VERSION 5.8 ;
BUSBITCHARS "[]" ;
DIVIDERCHAR "/" ;
UNITS
    DATABASE MICRONS 1000 ;
END UNITS

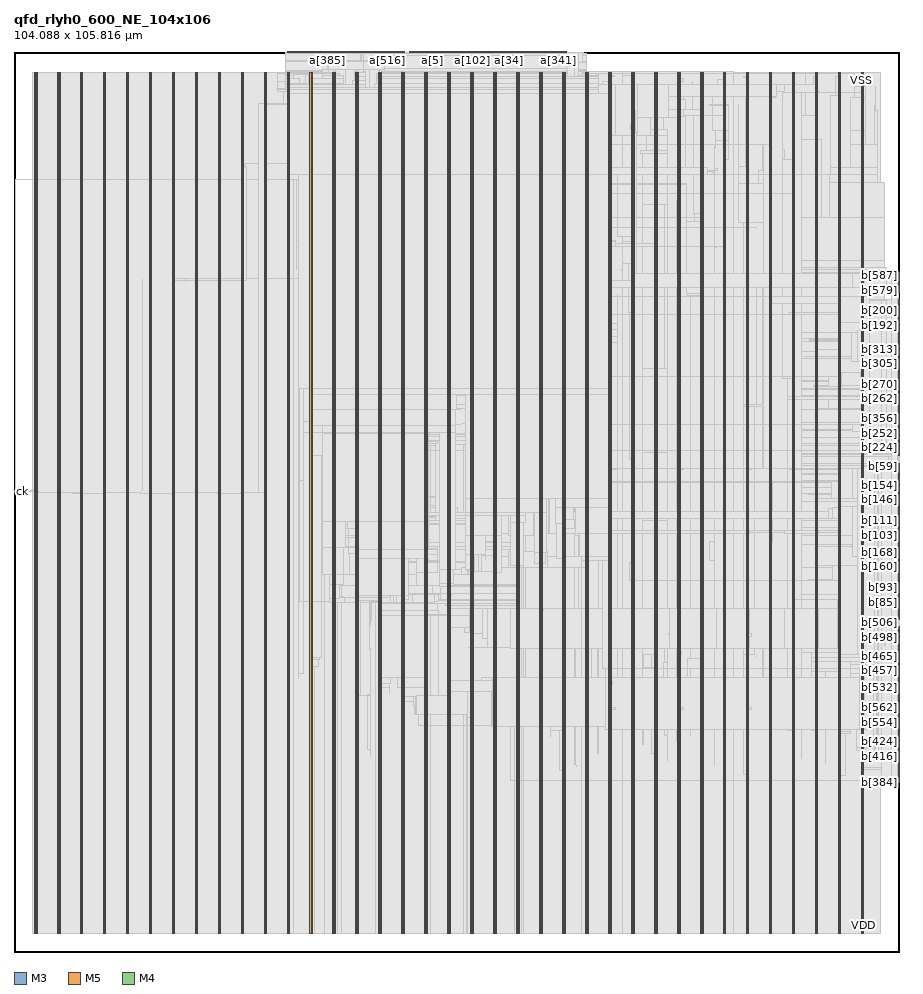
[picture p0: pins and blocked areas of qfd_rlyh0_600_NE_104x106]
MACRO qfd_rlyh0_600_NE_104x106
  FOREIGN qfd_rlyh0_600_NE_104x106 0 0 ;
  CLASS BLOCK ;
  SIZE 104.088 BY 105.816 ;
  PIN a[0]
    DIRECTION INPUT ;
    USE SIGNAL ;
    PORT
      LAYER M3 ;
        RECT  48.852 105.779 48.87 105.816 ;
    END
  END a[0]
  PIN a[100]
    DIRECTION INPUT ;
    USE SIGNAL ;
    PORT
      LAYER M3 ;
        RECT  53.748 105.779 53.766 105.816 ;
    END
  END a[100]
  PIN a[101]
    DIRECTION INPUT ;
    USE SIGNAL ;
    PORT
      LAYER M3 ;
        RECT  53.82 105.779 53.838 105.816 ;
    END
  END a[101]
  PIN a[102]
    DIRECTION INPUT ;
    USE SIGNAL ;
    PORT
      LAYER M3 ;
        RECT  53.892 105.779 53.91 105.816 ;
    END
  END a[102]
  PIN a[103]
    DIRECTION INPUT ;
    USE SIGNAL ;
    PORT
      LAYER M3 ;
        RECT  53.964 105.779 53.982 105.816 ;
    END
  END a[103]
  PIN a[104]
    DIRECTION INPUT ;
    USE SIGNAL ;
    PORT
      LAYER M3 ;
        RECT  54.036 105.779 54.054 105.816 ;
    END
  END a[104]
  PIN a[105]
    DIRECTION INPUT ;
    USE SIGNAL ;
    PORT
      LAYER M3 ;
        RECT  54.108 105.779 54.126 105.816 ;
    END
  END a[105]
  PIN a[106]
    DIRECTION INPUT ;
    USE SIGNAL ;
    PORT
      LAYER M3 ;
        RECT  54.18 105.779 54.198 105.816 ;
    END
  END a[106]
  PIN a[107]
    DIRECTION INPUT ;
    USE SIGNAL ;
    PORT
      LAYER M3 ;
        RECT  54.252 105.779 54.27 105.816 ;
    END
  END a[107]
  PIN a[108]
    DIRECTION INPUT ;
    USE SIGNAL ;
    PORT
      LAYER M3 ;
        RECT  54.324 105.779 54.342 105.816 ;
    END
  END a[108]
  PIN a[109]
    DIRECTION INPUT ;
    USE SIGNAL ;
    PORT
      LAYER M3 ;
        RECT  54.396 105.779 54.414 105.816 ;
    END
  END a[109]
  PIN a[10]
    DIRECTION INPUT ;
    USE SIGNAL ;
    PORT
      LAYER M3 ;
        RECT  49.572 105.779 49.59 105.816 ;
    END
  END a[10]
  PIN a[110]
    DIRECTION INPUT ;
    USE SIGNAL ;
    PORT
      LAYER M3 ;
        RECT  54.468 105.779 54.486 105.816 ;
    END
  END a[110]
  PIN a[111]
    DIRECTION INPUT ;
    USE SIGNAL ;
    PORT
      LAYER M3 ;
        RECT  54.54 105.779 54.558 105.816 ;
    END
  END a[111]
  PIN a[112]
    DIRECTION INPUT ;
    USE SIGNAL ;
    PORT
      LAYER M3 ;
        RECT  54.612 105.779 54.63 105.816 ;
    END
  END a[112]
  PIN a[113]
    DIRECTION INPUT ;
    USE SIGNAL ;
    PORT
      LAYER M3 ;
        RECT  54.684 105.779 54.702 105.816 ;
    END
  END a[113]
  PIN a[114]
    DIRECTION INPUT ;
    USE SIGNAL ;
    PORT
      LAYER M3 ;
        RECT  54.756 105.779 54.774 105.816 ;
    END
  END a[114]
  PIN a[115]
    DIRECTION INPUT ;
    USE SIGNAL ;
    PORT
      LAYER M3 ;
        RECT  54.828 105.779 54.846 105.816 ;
    END
  END a[115]
  PIN a[116]
    DIRECTION INPUT ;
    USE SIGNAL ;
    PORT
      LAYER M3 ;
        RECT  54.9 105.779 54.918 105.816 ;
    END
  END a[116]
  PIN a[117]
    DIRECTION INPUT ;
    USE SIGNAL ;
    PORT
      LAYER M3 ;
        RECT  54.972 105.779 54.99 105.816 ;
    END
  END a[117]
  PIN a[118]
    DIRECTION INPUT ;
    USE SIGNAL ;
    PORT
      LAYER M3 ;
        RECT  55.044 105.779 55.062 105.816 ;
    END
  END a[118]
  PIN a[119]
    DIRECTION INPUT ;
    USE SIGNAL ;
    PORT
      LAYER M3 ;
        RECT  55.116 105.779 55.134 105.816 ;
    END
  END a[119]
  PIN a[11]
    DIRECTION INPUT ;
    USE SIGNAL ;
    PORT
      LAYER M3 ;
        RECT  49.644 105.779 49.662 105.816 ;
    END
  END a[11]
  PIN a[120]
    DIRECTION INPUT ;
    USE SIGNAL ;
    PORT
      LAYER M3 ;
        RECT  55.188 105.779 55.206 105.816 ;
    END
  END a[120]
  PIN a[121]
    DIRECTION INPUT ;
    USE SIGNAL ;
    PORT
      LAYER M3 ;
        RECT  55.26 105.779 55.278 105.816 ;
    END
  END a[121]
  PIN a[122]
    DIRECTION INPUT ;
    USE SIGNAL ;
    PORT
      LAYER M3 ;
        RECT  55.332 105.779 55.35 105.816 ;
    END
  END a[122]
  PIN a[123]
    DIRECTION INPUT ;
    USE SIGNAL ;
    PORT
      LAYER M3 ;
        RECT  55.404 105.779 55.422 105.816 ;
    END
  END a[123]
  PIN a[124]
    DIRECTION INPUT ;
    USE SIGNAL ;
    PORT
      LAYER M3 ;
        RECT  55.476 105.779 55.494 105.816 ;
    END
  END a[124]
  PIN a[125]
    DIRECTION INPUT ;
    USE SIGNAL ;
    PORT
      LAYER M3 ;
        RECT  55.548 105.779 55.566 105.816 ;
    END
  END a[125]
  PIN a[126]
    DIRECTION INPUT ;
    USE SIGNAL ;
    PORT
      LAYER M3 ;
        RECT  55.62 105.779 55.638 105.816 ;
    END
  END a[126]
  PIN a[127]
    DIRECTION INPUT ;
    USE SIGNAL ;
    PORT
      LAYER M3 ;
        RECT  55.692 105.779 55.71 105.816 ;
    END
  END a[127]
  PIN a[128]
    DIRECTION INPUT ;
    USE SIGNAL ;
    PORT
      LAYER M3 ;
        RECT  55.764 105.779 55.782 105.816 ;
    END
  END a[128]
  PIN a[129]
    DIRECTION INPUT ;
    USE SIGNAL ;
    PORT
      LAYER M3 ;
        RECT  55.836 105.779 55.854 105.816 ;
    END
  END a[129]
  PIN a[12]
    DIRECTION INPUT ;
    USE SIGNAL ;
    PORT
      LAYER M3 ;
        RECT  49.716 105.779 49.734 105.816 ;
    END
  END a[12]
  PIN a[130]
    DIRECTION INPUT ;
    USE SIGNAL ;
    PORT
      LAYER M3 ;
        RECT  55.908 105.779 55.926 105.816 ;
    END
  END a[130]
  PIN a[131]
    DIRECTION INPUT ;
    USE SIGNAL ;
    PORT
      LAYER M3 ;
        RECT  55.98 105.779 55.998 105.816 ;
    END
  END a[131]
  PIN a[132]
    DIRECTION INPUT ;
    USE SIGNAL ;
    PORT
      LAYER M3 ;
        RECT  56.052 105.779 56.07 105.816 ;
    END
  END a[132]
  PIN a[133]
    DIRECTION INPUT ;
    USE SIGNAL ;
    PORT
      LAYER M3 ;
        RECT  56.124 105.779 56.142 105.816 ;
    END
  END a[133]
  PIN a[134]
    DIRECTION INPUT ;
    USE SIGNAL ;
    PORT
      LAYER M3 ;
        RECT  56.196 105.779 56.214 105.816 ;
    END
  END a[134]
  PIN a[135]
    DIRECTION INPUT ;
    USE SIGNAL ;
    PORT
      LAYER M3 ;
        RECT  56.268 105.779 56.286 105.816 ;
    END
  END a[135]
  PIN a[136]
    DIRECTION INPUT ;
    USE SIGNAL ;
    PORT
      LAYER M3 ;
        RECT  56.34 105.779 56.358 105.816 ;
    END
  END a[136]
  PIN a[137]
    DIRECTION INPUT ;
    USE SIGNAL ;
    PORT
      LAYER M3 ;
        RECT  56.412 105.779 56.43 105.816 ;
    END
  END a[137]
  PIN a[138]
    DIRECTION INPUT ;
    USE SIGNAL ;
    PORT
      LAYER M3 ;
        RECT  56.484 105.779 56.502 105.816 ;
    END
  END a[138]
  PIN a[139]
    DIRECTION INPUT ;
    USE SIGNAL ;
    PORT
      LAYER M3 ;
        RECT  56.556 105.779 56.574 105.816 ;
    END
  END a[139]
  PIN a[13]
    DIRECTION INPUT ;
    USE SIGNAL ;
    PORT
      LAYER M3 ;
        RECT  49.788 105.779 49.806 105.816 ;
    END
  END a[13]
  PIN a[140]
    DIRECTION INPUT ;
    USE SIGNAL ;
    PORT
      LAYER M3 ;
        RECT  56.628 105.779 56.646 105.816 ;
    END
  END a[140]
  PIN a[141]
    DIRECTION INPUT ;
    USE SIGNAL ;
    PORT
      LAYER M3 ;
        RECT  56.7 105.779 56.718 105.816 ;
    END
  END a[141]
  PIN a[142]
    DIRECTION INPUT ;
    USE SIGNAL ;
    PORT
      LAYER M3 ;
        RECT  56.772 105.779 56.79 105.816 ;
    END
  END a[142]
  PIN a[143]
    DIRECTION INPUT ;
    USE SIGNAL ;
    PORT
      LAYER M3 ;
        RECT  56.844 105.779 56.862 105.816 ;
    END
  END a[143]
  PIN a[144]
    DIRECTION INPUT ;
    USE SIGNAL ;
    PORT
      LAYER M3 ;
        RECT  56.916 105.779 56.934 105.816 ;
    END
  END a[144]
  PIN a[145]
    DIRECTION INPUT ;
    USE SIGNAL ;
    PORT
      LAYER M3 ;
        RECT  56.988 105.779 57.006 105.816 ;
    END
  END a[145]
  PIN a[146]
    DIRECTION INPUT ;
    USE SIGNAL ;
    PORT
      LAYER M3 ;
        RECT  57.06 105.779 57.078 105.816 ;
    END
  END a[146]
  PIN a[147]
    DIRECTION INPUT ;
    USE SIGNAL ;
    PORT
      LAYER M3 ;
        RECT  57.132 105.779 57.15 105.816 ;
    END
  END a[147]
  PIN a[148]
    DIRECTION INPUT ;
    USE SIGNAL ;
    PORT
      LAYER M3 ;
        RECT  57.204 105.779 57.222 105.816 ;
    END
  END a[148]
  PIN a[149]
    DIRECTION INPUT ;
    USE SIGNAL ;
    PORT
      LAYER M3 ;
        RECT  57.276 105.779 57.294 105.816 ;
    END
  END a[149]
  PIN a[14]
    DIRECTION INPUT ;
    USE SIGNAL ;
    PORT
      LAYER M3 ;
        RECT  49.86 105.779 49.878 105.816 ;
    END
  END a[14]
  PIN a[150]
    DIRECTION INPUT ;
    USE SIGNAL ;
    PORT
      LAYER M3 ;
        RECT  57.348 105.779 57.366 105.816 ;
    END
  END a[150]
  PIN a[151]
    DIRECTION INPUT ;
    USE SIGNAL ;
    PORT
      LAYER M3 ;
        RECT  57.42 105.779 57.438 105.816 ;
    END
  END a[151]
  PIN a[152]
    DIRECTION INPUT ;
    USE SIGNAL ;
    PORT
      LAYER M3 ;
        RECT  57.492 105.779 57.51 105.816 ;
    END
  END a[152]
  PIN a[153]
    DIRECTION INPUT ;
    USE SIGNAL ;
    PORT
      LAYER M3 ;
        RECT  57.564 105.779 57.582 105.816 ;
    END
  END a[153]
  PIN a[154]
    DIRECTION INPUT ;
    USE SIGNAL ;
    PORT
      LAYER M3 ;
        RECT  57.636 105.779 57.654 105.816 ;
    END
  END a[154]
  PIN a[155]
    DIRECTION INPUT ;
    USE SIGNAL ;
    PORT
      LAYER M3 ;
        RECT  57.708 105.779 57.726 105.816 ;
    END
  END a[155]
  PIN a[156]
    DIRECTION INPUT ;
    USE SIGNAL ;
    PORT
      LAYER M3 ;
        RECT  57.78 105.779 57.798 105.816 ;
    END
  END a[156]
  PIN a[157]
    DIRECTION INPUT ;
    USE SIGNAL ;
    PORT
      LAYER M3 ;
        RECT  57.852 105.779 57.87 105.816 ;
    END
  END a[157]
  PIN a[158]
    DIRECTION INPUT ;
    USE SIGNAL ;
    PORT
      LAYER M3 ;
        RECT  57.924 105.779 57.942 105.816 ;
    END
  END a[158]
  PIN a[159]
    DIRECTION INPUT ;
    USE SIGNAL ;
    PORT
      LAYER M3 ;
        RECT  57.996 105.779 58.014 105.816 ;
    END
  END a[159]
  PIN a[15]
    DIRECTION INPUT ;
    USE SIGNAL ;
    PORT
      LAYER M3 ;
        RECT  49.932 105.779 49.95 105.816 ;
    END
  END a[15]
  PIN a[160]
    DIRECTION INPUT ;
    USE SIGNAL ;
    PORT
      LAYER M3 ;
        RECT  51.156 105.779 51.174 105.816 ;
    END
  END a[160]
  PIN a[161]
    DIRECTION INPUT ;
    USE SIGNAL ;
    PORT
      LAYER M3 ;
        RECT  51.228 105.779 51.246 105.816 ;
    END
  END a[161]
  PIN a[162]
    DIRECTION INPUT ;
    USE SIGNAL ;
    PORT
      LAYER M3 ;
        RECT  51.3 105.779 51.318 105.816 ;
    END
  END a[162]
  PIN a[163]
    DIRECTION INPUT ;
    USE SIGNAL ;
    PORT
      LAYER M3 ;
        RECT  51.372 105.779 51.39 105.816 ;
    END
  END a[163]
  PIN a[164]
    DIRECTION INPUT ;
    USE SIGNAL ;
    PORT
      LAYER M3 ;
        RECT  51.444 105.779 51.462 105.816 ;
    END
  END a[164]
  PIN a[165]
    DIRECTION INPUT ;
    USE SIGNAL ;
    PORT
      LAYER M3 ;
        RECT  51.516 105.779 51.534 105.816 ;
    END
  END a[165]
  PIN a[166]
    DIRECTION INPUT ;
    USE SIGNAL ;
    PORT
      LAYER M3 ;
        RECT  51.588 105.779 51.606 105.816 ;
    END
  END a[166]
  PIN a[167]
    DIRECTION INPUT ;
    USE SIGNAL ;
    PORT
      LAYER M3 ;
        RECT  51.66 105.779 51.678 105.816 ;
    END
  END a[167]
  PIN a[168]
    DIRECTION INPUT ;
    USE SIGNAL ;
    PORT
      LAYER M3 ;
        RECT  51.732 105.779 51.75 105.816 ;
    END
  END a[168]
  PIN a[169]
    DIRECTION INPUT ;
    USE SIGNAL ;
    PORT
      LAYER M3 ;
        RECT  51.804 105.779 51.822 105.816 ;
    END
  END a[169]
  PIN a[16]
    DIRECTION INPUT ;
    USE SIGNAL ;
    PORT
      LAYER M3 ;
        RECT  50.004 105.779 50.022 105.816 ;
    END
  END a[16]
  PIN a[170]
    DIRECTION INPUT ;
    USE SIGNAL ;
    PORT
      LAYER M3 ;
        RECT  51.876 105.779 51.894 105.816 ;
    END
  END a[170]
  PIN a[171]
    DIRECTION INPUT ;
    USE SIGNAL ;
    PORT
      LAYER M3 ;
        RECT  51.948 105.779 51.966 105.816 ;
    END
  END a[171]
  PIN a[172]
    DIRECTION INPUT ;
    USE SIGNAL ;
    PORT
      LAYER M3 ;
        RECT  52.02 105.779 52.038 105.816 ;
    END
  END a[172]
  PIN a[173]
    DIRECTION INPUT ;
    USE SIGNAL ;
    PORT
      LAYER M3 ;
        RECT  52.092 105.779 52.11 105.816 ;
    END
  END a[173]
  PIN a[174]
    DIRECTION INPUT ;
    USE SIGNAL ;
    PORT
      LAYER M3 ;
        RECT  52.164 105.779 52.182 105.816 ;
    END
  END a[174]
  PIN a[175]
    DIRECTION INPUT ;
    USE SIGNAL ;
    PORT
      LAYER M3 ;
        RECT  52.236 105.779 52.254 105.816 ;
    END
  END a[175]
  PIN a[176]
    DIRECTION INPUT ;
    USE SIGNAL ;
    PORT
      LAYER M3 ;
        RECT  52.308 105.779 52.326 105.816 ;
    END
  END a[176]
  PIN a[177]
    DIRECTION INPUT ;
    USE SIGNAL ;
    PORT
      LAYER M3 ;
        RECT  52.38 105.779 52.398 105.816 ;
    END
  END a[177]
  PIN a[178]
    DIRECTION INPUT ;
    USE SIGNAL ;
    PORT
      LAYER M3 ;
        RECT  52.452 105.779 52.47 105.816 ;
    END
  END a[178]
  PIN a[179]
    DIRECTION INPUT ;
    USE SIGNAL ;
    PORT
      LAYER M3 ;
        RECT  52.524 105.779 52.542 105.816 ;
    END
  END a[179]
  PIN a[17]
    DIRECTION INPUT ;
    USE SIGNAL ;
    PORT
      LAYER M3 ;
        RECT  50.076 105.779 50.094 105.816 ;
    END
  END a[17]
  PIN a[180]
    DIRECTION INPUT ;
    USE SIGNAL ;
    PORT
      LAYER M3 ;
        RECT  52.596 105.779 52.614 105.816 ;
    END
  END a[180]
  PIN a[181]
    DIRECTION INPUT ;
    USE SIGNAL ;
    PORT
      LAYER M3 ;
        RECT  52.668 105.779 52.686 105.816 ;
    END
  END a[181]
  PIN a[182]
    DIRECTION INPUT ;
    USE SIGNAL ;
    PORT
      LAYER M3 ;
        RECT  52.74 105.779 52.758 105.816 ;
    END
  END a[182]
  PIN a[183]
    DIRECTION INPUT ;
    USE SIGNAL ;
    PORT
      LAYER M3 ;
        RECT  52.812 105.779 52.83 105.816 ;
    END
  END a[183]
  PIN a[184]
    DIRECTION INPUT ;
    USE SIGNAL ;
    PORT
      LAYER M3 ;
        RECT  52.884 105.779 52.902 105.816 ;
    END
  END a[184]
  PIN a[185]
    DIRECTION INPUT ;
    USE SIGNAL ;
    PORT
      LAYER M3 ;
        RECT  52.956 105.779 52.974 105.816 ;
    END
  END a[185]
  PIN a[186]
    DIRECTION INPUT ;
    USE SIGNAL ;
    PORT
      LAYER M3 ;
        RECT  53.028 105.779 53.046 105.816 ;
    END
  END a[186]
  PIN a[187]
    DIRECTION INPUT ;
    USE SIGNAL ;
    PORT
      LAYER M3 ;
        RECT  53.1 105.779 53.118 105.816 ;
    END
  END a[187]
  PIN a[188]
    DIRECTION INPUT ;
    USE SIGNAL ;
    PORT
      LAYER M3 ;
        RECT  53.172 105.779 53.19 105.816 ;
    END
  END a[188]
  PIN a[189]
    DIRECTION INPUT ;
    USE SIGNAL ;
    PORT
      LAYER M3 ;
        RECT  53.244 105.779 53.262 105.816 ;
    END
  END a[189]
  PIN a[18]
    DIRECTION INPUT ;
    USE SIGNAL ;
    PORT
      LAYER M3 ;
        RECT  50.148 105.779 50.166 105.816 ;
    END
  END a[18]
  PIN a[190]
    DIRECTION INPUT ;
    USE SIGNAL ;
    PORT
      LAYER M3 ;
        RECT  53.316 105.779 53.334 105.816 ;
    END
  END a[190]
  PIN a[191]
    DIRECTION INPUT ;
    USE SIGNAL ;
    PORT
      LAYER M3 ;
        RECT  53.388 105.779 53.406 105.816 ;
    END
  END a[191]
  PIN a[192]
    DIRECTION INPUT ;
    USE SIGNAL ;
    PORT
      LAYER M5 ;
        RECT  52.752 105.732 52.776 105.816 ;
    END
  END a[192]
  PIN a[193]
    DIRECTION INPUT ;
    USE SIGNAL ;
    PORT
      LAYER M5 ;
        RECT  52.848 105.732 52.872 105.816 ;
    END
  END a[193]
  PIN a[194]
    DIRECTION INPUT ;
    USE SIGNAL ;
    PORT
      LAYER M5 ;
        RECT  52.944 105.732 52.968 105.816 ;
    END
  END a[194]
  PIN a[195]
    DIRECTION INPUT ;
    USE SIGNAL ;
    PORT
      LAYER M5 ;
        RECT  53.04 105.732 53.064 105.816 ;
    END
  END a[195]
  PIN a[196]
    DIRECTION INPUT ;
    USE SIGNAL ;
    PORT
      LAYER M5 ;
        RECT  53.136 105.732 53.16 105.816 ;
    END
  END a[196]
  PIN a[197]
    DIRECTION INPUT ;
    USE SIGNAL ;
    PORT
      LAYER M5 ;
        RECT  53.232 105.732 53.256 105.816 ;
    END
  END a[197]
  PIN a[198]
    DIRECTION INPUT ;
    USE SIGNAL ;
    PORT
      LAYER M5 ;
        RECT  53.328 105.732 53.352 105.816 ;
    END
  END a[198]
  PIN a[199]
    DIRECTION INPUT ;
    USE SIGNAL ;
    PORT
      LAYER M5 ;
        RECT  53.424 105.732 53.448 105.816 ;
    END
  END a[199]
  PIN a[19]
    DIRECTION INPUT ;
    USE SIGNAL ;
    PORT
      LAYER M3 ;
        RECT  50.22 105.779 50.238 105.816 ;
    END
  END a[19]
  PIN a[1]
    DIRECTION INPUT ;
    USE SIGNAL ;
    PORT
      LAYER M3 ;
        RECT  48.924 105.779 48.942 105.816 ;
    END
  END a[1]
  PIN a[200]
    DIRECTION INPUT ;
    USE SIGNAL ;
    PORT
      LAYER M5 ;
        RECT  53.52 105.732 53.544 105.816 ;
    END
  END a[200]
  PIN a[201]
    DIRECTION INPUT ;
    USE SIGNAL ;
    PORT
      LAYER M5 ;
        RECT  53.616 105.732 53.64 105.816 ;
    END
  END a[201]
  PIN a[202]
    DIRECTION INPUT ;
    USE SIGNAL ;
    PORT
      LAYER M5 ;
        RECT  53.712 105.732 53.736 105.816 ;
    END
  END a[202]
  PIN a[203]
    DIRECTION INPUT ;
    USE SIGNAL ;
    PORT
      LAYER M5 ;
        RECT  53.808 105.732 53.832 105.816 ;
    END
  END a[203]
  PIN a[204]
    DIRECTION INPUT ;
    USE SIGNAL ;
    PORT
      LAYER M5 ;
        RECT  53.904 105.732 53.928 105.816 ;
    END
  END a[204]
  PIN a[205]
    DIRECTION INPUT ;
    USE SIGNAL ;
    PORT
      LAYER M5 ;
        RECT  54 105.732 54.024 105.816 ;
    END
  END a[205]
  PIN a[206]
    DIRECTION INPUT ;
    USE SIGNAL ;
    PORT
      LAYER M5 ;
        RECT  54.096 105.732 54.12 105.816 ;
    END
  END a[206]
  PIN a[207]
    DIRECTION INPUT ;
    USE SIGNAL ;
    PORT
      LAYER M5 ;
        RECT  54.192 105.732 54.216 105.816 ;
    END
  END a[207]
  PIN a[208]
    DIRECTION INPUT ;
    USE SIGNAL ;
    PORT
      LAYER M5 ;
        RECT  54.288 105.732 54.312 105.816 ;
    END
  END a[208]
  PIN a[209]
    DIRECTION INPUT ;
    USE SIGNAL ;
    PORT
      LAYER M5 ;
        RECT  54.384 105.732 54.408 105.816 ;
    END
  END a[209]
  PIN a[20]
    DIRECTION INPUT ;
    USE SIGNAL ;
    PORT
      LAYER M3 ;
        RECT  50.292 105.779 50.31 105.816 ;
    END
  END a[20]
  PIN a[210]
    DIRECTION INPUT ;
    USE SIGNAL ;
    PORT
      LAYER M5 ;
        RECT  54.48 105.732 54.504 105.816 ;
    END
  END a[210]
  PIN a[211]
    DIRECTION INPUT ;
    USE SIGNAL ;
    PORT
      LAYER M5 ;
        RECT  54.576 105.732 54.6 105.816 ;
    END
  END a[211]
  PIN a[212]
    DIRECTION INPUT ;
    USE SIGNAL ;
    PORT
      LAYER M5 ;
        RECT  54.672 105.732 54.696 105.816 ;
    END
  END a[212]
  PIN a[213]
    DIRECTION INPUT ;
    USE SIGNAL ;
    PORT
      LAYER M5 ;
        RECT  54.768 105.732 54.792 105.816 ;
    END
  END a[213]
  PIN a[214]
    DIRECTION INPUT ;
    USE SIGNAL ;
    PORT
      LAYER M5 ;
        RECT  54.864 105.732 54.888 105.816 ;
    END
  END a[214]
  PIN a[215]
    DIRECTION INPUT ;
    USE SIGNAL ;
    PORT
      LAYER M5 ;
        RECT  54.96 105.732 54.984 105.816 ;
    END
  END a[215]
  PIN a[216]
    DIRECTION INPUT ;
    USE SIGNAL ;
    PORT
      LAYER M5 ;
        RECT  55.056 105.732 55.08 105.816 ;
    END
  END a[216]
  PIN a[217]
    DIRECTION INPUT ;
    USE SIGNAL ;
    PORT
      LAYER M5 ;
        RECT  55.152 105.732 55.176 105.816 ;
    END
  END a[217]
  PIN a[218]
    DIRECTION INPUT ;
    USE SIGNAL ;
    PORT
      LAYER M5 ;
        RECT  55.248 105.732 55.272 105.816 ;
    END
  END a[218]
  PIN a[219]
    DIRECTION INPUT ;
    USE SIGNAL ;
    PORT
      LAYER M5 ;
        RECT  55.344 105.732 55.368 105.816 ;
    END
  END a[219]
  PIN a[21]
    DIRECTION INPUT ;
    USE SIGNAL ;
    PORT
      LAYER M3 ;
        RECT  50.364 105.779 50.382 105.816 ;
    END
  END a[21]
  PIN a[220]
    DIRECTION INPUT ;
    USE SIGNAL ;
    PORT
      LAYER M5 ;
        RECT  55.44 105.732 55.464 105.816 ;
    END
  END a[220]
  PIN a[221]
    DIRECTION INPUT ;
    USE SIGNAL ;
    PORT
      LAYER M5 ;
        RECT  55.536 105.732 55.56 105.816 ;
    END
  END a[221]
  PIN a[222]
    DIRECTION INPUT ;
    USE SIGNAL ;
    PORT
      LAYER M5 ;
        RECT  55.632 105.732 55.656 105.816 ;
    END
  END a[222]
  PIN a[223]
    DIRECTION INPUT ;
    USE SIGNAL ;
    PORT
      LAYER M5 ;
        RECT  55.728 105.732 55.752 105.816 ;
    END
  END a[223]
  PIN a[224]
    DIRECTION INPUT ;
    USE SIGNAL ;
    PORT
      LAYER M5 ;
        RECT  46.608 105.732 46.632 105.816 ;
    END
  END a[224]
  PIN a[225]
    DIRECTION INPUT ;
    USE SIGNAL ;
    PORT
      LAYER M5 ;
        RECT  46.704 105.732 46.728 105.816 ;
    END
  END a[225]
  PIN a[226]
    DIRECTION INPUT ;
    USE SIGNAL ;
    PORT
      LAYER M5 ;
        RECT  46.8 105.732 46.824 105.816 ;
    END
  END a[226]
  PIN a[227]
    DIRECTION INPUT ;
    USE SIGNAL ;
    PORT
      LAYER M5 ;
        RECT  46.896 105.732 46.92 105.816 ;
    END
  END a[227]
  PIN a[228]
    DIRECTION INPUT ;
    USE SIGNAL ;
    PORT
      LAYER M5 ;
        RECT  46.992 105.732 47.016 105.816 ;
    END
  END a[228]
  PIN a[229]
    DIRECTION INPUT ;
    USE SIGNAL ;
    PORT
      LAYER M5 ;
        RECT  47.088 105.732 47.112 105.816 ;
    END
  END a[229]
  PIN a[22]
    DIRECTION INPUT ;
    USE SIGNAL ;
    PORT
      LAYER M3 ;
        RECT  50.436 105.779 50.454 105.816 ;
    END
  END a[22]
  PIN a[230]
    DIRECTION INPUT ;
    USE SIGNAL ;
    PORT
      LAYER M5 ;
        RECT  47.184 105.732 47.208 105.816 ;
    END
  END a[230]
  PIN a[231]
    DIRECTION INPUT ;
    USE SIGNAL ;
    PORT
      LAYER M5 ;
        RECT  47.28 105.732 47.304 105.816 ;
    END
  END a[231]
  PIN a[232]
    DIRECTION INPUT ;
    USE SIGNAL ;
    PORT
      LAYER M5 ;
        RECT  47.376 105.732 47.4 105.816 ;
    END
  END a[232]
  PIN a[233]
    DIRECTION INPUT ;
    USE SIGNAL ;
    PORT
      LAYER M5 ;
        RECT  47.472 105.732 47.496 105.816 ;
    END
  END a[233]
  PIN a[234]
    DIRECTION INPUT ;
    USE SIGNAL ;
    PORT
      LAYER M5 ;
        RECT  47.568 105.732 47.592 105.816 ;
    END
  END a[234]
  PIN a[235]
    DIRECTION INPUT ;
    USE SIGNAL ;
    PORT
      LAYER M5 ;
        RECT  47.664 105.732 47.688 105.816 ;
    END
  END a[235]
  PIN a[236]
    DIRECTION INPUT ;
    USE SIGNAL ;
    PORT
      LAYER M5 ;
        RECT  47.76 105.732 47.784 105.816 ;
    END
  END a[236]
  PIN a[237]
    DIRECTION INPUT ;
    USE SIGNAL ;
    PORT
      LAYER M5 ;
        RECT  47.856 105.732 47.88 105.816 ;
    END
  END a[237]
  PIN a[238]
    DIRECTION INPUT ;
    USE SIGNAL ;
    PORT
      LAYER M5 ;
        RECT  47.952 105.732 47.976 105.816 ;
    END
  END a[238]
  PIN a[239]
    DIRECTION INPUT ;
    USE SIGNAL ;
    PORT
      LAYER M5 ;
        RECT  48.048 105.732 48.072 105.816 ;
    END
  END a[239]
  PIN a[23]
    DIRECTION INPUT ;
    USE SIGNAL ;
    PORT
      LAYER M3 ;
        RECT  50.508 105.779 50.526 105.816 ;
    END
  END a[23]
  PIN a[240]
    DIRECTION INPUT ;
    USE SIGNAL ;
    PORT
      LAYER M5 ;
        RECT  48.144 105.732 48.168 105.816 ;
    END
  END a[240]
  PIN a[241]
    DIRECTION INPUT ;
    USE SIGNAL ;
    PORT
      LAYER M5 ;
        RECT  48.24 105.732 48.264 105.816 ;
    END
  END a[241]
  PIN a[242]
    DIRECTION INPUT ;
    USE SIGNAL ;
    PORT
      LAYER M5 ;
        RECT  48.336 105.732 48.36 105.816 ;
    END
  END a[242]
  PIN a[243]
    DIRECTION INPUT ;
    USE SIGNAL ;
    PORT
      LAYER M5 ;
        RECT  48.432 105.732 48.456 105.816 ;
    END
  END a[243]
  PIN a[244]
    DIRECTION INPUT ;
    USE SIGNAL ;
    PORT
      LAYER M5 ;
        RECT  48.528 105.732 48.552 105.816 ;
    END
  END a[244]
  PIN a[245]
    DIRECTION INPUT ;
    USE SIGNAL ;
    PORT
      LAYER M5 ;
        RECT  48.624 105.732 48.648 105.816 ;
    END
  END a[245]
  PIN a[246]
    DIRECTION INPUT ;
    USE SIGNAL ;
    PORT
      LAYER M5 ;
        RECT  48.72 105.732 48.744 105.816 ;
    END
  END a[246]
  PIN a[247]
    DIRECTION INPUT ;
    USE SIGNAL ;
    PORT
      LAYER M5 ;
        RECT  48.816 105.732 48.84 105.816 ;
    END
  END a[247]
  PIN a[248]
    DIRECTION INPUT ;
    USE SIGNAL ;
    PORT
      LAYER M5 ;
        RECT  48.912 105.732 48.936 105.816 ;
    END
  END a[248]
  PIN a[249]
    DIRECTION INPUT ;
    USE SIGNAL ;
    PORT
      LAYER M5 ;
        RECT  49.008 105.732 49.032 105.816 ;
    END
  END a[249]
  PIN a[24]
    DIRECTION INPUT ;
    USE SIGNAL ;
    PORT
      LAYER M3 ;
        RECT  50.58 105.779 50.598 105.816 ;
    END
  END a[24]
  PIN a[250]
    DIRECTION INPUT ;
    USE SIGNAL ;
    PORT
      LAYER M5 ;
        RECT  49.104 105.732 49.128 105.816 ;
    END
  END a[250]
  PIN a[251]
    DIRECTION INPUT ;
    USE SIGNAL ;
    PORT
      LAYER M5 ;
        RECT  49.2 105.732 49.224 105.816 ;
    END
  END a[251]
  PIN a[252]
    DIRECTION INPUT ;
    USE SIGNAL ;
    PORT
      LAYER M5 ;
        RECT  49.296 105.732 49.32 105.816 ;
    END
  END a[252]
  PIN a[253]
    DIRECTION INPUT ;
    USE SIGNAL ;
    PORT
      LAYER M5 ;
        RECT  49.392 105.732 49.416 105.816 ;
    END
  END a[253]
  PIN a[254]
    DIRECTION INPUT ;
    USE SIGNAL ;
    PORT
      LAYER M5 ;
        RECT  49.488 105.732 49.512 105.816 ;
    END
  END a[254]
  PIN a[255]
    DIRECTION INPUT ;
    USE SIGNAL ;
    PORT
      LAYER M5 ;
        RECT  49.584 105.732 49.608 105.816 ;
    END
  END a[255]
  PIN a[256]
    DIRECTION INPUT ;
    USE SIGNAL ;
    PORT
      LAYER M5 ;
        RECT  58.896 105.732 58.92 105.816 ;
    END
  END a[256]
  PIN a[257]
    DIRECTION INPUT ;
    USE SIGNAL ;
    PORT
      LAYER M5 ;
        RECT  58.992 105.732 59.016 105.816 ;
    END
  END a[257]
  PIN a[258]
    DIRECTION INPUT ;
    USE SIGNAL ;
    PORT
      LAYER M5 ;
        RECT  59.088 105.732 59.112 105.816 ;
    END
  END a[258]
  PIN a[259]
    DIRECTION INPUT ;
    USE SIGNAL ;
    PORT
      LAYER M5 ;
        RECT  59.184 105.732 59.208 105.816 ;
    END
  END a[259]
  PIN a[25]
    DIRECTION INPUT ;
    USE SIGNAL ;
    PORT
      LAYER M3 ;
        RECT  50.652 105.779 50.67 105.816 ;
    END
  END a[25]
  PIN a[260]
    DIRECTION INPUT ;
    USE SIGNAL ;
    PORT
      LAYER M5 ;
        RECT  59.28 105.732 59.304 105.816 ;
    END
  END a[260]
  PIN a[261]
    DIRECTION INPUT ;
    USE SIGNAL ;
    PORT
      LAYER M5 ;
        RECT  59.376 105.732 59.4 105.816 ;
    END
  END a[261]
  PIN a[262]
    DIRECTION INPUT ;
    USE SIGNAL ;
    PORT
      LAYER M5 ;
        RECT  59.472 105.732 59.496 105.816 ;
    END
  END a[262]
  PIN a[263]
    DIRECTION INPUT ;
    USE SIGNAL ;
    PORT
      LAYER M5 ;
        RECT  59.568 105.732 59.592 105.816 ;
    END
  END a[263]
  PIN a[264]
    DIRECTION INPUT ;
    USE SIGNAL ;
    PORT
      LAYER M5 ;
        RECT  59.664 105.732 59.688 105.816 ;
    END
  END a[264]
  PIN a[265]
    DIRECTION INPUT ;
    USE SIGNAL ;
    PORT
      LAYER M5 ;
        RECT  59.76 105.732 59.784 105.816 ;
    END
  END a[265]
  PIN a[266]
    DIRECTION INPUT ;
    USE SIGNAL ;
    PORT
      LAYER M5 ;
        RECT  59.856 105.732 59.88 105.816 ;
    END
  END a[266]
  PIN a[267]
    DIRECTION INPUT ;
    USE SIGNAL ;
    PORT
      LAYER M5 ;
        RECT  59.952 105.732 59.976 105.816 ;
    END
  END a[267]
  PIN a[268]
    DIRECTION INPUT ;
    USE SIGNAL ;
    PORT
      LAYER M5 ;
        RECT  60.048 105.732 60.072 105.816 ;
    END
  END a[268]
  PIN a[269]
    DIRECTION INPUT ;
    USE SIGNAL ;
    PORT
      LAYER M5 ;
        RECT  60.144 105.732 60.168 105.816 ;
    END
  END a[269]
  PIN a[26]
    DIRECTION INPUT ;
    USE SIGNAL ;
    PORT
      LAYER M3 ;
        RECT  50.724 105.779 50.742 105.816 ;
    END
  END a[26]
  PIN a[270]
    DIRECTION INPUT ;
    USE SIGNAL ;
    PORT
      LAYER M5 ;
        RECT  60.24 105.732 60.264 105.816 ;
    END
  END a[270]
  PIN a[271]
    DIRECTION INPUT ;
    USE SIGNAL ;
    PORT
      LAYER M5 ;
        RECT  60.336 105.732 60.36 105.816 ;
    END
  END a[271]
  PIN a[272]
    DIRECTION INPUT ;
    USE SIGNAL ;
    PORT
      LAYER M5 ;
        RECT  60.432 105.732 60.456 105.816 ;
    END
  END a[272]
  PIN a[273]
    DIRECTION INPUT ;
    USE SIGNAL ;
    PORT
      LAYER M5 ;
        RECT  60.528 105.732 60.552 105.816 ;
    END
  END a[273]
  PIN a[274]
    DIRECTION INPUT ;
    USE SIGNAL ;
    PORT
      LAYER M5 ;
        RECT  60.624 105.732 60.648 105.816 ;
    END
  END a[274]
  PIN a[275]
    DIRECTION INPUT ;
    USE SIGNAL ;
    PORT
      LAYER M5 ;
        RECT  60.72 105.732 60.744 105.816 ;
    END
  END a[275]
  PIN a[276]
    DIRECTION INPUT ;
    USE SIGNAL ;
    PORT
      LAYER M5 ;
        RECT  60.816 105.732 60.84 105.816 ;
    END
  END a[276]
  PIN a[277]
    DIRECTION INPUT ;
    USE SIGNAL ;
    PORT
      LAYER M5 ;
        RECT  60.912 105.732 60.936 105.816 ;
    END
  END a[277]
  PIN a[278]
    DIRECTION INPUT ;
    USE SIGNAL ;
    PORT
      LAYER M5 ;
        RECT  61.008 105.732 61.032 105.816 ;
    END
  END a[278]
  PIN a[279]
    DIRECTION INPUT ;
    USE SIGNAL ;
    PORT
      LAYER M5 ;
        RECT  61.104 105.732 61.128 105.816 ;
    END
  END a[279]
  PIN a[27]
    DIRECTION INPUT ;
    USE SIGNAL ;
    PORT
      LAYER M3 ;
        RECT  50.796 105.779 50.814 105.816 ;
    END
  END a[27]
  PIN a[280]
    DIRECTION INPUT ;
    USE SIGNAL ;
    PORT
      LAYER M5 ;
        RECT  61.2 105.732 61.224 105.816 ;
    END
  END a[280]
  PIN a[281]
    DIRECTION INPUT ;
    USE SIGNAL ;
    PORT
      LAYER M5 ;
        RECT  61.296 105.732 61.32 105.816 ;
    END
  END a[281]
  PIN a[282]
    DIRECTION INPUT ;
    USE SIGNAL ;
    PORT
      LAYER M5 ;
        RECT  61.392 105.732 61.416 105.816 ;
    END
  END a[282]
  PIN a[283]
    DIRECTION INPUT ;
    USE SIGNAL ;
    PORT
      LAYER M5 ;
        RECT  61.488 105.732 61.512 105.816 ;
    END
  END a[283]
  PIN a[284]
    DIRECTION INPUT ;
    USE SIGNAL ;
    PORT
      LAYER M5 ;
        RECT  61.584 105.732 61.608 105.816 ;
    END
  END a[284]
  PIN a[285]
    DIRECTION INPUT ;
    USE SIGNAL ;
    PORT
      LAYER M5 ;
        RECT  61.68 105.732 61.704 105.816 ;
    END
  END a[285]
  PIN a[286]
    DIRECTION INPUT ;
    USE SIGNAL ;
    PORT
      LAYER M5 ;
        RECT  61.776 105.732 61.8 105.816 ;
    END
  END a[286]
  PIN a[287]
    DIRECTION INPUT ;
    USE SIGNAL ;
    PORT
      LAYER M5 ;
        RECT  61.872 105.732 61.896 105.816 ;
    END
  END a[287]
  PIN a[288]
    DIRECTION INPUT ;
    USE SIGNAL ;
    PORT
      LAYER M5 ;
        RECT  55.824 105.732 55.848 105.816 ;
    END
  END a[288]
  PIN a[289]
    DIRECTION INPUT ;
    USE SIGNAL ;
    PORT
      LAYER M5 ;
        RECT  55.92 105.732 55.944 105.816 ;
    END
  END a[289]
  PIN a[28]
    DIRECTION INPUT ;
    USE SIGNAL ;
    PORT
      LAYER M3 ;
        RECT  50.868 105.779 50.886 105.816 ;
    END
  END a[28]
  PIN a[290]
    DIRECTION INPUT ;
    USE SIGNAL ;
    PORT
      LAYER M5 ;
        RECT  56.016 105.732 56.04 105.816 ;
    END
  END a[290]
  PIN a[291]
    DIRECTION INPUT ;
    USE SIGNAL ;
    PORT
      LAYER M5 ;
        RECT  56.112 105.732 56.136 105.816 ;
    END
  END a[291]
  PIN a[292]
    DIRECTION INPUT ;
    USE SIGNAL ;
    PORT
      LAYER M5 ;
        RECT  56.208 105.732 56.232 105.816 ;
    END
  END a[292]
  PIN a[293]
    DIRECTION INPUT ;
    USE SIGNAL ;
    PORT
      LAYER M5 ;
        RECT  56.304 105.732 56.328 105.816 ;
    END
  END a[293]
  PIN a[294]
    DIRECTION INPUT ;
    USE SIGNAL ;
    PORT
      LAYER M5 ;
        RECT  56.4 105.732 56.424 105.816 ;
    END
  END a[294]
  PIN a[295]
    DIRECTION INPUT ;
    USE SIGNAL ;
    PORT
      LAYER M5 ;
        RECT  56.496 105.732 56.52 105.816 ;
    END
  END a[295]
  PIN a[296]
    DIRECTION INPUT ;
    USE SIGNAL ;
    PORT
      LAYER M5 ;
        RECT  56.592 105.732 56.616 105.816 ;
    END
  END a[296]
  PIN a[297]
    DIRECTION INPUT ;
    USE SIGNAL ;
    PORT
      LAYER M5 ;
        RECT  56.688 105.732 56.712 105.816 ;
    END
  END a[297]
  PIN a[298]
    DIRECTION INPUT ;
    USE SIGNAL ;
    PORT
      LAYER M5 ;
        RECT  56.784 105.732 56.808 105.816 ;
    END
  END a[298]
  PIN a[299]
    DIRECTION INPUT ;
    USE SIGNAL ;
    PORT
      LAYER M5 ;
        RECT  56.88 105.732 56.904 105.816 ;
    END
  END a[299]
  PIN a[29]
    DIRECTION INPUT ;
    USE SIGNAL ;
    PORT
      LAYER M3 ;
        RECT  50.94 105.779 50.958 105.816 ;
    END
  END a[29]
  PIN a[2]
    DIRECTION INPUT ;
    USE SIGNAL ;
    PORT
      LAYER M3 ;
        RECT  48.996 105.779 49.014 105.816 ;
    END
  END a[2]
  PIN a[300]
    DIRECTION INPUT ;
    USE SIGNAL ;
    PORT
      LAYER M5 ;
        RECT  56.976 105.732 57 105.816 ;
    END
  END a[300]
  PIN a[301]
    DIRECTION INPUT ;
    USE SIGNAL ;
    PORT
      LAYER M5 ;
        RECT  57.072 105.732 57.096 105.816 ;
    END
  END a[301]
  PIN a[302]
    DIRECTION INPUT ;
    USE SIGNAL ;
    PORT
      LAYER M5 ;
        RECT  57.168 105.732 57.192 105.816 ;
    END
  END a[302]
  PIN a[303]
    DIRECTION INPUT ;
    USE SIGNAL ;
    PORT
      LAYER M5 ;
        RECT  57.264 105.732 57.288 105.816 ;
    END
  END a[303]
  PIN a[304]
    DIRECTION INPUT ;
    USE SIGNAL ;
    PORT
      LAYER M5 ;
        RECT  57.36 105.732 57.384 105.816 ;
    END
  END a[304]
  PIN a[305]
    DIRECTION INPUT ;
    USE SIGNAL ;
    PORT
      LAYER M5 ;
        RECT  57.456 105.732 57.48 105.816 ;
    END
  END a[305]
  PIN a[306]
    DIRECTION INPUT ;
    USE SIGNAL ;
    PORT
      LAYER M5 ;
        RECT  57.552 105.732 57.576 105.816 ;
    END
  END a[306]
  PIN a[307]
    DIRECTION INPUT ;
    USE SIGNAL ;
    PORT
      LAYER M5 ;
        RECT  57.648 105.732 57.672 105.816 ;
    END
  END a[307]
  PIN a[308]
    DIRECTION INPUT ;
    USE SIGNAL ;
    PORT
      LAYER M5 ;
        RECT  57.744 105.732 57.768 105.816 ;
    END
  END a[308]
  PIN a[309]
    DIRECTION INPUT ;
    USE SIGNAL ;
    PORT
      LAYER M5 ;
        RECT  57.84 105.732 57.864 105.816 ;
    END
  END a[309]
  PIN a[30]
    DIRECTION INPUT ;
    USE SIGNAL ;
    PORT
      LAYER M3 ;
        RECT  51.012 105.779 51.03 105.816 ;
    END
  END a[30]
  PIN a[310]
    DIRECTION INPUT ;
    USE SIGNAL ;
    PORT
      LAYER M5 ;
        RECT  57.936 105.732 57.96 105.816 ;
    END
  END a[310]
  PIN a[311]
    DIRECTION INPUT ;
    USE SIGNAL ;
    PORT
      LAYER M5 ;
        RECT  58.032 105.732 58.056 105.816 ;
    END
  END a[311]
  PIN a[312]
    DIRECTION INPUT ;
    USE SIGNAL ;
    PORT
      LAYER M5 ;
        RECT  58.128 105.732 58.152 105.816 ;
    END
  END a[312]
  PIN a[313]
    DIRECTION INPUT ;
    USE SIGNAL ;
    PORT
      LAYER M5 ;
        RECT  58.224 105.732 58.248 105.816 ;
    END
  END a[313]
  PIN a[314]
    DIRECTION INPUT ;
    USE SIGNAL ;
    PORT
      LAYER M5 ;
        RECT  58.32 105.732 58.344 105.816 ;
    END
  END a[314]
  PIN a[315]
    DIRECTION INPUT ;
    USE SIGNAL ;
    PORT
      LAYER M5 ;
        RECT  58.416 105.732 58.44 105.816 ;
    END
  END a[315]
  PIN a[316]
    DIRECTION INPUT ;
    USE SIGNAL ;
    PORT
      LAYER M5 ;
        RECT  58.512 105.732 58.536 105.816 ;
    END
  END a[316]
  PIN a[317]
    DIRECTION INPUT ;
    USE SIGNAL ;
    PORT
      LAYER M5 ;
        RECT  58.608 105.732 58.632 105.816 ;
    END
  END a[317]
  PIN a[318]
    DIRECTION INPUT ;
    USE SIGNAL ;
    PORT
      LAYER M5 ;
        RECT  58.704 105.732 58.728 105.816 ;
    END
  END a[318]
  PIN a[319]
    DIRECTION INPUT ;
    USE SIGNAL ;
    PORT
      LAYER M5 ;
        RECT  58.8 105.732 58.824 105.816 ;
    END
  END a[319]
  PIN a[31]
    DIRECTION INPUT ;
    USE SIGNAL ;
    PORT
      LAYER M3 ;
        RECT  51.084 105.779 51.102 105.816 ;
    END
  END a[31]
  PIN a[320]
    DIRECTION INPUT ;
    USE SIGNAL ;
    PORT
      LAYER M5 ;
        RECT  61.968 105.732 61.992 105.816 ;
    END
  END a[320]
  PIN a[321]
    DIRECTION INPUT ;
    USE SIGNAL ;
    PORT
      LAYER M5 ;
        RECT  62.064 105.732 62.088 105.816 ;
    END
  END a[321]
  PIN a[322]
    DIRECTION INPUT ;
    USE SIGNAL ;
    PORT
      LAYER M5 ;
        RECT  62.16 105.732 62.184 105.816 ;
    END
  END a[322]
  PIN a[323]
    DIRECTION INPUT ;
    USE SIGNAL ;
    PORT
      LAYER M5 ;
        RECT  62.256 105.732 62.28 105.816 ;
    END
  END a[323]
  PIN a[324]
    DIRECTION INPUT ;
    USE SIGNAL ;
    PORT
      LAYER M5 ;
        RECT  62.352 105.732 62.376 105.816 ;
    END
  END a[324]
  PIN a[325]
    DIRECTION INPUT ;
    USE SIGNAL ;
    PORT
      LAYER M5 ;
        RECT  62.448 105.732 62.472 105.816 ;
    END
  END a[325]
  PIN a[326]
    DIRECTION INPUT ;
    USE SIGNAL ;
    PORT
      LAYER M5 ;
        RECT  62.544 105.732 62.568 105.816 ;
    END
  END a[326]
  PIN a[327]
    DIRECTION INPUT ;
    USE SIGNAL ;
    PORT
      LAYER M5 ;
        RECT  62.64 105.732 62.664 105.816 ;
    END
  END a[327]
  PIN a[328]
    DIRECTION INPUT ;
    USE SIGNAL ;
    PORT
      LAYER M5 ;
        RECT  62.736 105.732 62.76 105.816 ;
    END
  END a[328]
  PIN a[329]
    DIRECTION INPUT ;
    USE SIGNAL ;
    PORT
      LAYER M5 ;
        RECT  62.832 105.732 62.856 105.816 ;
    END
  END a[329]
  PIN a[32]
    DIRECTION INPUT ;
    USE SIGNAL ;
    PORT
      LAYER M3 ;
        RECT  58.068 105.779 58.086 105.816 ;
    END
  END a[32]
  PIN a[330]
    DIRECTION INPUT ;
    USE SIGNAL ;
    PORT
      LAYER M5 ;
        RECT  62.928 105.732 62.952 105.816 ;
    END
  END a[330]
  PIN a[331]
    DIRECTION INPUT ;
    USE SIGNAL ;
    PORT
      LAYER M5 ;
        RECT  63.024 105.732 63.048 105.816 ;
    END
  END a[331]
  PIN a[332]
    DIRECTION INPUT ;
    USE SIGNAL ;
    PORT
      LAYER M5 ;
        RECT  63.12 105.732 63.144 105.816 ;
    END
  END a[332]
  PIN a[333]
    DIRECTION INPUT ;
    USE SIGNAL ;
    PORT
      LAYER M5 ;
        RECT  63.216 105.732 63.24 105.816 ;
    END
  END a[333]
  PIN a[334]
    DIRECTION INPUT ;
    USE SIGNAL ;
    PORT
      LAYER M5 ;
        RECT  63.312 105.732 63.336 105.816 ;
    END
  END a[334]
  PIN a[335]
    DIRECTION INPUT ;
    USE SIGNAL ;
    PORT
      LAYER M5 ;
        RECT  63.408 105.732 63.432 105.816 ;
    END
  END a[335]
  PIN a[336]
    DIRECTION INPUT ;
    USE SIGNAL ;
    PORT
      LAYER M5 ;
        RECT  63.504 105.732 63.528 105.816 ;
    END
  END a[336]
  PIN a[337]
    DIRECTION INPUT ;
    USE SIGNAL ;
    PORT
      LAYER M5 ;
        RECT  63.6 105.732 63.624 105.816 ;
    END
  END a[337]
  PIN a[338]
    DIRECTION INPUT ;
    USE SIGNAL ;
    PORT
      LAYER M5 ;
        RECT  63.696 105.732 63.72 105.816 ;
    END
  END a[338]
  PIN a[339]
    DIRECTION INPUT ;
    USE SIGNAL ;
    PORT
      LAYER M5 ;
        RECT  63.792 105.732 63.816 105.816 ;
    END
  END a[339]
  PIN a[33]
    DIRECTION INPUT ;
    USE SIGNAL ;
    PORT
      LAYER M3 ;
        RECT  58.14 105.779 58.158 105.816 ;
    END
  END a[33]
  PIN a[340]
    DIRECTION INPUT ;
    USE SIGNAL ;
    PORT
      LAYER M5 ;
        RECT  63.888 105.732 63.912 105.816 ;
    END
  END a[340]
  PIN a[341]
    DIRECTION INPUT ;
    USE SIGNAL ;
    PORT
      LAYER M5 ;
        RECT  63.984 105.732 64.008 105.816 ;
    END
  END a[341]
  PIN a[342]
    DIRECTION INPUT ;
    USE SIGNAL ;
    PORT
      LAYER M5 ;
        RECT  64.08 105.732 64.104 105.816 ;
    END
  END a[342]
  PIN a[343]
    DIRECTION INPUT ;
    USE SIGNAL ;
    PORT
      LAYER M5 ;
        RECT  64.176 105.732 64.2 105.816 ;
    END
  END a[343]
  PIN a[344]
    DIRECTION INPUT ;
    USE SIGNAL ;
    PORT
      LAYER M5 ;
        RECT  64.272 105.732 64.296 105.816 ;
    END
  END a[344]
  PIN a[345]
    DIRECTION INPUT ;
    USE SIGNAL ;
    PORT
      LAYER M5 ;
        RECT  64.368 105.732 64.392 105.816 ;
    END
  END a[345]
  PIN a[346]
    DIRECTION INPUT ;
    USE SIGNAL ;
    PORT
      LAYER M5 ;
        RECT  64.464 105.732 64.488 105.816 ;
    END
  END a[346]
  PIN a[347]
    DIRECTION INPUT ;
    USE SIGNAL ;
    PORT
      LAYER M5 ;
        RECT  64.56 105.732 64.584 105.816 ;
    END
  END a[347]
  PIN a[348]
    DIRECTION INPUT ;
    USE SIGNAL ;
    PORT
      LAYER M5 ;
        RECT  64.656 105.732 64.68 105.816 ;
    END
  END a[348]
  PIN a[349]
    DIRECTION INPUT ;
    USE SIGNAL ;
    PORT
      LAYER M5 ;
        RECT  64.752 105.732 64.776 105.816 ;
    END
  END a[349]
  PIN a[34]
    DIRECTION INPUT ;
    USE SIGNAL ;
    PORT
      LAYER M3 ;
        RECT  58.212 105.779 58.23 105.816 ;
    END
  END a[34]
  PIN a[350]
    DIRECTION INPUT ;
    USE SIGNAL ;
    PORT
      LAYER M5 ;
        RECT  64.848 105.732 64.872 105.816 ;
    END
  END a[350]
  PIN a[351]
    DIRECTION INPUT ;
    USE SIGNAL ;
    PORT
      LAYER M5 ;
        RECT  64.944 105.732 64.968 105.816 ;
    END
  END a[351]
  PIN a[352]
    DIRECTION INPUT ;
    USE SIGNAL ;
    PORT
      LAYER M5 ;
        RECT  49.68 105.732 49.704 105.816 ;
    END
  END a[352]
  PIN a[353]
    DIRECTION INPUT ;
    USE SIGNAL ;
    PORT
      LAYER M5 ;
        RECT  49.776 105.732 49.8 105.816 ;
    END
  END a[353]
  PIN a[354]
    DIRECTION INPUT ;
    USE SIGNAL ;
    PORT
      LAYER M5 ;
        RECT  49.872 105.732 49.896 105.816 ;
    END
  END a[354]
  PIN a[355]
    DIRECTION INPUT ;
    USE SIGNAL ;
    PORT
      LAYER M5 ;
        RECT  49.968 105.732 49.992 105.816 ;
    END
  END a[355]
  PIN a[356]
    DIRECTION INPUT ;
    USE SIGNAL ;
    PORT
      LAYER M5 ;
        RECT  50.064 105.732 50.088 105.816 ;
    END
  END a[356]
  PIN a[357]
    DIRECTION INPUT ;
    USE SIGNAL ;
    PORT
      LAYER M5 ;
        RECT  50.16 105.732 50.184 105.816 ;
    END
  END a[357]
  PIN a[358]
    DIRECTION INPUT ;
    USE SIGNAL ;
    PORT
      LAYER M5 ;
        RECT  50.256 105.732 50.28 105.816 ;
    END
  END a[358]
  PIN a[359]
    DIRECTION INPUT ;
    USE SIGNAL ;
    PORT
      LAYER M5 ;
        RECT  50.352 105.732 50.376 105.816 ;
    END
  END a[359]
  PIN a[35]
    DIRECTION INPUT ;
    USE SIGNAL ;
    PORT
      LAYER M3 ;
        RECT  58.284 105.779 58.302 105.816 ;
    END
  END a[35]
  PIN a[360]
    DIRECTION INPUT ;
    USE SIGNAL ;
    PORT
      LAYER M5 ;
        RECT  50.448 105.732 50.472 105.816 ;
    END
  END a[360]
  PIN a[361]
    DIRECTION INPUT ;
    USE SIGNAL ;
    PORT
      LAYER M5 ;
        RECT  50.544 105.732 50.568 105.816 ;
    END
  END a[361]
  PIN a[362]
    DIRECTION INPUT ;
    USE SIGNAL ;
    PORT
      LAYER M5 ;
        RECT  50.64 105.732 50.664 105.816 ;
    END
  END a[362]
  PIN a[363]
    DIRECTION INPUT ;
    USE SIGNAL ;
    PORT
      LAYER M5 ;
        RECT  50.736 105.732 50.76 105.816 ;
    END
  END a[363]
  PIN a[364]
    DIRECTION INPUT ;
    USE SIGNAL ;
    PORT
      LAYER M5 ;
        RECT  50.832 105.732 50.856 105.816 ;
    END
  END a[364]
  PIN a[365]
    DIRECTION INPUT ;
    USE SIGNAL ;
    PORT
      LAYER M5 ;
        RECT  50.928 105.732 50.952 105.816 ;
    END
  END a[365]
  PIN a[366]
    DIRECTION INPUT ;
    USE SIGNAL ;
    PORT
      LAYER M5 ;
        RECT  51.024 105.732 51.048 105.816 ;
    END
  END a[366]
  PIN a[367]
    DIRECTION INPUT ;
    USE SIGNAL ;
    PORT
      LAYER M5 ;
        RECT  51.12 105.732 51.144 105.816 ;
    END
  END a[367]
  PIN a[368]
    DIRECTION INPUT ;
    USE SIGNAL ;
    PORT
      LAYER M5 ;
        RECT  51.216 105.732 51.24 105.816 ;
    END
  END a[368]
  PIN a[369]
    DIRECTION INPUT ;
    USE SIGNAL ;
    PORT
      LAYER M5 ;
        RECT  51.312 105.732 51.336 105.816 ;
    END
  END a[369]
  PIN a[36]
    DIRECTION INPUT ;
    USE SIGNAL ;
    PORT
      LAYER M3 ;
        RECT  58.356 105.779 58.374 105.816 ;
    END
  END a[36]
  PIN a[370]
    DIRECTION INPUT ;
    USE SIGNAL ;
    PORT
      LAYER M5 ;
        RECT  51.408 105.732 51.432 105.816 ;
    END
  END a[370]
  PIN a[371]
    DIRECTION INPUT ;
    USE SIGNAL ;
    PORT
      LAYER M5 ;
        RECT  51.504 105.732 51.528 105.816 ;
    END
  END a[371]
  PIN a[372]
    DIRECTION INPUT ;
    USE SIGNAL ;
    PORT
      LAYER M5 ;
        RECT  51.6 105.732 51.624 105.816 ;
    END
  END a[372]
  PIN a[373]
    DIRECTION INPUT ;
    USE SIGNAL ;
    PORT
      LAYER M5 ;
        RECT  51.696 105.732 51.72 105.816 ;
    END
  END a[373]
  PIN a[374]
    DIRECTION INPUT ;
    USE SIGNAL ;
    PORT
      LAYER M5 ;
        RECT  51.792 105.732 51.816 105.816 ;
    END
  END a[374]
  PIN a[375]
    DIRECTION INPUT ;
    USE SIGNAL ;
    PORT
      LAYER M5 ;
        RECT  51.888 105.732 51.912 105.816 ;
    END
  END a[375]
  PIN a[376]
    DIRECTION INPUT ;
    USE SIGNAL ;
    PORT
      LAYER M5 ;
        RECT  51.984 105.732 52.008 105.816 ;
    END
  END a[376]
  PIN a[377]
    DIRECTION INPUT ;
    USE SIGNAL ;
    PORT
      LAYER M5 ;
        RECT  52.08 105.732 52.104 105.816 ;
    END
  END a[377]
  PIN a[378]
    DIRECTION INPUT ;
    USE SIGNAL ;
    PORT
      LAYER M5 ;
        RECT  52.176 105.732 52.2 105.816 ;
    END
  END a[378]
  PIN a[379]
    DIRECTION INPUT ;
    USE SIGNAL ;
    PORT
      LAYER M5 ;
        RECT  52.272 105.732 52.296 105.816 ;
    END
  END a[379]
  PIN a[37]
    DIRECTION INPUT ;
    USE SIGNAL ;
    PORT
      LAYER M3 ;
        RECT  58.428 105.779 58.446 105.816 ;
    END
  END a[37]
  PIN a[380]
    DIRECTION INPUT ;
    USE SIGNAL ;
    PORT
      LAYER M5 ;
        RECT  52.368 105.732 52.392 105.816 ;
    END
  END a[380]
  PIN a[381]
    DIRECTION INPUT ;
    USE SIGNAL ;
    PORT
      LAYER M5 ;
        RECT  52.464 105.732 52.488 105.816 ;
    END
  END a[381]
  PIN a[382]
    DIRECTION INPUT ;
    USE SIGNAL ;
    PORT
      LAYER M5 ;
        RECT  52.56 105.732 52.584 105.816 ;
    END
  END a[382]
  PIN a[383]
    DIRECTION INPUT ;
    USE SIGNAL ;
    PORT
      LAYER M5 ;
        RECT  52.656 105.732 52.68 105.816 ;
    END
  END a[383]
  PIN a[384]
    DIRECTION INPUT ;
    USE SIGNAL ;
    PORT
      LAYER M3 ;
        RECT  36.756 105.779 36.774 105.816 ;
    END
  END a[384]
  PIN a[385]
    DIRECTION INPUT ;
    USE SIGNAL ;
    PORT
      LAYER M3 ;
        RECT  36.828 105.779 36.846 105.816 ;
    END
  END a[385]
  PIN a[386]
    DIRECTION INPUT ;
    USE SIGNAL ;
    PORT
      LAYER M3 ;
        RECT  36.9 105.779 36.918 105.816 ;
    END
  END a[386]
  PIN a[387]
    DIRECTION INPUT ;
    USE SIGNAL ;
    PORT
      LAYER M3 ;
        RECT  36.972 105.779 36.99 105.816 ;
    END
  END a[387]
  PIN a[388]
    DIRECTION INPUT ;
    USE SIGNAL ;
    PORT
      LAYER M3 ;
        RECT  37.044 105.779 37.062 105.816 ;
    END
  END a[388]
  PIN a[389]
    DIRECTION INPUT ;
    USE SIGNAL ;
    PORT
      LAYER M3 ;
        RECT  37.116 105.779 37.134 105.816 ;
    END
  END a[389]
  PIN a[38]
    DIRECTION INPUT ;
    USE SIGNAL ;
    PORT
      LAYER M3 ;
        RECT  58.5 105.779 58.518 105.816 ;
    END
  END a[38]
  PIN a[390]
    DIRECTION INPUT ;
    USE SIGNAL ;
    PORT
      LAYER M3 ;
        RECT  37.188 105.779 37.206 105.816 ;
    END
  END a[390]
  PIN a[391]
    DIRECTION INPUT ;
    USE SIGNAL ;
    PORT
      LAYER M3 ;
        RECT  37.26 105.779 37.278 105.816 ;
    END
  END a[391]
  PIN a[392]
    DIRECTION INPUT ;
    USE SIGNAL ;
    PORT
      LAYER M3 ;
        RECT  37.332 105.779 37.35 105.816 ;
    END
  END a[392]
  PIN a[393]
    DIRECTION INPUT ;
    USE SIGNAL ;
    PORT
      LAYER M3 ;
        RECT  37.404 105.779 37.422 105.816 ;
    END
  END a[393]
  PIN a[394]
    DIRECTION INPUT ;
    USE SIGNAL ;
    PORT
      LAYER M3 ;
        RECT  37.476 105.779 37.494 105.816 ;
    END
  END a[394]
  PIN a[395]
    DIRECTION INPUT ;
    USE SIGNAL ;
    PORT
      LAYER M3 ;
        RECT  37.548 105.779 37.566 105.816 ;
    END
  END a[395]
  PIN a[396]
    DIRECTION INPUT ;
    USE SIGNAL ;
    PORT
      LAYER M3 ;
        RECT  37.62 105.779 37.638 105.816 ;
    END
  END a[396]
  PIN a[397]
    DIRECTION INPUT ;
    USE SIGNAL ;
    PORT
      LAYER M3 ;
        RECT  37.692 105.779 37.71 105.816 ;
    END
  END a[397]
  PIN a[398]
    DIRECTION INPUT ;
    USE SIGNAL ;
    PORT
      LAYER M3 ;
        RECT  37.764 105.779 37.782 105.816 ;
    END
  END a[398]
  PIN a[399]
    DIRECTION INPUT ;
    USE SIGNAL ;
    PORT
      LAYER M3 ;
        RECT  37.836 105.779 37.854 105.816 ;
    END
  END a[399]
  PIN a[39]
    DIRECTION INPUT ;
    USE SIGNAL ;
    PORT
      LAYER M3 ;
        RECT  58.572 105.779 58.59 105.816 ;
    END
  END a[39]
  PIN a[3]
    DIRECTION INPUT ;
    USE SIGNAL ;
    PORT
      LAYER M3 ;
        RECT  49.068 105.779 49.086 105.816 ;
    END
  END a[3]
  PIN a[400]
    DIRECTION INPUT ;
    USE SIGNAL ;
    PORT
      LAYER M3 ;
        RECT  37.908 105.779 37.926 105.816 ;
    END
  END a[400]
  PIN a[401]
    DIRECTION INPUT ;
    USE SIGNAL ;
    PORT
      LAYER M3 ;
        RECT  37.98 105.779 37.998 105.816 ;
    END
  END a[401]
  PIN a[402]
    DIRECTION INPUT ;
    USE SIGNAL ;
    PORT
      LAYER M3 ;
        RECT  38.052 105.779 38.07 105.816 ;
    END
  END a[402]
  PIN a[403]
    DIRECTION INPUT ;
    USE SIGNAL ;
    PORT
      LAYER M3 ;
        RECT  38.124 105.779 38.142 105.816 ;
    END
  END a[403]
  PIN a[404]
    DIRECTION INPUT ;
    USE SIGNAL ;
    PORT
      LAYER M3 ;
        RECT  38.196 105.779 38.214 105.816 ;
    END
  END a[404]
  PIN a[405]
    DIRECTION INPUT ;
    USE SIGNAL ;
    PORT
      LAYER M3 ;
        RECT  38.268 105.779 38.286 105.816 ;
    END
  END a[405]
  PIN a[406]
    DIRECTION INPUT ;
    USE SIGNAL ;
    PORT
      LAYER M3 ;
        RECT  38.34 105.779 38.358 105.816 ;
    END
  END a[406]
  PIN a[407]
    DIRECTION INPUT ;
    USE SIGNAL ;
    PORT
      LAYER M3 ;
        RECT  38.412 105.779 38.43 105.816 ;
    END
  END a[407]
  PIN a[408]
    DIRECTION INPUT ;
    USE SIGNAL ;
    PORT
      LAYER M3 ;
        RECT  38.484 105.779 38.502 105.816 ;
    END
  END a[408]
  PIN a[409]
    DIRECTION INPUT ;
    USE SIGNAL ;
    PORT
      LAYER M3 ;
        RECT  38.556 105.779 38.574 105.816 ;
    END
  END a[409]
  PIN a[40]
    DIRECTION INPUT ;
    USE SIGNAL ;
    PORT
      LAYER M3 ;
        RECT  58.644 105.779 58.662 105.816 ;
    END
  END a[40]
  PIN a[410]
    DIRECTION INPUT ;
    USE SIGNAL ;
    PORT
      LAYER M3 ;
        RECT  38.628 105.779 38.646 105.816 ;
    END
  END a[410]
  PIN a[411]
    DIRECTION INPUT ;
    USE SIGNAL ;
    PORT
      LAYER M3 ;
        RECT  38.7 105.779 38.718 105.816 ;
    END
  END a[411]
  PIN a[412]
    DIRECTION INPUT ;
    USE SIGNAL ;
    PORT
      LAYER M3 ;
        RECT  38.772 105.779 38.79 105.816 ;
    END
  END a[412]
  PIN a[413]
    DIRECTION INPUT ;
    USE SIGNAL ;
    PORT
      LAYER M3 ;
        RECT  38.844 105.779 38.862 105.816 ;
    END
  END a[413]
  PIN a[414]
    DIRECTION INPUT ;
    USE SIGNAL ;
    PORT
      LAYER M3 ;
        RECT  38.916 105.779 38.934 105.816 ;
    END
  END a[414]
  PIN a[415]
    DIRECTION INPUT ;
    USE SIGNAL ;
    PORT
      LAYER M3 ;
        RECT  38.988 105.779 39.006 105.816 ;
    END
  END a[415]
  PIN a[416]
    DIRECTION INPUT ;
    USE SIGNAL ;
    PORT
      LAYER M3 ;
        RECT  34.452 105.779 34.47 105.816 ;
    END
  END a[416]
  PIN a[417]
    DIRECTION INPUT ;
    USE SIGNAL ;
    PORT
      LAYER M3 ;
        RECT  34.524 105.779 34.542 105.816 ;
    END
  END a[417]
  PIN a[418]
    DIRECTION INPUT ;
    USE SIGNAL ;
    PORT
      LAYER M3 ;
        RECT  34.596 105.779 34.614 105.816 ;
    END
  END a[418]
  PIN a[419]
    DIRECTION INPUT ;
    USE SIGNAL ;
    PORT
      LAYER M3 ;
        RECT  34.668 105.779 34.686 105.816 ;
    END
  END a[419]
  PIN a[41]
    DIRECTION INPUT ;
    USE SIGNAL ;
    PORT
      LAYER M3 ;
        RECT  58.716 105.779 58.734 105.816 ;
    END
  END a[41]
  PIN a[420]
    DIRECTION INPUT ;
    USE SIGNAL ;
    PORT
      LAYER M3 ;
        RECT  34.74 105.779 34.758 105.816 ;
    END
  END a[420]
  PIN a[421]
    DIRECTION INPUT ;
    USE SIGNAL ;
    PORT
      LAYER M3 ;
        RECT  34.812 105.779 34.83 105.816 ;
    END
  END a[421]
  PIN a[422]
    DIRECTION INPUT ;
    USE SIGNAL ;
    PORT
      LAYER M3 ;
        RECT  34.884 105.779 34.902 105.816 ;
    END
  END a[422]
  PIN a[423]
    DIRECTION INPUT ;
    USE SIGNAL ;
    PORT
      LAYER M3 ;
        RECT  34.956 105.779 34.974 105.816 ;
    END
  END a[423]
  PIN a[424]
    DIRECTION INPUT ;
    USE SIGNAL ;
    PORT
      LAYER M3 ;
        RECT  35.028 105.779 35.046 105.816 ;
    END
  END a[424]
  PIN a[425]
    DIRECTION INPUT ;
    USE SIGNAL ;
    PORT
      LAYER M3 ;
        RECT  35.1 105.779 35.118 105.816 ;
    END
  END a[425]
  PIN a[426]
    DIRECTION INPUT ;
    USE SIGNAL ;
    PORT
      LAYER M3 ;
        RECT  35.172 105.779 35.19 105.816 ;
    END
  END a[426]
  PIN a[427]
    DIRECTION INPUT ;
    USE SIGNAL ;
    PORT
      LAYER M3 ;
        RECT  35.244 105.779 35.262 105.816 ;
    END
  END a[427]
  PIN a[428]
    DIRECTION INPUT ;
    USE SIGNAL ;
    PORT
      LAYER M3 ;
        RECT  35.316 105.779 35.334 105.816 ;
    END
  END a[428]
  PIN a[429]
    DIRECTION INPUT ;
    USE SIGNAL ;
    PORT
      LAYER M3 ;
        RECT  35.388 105.779 35.406 105.816 ;
    END
  END a[429]
  PIN a[42]
    DIRECTION INPUT ;
    USE SIGNAL ;
    PORT
      LAYER M3 ;
        RECT  58.788 105.779 58.806 105.816 ;
    END
  END a[42]
  PIN a[430]
    DIRECTION INPUT ;
    USE SIGNAL ;
    PORT
      LAYER M3 ;
        RECT  35.46 105.779 35.478 105.816 ;
    END
  END a[430]
  PIN a[431]
    DIRECTION INPUT ;
    USE SIGNAL ;
    PORT
      LAYER M3 ;
        RECT  35.532 105.779 35.55 105.816 ;
    END
  END a[431]
  PIN a[432]
    DIRECTION INPUT ;
    USE SIGNAL ;
    PORT
      LAYER M3 ;
        RECT  35.604 105.779 35.622 105.816 ;
    END
  END a[432]
  PIN a[433]
    DIRECTION INPUT ;
    USE SIGNAL ;
    PORT
      LAYER M3 ;
        RECT  35.676 105.779 35.694 105.816 ;
    END
  END a[433]
  PIN a[434]
    DIRECTION INPUT ;
    USE SIGNAL ;
    PORT
      LAYER M3 ;
        RECT  35.748 105.779 35.766 105.816 ;
    END
  END a[434]
  PIN a[435]
    DIRECTION INPUT ;
    USE SIGNAL ;
    PORT
      LAYER M3 ;
        RECT  35.82 105.779 35.838 105.816 ;
    END
  END a[435]
  PIN a[436]
    DIRECTION INPUT ;
    USE SIGNAL ;
    PORT
      LAYER M3 ;
        RECT  35.892 105.779 35.91 105.816 ;
    END
  END a[436]
  PIN a[437]
    DIRECTION INPUT ;
    USE SIGNAL ;
    PORT
      LAYER M3 ;
        RECT  35.964 105.779 35.982 105.816 ;
    END
  END a[437]
  PIN a[438]
    DIRECTION INPUT ;
    USE SIGNAL ;
    PORT
      LAYER M3 ;
        RECT  36.036 105.779 36.054 105.816 ;
    END
  END a[438]
  PIN a[439]
    DIRECTION INPUT ;
    USE SIGNAL ;
    PORT
      LAYER M3 ;
        RECT  36.108 105.779 36.126 105.816 ;
    END
  END a[439]
  PIN a[43]
    DIRECTION INPUT ;
    USE SIGNAL ;
    PORT
      LAYER M3 ;
        RECT  58.86 105.779 58.878 105.816 ;
    END
  END a[43]
  PIN a[440]
    DIRECTION INPUT ;
    USE SIGNAL ;
    PORT
      LAYER M3 ;
        RECT  36.18 105.779 36.198 105.816 ;
    END
  END a[440]
  PIN a[441]
    DIRECTION INPUT ;
    USE SIGNAL ;
    PORT
      LAYER M3 ;
        RECT  36.252 105.779 36.27 105.816 ;
    END
  END a[441]
  PIN a[442]
    DIRECTION INPUT ;
    USE SIGNAL ;
    PORT
      LAYER M3 ;
        RECT  36.324 105.779 36.342 105.816 ;
    END
  END a[442]
  PIN a[443]
    DIRECTION INPUT ;
    USE SIGNAL ;
    PORT
      LAYER M3 ;
        RECT  36.396 105.779 36.414 105.816 ;
    END
  END a[443]
  PIN a[444]
    DIRECTION INPUT ;
    USE SIGNAL ;
    PORT
      LAYER M3 ;
        RECT  36.468 105.779 36.486 105.816 ;
    END
  END a[444]
  PIN a[445]
    DIRECTION INPUT ;
    USE SIGNAL ;
    PORT
      LAYER M3 ;
        RECT  36.54 105.779 36.558 105.816 ;
    END
  END a[445]
  PIN a[446]
    DIRECTION INPUT ;
    USE SIGNAL ;
    PORT
      LAYER M3 ;
        RECT  36.612 105.779 36.63 105.816 ;
    END
  END a[446]
  PIN a[447]
    DIRECTION INPUT ;
    USE SIGNAL ;
    PORT
      LAYER M3 ;
        RECT  36.684 105.779 36.702 105.816 ;
    END
  END a[447]
  PIN a[448]
    DIRECTION INPUT ;
    USE SIGNAL ;
    PORT
      LAYER M3 ;
        RECT  32.148 105.779 32.166 105.816 ;
    END
  END a[448]
  PIN a[449]
    DIRECTION INPUT ;
    USE SIGNAL ;
    PORT
      LAYER M3 ;
        RECT  32.22 105.779 32.238 105.816 ;
    END
  END a[449]
  PIN a[44]
    DIRECTION INPUT ;
    USE SIGNAL ;
    PORT
      LAYER M3 ;
        RECT  58.932 105.779 58.95 105.816 ;
    END
  END a[44]
  PIN a[450]
    DIRECTION INPUT ;
    USE SIGNAL ;
    PORT
      LAYER M3 ;
        RECT  32.292 105.779 32.31 105.816 ;
    END
  END a[450]
  PIN a[451]
    DIRECTION INPUT ;
    USE SIGNAL ;
    PORT
      LAYER M3 ;
        RECT  32.364 105.779 32.382 105.816 ;
    END
  END a[451]
  PIN a[452]
    DIRECTION INPUT ;
    USE SIGNAL ;
    PORT
      LAYER M3 ;
        RECT  32.436 105.779 32.454 105.816 ;
    END
  END a[452]
  PIN a[453]
    DIRECTION INPUT ;
    USE SIGNAL ;
    PORT
      LAYER M3 ;
        RECT  32.508 105.779 32.526 105.816 ;
    END
  END a[453]
  PIN a[454]
    DIRECTION INPUT ;
    USE SIGNAL ;
    PORT
      LAYER M3 ;
        RECT  32.58 105.779 32.598 105.816 ;
    END
  END a[454]
  PIN a[455]
    DIRECTION INPUT ;
    USE SIGNAL ;
    PORT
      LAYER M3 ;
        RECT  32.652 105.779 32.67 105.816 ;
    END
  END a[455]
  PIN a[456]
    DIRECTION INPUT ;
    USE SIGNAL ;
    PORT
      LAYER M3 ;
        RECT  32.724 105.779 32.742 105.816 ;
    END
  END a[456]
  PIN a[457]
    DIRECTION INPUT ;
    USE SIGNAL ;
    PORT
      LAYER M3 ;
        RECT  32.796 105.779 32.814 105.816 ;
    END
  END a[457]
  PIN a[458]
    DIRECTION INPUT ;
    USE SIGNAL ;
    PORT
      LAYER M3 ;
        RECT  32.868 105.779 32.886 105.816 ;
    END
  END a[458]
  PIN a[459]
    DIRECTION INPUT ;
    USE SIGNAL ;
    PORT
      LAYER M3 ;
        RECT  32.94 105.779 32.958 105.816 ;
    END
  END a[459]
  PIN a[45]
    DIRECTION INPUT ;
    USE SIGNAL ;
    PORT
      LAYER M3 ;
        RECT  59.004 105.779 59.022 105.816 ;
    END
  END a[45]
  PIN a[460]
    DIRECTION INPUT ;
    USE SIGNAL ;
    PORT
      LAYER M3 ;
        RECT  33.012 105.779 33.03 105.816 ;
    END
  END a[460]
  PIN a[461]
    DIRECTION INPUT ;
    USE SIGNAL ;
    PORT
      LAYER M3 ;
        RECT  33.084 105.779 33.102 105.816 ;
    END
  END a[461]
  PIN a[462]
    DIRECTION INPUT ;
    USE SIGNAL ;
    PORT
      LAYER M3 ;
        RECT  33.156 105.779 33.174 105.816 ;
    END
  END a[462]
  PIN a[463]
    DIRECTION INPUT ;
    USE SIGNAL ;
    PORT
      LAYER M3 ;
        RECT  33.228 105.779 33.246 105.816 ;
    END
  END a[463]
  PIN a[464]
    DIRECTION INPUT ;
    USE SIGNAL ;
    PORT
      LAYER M3 ;
        RECT  33.3 105.779 33.318 105.816 ;
    END
  END a[464]
  PIN a[465]
    DIRECTION INPUT ;
    USE SIGNAL ;
    PORT
      LAYER M3 ;
        RECT  33.372 105.779 33.39 105.816 ;
    END
  END a[465]
  PIN a[466]
    DIRECTION INPUT ;
    USE SIGNAL ;
    PORT
      LAYER M3 ;
        RECT  33.444 105.779 33.462 105.816 ;
    END
  END a[466]
  PIN a[467]
    DIRECTION INPUT ;
    USE SIGNAL ;
    PORT
      LAYER M3 ;
        RECT  33.516 105.779 33.534 105.816 ;
    END
  END a[467]
  PIN a[468]
    DIRECTION INPUT ;
    USE SIGNAL ;
    PORT
      LAYER M3 ;
        RECT  33.588 105.779 33.606 105.816 ;
    END
  END a[468]
  PIN a[469]
    DIRECTION INPUT ;
    USE SIGNAL ;
    PORT
      LAYER M3 ;
        RECT  33.66 105.779 33.678 105.816 ;
    END
  END a[469]
  PIN a[46]
    DIRECTION INPUT ;
    USE SIGNAL ;
    PORT
      LAYER M3 ;
        RECT  59.076 105.779 59.094 105.816 ;
    END
  END a[46]
  PIN a[470]
    DIRECTION INPUT ;
    USE SIGNAL ;
    PORT
      LAYER M3 ;
        RECT  33.732 105.779 33.75 105.816 ;
    END
  END a[470]
  PIN a[471]
    DIRECTION INPUT ;
    USE SIGNAL ;
    PORT
      LAYER M3 ;
        RECT  33.804 105.779 33.822 105.816 ;
    END
  END a[471]
  PIN a[472]
    DIRECTION INPUT ;
    USE SIGNAL ;
    PORT
      LAYER M3 ;
        RECT  33.876 105.779 33.894 105.816 ;
    END
  END a[472]
  PIN a[473]
    DIRECTION INPUT ;
    USE SIGNAL ;
    PORT
      LAYER M3 ;
        RECT  33.948 105.779 33.966 105.816 ;
    END
  END a[473]
  PIN a[474]
    DIRECTION INPUT ;
    USE SIGNAL ;
    PORT
      LAYER M3 ;
        RECT  34.02 105.779 34.038 105.816 ;
    END
  END a[474]
  PIN a[475]
    DIRECTION INPUT ;
    USE SIGNAL ;
    PORT
      LAYER M3 ;
        RECT  34.092 105.779 34.11 105.816 ;
    END
  END a[475]
  PIN a[476]
    DIRECTION INPUT ;
    USE SIGNAL ;
    PORT
      LAYER M3 ;
        RECT  34.164 105.779 34.182 105.816 ;
    END
  END a[476]
  PIN a[477]
    DIRECTION INPUT ;
    USE SIGNAL ;
    PORT
      LAYER M3 ;
        RECT  34.236 105.779 34.254 105.816 ;
    END
  END a[477]
  PIN a[478]
    DIRECTION INPUT ;
    USE SIGNAL ;
    PORT
      LAYER M3 ;
        RECT  34.308 105.779 34.326 105.816 ;
    END
  END a[478]
  PIN a[479]
    DIRECTION INPUT ;
    USE SIGNAL ;
    PORT
      LAYER M3 ;
        RECT  34.38 105.779 34.398 105.816 ;
    END
  END a[479]
  PIN a[47]
    DIRECTION INPUT ;
    USE SIGNAL ;
    PORT
      LAYER M3 ;
        RECT  59.148 105.779 59.166 105.816 ;
    END
  END a[47]
  PIN a[480]
    DIRECTION INPUT ;
    USE SIGNAL ;
    PORT
      LAYER M3 ;
        RECT  39.06 105.779 39.078 105.816 ;
    END
  END a[480]
  PIN a[481]
    DIRECTION INPUT ;
    USE SIGNAL ;
    PORT
      LAYER M3 ;
        RECT  39.132 105.779 39.15 105.816 ;
    END
  END a[481]
  PIN a[482]
    DIRECTION INPUT ;
    USE SIGNAL ;
    PORT
      LAYER M3 ;
        RECT  39.204 105.779 39.222 105.816 ;
    END
  END a[482]
  PIN a[483]
    DIRECTION INPUT ;
    USE SIGNAL ;
    PORT
      LAYER M3 ;
        RECT  39.276 105.779 39.294 105.816 ;
    END
  END a[483]
  PIN a[484]
    DIRECTION INPUT ;
    USE SIGNAL ;
    PORT
      LAYER M3 ;
        RECT  39.348 105.779 39.366 105.816 ;
    END
  END a[484]
  PIN a[485]
    DIRECTION INPUT ;
    USE SIGNAL ;
    PORT
      LAYER M3 ;
        RECT  39.42 105.779 39.438 105.816 ;
    END
  END a[485]
  PIN a[486]
    DIRECTION INPUT ;
    USE SIGNAL ;
    PORT
      LAYER M3 ;
        RECT  39.492 105.779 39.51 105.816 ;
    END
  END a[486]
  PIN a[487]
    DIRECTION INPUT ;
    USE SIGNAL ;
    PORT
      LAYER M3 ;
        RECT  39.564 105.779 39.582 105.816 ;
    END
  END a[487]
  PIN a[488]
    DIRECTION INPUT ;
    USE SIGNAL ;
    PORT
      LAYER M3 ;
        RECT  39.636 105.779 39.654 105.816 ;
    END
  END a[488]
  PIN a[489]
    DIRECTION INPUT ;
    USE SIGNAL ;
    PORT
      LAYER M3 ;
        RECT  39.708 105.779 39.726 105.816 ;
    END
  END a[489]
  PIN a[48]
    DIRECTION INPUT ;
    USE SIGNAL ;
    PORT
      LAYER M3 ;
        RECT  59.22 105.779 59.238 105.816 ;
    END
  END a[48]
  PIN a[490]
    DIRECTION INPUT ;
    USE SIGNAL ;
    PORT
      LAYER M3 ;
        RECT  39.78 105.779 39.798 105.816 ;
    END
  END a[490]
  PIN a[491]
    DIRECTION INPUT ;
    USE SIGNAL ;
    PORT
      LAYER M3 ;
        RECT  39.852 105.779 39.87 105.816 ;
    END
  END a[491]
  PIN a[492]
    DIRECTION INPUT ;
    USE SIGNAL ;
    PORT
      LAYER M3 ;
        RECT  39.924 105.779 39.942 105.816 ;
    END
  END a[492]
  PIN a[493]
    DIRECTION INPUT ;
    USE SIGNAL ;
    PORT
      LAYER M3 ;
        RECT  39.996 105.779 40.014 105.816 ;
    END
  END a[493]
  PIN a[494]
    DIRECTION INPUT ;
    USE SIGNAL ;
    PORT
      LAYER M3 ;
        RECT  40.068 105.779 40.086 105.816 ;
    END
  END a[494]
  PIN a[495]
    DIRECTION INPUT ;
    USE SIGNAL ;
    PORT
      LAYER M3 ;
        RECT  40.14 105.779 40.158 105.816 ;
    END
  END a[495]
  PIN a[496]
    DIRECTION INPUT ;
    USE SIGNAL ;
    PORT
      LAYER M3 ;
        RECT  40.212 105.779 40.23 105.816 ;
    END
  END a[496]
  PIN a[497]
    DIRECTION INPUT ;
    USE SIGNAL ;
    PORT
      LAYER M3 ;
        RECT  40.284 105.779 40.302 105.816 ;
    END
  END a[497]
  PIN a[498]
    DIRECTION INPUT ;
    USE SIGNAL ;
    PORT
      LAYER M3 ;
        RECT  40.356 105.779 40.374 105.816 ;
    END
  END a[498]
  PIN a[499]
    DIRECTION INPUT ;
    USE SIGNAL ;
    PORT
      LAYER M3 ;
        RECT  40.428 105.779 40.446 105.816 ;
    END
  END a[499]
  PIN a[49]
    DIRECTION INPUT ;
    USE SIGNAL ;
    PORT
      LAYER M3 ;
        RECT  59.292 105.779 59.31 105.816 ;
    END
  END a[49]
  PIN a[4]
    DIRECTION INPUT ;
    USE SIGNAL ;
    PORT
      LAYER M3 ;
        RECT  49.14 105.779 49.158 105.816 ;
    END
  END a[4]
  PIN a[500]
    DIRECTION INPUT ;
    USE SIGNAL ;
    PORT
      LAYER M3 ;
        RECT  40.5 105.779 40.518 105.816 ;
    END
  END a[500]
  PIN a[501]
    DIRECTION INPUT ;
    USE SIGNAL ;
    PORT
      LAYER M3 ;
        RECT  40.572 105.779 40.59 105.816 ;
    END
  END a[501]
  PIN a[502]
    DIRECTION INPUT ;
    USE SIGNAL ;
    PORT
      LAYER M3 ;
        RECT  40.644 105.779 40.662 105.816 ;
    END
  END a[502]
  PIN a[503]
    DIRECTION INPUT ;
    USE SIGNAL ;
    PORT
      LAYER M3 ;
        RECT  40.716 105.779 40.734 105.816 ;
    END
  END a[503]
  PIN a[504]
    DIRECTION INPUT ;
    USE SIGNAL ;
    PORT
      LAYER M3 ;
        RECT  40.788 105.779 40.806 105.816 ;
    END
  END a[504]
  PIN a[505]
    DIRECTION INPUT ;
    USE SIGNAL ;
    PORT
      LAYER M3 ;
        RECT  40.86 105.779 40.878 105.816 ;
    END
  END a[505]
  PIN a[506]
    DIRECTION INPUT ;
    USE SIGNAL ;
    PORT
      LAYER M3 ;
        RECT  40.932 105.779 40.95 105.816 ;
    END
  END a[506]
  PIN a[507]
    DIRECTION INPUT ;
    USE SIGNAL ;
    PORT
      LAYER M3 ;
        RECT  41.004 105.779 41.022 105.816 ;
    END
  END a[507]
  PIN a[508]
    DIRECTION INPUT ;
    USE SIGNAL ;
    PORT
      LAYER M3 ;
        RECT  41.076 105.779 41.094 105.816 ;
    END
  END a[508]
  PIN a[509]
    DIRECTION INPUT ;
    USE SIGNAL ;
    PORT
      LAYER M3 ;
        RECT  41.148 105.779 41.166 105.816 ;
    END
  END a[509]
  PIN a[50]
    DIRECTION INPUT ;
    USE SIGNAL ;
    PORT
      LAYER M3 ;
        RECT  59.364 105.779 59.382 105.816 ;
    END
  END a[50]
  PIN a[510]
    DIRECTION INPUT ;
    USE SIGNAL ;
    PORT
      LAYER M3 ;
        RECT  41.22 105.779 41.238 105.816 ;
    END
  END a[510]
  PIN a[511]
    DIRECTION INPUT ;
    USE SIGNAL ;
    PORT
      LAYER M3 ;
        RECT  41.292 105.779 41.31 105.816 ;
    END
  END a[511]
  PIN a[512]
    DIRECTION INPUT ;
    USE SIGNAL ;
    PORT
      LAYER M3 ;
        RECT  43.668 105.779 43.686 105.816 ;
    END
  END a[512]
  PIN a[513]
    DIRECTION INPUT ;
    USE SIGNAL ;
    PORT
      LAYER M3 ;
        RECT  43.74 105.779 43.758 105.816 ;
    END
  END a[513]
  PIN a[514]
    DIRECTION INPUT ;
    USE SIGNAL ;
    PORT
      LAYER M3 ;
        RECT  43.812 105.779 43.83 105.816 ;
    END
  END a[514]
  PIN a[515]
    DIRECTION INPUT ;
    USE SIGNAL ;
    PORT
      LAYER M3 ;
        RECT  43.884 105.779 43.902 105.816 ;
    END
  END a[515]
  PIN a[516]
    DIRECTION INPUT ;
    USE SIGNAL ;
    PORT
      LAYER M3 ;
        RECT  43.956 105.779 43.974 105.816 ;
    END
  END a[516]
  PIN a[517]
    DIRECTION INPUT ;
    USE SIGNAL ;
    PORT
      LAYER M3 ;
        RECT  44.028 105.779 44.046 105.816 ;
    END
  END a[517]
  PIN a[518]
    DIRECTION INPUT ;
    USE SIGNAL ;
    PORT
      LAYER M3 ;
        RECT  44.1 105.779 44.118 105.816 ;
    END
  END a[518]
  PIN a[519]
    DIRECTION INPUT ;
    USE SIGNAL ;
    PORT
      LAYER M3 ;
        RECT  44.172 105.779 44.19 105.816 ;
    END
  END a[519]
  PIN a[51]
    DIRECTION INPUT ;
    USE SIGNAL ;
    PORT
      LAYER M3 ;
        RECT  59.436 105.779 59.454 105.816 ;
    END
  END a[51]
  PIN a[520]
    DIRECTION INPUT ;
    USE SIGNAL ;
    PORT
      LAYER M3 ;
        RECT  44.244 105.779 44.262 105.816 ;
    END
  END a[520]
  PIN a[521]
    DIRECTION INPUT ;
    USE SIGNAL ;
    PORT
      LAYER M3 ;
        RECT  44.316 105.779 44.334 105.816 ;
    END
  END a[521]
  PIN a[522]
    DIRECTION INPUT ;
    USE SIGNAL ;
    PORT
      LAYER M3 ;
        RECT  44.388 105.779 44.406 105.816 ;
    END
  END a[522]
  PIN a[523]
    DIRECTION INPUT ;
    USE SIGNAL ;
    PORT
      LAYER M3 ;
        RECT  44.46 105.779 44.478 105.816 ;
    END
  END a[523]
  PIN a[524]
    DIRECTION INPUT ;
    USE SIGNAL ;
    PORT
      LAYER M3 ;
        RECT  44.532 105.779 44.55 105.816 ;
    END
  END a[524]
  PIN a[525]
    DIRECTION INPUT ;
    USE SIGNAL ;
    PORT
      LAYER M3 ;
        RECT  44.604 105.779 44.622 105.816 ;
    END
  END a[525]
  PIN a[526]
    DIRECTION INPUT ;
    USE SIGNAL ;
    PORT
      LAYER M3 ;
        RECT  44.676 105.779 44.694 105.816 ;
    END
  END a[526]
  PIN a[527]
    DIRECTION INPUT ;
    USE SIGNAL ;
    PORT
      LAYER M3 ;
        RECT  44.748 105.779 44.766 105.816 ;
    END
  END a[527]
  PIN a[528]
    DIRECTION INPUT ;
    USE SIGNAL ;
    PORT
      LAYER M3 ;
        RECT  44.82 105.779 44.838 105.816 ;
    END
  END a[528]
  PIN a[529]
    DIRECTION INPUT ;
    USE SIGNAL ;
    PORT
      LAYER M3 ;
        RECT  44.892 105.779 44.91 105.816 ;
    END
  END a[529]
  PIN a[52]
    DIRECTION INPUT ;
    USE SIGNAL ;
    PORT
      LAYER M3 ;
        RECT  59.508 105.779 59.526 105.816 ;
    END
  END a[52]
  PIN a[530]
    DIRECTION INPUT ;
    USE SIGNAL ;
    PORT
      LAYER M3 ;
        RECT  44.964 105.779 44.982 105.816 ;
    END
  END a[530]
  PIN a[531]
    DIRECTION INPUT ;
    USE SIGNAL ;
    PORT
      LAYER M3 ;
        RECT  45.036 105.779 45.054 105.816 ;
    END
  END a[531]
  PIN a[532]
    DIRECTION INPUT ;
    USE SIGNAL ;
    PORT
      LAYER M3 ;
        RECT  45.108 105.779 45.126 105.816 ;
    END
  END a[532]
  PIN a[533]
    DIRECTION INPUT ;
    USE SIGNAL ;
    PORT
      LAYER M3 ;
        RECT  45.18 105.779 45.198 105.816 ;
    END
  END a[533]
  PIN a[534]
    DIRECTION INPUT ;
    USE SIGNAL ;
    PORT
      LAYER M3 ;
        RECT  45.252 105.779 45.27 105.816 ;
    END
  END a[534]
  PIN a[535]
    DIRECTION INPUT ;
    USE SIGNAL ;
    PORT
      LAYER M3 ;
        RECT  45.324 105.779 45.342 105.816 ;
    END
  END a[535]
  PIN a[536]
    DIRECTION INPUT ;
    USE SIGNAL ;
    PORT
      LAYER M3 ;
        RECT  45.396 105.779 45.414 105.816 ;
    END
  END a[536]
  PIN a[537]
    DIRECTION INPUT ;
    USE SIGNAL ;
    PORT
      LAYER M3 ;
        RECT  45.468 105.779 45.486 105.816 ;
    END
  END a[537]
  PIN a[538]
    DIRECTION INPUT ;
    USE SIGNAL ;
    PORT
      LAYER M3 ;
        RECT  45.54 105.779 45.558 105.816 ;
    END
  END a[538]
  PIN a[539]
    DIRECTION INPUT ;
    USE SIGNAL ;
    PORT
      LAYER M3 ;
        RECT  45.612 105.779 45.63 105.816 ;
    END
  END a[539]
  PIN a[53]
    DIRECTION INPUT ;
    USE SIGNAL ;
    PORT
      LAYER M3 ;
        RECT  59.58 105.779 59.598 105.816 ;
    END
  END a[53]
  PIN a[540]
    DIRECTION INPUT ;
    USE SIGNAL ;
    PORT
      LAYER M3 ;
        RECT  45.684 105.779 45.702 105.816 ;
    END
  END a[540]
  PIN a[541]
    DIRECTION INPUT ;
    USE SIGNAL ;
    PORT
      LAYER M3 ;
        RECT  45.756 105.779 45.774 105.816 ;
    END
  END a[541]
  PIN a[542]
    DIRECTION INPUT ;
    USE SIGNAL ;
    PORT
      LAYER M3 ;
        RECT  45.828 105.779 45.846 105.816 ;
    END
  END a[542]
  PIN a[543]
    DIRECTION INPUT ;
    USE SIGNAL ;
    PORT
      LAYER M3 ;
        RECT  45.9 105.779 45.918 105.816 ;
    END
  END a[543]
  PIN a[544]
    DIRECTION INPUT ;
    USE SIGNAL ;
    PORT
      LAYER M3 ;
        RECT  41.364 105.779 41.382 105.816 ;
    END
  END a[544]
  PIN a[545]
    DIRECTION INPUT ;
    USE SIGNAL ;
    PORT
      LAYER M3 ;
        RECT  41.436 105.779 41.454 105.816 ;
    END
  END a[545]
  PIN a[546]
    DIRECTION INPUT ;
    USE SIGNAL ;
    PORT
      LAYER M3 ;
        RECT  41.508 105.779 41.526 105.816 ;
    END
  END a[546]
  PIN a[547]
    DIRECTION INPUT ;
    USE SIGNAL ;
    PORT
      LAYER M3 ;
        RECT  41.58 105.779 41.598 105.816 ;
    END
  END a[547]
  PIN a[548]
    DIRECTION INPUT ;
    USE SIGNAL ;
    PORT
      LAYER M3 ;
        RECT  41.652 105.779 41.67 105.816 ;
    END
  END a[548]
  PIN a[549]
    DIRECTION INPUT ;
    USE SIGNAL ;
    PORT
      LAYER M3 ;
        RECT  41.724 105.779 41.742 105.816 ;
    END
  END a[549]
  PIN a[54]
    DIRECTION INPUT ;
    USE SIGNAL ;
    PORT
      LAYER M3 ;
        RECT  59.652 105.779 59.67 105.816 ;
    END
  END a[54]
  PIN a[550]
    DIRECTION INPUT ;
    USE SIGNAL ;
    PORT
      LAYER M3 ;
        RECT  41.796 105.779 41.814 105.816 ;
    END
  END a[550]
  PIN a[551]
    DIRECTION INPUT ;
    USE SIGNAL ;
    PORT
      LAYER M3 ;
        RECT  41.868 105.779 41.886 105.816 ;
    END
  END a[551]
  PIN a[552]
    DIRECTION INPUT ;
    USE SIGNAL ;
    PORT
      LAYER M3 ;
        RECT  41.94 105.779 41.958 105.816 ;
    END
  END a[552]
  PIN a[553]
    DIRECTION INPUT ;
    USE SIGNAL ;
    PORT
      LAYER M3 ;
        RECT  42.012 105.779 42.03 105.816 ;
    END
  END a[553]
  PIN a[554]
    DIRECTION INPUT ;
    USE SIGNAL ;
    PORT
      LAYER M3 ;
        RECT  42.084 105.779 42.102 105.816 ;
    END
  END a[554]
  PIN a[555]
    DIRECTION INPUT ;
    USE SIGNAL ;
    PORT
      LAYER M3 ;
        RECT  42.156 105.779 42.174 105.816 ;
    END
  END a[555]
  PIN a[556]
    DIRECTION INPUT ;
    USE SIGNAL ;
    PORT
      LAYER M3 ;
        RECT  42.228 105.779 42.246 105.816 ;
    END
  END a[556]
  PIN a[557]
    DIRECTION INPUT ;
    USE SIGNAL ;
    PORT
      LAYER M3 ;
        RECT  42.3 105.779 42.318 105.816 ;
    END
  END a[557]
  PIN a[558]
    DIRECTION INPUT ;
    USE SIGNAL ;
    PORT
      LAYER M3 ;
        RECT  42.372 105.779 42.39 105.816 ;
    END
  END a[558]
  PIN a[559]
    DIRECTION INPUT ;
    USE SIGNAL ;
    PORT
      LAYER M3 ;
        RECT  42.444 105.779 42.462 105.816 ;
    END
  END a[559]
  PIN a[55]
    DIRECTION INPUT ;
    USE SIGNAL ;
    PORT
      LAYER M3 ;
        RECT  59.724 105.779 59.742 105.816 ;
    END
  END a[55]
  PIN a[560]
    DIRECTION INPUT ;
    USE SIGNAL ;
    PORT
      LAYER M3 ;
        RECT  42.516 105.779 42.534 105.816 ;
    END
  END a[560]
  PIN a[561]
    DIRECTION INPUT ;
    USE SIGNAL ;
    PORT
      LAYER M3 ;
        RECT  42.588 105.779 42.606 105.816 ;
    END
  END a[561]
  PIN a[562]
    DIRECTION INPUT ;
    USE SIGNAL ;
    PORT
      LAYER M3 ;
        RECT  42.66 105.779 42.678 105.816 ;
    END
  END a[562]
  PIN a[563]
    DIRECTION INPUT ;
    USE SIGNAL ;
    PORT
      LAYER M3 ;
        RECT  42.732 105.779 42.75 105.816 ;
    END
  END a[563]
  PIN a[564]
    DIRECTION INPUT ;
    USE SIGNAL ;
    PORT
      LAYER M3 ;
        RECT  42.804 105.779 42.822 105.816 ;
    END
  END a[564]
  PIN a[565]
    DIRECTION INPUT ;
    USE SIGNAL ;
    PORT
      LAYER M3 ;
        RECT  42.876 105.779 42.894 105.816 ;
    END
  END a[565]
  PIN a[566]
    DIRECTION INPUT ;
    USE SIGNAL ;
    PORT
      LAYER M3 ;
        RECT  42.948 105.779 42.966 105.816 ;
    END
  END a[566]
  PIN a[567]
    DIRECTION INPUT ;
    USE SIGNAL ;
    PORT
      LAYER M3 ;
        RECT  43.02 105.779 43.038 105.816 ;
    END
  END a[567]
  PIN a[568]
    DIRECTION INPUT ;
    USE SIGNAL ;
    PORT
      LAYER M3 ;
        RECT  43.092 105.779 43.11 105.816 ;
    END
  END a[568]
  PIN a[569]
    DIRECTION INPUT ;
    USE SIGNAL ;
    PORT
      LAYER M3 ;
        RECT  43.164 105.779 43.182 105.816 ;
    END
  END a[569]
  PIN a[56]
    DIRECTION INPUT ;
    USE SIGNAL ;
    PORT
      LAYER M3 ;
        RECT  59.796 105.779 59.814 105.816 ;
    END
  END a[56]
  PIN a[570]
    DIRECTION INPUT ;
    USE SIGNAL ;
    PORT
      LAYER M3 ;
        RECT  43.236 105.779 43.254 105.816 ;
    END
  END a[570]
  PIN a[571]
    DIRECTION INPUT ;
    USE SIGNAL ;
    PORT
      LAYER M3 ;
        RECT  43.308 105.779 43.326 105.816 ;
    END
  END a[571]
  PIN a[572]
    DIRECTION INPUT ;
    USE SIGNAL ;
    PORT
      LAYER M3 ;
        RECT  43.38 105.779 43.398 105.816 ;
    END
  END a[572]
  PIN a[573]
    DIRECTION INPUT ;
    USE SIGNAL ;
    PORT
      LAYER M3 ;
        RECT  43.452 105.779 43.47 105.816 ;
    END
  END a[573]
  PIN a[574]
    DIRECTION INPUT ;
    USE SIGNAL ;
    PORT
      LAYER M3 ;
        RECT  43.524 105.779 43.542 105.816 ;
    END
  END a[574]
  PIN a[575]
    DIRECTION INPUT ;
    USE SIGNAL ;
    PORT
      LAYER M3 ;
        RECT  43.596 105.779 43.614 105.816 ;
    END
  END a[575]
  PIN a[576]
    DIRECTION INPUT ;
    USE SIGNAL ;
    PORT
      LAYER M5 ;
        RECT  43.536 105.732 43.56 105.816 ;
    END
  END a[576]
  PIN a[577]
    DIRECTION INPUT ;
    USE SIGNAL ;
    PORT
      LAYER M5 ;
        RECT  43.632 105.732 43.656 105.816 ;
    END
  END a[577]
  PIN a[578]
    DIRECTION INPUT ;
    USE SIGNAL ;
    PORT
      LAYER M5 ;
        RECT  43.728 105.732 43.752 105.816 ;
    END
  END a[578]
  PIN a[579]
    DIRECTION INPUT ;
    USE SIGNAL ;
    PORT
      LAYER M5 ;
        RECT  43.824 105.732 43.848 105.816 ;
    END
  END a[579]
  PIN a[57]
    DIRECTION INPUT ;
    USE SIGNAL ;
    PORT
      LAYER M3 ;
        RECT  59.868 105.779 59.886 105.816 ;
    END
  END a[57]
  PIN a[580]
    DIRECTION INPUT ;
    USE SIGNAL ;
    PORT
      LAYER M5 ;
        RECT  43.92 105.732 43.944 105.816 ;
    END
  END a[580]
  PIN a[581]
    DIRECTION INPUT ;
    USE SIGNAL ;
    PORT
      LAYER M5 ;
        RECT  44.016 105.732 44.04 105.816 ;
    END
  END a[581]
  PIN a[582]
    DIRECTION INPUT ;
    USE SIGNAL ;
    PORT
      LAYER M5 ;
        RECT  44.112 105.732 44.136 105.816 ;
    END
  END a[582]
  PIN a[583]
    DIRECTION INPUT ;
    USE SIGNAL ;
    PORT
      LAYER M5 ;
        RECT  44.208 105.732 44.232 105.816 ;
    END
  END a[583]
  PIN a[584]
    DIRECTION INPUT ;
    USE SIGNAL ;
    PORT
      LAYER M5 ;
        RECT  44.304 105.732 44.328 105.816 ;
    END
  END a[584]
  PIN a[585]
    DIRECTION INPUT ;
    USE SIGNAL ;
    PORT
      LAYER M5 ;
        RECT  44.4 105.732 44.424 105.816 ;
    END
  END a[585]
  PIN a[586]
    DIRECTION INPUT ;
    USE SIGNAL ;
    PORT
      LAYER M5 ;
        RECT  44.496 105.732 44.52 105.816 ;
    END
  END a[586]
  PIN a[587]
    DIRECTION INPUT ;
    USE SIGNAL ;
    PORT
      LAYER M5 ;
        RECT  44.592 105.732 44.616 105.816 ;
    END
  END a[587]
  PIN a[588]
    DIRECTION INPUT ;
    USE SIGNAL ;
    PORT
      LAYER M5 ;
        RECT  44.688 105.732 44.712 105.816 ;
    END
  END a[588]
  PIN a[589]
    DIRECTION INPUT ;
    USE SIGNAL ;
    PORT
      LAYER M5 ;
        RECT  44.784 105.732 44.808 105.816 ;
    END
  END a[589]
  PIN a[58]
    DIRECTION INPUT ;
    USE SIGNAL ;
    PORT
      LAYER M3 ;
        RECT  59.94 105.779 59.958 105.816 ;
    END
  END a[58]
  PIN a[590]
    DIRECTION INPUT ;
    USE SIGNAL ;
    PORT
      LAYER M5 ;
        RECT  44.88 105.732 44.904 105.816 ;
    END
  END a[590]
  PIN a[591]
    DIRECTION INPUT ;
    USE SIGNAL ;
    PORT
      LAYER M5 ;
        RECT  44.976 105.732 45 105.816 ;
    END
  END a[591]
  PIN a[592]
    DIRECTION INPUT ;
    USE SIGNAL ;
    PORT
      LAYER M5 ;
        RECT  45.072 105.732 45.096 105.816 ;
    END
  END a[592]
  PIN a[593]
    DIRECTION INPUT ;
    USE SIGNAL ;
    PORT
      LAYER M5 ;
        RECT  45.168 105.732 45.192 105.816 ;
    END
  END a[593]
  PIN a[594]
    DIRECTION INPUT ;
    USE SIGNAL ;
    PORT
      LAYER M5 ;
        RECT  45.264 105.732 45.288 105.816 ;
    END
  END a[594]
  PIN a[595]
    DIRECTION INPUT ;
    USE SIGNAL ;
    PORT
      LAYER M5 ;
        RECT  45.36 105.732 45.384 105.816 ;
    END
  END a[595]
  PIN a[596]
    DIRECTION INPUT ;
    USE SIGNAL ;
    PORT
      LAYER M5 ;
        RECT  45.456 105.732 45.48 105.816 ;
    END
  END a[596]
  PIN a[597]
    DIRECTION INPUT ;
    USE SIGNAL ;
    PORT
      LAYER M5 ;
        RECT  45.552 105.732 45.576 105.816 ;
    END
  END a[597]
  PIN a[598]
    DIRECTION INPUT ;
    USE SIGNAL ;
    PORT
      LAYER M5 ;
        RECT  45.648 105.732 45.672 105.816 ;
    END
  END a[598]
  PIN a[599]
    DIRECTION INPUT ;
    USE SIGNAL ;
    PORT
      LAYER M5 ;
        RECT  45.744 105.732 45.768 105.816 ;
    END
  END a[599]
  PIN a[59]
    DIRECTION INPUT ;
    USE SIGNAL ;
    PORT
      LAYER M3 ;
        RECT  60.012 105.779 60.03 105.816 ;
    END
  END a[59]
  PIN a[5]
    DIRECTION INPUT ;
    USE SIGNAL ;
    PORT
      LAYER M3 ;
        RECT  49.212 105.779 49.23 105.816 ;
    END
  END a[5]
  PIN a[60]
    DIRECTION INPUT ;
    USE SIGNAL ;
    PORT
      LAYER M3 ;
        RECT  60.084 105.779 60.102 105.816 ;
    END
  END a[60]
  PIN a[61]
    DIRECTION INPUT ;
    USE SIGNAL ;
    PORT
      LAYER M3 ;
        RECT  60.156 105.779 60.174 105.816 ;
    END
  END a[61]
  PIN a[62]
    DIRECTION INPUT ;
    USE SIGNAL ;
    PORT
      LAYER M3 ;
        RECT  60.228 105.779 60.246 105.816 ;
    END
  END a[62]
  PIN a[63]
    DIRECTION INPUT ;
    USE SIGNAL ;
    PORT
      LAYER M3 ;
        RECT  60.3 105.779 60.318 105.816 ;
    END
  END a[63]
  PIN a[64]
    DIRECTION INPUT ;
    USE SIGNAL ;
    PORT
      LAYER M3 ;
        RECT  46.548 105.779 46.566 105.816 ;
    END
  END a[64]
  PIN a[65]
    DIRECTION INPUT ;
    USE SIGNAL ;
    PORT
      LAYER M3 ;
        RECT  46.62 105.779 46.638 105.816 ;
    END
  END a[65]
  PIN a[66]
    DIRECTION INPUT ;
    USE SIGNAL ;
    PORT
      LAYER M3 ;
        RECT  46.692 105.779 46.71 105.816 ;
    END
  END a[66]
  PIN a[67]
    DIRECTION INPUT ;
    USE SIGNAL ;
    PORT
      LAYER M3 ;
        RECT  46.764 105.779 46.782 105.816 ;
    END
  END a[67]
  PIN a[68]
    DIRECTION INPUT ;
    USE SIGNAL ;
    PORT
      LAYER M3 ;
        RECT  46.836 105.779 46.854 105.816 ;
    END
  END a[68]
  PIN a[69]
    DIRECTION INPUT ;
    USE SIGNAL ;
    PORT
      LAYER M3 ;
        RECT  46.908 105.779 46.926 105.816 ;
    END
  END a[69]
  PIN a[6]
    DIRECTION INPUT ;
    USE SIGNAL ;
    PORT
      LAYER M3 ;
        RECT  49.284 105.779 49.302 105.816 ;
    END
  END a[6]
  PIN a[70]
    DIRECTION INPUT ;
    USE SIGNAL ;
    PORT
      LAYER M3 ;
        RECT  46.98 105.779 46.998 105.816 ;
    END
  END a[70]
  PIN a[71]
    DIRECTION INPUT ;
    USE SIGNAL ;
    PORT
      LAYER M3 ;
        RECT  47.052 105.779 47.07 105.816 ;
    END
  END a[71]
  PIN a[72]
    DIRECTION INPUT ;
    USE SIGNAL ;
    PORT
      LAYER M3 ;
        RECT  47.124 105.779 47.142 105.816 ;
    END
  END a[72]
  PIN a[73]
    DIRECTION INPUT ;
    USE SIGNAL ;
    PORT
      LAYER M3 ;
        RECT  47.196 105.779 47.214 105.816 ;
    END
  END a[73]
  PIN a[74]
    DIRECTION INPUT ;
    USE SIGNAL ;
    PORT
      LAYER M3 ;
        RECT  47.268 105.779 47.286 105.816 ;
    END
  END a[74]
  PIN a[75]
    DIRECTION INPUT ;
    USE SIGNAL ;
    PORT
      LAYER M3 ;
        RECT  47.34 105.779 47.358 105.816 ;
    END
  END a[75]
  PIN a[76]
    DIRECTION INPUT ;
    USE SIGNAL ;
    PORT
      LAYER M3 ;
        RECT  47.412 105.779 47.43 105.816 ;
    END
  END a[76]
  PIN a[77]
    DIRECTION INPUT ;
    USE SIGNAL ;
    PORT
      LAYER M3 ;
        RECT  47.484 105.779 47.502 105.816 ;
    END
  END a[77]
  PIN a[78]
    DIRECTION INPUT ;
    USE SIGNAL ;
    PORT
      LAYER M3 ;
        RECT  47.556 105.779 47.574 105.816 ;
    END
  END a[78]
  PIN a[79]
    DIRECTION INPUT ;
    USE SIGNAL ;
    PORT
      LAYER M3 ;
        RECT  47.628 105.779 47.646 105.816 ;
    END
  END a[79]
  PIN a[7]
    DIRECTION INPUT ;
    USE SIGNAL ;
    PORT
      LAYER M3 ;
        RECT  49.356 105.779 49.374 105.816 ;
    END
  END a[7]
  PIN a[80]
    DIRECTION INPUT ;
    USE SIGNAL ;
    PORT
      LAYER M3 ;
        RECT  47.7 105.779 47.718 105.816 ;
    END
  END a[80]
  PIN a[81]
    DIRECTION INPUT ;
    USE SIGNAL ;
    PORT
      LAYER M3 ;
        RECT  47.772 105.779 47.79 105.816 ;
    END
  END a[81]
  PIN a[82]
    DIRECTION INPUT ;
    USE SIGNAL ;
    PORT
      LAYER M3 ;
        RECT  47.844 105.779 47.862 105.816 ;
    END
  END a[82]
  PIN a[83]
    DIRECTION INPUT ;
    USE SIGNAL ;
    PORT
      LAYER M3 ;
        RECT  47.916 105.779 47.934 105.816 ;
    END
  END a[83]
  PIN a[84]
    DIRECTION INPUT ;
    USE SIGNAL ;
    PORT
      LAYER M3 ;
        RECT  47.988 105.779 48.006 105.816 ;
    END
  END a[84]
  PIN a[85]
    DIRECTION INPUT ;
    USE SIGNAL ;
    PORT
      LAYER M3 ;
        RECT  48.06 105.779 48.078 105.816 ;
    END
  END a[85]
  PIN a[86]
    DIRECTION INPUT ;
    USE SIGNAL ;
    PORT
      LAYER M3 ;
        RECT  48.132 105.779 48.15 105.816 ;
    END
  END a[86]
  PIN a[87]
    DIRECTION INPUT ;
    USE SIGNAL ;
    PORT
      LAYER M3 ;
        RECT  48.204 105.779 48.222 105.816 ;
    END
  END a[87]
  PIN a[88]
    DIRECTION INPUT ;
    USE SIGNAL ;
    PORT
      LAYER M3 ;
        RECT  48.276 105.779 48.294 105.816 ;
    END
  END a[88]
  PIN a[89]
    DIRECTION INPUT ;
    USE SIGNAL ;
    PORT
      LAYER M3 ;
        RECT  48.348 105.779 48.366 105.816 ;
    END
  END a[89]
  PIN a[8]
    DIRECTION INPUT ;
    USE SIGNAL ;
    PORT
      LAYER M3 ;
        RECT  49.428 105.779 49.446 105.816 ;
    END
  END a[8]
  PIN a[90]
    DIRECTION INPUT ;
    USE SIGNAL ;
    PORT
      LAYER M3 ;
        RECT  48.42 105.779 48.438 105.816 ;
    END
  END a[90]
  PIN a[91]
    DIRECTION INPUT ;
    USE SIGNAL ;
    PORT
      LAYER M3 ;
        RECT  48.492 105.779 48.51 105.816 ;
    END
  END a[91]
  PIN a[92]
    DIRECTION INPUT ;
    USE SIGNAL ;
    PORT
      LAYER M3 ;
        RECT  48.564 105.779 48.582 105.816 ;
    END
  END a[92]
  PIN a[93]
    DIRECTION INPUT ;
    USE SIGNAL ;
    PORT
      LAYER M3 ;
        RECT  48.636 105.779 48.654 105.816 ;
    END
  END a[93]
  PIN a[94]
    DIRECTION INPUT ;
    USE SIGNAL ;
    PORT
      LAYER M3 ;
        RECT  48.708 105.779 48.726 105.816 ;
    END
  END a[94]
  PIN a[95]
    DIRECTION INPUT ;
    USE SIGNAL ;
    PORT
      LAYER M3 ;
        RECT  48.78 105.779 48.798 105.816 ;
    END
  END a[95]
  PIN a[96]
    DIRECTION INPUT ;
    USE SIGNAL ;
    PORT
      LAYER M3 ;
        RECT  53.46 105.779 53.478 105.816 ;
    END
  END a[96]
  PIN a[97]
    DIRECTION INPUT ;
    USE SIGNAL ;
    PORT
      LAYER M3 ;
        RECT  53.532 105.779 53.55 105.816 ;
    END
  END a[97]
  PIN a[98]
    DIRECTION INPUT ;
    USE SIGNAL ;
    PORT
      LAYER M3 ;
        RECT  53.604 105.779 53.622 105.816 ;
    END
  END a[98]
  PIN a[99]
    DIRECTION INPUT ;
    USE SIGNAL ;
    PORT
      LAYER M3 ;
        RECT  53.676 105.779 53.694 105.816 ;
    END
  END a[99]
  PIN a[9]
    DIRECTION INPUT ;
    USE SIGNAL ;
    PORT
      LAYER M3 ;
        RECT  49.5 105.779 49.518 105.816 ;
    END
  END a[9]
  PIN b[0]
    DIRECTION OUTPUT ;
    USE SIGNAL ;
    PORT
      LAYER M4 ;
        RECT  104.004 42.192 104.088 42.216 ;
    END
  END b[0]
  PIN b[100]
    DIRECTION OUTPUT ;
    USE SIGNAL ;
    PORT
      LAYER M4 ;
        RECT  104.004 48.72 104.088 48.744 ;
    END
  END b[100]
  PIN b[101]
    DIRECTION OUTPUT ;
    USE SIGNAL ;
    PORT
      LAYER M4 ;
        RECT  104.004 48.816 104.088 48.84 ;
    END
  END b[101]
  PIN b[102]
    DIRECTION OUTPUT ;
    USE SIGNAL ;
    PORT
      LAYER M4 ;
        RECT  104.004 48.912 104.088 48.936 ;
    END
  END b[102]
  PIN b[103]
    DIRECTION OUTPUT ;
    USE SIGNAL ;
    PORT
      LAYER M4 ;
        RECT  104.004 49.008 104.088 49.032 ;
    END
  END b[103]
  PIN b[104]
    DIRECTION OUTPUT ;
    USE SIGNAL ;
    PORT
      LAYER M4 ;
        RECT  104.004 49.104 104.088 49.128 ;
    END
  END b[104]
  PIN b[105]
    DIRECTION OUTPUT ;
    USE SIGNAL ;
    PORT
      LAYER M4 ;
        RECT  104.004 49.2 104.088 49.224 ;
    END
  END b[105]
  PIN b[106]
    DIRECTION OUTPUT ;
    USE SIGNAL ;
    PORT
      LAYER M4 ;
        RECT  104.004 49.296 104.088 49.32 ;
    END
  END b[106]
  PIN b[107]
    DIRECTION OUTPUT ;
    USE SIGNAL ;
    PORT
      LAYER M4 ;
        RECT  104.004 49.392 104.088 49.416 ;
    END
  END b[107]
  PIN b[108]
    DIRECTION OUTPUT ;
    USE SIGNAL ;
    PORT
      LAYER M4 ;
        RECT  104.004 49.488 104.088 49.512 ;
    END
  END b[108]
  PIN b[109]
    DIRECTION OUTPUT ;
    USE SIGNAL ;
    PORT
      LAYER M4 ;
        RECT  104.004 49.584 104.088 49.608 ;
    END
  END b[109]
  PIN b[10]
    DIRECTION OUTPUT ;
    USE SIGNAL ;
    PORT
      LAYER M4 ;
        RECT  104.004 43.152 104.088 43.176 ;
    END
  END b[10]
  PIN b[110]
    DIRECTION OUTPUT ;
    USE SIGNAL ;
    PORT
      LAYER M4 ;
        RECT  104.004 49.68 104.088 49.704 ;
    END
  END b[110]
  PIN b[111]
    DIRECTION OUTPUT ;
    USE SIGNAL ;
    PORT
      LAYER M4 ;
        RECT  104.004 49.776 104.088 49.8 ;
    END
  END b[111]
  PIN b[112]
    DIRECTION OUTPUT ;
    USE SIGNAL ;
    PORT
      LAYER M4 ;
        RECT  104.004 49.872 104.088 49.896 ;
    END
  END b[112]
  PIN b[113]
    DIRECTION OUTPUT ;
    USE SIGNAL ;
    PORT
      LAYER M4 ;
        RECT  104.004 49.968 104.088 49.992 ;
    END
  END b[113]
  PIN b[114]
    DIRECTION OUTPUT ;
    USE SIGNAL ;
    PORT
      LAYER M4 ;
        RECT  104.004 50.064 104.088 50.088 ;
    END
  END b[114]
  PIN b[115]
    DIRECTION OUTPUT ;
    USE SIGNAL ;
    PORT
      LAYER M4 ;
        RECT  104.004 50.16 104.088 50.184 ;
    END
  END b[115]
  PIN b[116]
    DIRECTION OUTPUT ;
    USE SIGNAL ;
    PORT
      LAYER M4 ;
        RECT  104.004 50.256 104.088 50.28 ;
    END
  END b[116]
  PIN b[117]
    DIRECTION OUTPUT ;
    USE SIGNAL ;
    PORT
      LAYER M4 ;
        RECT  104.004 50.352 104.088 50.376 ;
    END
  END b[117]
  PIN b[118]
    DIRECTION OUTPUT ;
    USE SIGNAL ;
    PORT
      LAYER M4 ;
        RECT  104.004 50.448 104.088 50.472 ;
    END
  END b[118]
  PIN b[119]
    DIRECTION OUTPUT ;
    USE SIGNAL ;
    PORT
      LAYER M4 ;
        RECT  104.004 50.544 104.088 50.568 ;
    END
  END b[119]
  PIN b[11]
    DIRECTION OUTPUT ;
    USE SIGNAL ;
    PORT
      LAYER M4 ;
        RECT  104.004 43.248 104.088 43.272 ;
    END
  END b[11]
  PIN b[120]
    DIRECTION OUTPUT ;
    USE SIGNAL ;
    PORT
      LAYER M4 ;
        RECT  104.004 50.64 104.088 50.664 ;
    END
  END b[120]
  PIN b[121]
    DIRECTION OUTPUT ;
    USE SIGNAL ;
    PORT
      LAYER M4 ;
        RECT  104.004 50.736 104.088 50.76 ;
    END
  END b[121]
  PIN b[122]
    DIRECTION OUTPUT ;
    USE SIGNAL ;
    PORT
      LAYER M4 ;
        RECT  104.004 50.832 104.088 50.856 ;
    END
  END b[122]
  PIN b[123]
    DIRECTION OUTPUT ;
    USE SIGNAL ;
    PORT
      LAYER M4 ;
        RECT  104.004 50.928 104.088 50.952 ;
    END
  END b[123]
  PIN b[124]
    DIRECTION OUTPUT ;
    USE SIGNAL ;
    PORT
      LAYER M4 ;
        RECT  104.004 51.024 104.088 51.048 ;
    END
  END b[124]
  PIN b[125]
    DIRECTION OUTPUT ;
    USE SIGNAL ;
    PORT
      LAYER M4 ;
        RECT  104.004 51.12 104.088 51.144 ;
    END
  END b[125]
  PIN b[126]
    DIRECTION OUTPUT ;
    USE SIGNAL ;
    PORT
      LAYER M4 ;
        RECT  104.004 51.216 104.088 51.24 ;
    END
  END b[126]
  PIN b[127]
    DIRECTION OUTPUT ;
    USE SIGNAL ;
    PORT
      LAYER M4 ;
        RECT  104.004 51.312 104.088 51.336 ;
    END
  END b[127]
  PIN b[128]
    DIRECTION OUTPUT ;
    USE SIGNAL ;
    PORT
      LAYER M4 ;
        RECT  104.004 51.408 104.088 51.432 ;
    END
  END b[128]
  PIN b[129]
    DIRECTION OUTPUT ;
    USE SIGNAL ;
    PORT
      LAYER M4 ;
        RECT  104.004 51.504 104.088 51.528 ;
    END
  END b[129]
  PIN b[12]
    DIRECTION OUTPUT ;
    USE SIGNAL ;
    PORT
      LAYER M4 ;
        RECT  104.004 43.344 104.088 43.368 ;
    END
  END b[12]
  PIN b[130]
    DIRECTION OUTPUT ;
    USE SIGNAL ;
    PORT
      LAYER M4 ;
        RECT  104.004 51.6 104.088 51.624 ;
    END
  END b[130]
  PIN b[131]
    DIRECTION OUTPUT ;
    USE SIGNAL ;
    PORT
      LAYER M4 ;
        RECT  104.004 51.696 104.088 51.72 ;
    END
  END b[131]
  PIN b[132]
    DIRECTION OUTPUT ;
    USE SIGNAL ;
    PORT
      LAYER M4 ;
        RECT  104.004 51.792 104.088 51.816 ;
    END
  END b[132]
  PIN b[133]
    DIRECTION OUTPUT ;
    USE SIGNAL ;
    PORT
      LAYER M4 ;
        RECT  104.004 51.888 104.088 51.912 ;
    END
  END b[133]
  PIN b[134]
    DIRECTION OUTPUT ;
    USE SIGNAL ;
    PORT
      LAYER M4 ;
        RECT  104.004 51.984 104.088 52.008 ;
    END
  END b[134]
  PIN b[135]
    DIRECTION OUTPUT ;
    USE SIGNAL ;
    PORT
      LAYER M4 ;
        RECT  104.004 52.08 104.088 52.104 ;
    END
  END b[135]
  PIN b[136]
    DIRECTION OUTPUT ;
    USE SIGNAL ;
    PORT
      LAYER M4 ;
        RECT  104.004 52.176 104.088 52.2 ;
    END
  END b[136]
  PIN b[137]
    DIRECTION OUTPUT ;
    USE SIGNAL ;
    PORT
      LAYER M4 ;
        RECT  104.004 52.272 104.088 52.296 ;
    END
  END b[137]
  PIN b[138]
    DIRECTION OUTPUT ;
    USE SIGNAL ;
    PORT
      LAYER M4 ;
        RECT  104.004 52.368 104.088 52.392 ;
    END
  END b[138]
  PIN b[139]
    DIRECTION OUTPUT ;
    USE SIGNAL ;
    PORT
      LAYER M4 ;
        RECT  104.004 52.464 104.088 52.488 ;
    END
  END b[139]
  PIN b[13]
    DIRECTION OUTPUT ;
    USE SIGNAL ;
    PORT
      LAYER M4 ;
        RECT  104.004 43.44 104.088 43.464 ;
    END
  END b[13]
  PIN b[140]
    DIRECTION OUTPUT ;
    USE SIGNAL ;
    PORT
      LAYER M4 ;
        RECT  104.004 52.56 104.088 52.584 ;
    END
  END b[140]
  PIN b[141]
    DIRECTION OUTPUT ;
    USE SIGNAL ;
    PORT
      LAYER M4 ;
        RECT  104.004 52.656 104.088 52.68 ;
    END
  END b[141]
  PIN b[142]
    DIRECTION OUTPUT ;
    USE SIGNAL ;
    PORT
      LAYER M4 ;
        RECT  104.004 52.752 104.088 52.776 ;
    END
  END b[142]
  PIN b[143]
    DIRECTION OUTPUT ;
    USE SIGNAL ;
    PORT
      LAYER M4 ;
        RECT  104.004 52.848 104.088 52.872 ;
    END
  END b[143]
  PIN b[144]
    DIRECTION OUTPUT ;
    USE SIGNAL ;
    PORT
      LAYER M4 ;
        RECT  104.004 52.944 104.088 52.968 ;
    END
  END b[144]
  PIN b[145]
    DIRECTION OUTPUT ;
    USE SIGNAL ;
    PORT
      LAYER M4 ;
        RECT  104.004 53.04 104.088 53.064 ;
    END
  END b[145]
  PIN b[146]
    DIRECTION OUTPUT ;
    USE SIGNAL ;
    PORT
      LAYER M4 ;
        RECT  104.004 53.136 104.088 53.16 ;
    END
  END b[146]
  PIN b[147]
    DIRECTION OUTPUT ;
    USE SIGNAL ;
    PORT
      LAYER M4 ;
        RECT  104.004 53.232 104.088 53.256 ;
    END
  END b[147]
  PIN b[148]
    DIRECTION OUTPUT ;
    USE SIGNAL ;
    PORT
      LAYER M4 ;
        RECT  104.004 53.328 104.088 53.352 ;
    END
  END b[148]
  PIN b[149]
    DIRECTION OUTPUT ;
    USE SIGNAL ;
    PORT
      LAYER M4 ;
        RECT  104.004 53.424 104.088 53.448 ;
    END
  END b[149]
  PIN b[14]
    DIRECTION OUTPUT ;
    USE SIGNAL ;
    PORT
      LAYER M4 ;
        RECT  104.004 43.536 104.088 43.56 ;
    END
  END b[14]
  PIN b[150]
    DIRECTION OUTPUT ;
    USE SIGNAL ;
    PORT
      LAYER M4 ;
        RECT  104.004 53.52 104.088 53.544 ;
    END
  END b[150]
  PIN b[151]
    DIRECTION OUTPUT ;
    USE SIGNAL ;
    PORT
      LAYER M4 ;
        RECT  104.004 53.616 104.088 53.64 ;
    END
  END b[151]
  PIN b[152]
    DIRECTION OUTPUT ;
    USE SIGNAL ;
    PORT
      LAYER M4 ;
        RECT  104.004 53.712 104.088 53.736 ;
    END
  END b[152]
  PIN b[153]
    DIRECTION OUTPUT ;
    USE SIGNAL ;
    PORT
      LAYER M4 ;
        RECT  104.004 53.808 104.088 53.832 ;
    END
  END b[153]
  PIN b[154]
    DIRECTION OUTPUT ;
    USE SIGNAL ;
    PORT
      LAYER M4 ;
        RECT  104.004 53.904 104.088 53.928 ;
    END
  END b[154]
  PIN b[155]
    DIRECTION OUTPUT ;
    USE SIGNAL ;
    PORT
      LAYER M4 ;
        RECT  104.004 54 104.088 54.024 ;
    END
  END b[155]
  PIN b[156]
    DIRECTION OUTPUT ;
    USE SIGNAL ;
    PORT
      LAYER M4 ;
        RECT  104.004 54.096 104.088 54.12 ;
    END
  END b[156]
  PIN b[157]
    DIRECTION OUTPUT ;
    USE SIGNAL ;
    PORT
      LAYER M4 ;
        RECT  104.004 54.192 104.088 54.216 ;
    END
  END b[157]
  PIN b[158]
    DIRECTION OUTPUT ;
    USE SIGNAL ;
    PORT
      LAYER M4 ;
        RECT  104.004 54.288 104.088 54.312 ;
    END
  END b[158]
  PIN b[159]
    DIRECTION OUTPUT ;
    USE SIGNAL ;
    PORT
      LAYER M4 ;
        RECT  104.004 54.384 104.088 54.408 ;
    END
  END b[159]
  PIN b[15]
    DIRECTION OUTPUT ;
    USE SIGNAL ;
    PORT
      LAYER M4 ;
        RECT  104.004 43.632 104.088 43.656 ;
    END
  END b[15]
  PIN b[160]
    DIRECTION OUTPUT ;
    USE SIGNAL ;
    PORT
      LAYER M4 ;
        RECT  104.004 45.264 104.088 45.288 ;
    END
  END b[160]
  PIN b[161]
    DIRECTION OUTPUT ;
    USE SIGNAL ;
    PORT
      LAYER M4 ;
        RECT  104.004 45.36 104.088 45.384 ;
    END
  END b[161]
  PIN b[162]
    DIRECTION OUTPUT ;
    USE SIGNAL ;
    PORT
      LAYER M4 ;
        RECT  104.004 45.456 104.088 45.48 ;
    END
  END b[162]
  PIN b[163]
    DIRECTION OUTPUT ;
    USE SIGNAL ;
    PORT
      LAYER M4 ;
        RECT  104.004 45.552 104.088 45.576 ;
    END
  END b[163]
  PIN b[164]
    DIRECTION OUTPUT ;
    USE SIGNAL ;
    PORT
      LAYER M4 ;
        RECT  104.004 45.648 104.088 45.672 ;
    END
  END b[164]
  PIN b[165]
    DIRECTION OUTPUT ;
    USE SIGNAL ;
    PORT
      LAYER M4 ;
        RECT  104.004 45.744 104.088 45.768 ;
    END
  END b[165]
  PIN b[166]
    DIRECTION OUTPUT ;
    USE SIGNAL ;
    PORT
      LAYER M4 ;
        RECT  104.004 45.84 104.088 45.864 ;
    END
  END b[166]
  PIN b[167]
    DIRECTION OUTPUT ;
    USE SIGNAL ;
    PORT
      LAYER M4 ;
        RECT  104.004 45.936 104.088 45.96 ;
    END
  END b[167]
  PIN b[168]
    DIRECTION OUTPUT ;
    USE SIGNAL ;
    PORT
      LAYER M4 ;
        RECT  104.004 46.032 104.088 46.056 ;
    END
  END b[168]
  PIN b[169]
    DIRECTION OUTPUT ;
    USE SIGNAL ;
    PORT
      LAYER M4 ;
        RECT  104.004 46.128 104.088 46.152 ;
    END
  END b[169]
  PIN b[16]
    DIRECTION OUTPUT ;
    USE SIGNAL ;
    PORT
      LAYER M4 ;
        RECT  104.004 43.728 104.088 43.752 ;
    END
  END b[16]
  PIN b[170]
    DIRECTION OUTPUT ;
    USE SIGNAL ;
    PORT
      LAYER M4 ;
        RECT  104.004 46.224 104.088 46.248 ;
    END
  END b[170]
  PIN b[171]
    DIRECTION OUTPUT ;
    USE SIGNAL ;
    PORT
      LAYER M4 ;
        RECT  104.004 46.32 104.088 46.344 ;
    END
  END b[171]
  PIN b[172]
    DIRECTION OUTPUT ;
    USE SIGNAL ;
    PORT
      LAYER M4 ;
        RECT  104.004 46.416 104.088 46.44 ;
    END
  END b[172]
  PIN b[173]
    DIRECTION OUTPUT ;
    USE SIGNAL ;
    PORT
      LAYER M4 ;
        RECT  104.004 46.512 104.088 46.536 ;
    END
  END b[173]
  PIN b[174]
    DIRECTION OUTPUT ;
    USE SIGNAL ;
    PORT
      LAYER M4 ;
        RECT  104.004 46.608 104.088 46.632 ;
    END
  END b[174]
  PIN b[175]
    DIRECTION OUTPUT ;
    USE SIGNAL ;
    PORT
      LAYER M4 ;
        RECT  104.004 46.704 104.088 46.728 ;
    END
  END b[175]
  PIN b[176]
    DIRECTION OUTPUT ;
    USE SIGNAL ;
    PORT
      LAYER M4 ;
        RECT  104.004 46.8 104.088 46.824 ;
    END
  END b[176]
  PIN b[177]
    DIRECTION OUTPUT ;
    USE SIGNAL ;
    PORT
      LAYER M4 ;
        RECT  104.004 46.896 104.088 46.92 ;
    END
  END b[177]
  PIN b[178]
    DIRECTION OUTPUT ;
    USE SIGNAL ;
    PORT
      LAYER M4 ;
        RECT  104.004 46.992 104.088 47.016 ;
    END
  END b[178]
  PIN b[179]
    DIRECTION OUTPUT ;
    USE SIGNAL ;
    PORT
      LAYER M4 ;
        RECT  104.004 47.088 104.088 47.112 ;
    END
  END b[179]
  PIN b[17]
    DIRECTION OUTPUT ;
    USE SIGNAL ;
    PORT
      LAYER M4 ;
        RECT  104.004 43.824 104.088 43.848 ;
    END
  END b[17]
  PIN b[180]
    DIRECTION OUTPUT ;
    USE SIGNAL ;
    PORT
      LAYER M4 ;
        RECT  104.004 47.184 104.088 47.208 ;
    END
  END b[180]
  PIN b[181]
    DIRECTION OUTPUT ;
    USE SIGNAL ;
    PORT
      LAYER M4 ;
        RECT  104.004 47.28 104.088 47.304 ;
    END
  END b[181]
  PIN b[182]
    DIRECTION OUTPUT ;
    USE SIGNAL ;
    PORT
      LAYER M4 ;
        RECT  104.004 47.376 104.088 47.4 ;
    END
  END b[182]
  PIN b[183]
    DIRECTION OUTPUT ;
    USE SIGNAL ;
    PORT
      LAYER M4 ;
        RECT  104.004 47.472 104.088 47.496 ;
    END
  END b[183]
  PIN b[184]
    DIRECTION OUTPUT ;
    USE SIGNAL ;
    PORT
      LAYER M4 ;
        RECT  104.004 47.568 104.088 47.592 ;
    END
  END b[184]
  PIN b[185]
    DIRECTION OUTPUT ;
    USE SIGNAL ;
    PORT
      LAYER M4 ;
        RECT  104.004 47.664 104.088 47.688 ;
    END
  END b[185]
  PIN b[186]
    DIRECTION OUTPUT ;
    USE SIGNAL ;
    PORT
      LAYER M4 ;
        RECT  104.004 47.76 104.088 47.784 ;
    END
  END b[186]
  PIN b[187]
    DIRECTION OUTPUT ;
    USE SIGNAL ;
    PORT
      LAYER M4 ;
        RECT  104.004 47.856 104.088 47.88 ;
    END
  END b[187]
  PIN b[188]
    DIRECTION OUTPUT ;
    USE SIGNAL ;
    PORT
      LAYER M4 ;
        RECT  104.004 47.952 104.088 47.976 ;
    END
  END b[188]
  PIN b[189]
    DIRECTION OUTPUT ;
    USE SIGNAL ;
    PORT
      LAYER M4 ;
        RECT  104.004 48.048 104.088 48.072 ;
    END
  END b[189]
  PIN b[18]
    DIRECTION OUTPUT ;
    USE SIGNAL ;
    PORT
      LAYER M4 ;
        RECT  104.004 43.92 104.088 43.944 ;
    END
  END b[18]
  PIN b[190]
    DIRECTION OUTPUT ;
    USE SIGNAL ;
    PORT
      LAYER M4 ;
        RECT  104.004 48.144 104.088 48.168 ;
    END
  END b[190]
  PIN b[191]
    DIRECTION OUTPUT ;
    USE SIGNAL ;
    PORT
      LAYER M4 ;
        RECT  104.004 48.24 104.088 48.264 ;
    END
  END b[191]
  PIN b[192]
    DIRECTION OUTPUT ;
    USE SIGNAL ;
    PORT
      LAYER M4 ;
        RECT  104.004 73.68 104.088 73.704 ;
    END
  END b[192]
  PIN b[193]
    DIRECTION OUTPUT ;
    USE SIGNAL ;
    PORT
      LAYER M4 ;
        RECT  104.004 73.776 104.088 73.8 ;
    END
  END b[193]
  PIN b[194]
    DIRECTION OUTPUT ;
    USE SIGNAL ;
    PORT
      LAYER M4 ;
        RECT  104.004 73.872 104.088 73.896 ;
    END
  END b[194]
  PIN b[195]
    DIRECTION OUTPUT ;
    USE SIGNAL ;
    PORT
      LAYER M4 ;
        RECT  104.004 73.968 104.088 73.992 ;
    END
  END b[195]
  PIN b[196]
    DIRECTION OUTPUT ;
    USE SIGNAL ;
    PORT
      LAYER M4 ;
        RECT  104.004 74.064 104.088 74.088 ;
    END
  END b[196]
  PIN b[197]
    DIRECTION OUTPUT ;
    USE SIGNAL ;
    PORT
      LAYER M4 ;
        RECT  104.004 74.16 104.088 74.184 ;
    END
  END b[197]
  PIN b[198]
    DIRECTION OUTPUT ;
    USE SIGNAL ;
    PORT
      LAYER M4 ;
        RECT  104.004 74.256 104.088 74.28 ;
    END
  END b[198]
  PIN b[199]
    DIRECTION OUTPUT ;
    USE SIGNAL ;
    PORT
      LAYER M4 ;
        RECT  104.004 74.352 104.088 74.376 ;
    END
  END b[199]
  PIN b[19]
    DIRECTION OUTPUT ;
    USE SIGNAL ;
    PORT
      LAYER M4 ;
        RECT  104.004 44.016 104.088 44.04 ;
    END
  END b[19]
  PIN b[1]
    DIRECTION OUTPUT ;
    USE SIGNAL ;
    PORT
      LAYER M4 ;
        RECT  104.004 42.288 104.088 42.312 ;
    END
  END b[1]
  PIN b[200]
    DIRECTION OUTPUT ;
    USE SIGNAL ;
    PORT
      LAYER M4 ;
        RECT  104.004 74.448 104.088 74.472 ;
    END
  END b[200]
  PIN b[201]
    DIRECTION OUTPUT ;
    USE SIGNAL ;
    PORT
      LAYER M4 ;
        RECT  104.004 74.544 104.088 74.568 ;
    END
  END b[201]
  PIN b[202]
    DIRECTION OUTPUT ;
    USE SIGNAL ;
    PORT
      LAYER M4 ;
        RECT  104.004 74.64 104.088 74.664 ;
    END
  END b[202]
  PIN b[203]
    DIRECTION OUTPUT ;
    USE SIGNAL ;
    PORT
      LAYER M4 ;
        RECT  104.004 74.736 104.088 74.76 ;
    END
  END b[203]
  PIN b[204]
    DIRECTION OUTPUT ;
    USE SIGNAL ;
    PORT
      LAYER M4 ;
        RECT  104.004 74.832 104.088 74.856 ;
    END
  END b[204]
  PIN b[205]
    DIRECTION OUTPUT ;
    USE SIGNAL ;
    PORT
      LAYER M4 ;
        RECT  104.004 74.928 104.088 74.952 ;
    END
  END b[205]
  PIN b[206]
    DIRECTION OUTPUT ;
    USE SIGNAL ;
    PORT
      LAYER M4 ;
        RECT  104.004 75.024 104.088 75.048 ;
    END
  END b[206]
  PIN b[207]
    DIRECTION OUTPUT ;
    USE SIGNAL ;
    PORT
      LAYER M4 ;
        RECT  104.004 75.12 104.088 75.144 ;
    END
  END b[207]
  PIN b[208]
    DIRECTION OUTPUT ;
    USE SIGNAL ;
    PORT
      LAYER M4 ;
        RECT  104.004 75.216 104.088 75.24 ;
    END
  END b[208]
  PIN b[209]
    DIRECTION OUTPUT ;
    USE SIGNAL ;
    PORT
      LAYER M4 ;
        RECT  104.004 75.312 104.088 75.336 ;
    END
  END b[209]
  PIN b[20]
    DIRECTION OUTPUT ;
    USE SIGNAL ;
    PORT
      LAYER M4 ;
        RECT  104.004 44.112 104.088 44.136 ;
    END
  END b[20]
  PIN b[210]
    DIRECTION OUTPUT ;
    USE SIGNAL ;
    PORT
      LAYER M4 ;
        RECT  104.004 75.408 104.088 75.432 ;
    END
  END b[210]
  PIN b[211]
    DIRECTION OUTPUT ;
    USE SIGNAL ;
    PORT
      LAYER M4 ;
        RECT  104.004 75.504 104.088 75.528 ;
    END
  END b[211]
  PIN b[212]
    DIRECTION OUTPUT ;
    USE SIGNAL ;
    PORT
      LAYER M4 ;
        RECT  104.004 75.6 104.088 75.624 ;
    END
  END b[212]
  PIN b[213]
    DIRECTION OUTPUT ;
    USE SIGNAL ;
    PORT
      LAYER M4 ;
        RECT  104.004 75.696 104.088 75.72 ;
    END
  END b[213]
  PIN b[214]
    DIRECTION OUTPUT ;
    USE SIGNAL ;
    PORT
      LAYER M4 ;
        RECT  104.004 75.792 104.088 75.816 ;
    END
  END b[214]
  PIN b[215]
    DIRECTION OUTPUT ;
    USE SIGNAL ;
    PORT
      LAYER M4 ;
        RECT  104.004 75.888 104.088 75.912 ;
    END
  END b[215]
  PIN b[216]
    DIRECTION OUTPUT ;
    USE SIGNAL ;
    PORT
      LAYER M4 ;
        RECT  104.004 75.984 104.088 76.008 ;
    END
  END b[216]
  PIN b[217]
    DIRECTION OUTPUT ;
    USE SIGNAL ;
    PORT
      LAYER M4 ;
        RECT  104.004 76.08 104.088 76.104 ;
    END
  END b[217]
  PIN b[218]
    DIRECTION OUTPUT ;
    USE SIGNAL ;
    PORT
      LAYER M4 ;
        RECT  104.004 76.176 104.088 76.2 ;
    END
  END b[218]
  PIN b[219]
    DIRECTION OUTPUT ;
    USE SIGNAL ;
    PORT
      LAYER M4 ;
        RECT  104.004 76.272 104.088 76.296 ;
    END
  END b[219]
  PIN b[21]
    DIRECTION OUTPUT ;
    USE SIGNAL ;
    PORT
      LAYER M4 ;
        RECT  104.004 44.208 104.088 44.232 ;
    END
  END b[21]
  PIN b[220]
    DIRECTION OUTPUT ;
    USE SIGNAL ;
    PORT
      LAYER M4 ;
        RECT  104.004 76.368 104.088 76.392 ;
    END
  END b[220]
  PIN b[221]
    DIRECTION OUTPUT ;
    USE SIGNAL ;
    PORT
      LAYER M4 ;
        RECT  104.004 76.464 104.088 76.488 ;
    END
  END b[221]
  PIN b[222]
    DIRECTION OUTPUT ;
    USE SIGNAL ;
    PORT
      LAYER M4 ;
        RECT  104.004 76.56 104.088 76.584 ;
    END
  END b[222]
  PIN b[223]
    DIRECTION OUTPUT ;
    USE SIGNAL ;
    PORT
      LAYER M4 ;
        RECT  104.004 76.656 104.088 76.68 ;
    END
  END b[223]
  PIN b[224]
    DIRECTION OUTPUT ;
    USE SIGNAL ;
    PORT
      LAYER M4 ;
        RECT  104.004 58.32 104.088 58.344 ;
    END
  END b[224]
  PIN b[225]
    DIRECTION OUTPUT ;
    USE SIGNAL ;
    PORT
      LAYER M4 ;
        RECT  104.004 58.416 104.088 58.44 ;
    END
  END b[225]
  PIN b[226]
    DIRECTION OUTPUT ;
    USE SIGNAL ;
    PORT
      LAYER M4 ;
        RECT  104.004 58.512 104.088 58.536 ;
    END
  END b[226]
  PIN b[227]
    DIRECTION OUTPUT ;
    USE SIGNAL ;
    PORT
      LAYER M4 ;
        RECT  104.004 58.608 104.088 58.632 ;
    END
  END b[227]
  PIN b[228]
    DIRECTION OUTPUT ;
    USE SIGNAL ;
    PORT
      LAYER M4 ;
        RECT  104.004 58.704 104.088 58.728 ;
    END
  END b[228]
  PIN b[229]
    DIRECTION OUTPUT ;
    USE SIGNAL ;
    PORT
      LAYER M4 ;
        RECT  104.004 58.8 104.088 58.824 ;
    END
  END b[229]
  PIN b[22]
    DIRECTION OUTPUT ;
    USE SIGNAL ;
    PORT
      LAYER M4 ;
        RECT  104.004 44.304 104.088 44.328 ;
    END
  END b[22]
  PIN b[230]
    DIRECTION OUTPUT ;
    USE SIGNAL ;
    PORT
      LAYER M4 ;
        RECT  104.004 58.896 104.088 58.92 ;
    END
  END b[230]
  PIN b[231]
    DIRECTION OUTPUT ;
    USE SIGNAL ;
    PORT
      LAYER M4 ;
        RECT  104.004 58.992 104.088 59.016 ;
    END
  END b[231]
  PIN b[232]
    DIRECTION OUTPUT ;
    USE SIGNAL ;
    PORT
      LAYER M4 ;
        RECT  104.004 59.088 104.088 59.112 ;
    END
  END b[232]
  PIN b[233]
    DIRECTION OUTPUT ;
    USE SIGNAL ;
    PORT
      LAYER M4 ;
        RECT  104.004 59.184 104.088 59.208 ;
    END
  END b[233]
  PIN b[234]
    DIRECTION OUTPUT ;
    USE SIGNAL ;
    PORT
      LAYER M4 ;
        RECT  104.004 59.28 104.088 59.304 ;
    END
  END b[234]
  PIN b[235]
    DIRECTION OUTPUT ;
    USE SIGNAL ;
    PORT
      LAYER M4 ;
        RECT  104.004 59.376 104.088 59.4 ;
    END
  END b[235]
  PIN b[236]
    DIRECTION OUTPUT ;
    USE SIGNAL ;
    PORT
      LAYER M4 ;
        RECT  104.004 59.472 104.088 59.496 ;
    END
  END b[236]
  PIN b[237]
    DIRECTION OUTPUT ;
    USE SIGNAL ;
    PORT
      LAYER M4 ;
        RECT  104.004 59.568 104.088 59.592 ;
    END
  END b[237]
  PIN b[238]
    DIRECTION OUTPUT ;
    USE SIGNAL ;
    PORT
      LAYER M4 ;
        RECT  104.004 59.664 104.088 59.688 ;
    END
  END b[238]
  PIN b[239]
    DIRECTION OUTPUT ;
    USE SIGNAL ;
    PORT
      LAYER M4 ;
        RECT  104.004 59.76 104.088 59.784 ;
    END
  END b[239]
  PIN b[23]
    DIRECTION OUTPUT ;
    USE SIGNAL ;
    PORT
      LAYER M4 ;
        RECT  104.004 44.4 104.088 44.424 ;
    END
  END b[23]
  PIN b[240]
    DIRECTION OUTPUT ;
    USE SIGNAL ;
    PORT
      LAYER M4 ;
        RECT  104.004 59.856 104.088 59.88 ;
    END
  END b[240]
  PIN b[241]
    DIRECTION OUTPUT ;
    USE SIGNAL ;
    PORT
      LAYER M4 ;
        RECT  104.004 59.952 104.088 59.976 ;
    END
  END b[241]
  PIN b[242]
    DIRECTION OUTPUT ;
    USE SIGNAL ;
    PORT
      LAYER M4 ;
        RECT  104.004 60.048 104.088 60.072 ;
    END
  END b[242]
  PIN b[243]
    DIRECTION OUTPUT ;
    USE SIGNAL ;
    PORT
      LAYER M4 ;
        RECT  104.004 60.144 104.088 60.168 ;
    END
  END b[243]
  PIN b[244]
    DIRECTION OUTPUT ;
    USE SIGNAL ;
    PORT
      LAYER M4 ;
        RECT  104.004 60.24 104.088 60.264 ;
    END
  END b[244]
  PIN b[245]
    DIRECTION OUTPUT ;
    USE SIGNAL ;
    PORT
      LAYER M4 ;
        RECT  104.004 60.336 104.088 60.36 ;
    END
  END b[245]
  PIN b[246]
    DIRECTION OUTPUT ;
    USE SIGNAL ;
    PORT
      LAYER M4 ;
        RECT  104.004 60.432 104.088 60.456 ;
    END
  END b[246]
  PIN b[247]
    DIRECTION OUTPUT ;
    USE SIGNAL ;
    PORT
      LAYER M4 ;
        RECT  104.004 60.528 104.088 60.552 ;
    END
  END b[247]
  PIN b[248]
    DIRECTION OUTPUT ;
    USE SIGNAL ;
    PORT
      LAYER M4 ;
        RECT  104.004 60.624 104.088 60.648 ;
    END
  END b[248]
  PIN b[249]
    DIRECTION OUTPUT ;
    USE SIGNAL ;
    PORT
      LAYER M4 ;
        RECT  104.004 60.72 104.088 60.744 ;
    END
  END b[249]
  PIN b[24]
    DIRECTION OUTPUT ;
    USE SIGNAL ;
    PORT
      LAYER M4 ;
        RECT  104.004 44.496 104.088 44.52 ;
    END
  END b[24]
  PIN b[250]
    DIRECTION OUTPUT ;
    USE SIGNAL ;
    PORT
      LAYER M4 ;
        RECT  104.004 60.816 104.088 60.84 ;
    END
  END b[250]
  PIN b[251]
    DIRECTION OUTPUT ;
    USE SIGNAL ;
    PORT
      LAYER M4 ;
        RECT  104.004 60.912 104.088 60.936 ;
    END
  END b[251]
  PIN b[252]
    DIRECTION OUTPUT ;
    USE SIGNAL ;
    PORT
      LAYER M4 ;
        RECT  104.004 61.008 104.088 61.032 ;
    END
  END b[252]
  PIN b[253]
    DIRECTION OUTPUT ;
    USE SIGNAL ;
    PORT
      LAYER M4 ;
        RECT  104.004 61.104 104.088 61.128 ;
    END
  END b[253]
  PIN b[254]
    DIRECTION OUTPUT ;
    USE SIGNAL ;
    PORT
      LAYER M4 ;
        RECT  104.004 61.2 104.088 61.224 ;
    END
  END b[254]
  PIN b[255]
    DIRECTION OUTPUT ;
    USE SIGNAL ;
    PORT
      LAYER M4 ;
        RECT  104.004 61.296 104.088 61.32 ;
    END
  END b[255]
  PIN b[256]
    DIRECTION OUTPUT ;
    USE SIGNAL ;
    PORT
      LAYER M4 ;
        RECT  104.004 64.464 104.088 64.488 ;
    END
  END b[256]
  PIN b[257]
    DIRECTION OUTPUT ;
    USE SIGNAL ;
    PORT
      LAYER M4 ;
        RECT  104.004 64.56 104.088 64.584 ;
    END
  END b[257]
  PIN b[258]
    DIRECTION OUTPUT ;
    USE SIGNAL ;
    PORT
      LAYER M4 ;
        RECT  104.004 64.656 104.088 64.68 ;
    END
  END b[258]
  PIN b[259]
    DIRECTION OUTPUT ;
    USE SIGNAL ;
    PORT
      LAYER M4 ;
        RECT  104.004 64.752 104.088 64.776 ;
    END
  END b[259]
  PIN b[25]
    DIRECTION OUTPUT ;
    USE SIGNAL ;
    PORT
      LAYER M4 ;
        RECT  104.004 44.592 104.088 44.616 ;
    END
  END b[25]
  PIN b[260]
    DIRECTION OUTPUT ;
    USE SIGNAL ;
    PORT
      LAYER M4 ;
        RECT  104.004 64.848 104.088 64.872 ;
    END
  END b[260]
  PIN b[261]
    DIRECTION OUTPUT ;
    USE SIGNAL ;
    PORT
      LAYER M4 ;
        RECT  104.004 64.944 104.088 64.968 ;
    END
  END b[261]
  PIN b[262]
    DIRECTION OUTPUT ;
    USE SIGNAL ;
    PORT
      LAYER M4 ;
        RECT  104.004 65.04 104.088 65.064 ;
    END
  END b[262]
  PIN b[263]
    DIRECTION OUTPUT ;
    USE SIGNAL ;
    PORT
      LAYER M4 ;
        RECT  104.004 65.136 104.088 65.16 ;
    END
  END b[263]
  PIN b[264]
    DIRECTION OUTPUT ;
    USE SIGNAL ;
    PORT
      LAYER M4 ;
        RECT  104.004 65.232 104.088 65.256 ;
    END
  END b[264]
  PIN b[265]
    DIRECTION OUTPUT ;
    USE SIGNAL ;
    PORT
      LAYER M4 ;
        RECT  104.004 65.328 104.088 65.352 ;
    END
  END b[265]
  PIN b[266]
    DIRECTION OUTPUT ;
    USE SIGNAL ;
    PORT
      LAYER M4 ;
        RECT  104.004 65.424 104.088 65.448 ;
    END
  END b[266]
  PIN b[267]
    DIRECTION OUTPUT ;
    USE SIGNAL ;
    PORT
      LAYER M4 ;
        RECT  104.004 65.52 104.088 65.544 ;
    END
  END b[267]
  PIN b[268]
    DIRECTION OUTPUT ;
    USE SIGNAL ;
    PORT
      LAYER M4 ;
        RECT  104.004 65.616 104.088 65.64 ;
    END
  END b[268]
  PIN b[269]
    DIRECTION OUTPUT ;
    USE SIGNAL ;
    PORT
      LAYER M4 ;
        RECT  104.004 65.712 104.088 65.736 ;
    END
  END b[269]
  PIN b[26]
    DIRECTION OUTPUT ;
    USE SIGNAL ;
    PORT
      LAYER M4 ;
        RECT  104.004 44.688 104.088 44.712 ;
    END
  END b[26]
  PIN b[270]
    DIRECTION OUTPUT ;
    USE SIGNAL ;
    PORT
      LAYER M4 ;
        RECT  104.004 65.808 104.088 65.832 ;
    END
  END b[270]
  PIN b[271]
    DIRECTION OUTPUT ;
    USE SIGNAL ;
    PORT
      LAYER M4 ;
        RECT  104.004 65.904 104.088 65.928 ;
    END
  END b[271]
  PIN b[272]
    DIRECTION OUTPUT ;
    USE SIGNAL ;
    PORT
      LAYER M4 ;
        RECT  104.004 66 104.088 66.024 ;
    END
  END b[272]
  PIN b[273]
    DIRECTION OUTPUT ;
    USE SIGNAL ;
    PORT
      LAYER M4 ;
        RECT  104.004 66.096 104.088 66.12 ;
    END
  END b[273]
  PIN b[274]
    DIRECTION OUTPUT ;
    USE SIGNAL ;
    PORT
      LAYER M4 ;
        RECT  104.004 66.192 104.088 66.216 ;
    END
  END b[274]
  PIN b[275]
    DIRECTION OUTPUT ;
    USE SIGNAL ;
    PORT
      LAYER M4 ;
        RECT  104.004 66.288 104.088 66.312 ;
    END
  END b[275]
  PIN b[276]
    DIRECTION OUTPUT ;
    USE SIGNAL ;
    PORT
      LAYER M4 ;
        RECT  104.004 66.384 104.088 66.408 ;
    END
  END b[276]
  PIN b[277]
    DIRECTION OUTPUT ;
    USE SIGNAL ;
    PORT
      LAYER M4 ;
        RECT  104.004 66.48 104.088 66.504 ;
    END
  END b[277]
  PIN b[278]
    DIRECTION OUTPUT ;
    USE SIGNAL ;
    PORT
      LAYER M4 ;
        RECT  104.004 66.576 104.088 66.6 ;
    END
  END b[278]
  PIN b[279]
    DIRECTION OUTPUT ;
    USE SIGNAL ;
    PORT
      LAYER M4 ;
        RECT  104.004 66.672 104.088 66.696 ;
    END
  END b[279]
  PIN b[27]
    DIRECTION OUTPUT ;
    USE SIGNAL ;
    PORT
      LAYER M4 ;
        RECT  104.004 44.784 104.088 44.808 ;
    END
  END b[27]
  PIN b[280]
    DIRECTION OUTPUT ;
    USE SIGNAL ;
    PORT
      LAYER M4 ;
        RECT  104.004 66.768 104.088 66.792 ;
    END
  END b[280]
  PIN b[281]
    DIRECTION OUTPUT ;
    USE SIGNAL ;
    PORT
      LAYER M4 ;
        RECT  104.004 66.864 104.088 66.888 ;
    END
  END b[281]
  PIN b[282]
    DIRECTION OUTPUT ;
    USE SIGNAL ;
    PORT
      LAYER M4 ;
        RECT  104.004 66.96 104.088 66.984 ;
    END
  END b[282]
  PIN b[283]
    DIRECTION OUTPUT ;
    USE SIGNAL ;
    PORT
      LAYER M4 ;
        RECT  104.004 67.056 104.088 67.08 ;
    END
  END b[283]
  PIN b[284]
    DIRECTION OUTPUT ;
    USE SIGNAL ;
    PORT
      LAYER M4 ;
        RECT  104.004 67.152 104.088 67.176 ;
    END
  END b[284]
  PIN b[285]
    DIRECTION OUTPUT ;
    USE SIGNAL ;
    PORT
      LAYER M4 ;
        RECT  104.004 67.248 104.088 67.272 ;
    END
  END b[285]
  PIN b[286]
    DIRECTION OUTPUT ;
    USE SIGNAL ;
    PORT
      LAYER M4 ;
        RECT  104.004 67.344 104.088 67.368 ;
    END
  END b[286]
  PIN b[287]
    DIRECTION OUTPUT ;
    USE SIGNAL ;
    PORT
      LAYER M4 ;
        RECT  104.004 67.44 104.088 67.464 ;
    END
  END b[287]
  PIN b[288]
    DIRECTION OUTPUT ;
    USE SIGNAL ;
    PORT
      LAYER M4 ;
        RECT  104.004 67.536 104.088 67.56 ;
    END
  END b[288]
  PIN b[289]
    DIRECTION OUTPUT ;
    USE SIGNAL ;
    PORT
      LAYER M4 ;
        RECT  104.004 67.632 104.088 67.656 ;
    END
  END b[289]
  PIN b[28]
    DIRECTION OUTPUT ;
    USE SIGNAL ;
    PORT
      LAYER M4 ;
        RECT  104.004 44.88 104.088 44.904 ;
    END
  END b[28]
  PIN b[290]
    DIRECTION OUTPUT ;
    USE SIGNAL ;
    PORT
      LAYER M4 ;
        RECT  104.004 67.728 104.088 67.752 ;
    END
  END b[290]
  PIN b[291]
    DIRECTION OUTPUT ;
    USE SIGNAL ;
    PORT
      LAYER M4 ;
        RECT  104.004 67.824 104.088 67.848 ;
    END
  END b[291]
  PIN b[292]
    DIRECTION OUTPUT ;
    USE SIGNAL ;
    PORT
      LAYER M4 ;
        RECT  104.004 67.92 104.088 67.944 ;
    END
  END b[292]
  PIN b[293]
    DIRECTION OUTPUT ;
    USE SIGNAL ;
    PORT
      LAYER M4 ;
        RECT  104.004 68.016 104.088 68.04 ;
    END
  END b[293]
  PIN b[294]
    DIRECTION OUTPUT ;
    USE SIGNAL ;
    PORT
      LAYER M4 ;
        RECT  104.004 68.112 104.088 68.136 ;
    END
  END b[294]
  PIN b[295]
    DIRECTION OUTPUT ;
    USE SIGNAL ;
    PORT
      LAYER M4 ;
        RECT  104.004 68.208 104.088 68.232 ;
    END
  END b[295]
  PIN b[296]
    DIRECTION OUTPUT ;
    USE SIGNAL ;
    PORT
      LAYER M4 ;
        RECT  104.004 68.304 104.088 68.328 ;
    END
  END b[296]
  PIN b[297]
    DIRECTION OUTPUT ;
    USE SIGNAL ;
    PORT
      LAYER M4 ;
        RECT  104.004 68.4 104.088 68.424 ;
    END
  END b[297]
  PIN b[298]
    DIRECTION OUTPUT ;
    USE SIGNAL ;
    PORT
      LAYER M4 ;
        RECT  104.004 68.496 104.088 68.52 ;
    END
  END b[298]
  PIN b[299]
    DIRECTION OUTPUT ;
    USE SIGNAL ;
    PORT
      LAYER M4 ;
        RECT  104.004 68.592 104.088 68.616 ;
    END
  END b[299]
  PIN b[29]
    DIRECTION OUTPUT ;
    USE SIGNAL ;
    PORT
      LAYER M4 ;
        RECT  104.004 44.976 104.088 45 ;
    END
  END b[29]
  PIN b[2]
    DIRECTION OUTPUT ;
    USE SIGNAL ;
    PORT
      LAYER M4 ;
        RECT  104.004 42.384 104.088 42.408 ;
    END
  END b[2]
  PIN b[300]
    DIRECTION OUTPUT ;
    USE SIGNAL ;
    PORT
      LAYER M4 ;
        RECT  104.004 68.688 104.088 68.712 ;
    END
  END b[300]
  PIN b[301]
    DIRECTION OUTPUT ;
    USE SIGNAL ;
    PORT
      LAYER M4 ;
        RECT  104.004 68.784 104.088 68.808 ;
    END
  END b[301]
  PIN b[302]
    DIRECTION OUTPUT ;
    USE SIGNAL ;
    PORT
      LAYER M4 ;
        RECT  104.004 68.88 104.088 68.904 ;
    END
  END b[302]
  PIN b[303]
    DIRECTION OUTPUT ;
    USE SIGNAL ;
    PORT
      LAYER M4 ;
        RECT  104.004 68.976 104.088 69 ;
    END
  END b[303]
  PIN b[304]
    DIRECTION OUTPUT ;
    USE SIGNAL ;
    PORT
      LAYER M4 ;
        RECT  104.004 69.072 104.088 69.096 ;
    END
  END b[304]
  PIN b[305]
    DIRECTION OUTPUT ;
    USE SIGNAL ;
    PORT
      LAYER M4 ;
        RECT  104.004 69.168 104.088 69.192 ;
    END
  END b[305]
  PIN b[306]
    DIRECTION OUTPUT ;
    USE SIGNAL ;
    PORT
      LAYER M4 ;
        RECT  104.004 69.264 104.088 69.288 ;
    END
  END b[306]
  PIN b[307]
    DIRECTION OUTPUT ;
    USE SIGNAL ;
    PORT
      LAYER M4 ;
        RECT  104.004 69.36 104.088 69.384 ;
    END
  END b[307]
  PIN b[308]
    DIRECTION OUTPUT ;
    USE SIGNAL ;
    PORT
      LAYER M4 ;
        RECT  104.004 69.456 104.088 69.48 ;
    END
  END b[308]
  PIN b[309]
    DIRECTION OUTPUT ;
    USE SIGNAL ;
    PORT
      LAYER M4 ;
        RECT  104.004 69.552 104.088 69.576 ;
    END
  END b[309]
  PIN b[30]
    DIRECTION OUTPUT ;
    USE SIGNAL ;
    PORT
      LAYER M4 ;
        RECT  104.004 45.072 104.088 45.096 ;
    END
  END b[30]
  PIN b[310]
    DIRECTION OUTPUT ;
    USE SIGNAL ;
    PORT
      LAYER M4 ;
        RECT  104.004 69.648 104.088 69.672 ;
    END
  END b[310]
  PIN b[311]
    DIRECTION OUTPUT ;
    USE SIGNAL ;
    PORT
      LAYER M4 ;
        RECT  104.004 69.744 104.088 69.768 ;
    END
  END b[311]
  PIN b[312]
    DIRECTION OUTPUT ;
    USE SIGNAL ;
    PORT
      LAYER M4 ;
        RECT  104.004 69.84 104.088 69.864 ;
    END
  END b[312]
  PIN b[313]
    DIRECTION OUTPUT ;
    USE SIGNAL ;
    PORT
      LAYER M4 ;
        RECT  104.004 69.936 104.088 69.96 ;
    END
  END b[313]
  PIN b[314]
    DIRECTION OUTPUT ;
    USE SIGNAL ;
    PORT
      LAYER M4 ;
        RECT  104.004 70.032 104.088 70.056 ;
    END
  END b[314]
  PIN b[315]
    DIRECTION OUTPUT ;
    USE SIGNAL ;
    PORT
      LAYER M4 ;
        RECT  104.004 70.128 104.088 70.152 ;
    END
  END b[315]
  PIN b[316]
    DIRECTION OUTPUT ;
    USE SIGNAL ;
    PORT
      LAYER M4 ;
        RECT  104.004 70.224 104.088 70.248 ;
    END
  END b[316]
  PIN b[317]
    DIRECTION OUTPUT ;
    USE SIGNAL ;
    PORT
      LAYER M4 ;
        RECT  104.004 70.32 104.088 70.344 ;
    END
  END b[317]
  PIN b[318]
    DIRECTION OUTPUT ;
    USE SIGNAL ;
    PORT
      LAYER M4 ;
        RECT  104.004 70.416 104.088 70.44 ;
    END
  END b[318]
  PIN b[319]
    DIRECTION OUTPUT ;
    USE SIGNAL ;
    PORT
      LAYER M4 ;
        RECT  104.004 70.512 104.088 70.536 ;
    END
  END b[319]
  PIN b[31]
    DIRECTION OUTPUT ;
    USE SIGNAL ;
    PORT
      LAYER M4 ;
        RECT  104.004 45.168 104.088 45.192 ;
    END
  END b[31]
  PIN b[320]
    DIRECTION OUTPUT ;
    USE SIGNAL ;
    PORT
      LAYER M4 ;
        RECT  104.004 70.608 104.088 70.632 ;
    END
  END b[320]
  PIN b[321]
    DIRECTION OUTPUT ;
    USE SIGNAL ;
    PORT
      LAYER M4 ;
        RECT  104.004 70.704 104.088 70.728 ;
    END
  END b[321]
  PIN b[322]
    DIRECTION OUTPUT ;
    USE SIGNAL ;
    PORT
      LAYER M4 ;
        RECT  104.004 70.8 104.088 70.824 ;
    END
  END b[322]
  PIN b[323]
    DIRECTION OUTPUT ;
    USE SIGNAL ;
    PORT
      LAYER M4 ;
        RECT  104.004 70.896 104.088 70.92 ;
    END
  END b[323]
  PIN b[324]
    DIRECTION OUTPUT ;
    USE SIGNAL ;
    PORT
      LAYER M4 ;
        RECT  104.004 70.992 104.088 71.016 ;
    END
  END b[324]
  PIN b[325]
    DIRECTION OUTPUT ;
    USE SIGNAL ;
    PORT
      LAYER M4 ;
        RECT  104.004 71.088 104.088 71.112 ;
    END
  END b[325]
  PIN b[326]
    DIRECTION OUTPUT ;
    USE SIGNAL ;
    PORT
      LAYER M4 ;
        RECT  104.004 71.184 104.088 71.208 ;
    END
  END b[326]
  PIN b[327]
    DIRECTION OUTPUT ;
    USE SIGNAL ;
    PORT
      LAYER M4 ;
        RECT  104.004 71.28 104.088 71.304 ;
    END
  END b[327]
  PIN b[328]
    DIRECTION OUTPUT ;
    USE SIGNAL ;
    PORT
      LAYER M4 ;
        RECT  104.004 71.376 104.088 71.4 ;
    END
  END b[328]
  PIN b[329]
    DIRECTION OUTPUT ;
    USE SIGNAL ;
    PORT
      LAYER M4 ;
        RECT  104.004 71.472 104.088 71.496 ;
    END
  END b[329]
  PIN b[32]
    DIRECTION OUTPUT ;
    USE SIGNAL ;
    PORT
      LAYER M4 ;
        RECT  104.004 54.48 104.088 54.504 ;
    END
  END b[32]
  PIN b[330]
    DIRECTION OUTPUT ;
    USE SIGNAL ;
    PORT
      LAYER M4 ;
        RECT  104.004 71.568 104.088 71.592 ;
    END
  END b[330]
  PIN b[331]
    DIRECTION OUTPUT ;
    USE SIGNAL ;
    PORT
      LAYER M4 ;
        RECT  104.004 71.664 104.088 71.688 ;
    END
  END b[331]
  PIN b[332]
    DIRECTION OUTPUT ;
    USE SIGNAL ;
    PORT
      LAYER M4 ;
        RECT  104.004 71.76 104.088 71.784 ;
    END
  END b[332]
  PIN b[333]
    DIRECTION OUTPUT ;
    USE SIGNAL ;
    PORT
      LAYER M4 ;
        RECT  104.004 71.856 104.088 71.88 ;
    END
  END b[333]
  PIN b[334]
    DIRECTION OUTPUT ;
    USE SIGNAL ;
    PORT
      LAYER M4 ;
        RECT  104.004 71.952 104.088 71.976 ;
    END
  END b[334]
  PIN b[335]
    DIRECTION OUTPUT ;
    USE SIGNAL ;
    PORT
      LAYER M4 ;
        RECT  104.004 72.048 104.088 72.072 ;
    END
  END b[335]
  PIN b[336]
    DIRECTION OUTPUT ;
    USE SIGNAL ;
    PORT
      LAYER M4 ;
        RECT  104.004 72.144 104.088 72.168 ;
    END
  END b[336]
  PIN b[337]
    DIRECTION OUTPUT ;
    USE SIGNAL ;
    PORT
      LAYER M4 ;
        RECT  104.004 72.24 104.088 72.264 ;
    END
  END b[337]
  PIN b[338]
    DIRECTION OUTPUT ;
    USE SIGNAL ;
    PORT
      LAYER M4 ;
        RECT  104.004 72.336 104.088 72.36 ;
    END
  END b[338]
  PIN b[339]
    DIRECTION OUTPUT ;
    USE SIGNAL ;
    PORT
      LAYER M4 ;
        RECT  104.004 72.432 104.088 72.456 ;
    END
  END b[339]
  PIN b[33]
    DIRECTION OUTPUT ;
    USE SIGNAL ;
    PORT
      LAYER M4 ;
        RECT  104.004 54.576 104.088 54.6 ;
    END
  END b[33]
  PIN b[340]
    DIRECTION OUTPUT ;
    USE SIGNAL ;
    PORT
      LAYER M4 ;
        RECT  104.004 72.528 104.088 72.552 ;
    END
  END b[340]
  PIN b[341]
    DIRECTION OUTPUT ;
    USE SIGNAL ;
    PORT
      LAYER M4 ;
        RECT  104.004 72.624 104.088 72.648 ;
    END
  END b[341]
  PIN b[342]
    DIRECTION OUTPUT ;
    USE SIGNAL ;
    PORT
      LAYER M4 ;
        RECT  104.004 72.72 104.088 72.744 ;
    END
  END b[342]
  PIN b[343]
    DIRECTION OUTPUT ;
    USE SIGNAL ;
    PORT
      LAYER M4 ;
        RECT  104.004 72.816 104.088 72.84 ;
    END
  END b[343]
  PIN b[344]
    DIRECTION OUTPUT ;
    USE SIGNAL ;
    PORT
      LAYER M4 ;
        RECT  104.004 72.912 104.088 72.936 ;
    END
  END b[344]
  PIN b[345]
    DIRECTION OUTPUT ;
    USE SIGNAL ;
    PORT
      LAYER M4 ;
        RECT  104.004 73.008 104.088 73.032 ;
    END
  END b[345]
  PIN b[346]
    DIRECTION OUTPUT ;
    USE SIGNAL ;
    PORT
      LAYER M4 ;
        RECT  104.004 73.104 104.088 73.128 ;
    END
  END b[346]
  PIN b[347]
    DIRECTION OUTPUT ;
    USE SIGNAL ;
    PORT
      LAYER M4 ;
        RECT  104.004 73.2 104.088 73.224 ;
    END
  END b[347]
  PIN b[348]
    DIRECTION OUTPUT ;
    USE SIGNAL ;
    PORT
      LAYER M4 ;
        RECT  104.004 73.296 104.088 73.32 ;
    END
  END b[348]
  PIN b[349]
    DIRECTION OUTPUT ;
    USE SIGNAL ;
    PORT
      LAYER M4 ;
        RECT  104.004 73.392 104.088 73.416 ;
    END
  END b[349]
  PIN b[34]
    DIRECTION OUTPUT ;
    USE SIGNAL ;
    PORT
      LAYER M4 ;
        RECT  104.004 54.672 104.088 54.696 ;
    END
  END b[34]
  PIN b[350]
    DIRECTION OUTPUT ;
    USE SIGNAL ;
    PORT
      LAYER M4 ;
        RECT  104.004 73.488 104.088 73.512 ;
    END
  END b[350]
  PIN b[351]
    DIRECTION OUTPUT ;
    USE SIGNAL ;
    PORT
      LAYER M4 ;
        RECT  104.004 73.584 104.088 73.608 ;
    END
  END b[351]
  PIN b[352]
    DIRECTION OUTPUT ;
    USE SIGNAL ;
    PORT
      LAYER M4 ;
        RECT  104.004 61.392 104.088 61.416 ;
    END
  END b[352]
  PIN b[353]
    DIRECTION OUTPUT ;
    USE SIGNAL ;
    PORT
      LAYER M4 ;
        RECT  104.004 61.488 104.088 61.512 ;
    END
  END b[353]
  PIN b[354]
    DIRECTION OUTPUT ;
    USE SIGNAL ;
    PORT
      LAYER M4 ;
        RECT  104.004 61.584 104.088 61.608 ;
    END
  END b[354]
  PIN b[355]
    DIRECTION OUTPUT ;
    USE SIGNAL ;
    PORT
      LAYER M4 ;
        RECT  104.004 61.68 104.088 61.704 ;
    END
  END b[355]
  PIN b[356]
    DIRECTION OUTPUT ;
    USE SIGNAL ;
    PORT
      LAYER M4 ;
        RECT  104.004 61.776 104.088 61.8 ;
    END
  END b[356]
  PIN b[357]
    DIRECTION OUTPUT ;
    USE SIGNAL ;
    PORT
      LAYER M4 ;
        RECT  104.004 61.872 104.088 61.896 ;
    END
  END b[357]
  PIN b[358]
    DIRECTION OUTPUT ;
    USE SIGNAL ;
    PORT
      LAYER M4 ;
        RECT  104.004 61.968 104.088 61.992 ;
    END
  END b[358]
  PIN b[359]
    DIRECTION OUTPUT ;
    USE SIGNAL ;
    PORT
      LAYER M4 ;
        RECT  104.004 62.064 104.088 62.088 ;
    END
  END b[359]
  PIN b[35]
    DIRECTION OUTPUT ;
    USE SIGNAL ;
    PORT
      LAYER M4 ;
        RECT  104.004 54.768 104.088 54.792 ;
    END
  END b[35]
  PIN b[360]
    DIRECTION OUTPUT ;
    USE SIGNAL ;
    PORT
      LAYER M4 ;
        RECT  104.004 62.16 104.088 62.184 ;
    END
  END b[360]
  PIN b[361]
    DIRECTION OUTPUT ;
    USE SIGNAL ;
    PORT
      LAYER M4 ;
        RECT  104.004 62.256 104.088 62.28 ;
    END
  END b[361]
  PIN b[362]
    DIRECTION OUTPUT ;
    USE SIGNAL ;
    PORT
      LAYER M4 ;
        RECT  104.004 62.352 104.088 62.376 ;
    END
  END b[362]
  PIN b[363]
    DIRECTION OUTPUT ;
    USE SIGNAL ;
    PORT
      LAYER M4 ;
        RECT  104.004 62.448 104.088 62.472 ;
    END
  END b[363]
  PIN b[364]
    DIRECTION OUTPUT ;
    USE SIGNAL ;
    PORT
      LAYER M4 ;
        RECT  104.004 62.544 104.088 62.568 ;
    END
  END b[364]
  PIN b[365]
    DIRECTION OUTPUT ;
    USE SIGNAL ;
    PORT
      LAYER M4 ;
        RECT  104.004 62.64 104.088 62.664 ;
    END
  END b[365]
  PIN b[366]
    DIRECTION OUTPUT ;
    USE SIGNAL ;
    PORT
      LAYER M4 ;
        RECT  104.004 62.736 104.088 62.76 ;
    END
  END b[366]
  PIN b[367]
    DIRECTION OUTPUT ;
    USE SIGNAL ;
    PORT
      LAYER M4 ;
        RECT  104.004 62.832 104.088 62.856 ;
    END
  END b[367]
  PIN b[368]
    DIRECTION OUTPUT ;
    USE SIGNAL ;
    PORT
      LAYER M4 ;
        RECT  104.004 62.928 104.088 62.952 ;
    END
  END b[368]
  PIN b[369]
    DIRECTION OUTPUT ;
    USE SIGNAL ;
    PORT
      LAYER M4 ;
        RECT  104.004 63.024 104.088 63.048 ;
    END
  END b[369]
  PIN b[36]
    DIRECTION OUTPUT ;
    USE SIGNAL ;
    PORT
      LAYER M4 ;
        RECT  104.004 54.864 104.088 54.888 ;
    END
  END b[36]
  PIN b[370]
    DIRECTION OUTPUT ;
    USE SIGNAL ;
    PORT
      LAYER M4 ;
        RECT  104.004 63.12 104.088 63.144 ;
    END
  END b[370]
  PIN b[371]
    DIRECTION OUTPUT ;
    USE SIGNAL ;
    PORT
      LAYER M4 ;
        RECT  104.004 63.216 104.088 63.24 ;
    END
  END b[371]
  PIN b[372]
    DIRECTION OUTPUT ;
    USE SIGNAL ;
    PORT
      LAYER M4 ;
        RECT  104.004 63.312 104.088 63.336 ;
    END
  END b[372]
  PIN b[373]
    DIRECTION OUTPUT ;
    USE SIGNAL ;
    PORT
      LAYER M4 ;
        RECT  104.004 63.408 104.088 63.432 ;
    END
  END b[373]
  PIN b[374]
    DIRECTION OUTPUT ;
    USE SIGNAL ;
    PORT
      LAYER M4 ;
        RECT  104.004 63.504 104.088 63.528 ;
    END
  END b[374]
  PIN b[375]
    DIRECTION OUTPUT ;
    USE SIGNAL ;
    PORT
      LAYER M4 ;
        RECT  104.004 63.6 104.088 63.624 ;
    END
  END b[375]
  PIN b[376]
    DIRECTION OUTPUT ;
    USE SIGNAL ;
    PORT
      LAYER M4 ;
        RECT  104.004 63.696 104.088 63.72 ;
    END
  END b[376]
  PIN b[377]
    DIRECTION OUTPUT ;
    USE SIGNAL ;
    PORT
      LAYER M4 ;
        RECT  104.004 63.792 104.088 63.816 ;
    END
  END b[377]
  PIN b[378]
    DIRECTION OUTPUT ;
    USE SIGNAL ;
    PORT
      LAYER M4 ;
        RECT  104.004 63.888 104.088 63.912 ;
    END
  END b[378]
  PIN b[379]
    DIRECTION OUTPUT ;
    USE SIGNAL ;
    PORT
      LAYER M4 ;
        RECT  104.004 63.984 104.088 64.008 ;
    END
  END b[379]
  PIN b[37]
    DIRECTION OUTPUT ;
    USE SIGNAL ;
    PORT
      LAYER M4 ;
        RECT  104.004 54.96 104.088 54.984 ;
    END
  END b[37]
  PIN b[380]
    DIRECTION OUTPUT ;
    USE SIGNAL ;
    PORT
      LAYER M4 ;
        RECT  104.004 64.08 104.088 64.104 ;
    END
  END b[380]
  PIN b[381]
    DIRECTION OUTPUT ;
    USE SIGNAL ;
    PORT
      LAYER M4 ;
        RECT  104.004 64.176 104.088 64.2 ;
    END
  END b[381]
  PIN b[382]
    DIRECTION OUTPUT ;
    USE SIGNAL ;
    PORT
      LAYER M4 ;
        RECT  104.004 64.272 104.088 64.296 ;
    END
  END b[382]
  PIN b[383]
    DIRECTION OUTPUT ;
    USE SIGNAL ;
    PORT
      LAYER M4 ;
        RECT  104.004 64.368 104.088 64.392 ;
    END
  END b[383]
  PIN b[384]
    DIRECTION OUTPUT ;
    USE SIGNAL ;
    PORT
      LAYER M4 ;
        RECT  104.004 19.92 104.088 19.944 ;
    END
  END b[384]
  PIN b[385]
    DIRECTION OUTPUT ;
    USE SIGNAL ;
    PORT
      LAYER M4 ;
        RECT  104.004 20.016 104.088 20.04 ;
    END
  END b[385]
  PIN b[386]
    DIRECTION OUTPUT ;
    USE SIGNAL ;
    PORT
      LAYER M4 ;
        RECT  104.004 20.112 104.088 20.136 ;
    END
  END b[386]
  PIN b[387]
    DIRECTION OUTPUT ;
    USE SIGNAL ;
    PORT
      LAYER M4 ;
        RECT  104.004 20.208 104.088 20.232 ;
    END
  END b[387]
  PIN b[388]
    DIRECTION OUTPUT ;
    USE SIGNAL ;
    PORT
      LAYER M4 ;
        RECT  104.004 20.304 104.088 20.328 ;
    END
  END b[388]
  PIN b[389]
    DIRECTION OUTPUT ;
    USE SIGNAL ;
    PORT
      LAYER M4 ;
        RECT  104.004 20.4 104.088 20.424 ;
    END
  END b[389]
  PIN b[38]
    DIRECTION OUTPUT ;
    USE SIGNAL ;
    PORT
      LAYER M4 ;
        RECT  104.004 55.056 104.088 55.08 ;
    END
  END b[38]
  PIN b[390]
    DIRECTION OUTPUT ;
    USE SIGNAL ;
    PORT
      LAYER M4 ;
        RECT  104.004 20.496 104.088 20.52 ;
    END
  END b[390]
  PIN b[391]
    DIRECTION OUTPUT ;
    USE SIGNAL ;
    PORT
      LAYER M4 ;
        RECT  104.004 20.592 104.088 20.616 ;
    END
  END b[391]
  PIN b[392]
    DIRECTION OUTPUT ;
    USE SIGNAL ;
    PORT
      LAYER M4 ;
        RECT  104.004 20.688 104.088 20.712 ;
    END
  END b[392]
  PIN b[393]
    DIRECTION OUTPUT ;
    USE SIGNAL ;
    PORT
      LAYER M4 ;
        RECT  104.004 20.784 104.088 20.808 ;
    END
  END b[393]
  PIN b[394]
    DIRECTION OUTPUT ;
    USE SIGNAL ;
    PORT
      LAYER M4 ;
        RECT  104.004 20.88 104.088 20.904 ;
    END
  END b[394]
  PIN b[395]
    DIRECTION OUTPUT ;
    USE SIGNAL ;
    PORT
      LAYER M4 ;
        RECT  104.004 20.976 104.088 21 ;
    END
  END b[395]
  PIN b[396]
    DIRECTION OUTPUT ;
    USE SIGNAL ;
    PORT
      LAYER M4 ;
        RECT  104.004 21.072 104.088 21.096 ;
    END
  END b[396]
  PIN b[397]
    DIRECTION OUTPUT ;
    USE SIGNAL ;
    PORT
      LAYER M4 ;
        RECT  104.004 21.168 104.088 21.192 ;
    END
  END b[397]
  PIN b[398]
    DIRECTION OUTPUT ;
    USE SIGNAL ;
    PORT
      LAYER M4 ;
        RECT  104.004 21.264 104.088 21.288 ;
    END
  END b[398]
  PIN b[399]
    DIRECTION OUTPUT ;
    USE SIGNAL ;
    PORT
      LAYER M4 ;
        RECT  104.004 21.36 104.088 21.384 ;
    END
  END b[399]
  PIN b[39]
    DIRECTION OUTPUT ;
    USE SIGNAL ;
    PORT
      LAYER M4 ;
        RECT  104.004 55.152 104.088 55.176 ;
    END
  END b[39]
  PIN b[3]
    DIRECTION OUTPUT ;
    USE SIGNAL ;
    PORT
      LAYER M4 ;
        RECT  104.004 42.48 104.088 42.504 ;
    END
  END b[3]
  PIN b[400]
    DIRECTION OUTPUT ;
    USE SIGNAL ;
    PORT
      LAYER M4 ;
        RECT  104.004 21.456 104.088 21.48 ;
    END
  END b[400]
  PIN b[401]
    DIRECTION OUTPUT ;
    USE SIGNAL ;
    PORT
      LAYER M4 ;
        RECT  104.004 21.552 104.088 21.576 ;
    END
  END b[401]
  PIN b[402]
    DIRECTION OUTPUT ;
    USE SIGNAL ;
    PORT
      LAYER M4 ;
        RECT  104.004 21.648 104.088 21.672 ;
    END
  END b[402]
  PIN b[403]
    DIRECTION OUTPUT ;
    USE SIGNAL ;
    PORT
      LAYER M4 ;
        RECT  104.004 21.744 104.088 21.768 ;
    END
  END b[403]
  PIN b[404]
    DIRECTION OUTPUT ;
    USE SIGNAL ;
    PORT
      LAYER M4 ;
        RECT  104.004 21.84 104.088 21.864 ;
    END
  END b[404]
  PIN b[405]
    DIRECTION OUTPUT ;
    USE SIGNAL ;
    PORT
      LAYER M4 ;
        RECT  104.004 21.936 104.088 21.96 ;
    END
  END b[405]
  PIN b[406]
    DIRECTION OUTPUT ;
    USE SIGNAL ;
    PORT
      LAYER M4 ;
        RECT  104.004 22.032 104.088 22.056 ;
    END
  END b[406]
  PIN b[407]
    DIRECTION OUTPUT ;
    USE SIGNAL ;
    PORT
      LAYER M4 ;
        RECT  104.004 22.128 104.088 22.152 ;
    END
  END b[407]
  PIN b[408]
    DIRECTION OUTPUT ;
    USE SIGNAL ;
    PORT
      LAYER M4 ;
        RECT  104.004 22.224 104.088 22.248 ;
    END
  END b[408]
  PIN b[409]
    DIRECTION OUTPUT ;
    USE SIGNAL ;
    PORT
      LAYER M4 ;
        RECT  104.004 22.32 104.088 22.344 ;
    END
  END b[409]
  PIN b[40]
    DIRECTION OUTPUT ;
    USE SIGNAL ;
    PORT
      LAYER M4 ;
        RECT  104.004 55.248 104.088 55.272 ;
    END
  END b[40]
  PIN b[410]
    DIRECTION OUTPUT ;
    USE SIGNAL ;
    PORT
      LAYER M4 ;
        RECT  104.004 22.416 104.088 22.44 ;
    END
  END b[410]
  PIN b[411]
    DIRECTION OUTPUT ;
    USE SIGNAL ;
    PORT
      LAYER M4 ;
        RECT  104.004 22.512 104.088 22.536 ;
    END
  END b[411]
  PIN b[412]
    DIRECTION OUTPUT ;
    USE SIGNAL ;
    PORT
      LAYER M4 ;
        RECT  104.004 22.608 104.088 22.632 ;
    END
  END b[412]
  PIN b[413]
    DIRECTION OUTPUT ;
    USE SIGNAL ;
    PORT
      LAYER M4 ;
        RECT  104.004 22.704 104.088 22.728 ;
    END
  END b[413]
  PIN b[414]
    DIRECTION OUTPUT ;
    USE SIGNAL ;
    PORT
      LAYER M4 ;
        RECT  104.004 22.8 104.088 22.824 ;
    END
  END b[414]
  PIN b[415]
    DIRECTION OUTPUT ;
    USE SIGNAL ;
    PORT
      LAYER M4 ;
        RECT  104.004 22.896 104.088 22.92 ;
    END
  END b[415]
  PIN b[416]
    DIRECTION OUTPUT ;
    USE SIGNAL ;
    PORT
      LAYER M4 ;
        RECT  104.004 22.992 104.088 23.016 ;
    END
  END b[416]
  PIN b[417]
    DIRECTION OUTPUT ;
    USE SIGNAL ;
    PORT
      LAYER M4 ;
        RECT  104.004 23.088 104.088 23.112 ;
    END
  END b[417]
  PIN b[418]
    DIRECTION OUTPUT ;
    USE SIGNAL ;
    PORT
      LAYER M4 ;
        RECT  104.004 23.184 104.088 23.208 ;
    END
  END b[418]
  PIN b[419]
    DIRECTION OUTPUT ;
    USE SIGNAL ;
    PORT
      LAYER M4 ;
        RECT  104.004 23.28 104.088 23.304 ;
    END
  END b[419]
  PIN b[41]
    DIRECTION OUTPUT ;
    USE SIGNAL ;
    PORT
      LAYER M4 ;
        RECT  104.004 55.344 104.088 55.368 ;
    END
  END b[41]
  PIN b[420]
    DIRECTION OUTPUT ;
    USE SIGNAL ;
    PORT
      LAYER M4 ;
        RECT  104.004 23.376 104.088 23.4 ;
    END
  END b[420]
  PIN b[421]
    DIRECTION OUTPUT ;
    USE SIGNAL ;
    PORT
      LAYER M4 ;
        RECT  104.004 23.472 104.088 23.496 ;
    END
  END b[421]
  PIN b[422]
    DIRECTION OUTPUT ;
    USE SIGNAL ;
    PORT
      LAYER M4 ;
        RECT  104.004 23.568 104.088 23.592 ;
    END
  END b[422]
  PIN b[423]
    DIRECTION OUTPUT ;
    USE SIGNAL ;
    PORT
      LAYER M4 ;
        RECT  104.004 23.664 104.088 23.688 ;
    END
  END b[423]
  PIN b[424]
    DIRECTION OUTPUT ;
    USE SIGNAL ;
    PORT
      LAYER M4 ;
        RECT  104.004 23.76 104.088 23.784 ;
    END
  END b[424]
  PIN b[425]
    DIRECTION OUTPUT ;
    USE SIGNAL ;
    PORT
      LAYER M4 ;
        RECT  104.004 23.856 104.088 23.88 ;
    END
  END b[425]
  PIN b[426]
    DIRECTION OUTPUT ;
    USE SIGNAL ;
    PORT
      LAYER M4 ;
        RECT  104.004 23.952 104.088 23.976 ;
    END
  END b[426]
  PIN b[427]
    DIRECTION OUTPUT ;
    USE SIGNAL ;
    PORT
      LAYER M4 ;
        RECT  104.004 24.048 104.088 24.072 ;
    END
  END b[427]
  PIN b[428]
    DIRECTION OUTPUT ;
    USE SIGNAL ;
    PORT
      LAYER M4 ;
        RECT  104.004 24.144 104.088 24.168 ;
    END
  END b[428]
  PIN b[429]
    DIRECTION OUTPUT ;
    USE SIGNAL ;
    PORT
      LAYER M4 ;
        RECT  104.004 24.24 104.088 24.264 ;
    END
  END b[429]
  PIN b[42]
    DIRECTION OUTPUT ;
    USE SIGNAL ;
    PORT
      LAYER M4 ;
        RECT  104.004 55.44 104.088 55.464 ;
    END
  END b[42]
  PIN b[430]
    DIRECTION OUTPUT ;
    USE SIGNAL ;
    PORT
      LAYER M4 ;
        RECT  104.004 24.336 104.088 24.36 ;
    END
  END b[430]
  PIN b[431]
    DIRECTION OUTPUT ;
    USE SIGNAL ;
    PORT
      LAYER M4 ;
        RECT  104.004 24.432 104.088 24.456 ;
    END
  END b[431]
  PIN b[432]
    DIRECTION OUTPUT ;
    USE SIGNAL ;
    PORT
      LAYER M4 ;
        RECT  104.004 24.528 104.088 24.552 ;
    END
  END b[432]
  PIN b[433]
    DIRECTION OUTPUT ;
    USE SIGNAL ;
    PORT
      LAYER M4 ;
        RECT  104.004 24.624 104.088 24.648 ;
    END
  END b[433]
  PIN b[434]
    DIRECTION OUTPUT ;
    USE SIGNAL ;
    PORT
      LAYER M4 ;
        RECT  104.004 24.72 104.088 24.744 ;
    END
  END b[434]
  PIN b[435]
    DIRECTION OUTPUT ;
    USE SIGNAL ;
    PORT
      LAYER M4 ;
        RECT  104.004 24.816 104.088 24.84 ;
    END
  END b[435]
  PIN b[436]
    DIRECTION OUTPUT ;
    USE SIGNAL ;
    PORT
      LAYER M4 ;
        RECT  104.004 24.912 104.088 24.936 ;
    END
  END b[436]
  PIN b[437]
    DIRECTION OUTPUT ;
    USE SIGNAL ;
    PORT
      LAYER M4 ;
        RECT  104.004 25.008 104.088 25.032 ;
    END
  END b[437]
  PIN b[438]
    DIRECTION OUTPUT ;
    USE SIGNAL ;
    PORT
      LAYER M4 ;
        RECT  104.004 25.104 104.088 25.128 ;
    END
  END b[438]
  PIN b[439]
    DIRECTION OUTPUT ;
    USE SIGNAL ;
    PORT
      LAYER M4 ;
        RECT  104.004 25.2 104.088 25.224 ;
    END
  END b[439]
  PIN b[43]
    DIRECTION OUTPUT ;
    USE SIGNAL ;
    PORT
      LAYER M4 ;
        RECT  104.004 55.536 104.088 55.56 ;
    END
  END b[43]
  PIN b[440]
    DIRECTION OUTPUT ;
    USE SIGNAL ;
    PORT
      LAYER M4 ;
        RECT  104.004 25.296 104.088 25.32 ;
    END
  END b[440]
  PIN b[441]
    DIRECTION OUTPUT ;
    USE SIGNAL ;
    PORT
      LAYER M4 ;
        RECT  104.004 25.392 104.088 25.416 ;
    END
  END b[441]
  PIN b[442]
    DIRECTION OUTPUT ;
    USE SIGNAL ;
    PORT
      LAYER M4 ;
        RECT  104.004 25.488 104.088 25.512 ;
    END
  END b[442]
  PIN b[443]
    DIRECTION OUTPUT ;
    USE SIGNAL ;
    PORT
      LAYER M4 ;
        RECT  104.004 25.584 104.088 25.608 ;
    END
  END b[443]
  PIN b[444]
    DIRECTION OUTPUT ;
    USE SIGNAL ;
    PORT
      LAYER M4 ;
        RECT  104.004 25.68 104.088 25.704 ;
    END
  END b[444]
  PIN b[445]
    DIRECTION OUTPUT ;
    USE SIGNAL ;
    PORT
      LAYER M4 ;
        RECT  104.004 25.776 104.088 25.8 ;
    END
  END b[445]
  PIN b[446]
    DIRECTION OUTPUT ;
    USE SIGNAL ;
    PORT
      LAYER M4 ;
        RECT  104.004 25.872 104.088 25.896 ;
    END
  END b[446]
  PIN b[447]
    DIRECTION OUTPUT ;
    USE SIGNAL ;
    PORT
      LAYER M4 ;
        RECT  104.004 25.968 104.088 25.992 ;
    END
  END b[447]
  PIN b[448]
    DIRECTION OUTPUT ;
    USE SIGNAL ;
    PORT
      LAYER M4 ;
        RECT  104.004 32.208 104.088 32.232 ;
    END
  END b[448]
  PIN b[449]
    DIRECTION OUTPUT ;
    USE SIGNAL ;
    PORT
      LAYER M4 ;
        RECT  104.004 32.304 104.088 32.328 ;
    END
  END b[449]
  PIN b[44]
    DIRECTION OUTPUT ;
    USE SIGNAL ;
    PORT
      LAYER M4 ;
        RECT  104.004 55.632 104.088 55.656 ;
    END
  END b[44]
  PIN b[450]
    DIRECTION OUTPUT ;
    USE SIGNAL ;
    PORT
      LAYER M4 ;
        RECT  104.004 32.4 104.088 32.424 ;
    END
  END b[450]
  PIN b[451]
    DIRECTION OUTPUT ;
    USE SIGNAL ;
    PORT
      LAYER M4 ;
        RECT  104.004 32.496 104.088 32.52 ;
    END
  END b[451]
  PIN b[452]
    DIRECTION OUTPUT ;
    USE SIGNAL ;
    PORT
      LAYER M4 ;
        RECT  104.004 32.592 104.088 32.616 ;
    END
  END b[452]
  PIN b[453]
    DIRECTION OUTPUT ;
    USE SIGNAL ;
    PORT
      LAYER M4 ;
        RECT  104.004 32.688 104.088 32.712 ;
    END
  END b[453]
  PIN b[454]
    DIRECTION OUTPUT ;
    USE SIGNAL ;
    PORT
      LAYER M4 ;
        RECT  104.004 32.784 104.088 32.808 ;
    END
  END b[454]
  PIN b[455]
    DIRECTION OUTPUT ;
    USE SIGNAL ;
    PORT
      LAYER M4 ;
        RECT  104.004 32.88 104.088 32.904 ;
    END
  END b[455]
  PIN b[456]
    DIRECTION OUTPUT ;
    USE SIGNAL ;
    PORT
      LAYER M4 ;
        RECT  104.004 32.976 104.088 33 ;
    END
  END b[456]
  PIN b[457]
    DIRECTION OUTPUT ;
    USE SIGNAL ;
    PORT
      LAYER M4 ;
        RECT  104.004 33.072 104.088 33.096 ;
    END
  END b[457]
  PIN b[458]
    DIRECTION OUTPUT ;
    USE SIGNAL ;
    PORT
      LAYER M4 ;
        RECT  104.004 33.168 104.088 33.192 ;
    END
  END b[458]
  PIN b[459]
    DIRECTION OUTPUT ;
    USE SIGNAL ;
    PORT
      LAYER M4 ;
        RECT  104.004 33.264 104.088 33.288 ;
    END
  END b[459]
  PIN b[45]
    DIRECTION OUTPUT ;
    USE SIGNAL ;
    PORT
      LAYER M4 ;
        RECT  104.004 55.728 104.088 55.752 ;
    END
  END b[45]
  PIN b[460]
    DIRECTION OUTPUT ;
    USE SIGNAL ;
    PORT
      LAYER M4 ;
        RECT  104.004 33.36 104.088 33.384 ;
    END
  END b[460]
  PIN b[461]
    DIRECTION OUTPUT ;
    USE SIGNAL ;
    PORT
      LAYER M4 ;
        RECT  104.004 33.456 104.088 33.48 ;
    END
  END b[461]
  PIN b[462]
    DIRECTION OUTPUT ;
    USE SIGNAL ;
    PORT
      LAYER M4 ;
        RECT  104.004 33.552 104.088 33.576 ;
    END
  END b[462]
  PIN b[463]
    DIRECTION OUTPUT ;
    USE SIGNAL ;
    PORT
      LAYER M4 ;
        RECT  104.004 33.648 104.088 33.672 ;
    END
  END b[463]
  PIN b[464]
    DIRECTION OUTPUT ;
    USE SIGNAL ;
    PORT
      LAYER M4 ;
        RECT  104.004 33.744 104.088 33.768 ;
    END
  END b[464]
  PIN b[465]
    DIRECTION OUTPUT ;
    USE SIGNAL ;
    PORT
      LAYER M4 ;
        RECT  104.004 33.84 104.088 33.864 ;
    END
  END b[465]
  PIN b[466]
    DIRECTION OUTPUT ;
    USE SIGNAL ;
    PORT
      LAYER M4 ;
        RECT  104.004 33.936 104.088 33.96 ;
    END
  END b[466]
  PIN b[467]
    DIRECTION OUTPUT ;
    USE SIGNAL ;
    PORT
      LAYER M4 ;
        RECT  104.004 34.032 104.088 34.056 ;
    END
  END b[467]
  PIN b[468]
    DIRECTION OUTPUT ;
    USE SIGNAL ;
    PORT
      LAYER M4 ;
        RECT  104.004 34.128 104.088 34.152 ;
    END
  END b[468]
  PIN b[469]
    DIRECTION OUTPUT ;
    USE SIGNAL ;
    PORT
      LAYER M4 ;
        RECT  104.004 34.224 104.088 34.248 ;
    END
  END b[469]
  PIN b[46]
    DIRECTION OUTPUT ;
    USE SIGNAL ;
    PORT
      LAYER M4 ;
        RECT  104.004 55.824 104.088 55.848 ;
    END
  END b[46]
  PIN b[470]
    DIRECTION OUTPUT ;
    USE SIGNAL ;
    PORT
      LAYER M4 ;
        RECT  104.004 34.32 104.088 34.344 ;
    END
  END b[470]
  PIN b[471]
    DIRECTION OUTPUT ;
    USE SIGNAL ;
    PORT
      LAYER M4 ;
        RECT  104.004 34.416 104.088 34.44 ;
    END
  END b[471]
  PIN b[472]
    DIRECTION OUTPUT ;
    USE SIGNAL ;
    PORT
      LAYER M4 ;
        RECT  104.004 34.512 104.088 34.536 ;
    END
  END b[472]
  PIN b[473]
    DIRECTION OUTPUT ;
    USE SIGNAL ;
    PORT
      LAYER M4 ;
        RECT  104.004 34.608 104.088 34.632 ;
    END
  END b[473]
  PIN b[474]
    DIRECTION OUTPUT ;
    USE SIGNAL ;
    PORT
      LAYER M4 ;
        RECT  104.004 34.704 104.088 34.728 ;
    END
  END b[474]
  PIN b[475]
    DIRECTION OUTPUT ;
    USE SIGNAL ;
    PORT
      LAYER M4 ;
        RECT  104.004 34.8 104.088 34.824 ;
    END
  END b[475]
  PIN b[476]
    DIRECTION OUTPUT ;
    USE SIGNAL ;
    PORT
      LAYER M4 ;
        RECT  104.004 34.896 104.088 34.92 ;
    END
  END b[476]
  PIN b[477]
    DIRECTION OUTPUT ;
    USE SIGNAL ;
    PORT
      LAYER M4 ;
        RECT  104.004 34.992 104.088 35.016 ;
    END
  END b[477]
  PIN b[478]
    DIRECTION OUTPUT ;
    USE SIGNAL ;
    PORT
      LAYER M4 ;
        RECT  104.004 35.088 104.088 35.112 ;
    END
  END b[478]
  PIN b[479]
    DIRECTION OUTPUT ;
    USE SIGNAL ;
    PORT
      LAYER M4 ;
        RECT  104.004 35.184 104.088 35.208 ;
    END
  END b[479]
  PIN b[47]
    DIRECTION OUTPUT ;
    USE SIGNAL ;
    PORT
      LAYER M4 ;
        RECT  104.004 55.92 104.088 55.944 ;
    END
  END b[47]
  PIN b[480]
    DIRECTION OUTPUT ;
    USE SIGNAL ;
    PORT
      LAYER M4 ;
        RECT  104.004 35.28 104.088 35.304 ;
    END
  END b[480]
  PIN b[481]
    DIRECTION OUTPUT ;
    USE SIGNAL ;
    PORT
      LAYER M4 ;
        RECT  104.004 35.376 104.088 35.4 ;
    END
  END b[481]
  PIN b[482]
    DIRECTION OUTPUT ;
    USE SIGNAL ;
    PORT
      LAYER M4 ;
        RECT  104.004 35.472 104.088 35.496 ;
    END
  END b[482]
  PIN b[483]
    DIRECTION OUTPUT ;
    USE SIGNAL ;
    PORT
      LAYER M4 ;
        RECT  104.004 35.568 104.088 35.592 ;
    END
  END b[483]
  PIN b[484]
    DIRECTION OUTPUT ;
    USE SIGNAL ;
    PORT
      LAYER M4 ;
        RECT  104.004 35.664 104.088 35.688 ;
    END
  END b[484]
  PIN b[485]
    DIRECTION OUTPUT ;
    USE SIGNAL ;
    PORT
      LAYER M4 ;
        RECT  104.004 35.76 104.088 35.784 ;
    END
  END b[485]
  PIN b[486]
    DIRECTION OUTPUT ;
    USE SIGNAL ;
    PORT
      LAYER M4 ;
        RECT  104.004 35.856 104.088 35.88 ;
    END
  END b[486]
  PIN b[487]
    DIRECTION OUTPUT ;
    USE SIGNAL ;
    PORT
      LAYER M4 ;
        RECT  104.004 35.952 104.088 35.976 ;
    END
  END b[487]
  PIN b[488]
    DIRECTION OUTPUT ;
    USE SIGNAL ;
    PORT
      LAYER M4 ;
        RECT  104.004 36.048 104.088 36.072 ;
    END
  END b[488]
  PIN b[489]
    DIRECTION OUTPUT ;
    USE SIGNAL ;
    PORT
      LAYER M4 ;
        RECT  104.004 36.144 104.088 36.168 ;
    END
  END b[489]
  PIN b[48]
    DIRECTION OUTPUT ;
    USE SIGNAL ;
    PORT
      LAYER M4 ;
        RECT  104.004 56.016 104.088 56.04 ;
    END
  END b[48]
  PIN b[490]
    DIRECTION OUTPUT ;
    USE SIGNAL ;
    PORT
      LAYER M4 ;
        RECT  104.004 36.24 104.088 36.264 ;
    END
  END b[490]
  PIN b[491]
    DIRECTION OUTPUT ;
    USE SIGNAL ;
    PORT
      LAYER M4 ;
        RECT  104.004 36.336 104.088 36.36 ;
    END
  END b[491]
  PIN b[492]
    DIRECTION OUTPUT ;
    USE SIGNAL ;
    PORT
      LAYER M4 ;
        RECT  104.004 36.432 104.088 36.456 ;
    END
  END b[492]
  PIN b[493]
    DIRECTION OUTPUT ;
    USE SIGNAL ;
    PORT
      LAYER M4 ;
        RECT  104.004 36.528 104.088 36.552 ;
    END
  END b[493]
  PIN b[494]
    DIRECTION OUTPUT ;
    USE SIGNAL ;
    PORT
      LAYER M4 ;
        RECT  104.004 36.624 104.088 36.648 ;
    END
  END b[494]
  PIN b[495]
    DIRECTION OUTPUT ;
    USE SIGNAL ;
    PORT
      LAYER M4 ;
        RECT  104.004 36.72 104.088 36.744 ;
    END
  END b[495]
  PIN b[496]
    DIRECTION OUTPUT ;
    USE SIGNAL ;
    PORT
      LAYER M4 ;
        RECT  104.004 36.816 104.088 36.84 ;
    END
  END b[496]
  PIN b[497]
    DIRECTION OUTPUT ;
    USE SIGNAL ;
    PORT
      LAYER M4 ;
        RECT  104.004 36.912 104.088 36.936 ;
    END
  END b[497]
  PIN b[498]
    DIRECTION OUTPUT ;
    USE SIGNAL ;
    PORT
      LAYER M4 ;
        RECT  104.004 37.008 104.088 37.032 ;
    END
  END b[498]
  PIN b[499]
    DIRECTION OUTPUT ;
    USE SIGNAL ;
    PORT
      LAYER M4 ;
        RECT  104.004 37.104 104.088 37.128 ;
    END
  END b[499]
  PIN b[49]
    DIRECTION OUTPUT ;
    USE SIGNAL ;
    PORT
      LAYER M4 ;
        RECT  104.004 56.112 104.088 56.136 ;
    END
  END b[49]
  PIN b[4]
    DIRECTION OUTPUT ;
    USE SIGNAL ;
    PORT
      LAYER M4 ;
        RECT  104.004 42.576 104.088 42.6 ;
    END
  END b[4]
  PIN b[500]
    DIRECTION OUTPUT ;
    USE SIGNAL ;
    PORT
      LAYER M4 ;
        RECT  104.004 37.2 104.088 37.224 ;
    END
  END b[500]
  PIN b[501]
    DIRECTION OUTPUT ;
    USE SIGNAL ;
    PORT
      LAYER M4 ;
        RECT  104.004 37.296 104.088 37.32 ;
    END
  END b[501]
  PIN b[502]
    DIRECTION OUTPUT ;
    USE SIGNAL ;
    PORT
      LAYER M4 ;
        RECT  104.004 37.392 104.088 37.416 ;
    END
  END b[502]
  PIN b[503]
    DIRECTION OUTPUT ;
    USE SIGNAL ;
    PORT
      LAYER M4 ;
        RECT  104.004 37.488 104.088 37.512 ;
    END
  END b[503]
  PIN b[504]
    DIRECTION OUTPUT ;
    USE SIGNAL ;
    PORT
      LAYER M4 ;
        RECT  104.004 37.584 104.088 37.608 ;
    END
  END b[504]
  PIN b[505]
    DIRECTION OUTPUT ;
    USE SIGNAL ;
    PORT
      LAYER M4 ;
        RECT  104.004 37.68 104.088 37.704 ;
    END
  END b[505]
  PIN b[506]
    DIRECTION OUTPUT ;
    USE SIGNAL ;
    PORT
      LAYER M4 ;
        RECT  104.004 37.776 104.088 37.8 ;
    END
  END b[506]
  PIN b[507]
    DIRECTION OUTPUT ;
    USE SIGNAL ;
    PORT
      LAYER M4 ;
        RECT  104.004 37.872 104.088 37.896 ;
    END
  END b[507]
  PIN b[508]
    DIRECTION OUTPUT ;
    USE SIGNAL ;
    PORT
      LAYER M4 ;
        RECT  104.004 37.968 104.088 37.992 ;
    END
  END b[508]
  PIN b[509]
    DIRECTION OUTPUT ;
    USE SIGNAL ;
    PORT
      LAYER M4 ;
        RECT  104.004 38.064 104.088 38.088 ;
    END
  END b[509]
  PIN b[50]
    DIRECTION OUTPUT ;
    USE SIGNAL ;
    PORT
      LAYER M4 ;
        RECT  104.004 56.208 104.088 56.232 ;
    END
  END b[50]
  PIN b[510]
    DIRECTION OUTPUT ;
    USE SIGNAL ;
    PORT
      LAYER M4 ;
        RECT  104.004 38.16 104.088 38.184 ;
    END
  END b[510]
  PIN b[511]
    DIRECTION OUTPUT ;
    USE SIGNAL ;
    PORT
      LAYER M4 ;
        RECT  104.004 38.256 104.088 38.28 ;
    END
  END b[511]
  PIN b[512]
    DIRECTION OUTPUT ;
    USE SIGNAL ;
    PORT
      LAYER M4 ;
        RECT  104.004 29.136 104.088 29.16 ;
    END
  END b[512]
  PIN b[513]
    DIRECTION OUTPUT ;
    USE SIGNAL ;
    PORT
      LAYER M4 ;
        RECT  104.004 29.232 104.088 29.256 ;
    END
  END b[513]
  PIN b[514]
    DIRECTION OUTPUT ;
    USE SIGNAL ;
    PORT
      LAYER M4 ;
        RECT  104.004 29.328 104.088 29.352 ;
    END
  END b[514]
  PIN b[515]
    DIRECTION OUTPUT ;
    USE SIGNAL ;
    PORT
      LAYER M4 ;
        RECT  104.004 29.424 104.088 29.448 ;
    END
  END b[515]
  PIN b[516]
    DIRECTION OUTPUT ;
    USE SIGNAL ;
    PORT
      LAYER M4 ;
        RECT  104.004 29.52 104.088 29.544 ;
    END
  END b[516]
  PIN b[517]
    DIRECTION OUTPUT ;
    USE SIGNAL ;
    PORT
      LAYER M4 ;
        RECT  104.004 29.616 104.088 29.64 ;
    END
  END b[517]
  PIN b[518]
    DIRECTION OUTPUT ;
    USE SIGNAL ;
    PORT
      LAYER M4 ;
        RECT  104.004 29.712 104.088 29.736 ;
    END
  END b[518]
  PIN b[519]
    DIRECTION OUTPUT ;
    USE SIGNAL ;
    PORT
      LAYER M4 ;
        RECT  104.004 29.808 104.088 29.832 ;
    END
  END b[519]
  PIN b[51]
    DIRECTION OUTPUT ;
    USE SIGNAL ;
    PORT
      LAYER M4 ;
        RECT  104.004 56.304 104.088 56.328 ;
    END
  END b[51]
  PIN b[520]
    DIRECTION OUTPUT ;
    USE SIGNAL ;
    PORT
      LAYER M4 ;
        RECT  104.004 29.904 104.088 29.928 ;
    END
  END b[520]
  PIN b[521]
    DIRECTION OUTPUT ;
    USE SIGNAL ;
    PORT
      LAYER M4 ;
        RECT  104.004 30 104.088 30.024 ;
    END
  END b[521]
  PIN b[522]
    DIRECTION OUTPUT ;
    USE SIGNAL ;
    PORT
      LAYER M4 ;
        RECT  104.004 30.096 104.088 30.12 ;
    END
  END b[522]
  PIN b[523]
    DIRECTION OUTPUT ;
    USE SIGNAL ;
    PORT
      LAYER M4 ;
        RECT  104.004 30.192 104.088 30.216 ;
    END
  END b[523]
  PIN b[524]
    DIRECTION OUTPUT ;
    USE SIGNAL ;
    PORT
      LAYER M4 ;
        RECT  104.004 30.288 104.088 30.312 ;
    END
  END b[524]
  PIN b[525]
    DIRECTION OUTPUT ;
    USE SIGNAL ;
    PORT
      LAYER M4 ;
        RECT  104.004 30.384 104.088 30.408 ;
    END
  END b[525]
  PIN b[526]
    DIRECTION OUTPUT ;
    USE SIGNAL ;
    PORT
      LAYER M4 ;
        RECT  104.004 30.48 104.088 30.504 ;
    END
  END b[526]
  PIN b[527]
    DIRECTION OUTPUT ;
    USE SIGNAL ;
    PORT
      LAYER M4 ;
        RECT  104.004 30.576 104.088 30.6 ;
    END
  END b[527]
  PIN b[528]
    DIRECTION OUTPUT ;
    USE SIGNAL ;
    PORT
      LAYER M4 ;
        RECT  104.004 30.672 104.088 30.696 ;
    END
  END b[528]
  PIN b[529]
    DIRECTION OUTPUT ;
    USE SIGNAL ;
    PORT
      LAYER M4 ;
        RECT  104.004 30.768 104.088 30.792 ;
    END
  END b[529]
  PIN b[52]
    DIRECTION OUTPUT ;
    USE SIGNAL ;
    PORT
      LAYER M4 ;
        RECT  104.004 56.4 104.088 56.424 ;
    END
  END b[52]
  PIN b[530]
    DIRECTION OUTPUT ;
    USE SIGNAL ;
    PORT
      LAYER M4 ;
        RECT  104.004 30.864 104.088 30.888 ;
    END
  END b[530]
  PIN b[531]
    DIRECTION OUTPUT ;
    USE SIGNAL ;
    PORT
      LAYER M4 ;
        RECT  104.004 30.96 104.088 30.984 ;
    END
  END b[531]
  PIN b[532]
    DIRECTION OUTPUT ;
    USE SIGNAL ;
    PORT
      LAYER M4 ;
        RECT  104.004 31.056 104.088 31.08 ;
    END
  END b[532]
  PIN b[533]
    DIRECTION OUTPUT ;
    USE SIGNAL ;
    PORT
      LAYER M4 ;
        RECT  104.004 31.152 104.088 31.176 ;
    END
  END b[533]
  PIN b[534]
    DIRECTION OUTPUT ;
    USE SIGNAL ;
    PORT
      LAYER M4 ;
        RECT  104.004 31.248 104.088 31.272 ;
    END
  END b[534]
  PIN b[535]
    DIRECTION OUTPUT ;
    USE SIGNAL ;
    PORT
      LAYER M4 ;
        RECT  104.004 31.344 104.088 31.368 ;
    END
  END b[535]
  PIN b[536]
    DIRECTION OUTPUT ;
    USE SIGNAL ;
    PORT
      LAYER M4 ;
        RECT  104.004 31.44 104.088 31.464 ;
    END
  END b[536]
  PIN b[537]
    DIRECTION OUTPUT ;
    USE SIGNAL ;
    PORT
      LAYER M4 ;
        RECT  104.004 31.536 104.088 31.56 ;
    END
  END b[537]
  PIN b[538]
    DIRECTION OUTPUT ;
    USE SIGNAL ;
    PORT
      LAYER M4 ;
        RECT  104.004 31.632 104.088 31.656 ;
    END
  END b[538]
  PIN b[539]
    DIRECTION OUTPUT ;
    USE SIGNAL ;
    PORT
      LAYER M4 ;
        RECT  104.004 31.728 104.088 31.752 ;
    END
  END b[539]
  PIN b[53]
    DIRECTION OUTPUT ;
    USE SIGNAL ;
    PORT
      LAYER M4 ;
        RECT  104.004 56.496 104.088 56.52 ;
    END
  END b[53]
  PIN b[540]
    DIRECTION OUTPUT ;
    USE SIGNAL ;
    PORT
      LAYER M4 ;
        RECT  104.004 31.824 104.088 31.848 ;
    END
  END b[540]
  PIN b[541]
    DIRECTION OUTPUT ;
    USE SIGNAL ;
    PORT
      LAYER M4 ;
        RECT  104.004 31.92 104.088 31.944 ;
    END
  END b[541]
  PIN b[542]
    DIRECTION OUTPUT ;
    USE SIGNAL ;
    PORT
      LAYER M4 ;
        RECT  104.004 32.016 104.088 32.04 ;
    END
  END b[542]
  PIN b[543]
    DIRECTION OUTPUT ;
    USE SIGNAL ;
    PORT
      LAYER M4 ;
        RECT  104.004 32.112 104.088 32.136 ;
    END
  END b[543]
  PIN b[544]
    DIRECTION OUTPUT ;
    USE SIGNAL ;
    PORT
      LAYER M4 ;
        RECT  104.004 26.064 104.088 26.088 ;
    END
  END b[544]
  PIN b[545]
    DIRECTION OUTPUT ;
    USE SIGNAL ;
    PORT
      LAYER M4 ;
        RECT  104.004 26.16 104.088 26.184 ;
    END
  END b[545]
  PIN b[546]
    DIRECTION OUTPUT ;
    USE SIGNAL ;
    PORT
      LAYER M4 ;
        RECT  104.004 26.256 104.088 26.28 ;
    END
  END b[546]
  PIN b[547]
    DIRECTION OUTPUT ;
    USE SIGNAL ;
    PORT
      LAYER M4 ;
        RECT  104.004 26.352 104.088 26.376 ;
    END
  END b[547]
  PIN b[548]
    DIRECTION OUTPUT ;
    USE SIGNAL ;
    PORT
      LAYER M4 ;
        RECT  104.004 26.448 104.088 26.472 ;
    END
  END b[548]
  PIN b[549]
    DIRECTION OUTPUT ;
    USE SIGNAL ;
    PORT
      LAYER M4 ;
        RECT  104.004 26.544 104.088 26.568 ;
    END
  END b[549]
  PIN b[54]
    DIRECTION OUTPUT ;
    USE SIGNAL ;
    PORT
      LAYER M4 ;
        RECT  104.004 56.592 104.088 56.616 ;
    END
  END b[54]
  PIN b[550]
    DIRECTION OUTPUT ;
    USE SIGNAL ;
    PORT
      LAYER M4 ;
        RECT  104.004 26.64 104.088 26.664 ;
    END
  END b[550]
  PIN b[551]
    DIRECTION OUTPUT ;
    USE SIGNAL ;
    PORT
      LAYER M4 ;
        RECT  104.004 26.736 104.088 26.76 ;
    END
  END b[551]
  PIN b[552]
    DIRECTION OUTPUT ;
    USE SIGNAL ;
    PORT
      LAYER M4 ;
        RECT  104.004 26.832 104.088 26.856 ;
    END
  END b[552]
  PIN b[553]
    DIRECTION OUTPUT ;
    USE SIGNAL ;
    PORT
      LAYER M4 ;
        RECT  104.004 26.928 104.088 26.952 ;
    END
  END b[553]
  PIN b[554]
    DIRECTION OUTPUT ;
    USE SIGNAL ;
    PORT
      LAYER M4 ;
        RECT  104.004 27.024 104.088 27.048 ;
    END
  END b[554]
  PIN b[555]
    DIRECTION OUTPUT ;
    USE SIGNAL ;
    PORT
      LAYER M4 ;
        RECT  104.004 27.12 104.088 27.144 ;
    END
  END b[555]
  PIN b[556]
    DIRECTION OUTPUT ;
    USE SIGNAL ;
    PORT
      LAYER M4 ;
        RECT  104.004 27.216 104.088 27.24 ;
    END
  END b[556]
  PIN b[557]
    DIRECTION OUTPUT ;
    USE SIGNAL ;
    PORT
      LAYER M4 ;
        RECT  104.004 27.312 104.088 27.336 ;
    END
  END b[557]
  PIN b[558]
    DIRECTION OUTPUT ;
    USE SIGNAL ;
    PORT
      LAYER M4 ;
        RECT  104.004 27.408 104.088 27.432 ;
    END
  END b[558]
  PIN b[559]
    DIRECTION OUTPUT ;
    USE SIGNAL ;
    PORT
      LAYER M4 ;
        RECT  104.004 27.504 104.088 27.528 ;
    END
  END b[559]
  PIN b[55]
    DIRECTION OUTPUT ;
    USE SIGNAL ;
    PORT
      LAYER M4 ;
        RECT  104.004 56.688 104.088 56.712 ;
    END
  END b[55]
  PIN b[560]
    DIRECTION OUTPUT ;
    USE SIGNAL ;
    PORT
      LAYER M4 ;
        RECT  104.004 27.6 104.088 27.624 ;
    END
  END b[560]
  PIN b[561]
    DIRECTION OUTPUT ;
    USE SIGNAL ;
    PORT
      LAYER M4 ;
        RECT  104.004 27.696 104.088 27.72 ;
    END
  END b[561]
  PIN b[562]
    DIRECTION OUTPUT ;
    USE SIGNAL ;
    PORT
      LAYER M4 ;
        RECT  104.004 27.792 104.088 27.816 ;
    END
  END b[562]
  PIN b[563]
    DIRECTION OUTPUT ;
    USE SIGNAL ;
    PORT
      LAYER M4 ;
        RECT  104.004 27.888 104.088 27.912 ;
    END
  END b[563]
  PIN b[564]
    DIRECTION OUTPUT ;
    USE SIGNAL ;
    PORT
      LAYER M4 ;
        RECT  104.004 27.984 104.088 28.008 ;
    END
  END b[564]
  PIN b[565]
    DIRECTION OUTPUT ;
    USE SIGNAL ;
    PORT
      LAYER M4 ;
        RECT  104.004 28.08 104.088 28.104 ;
    END
  END b[565]
  PIN b[566]
    DIRECTION OUTPUT ;
    USE SIGNAL ;
    PORT
      LAYER M4 ;
        RECT  104.004 28.176 104.088 28.2 ;
    END
  END b[566]
  PIN b[567]
    DIRECTION OUTPUT ;
    USE SIGNAL ;
    PORT
      LAYER M4 ;
        RECT  104.004 28.272 104.088 28.296 ;
    END
  END b[567]
  PIN b[568]
    DIRECTION OUTPUT ;
    USE SIGNAL ;
    PORT
      LAYER M4 ;
        RECT  104.004 28.368 104.088 28.392 ;
    END
  END b[568]
  PIN b[569]
    DIRECTION OUTPUT ;
    USE SIGNAL ;
    PORT
      LAYER M4 ;
        RECT  104.004 28.464 104.088 28.488 ;
    END
  END b[569]
  PIN b[56]
    DIRECTION OUTPUT ;
    USE SIGNAL ;
    PORT
      LAYER M4 ;
        RECT  104.004 56.784 104.088 56.808 ;
    END
  END b[56]
  PIN b[570]
    DIRECTION OUTPUT ;
    USE SIGNAL ;
    PORT
      LAYER M4 ;
        RECT  104.004 28.56 104.088 28.584 ;
    END
  END b[570]
  PIN b[571]
    DIRECTION OUTPUT ;
    USE SIGNAL ;
    PORT
      LAYER M4 ;
        RECT  104.004 28.656 104.088 28.68 ;
    END
  END b[571]
  PIN b[572]
    DIRECTION OUTPUT ;
    USE SIGNAL ;
    PORT
      LAYER M4 ;
        RECT  104.004 28.752 104.088 28.776 ;
    END
  END b[572]
  PIN b[573]
    DIRECTION OUTPUT ;
    USE SIGNAL ;
    PORT
      LAYER M4 ;
        RECT  104.004 28.848 104.088 28.872 ;
    END
  END b[573]
  PIN b[574]
    DIRECTION OUTPUT ;
    USE SIGNAL ;
    PORT
      LAYER M4 ;
        RECT  104.004 28.944 104.088 28.968 ;
    END
  END b[574]
  PIN b[575]
    DIRECTION OUTPUT ;
    USE SIGNAL ;
    PORT
      LAYER M4 ;
        RECT  104.004 29.04 104.088 29.064 ;
    END
  END b[575]
  PIN b[576]
    DIRECTION OUTPUT ;
    USE SIGNAL ;
    PORT
      LAYER M4 ;
        RECT  104.004 77.52 104.088 77.544 ;
    END
  END b[576]
  PIN b[577]
    DIRECTION OUTPUT ;
    USE SIGNAL ;
    PORT
      LAYER M4 ;
        RECT  104.004 77.616 104.088 77.64 ;
    END
  END b[577]
  PIN b[578]
    DIRECTION OUTPUT ;
    USE SIGNAL ;
    PORT
      LAYER M4 ;
        RECT  104.004 77.712 104.088 77.736 ;
    END
  END b[578]
  PIN b[579]
    DIRECTION OUTPUT ;
    USE SIGNAL ;
    PORT
      LAYER M4 ;
        RECT  104.004 77.808 104.088 77.832 ;
    END
  END b[579]
  PIN b[57]
    DIRECTION OUTPUT ;
    USE SIGNAL ;
    PORT
      LAYER M4 ;
        RECT  104.004 56.88 104.088 56.904 ;
    END
  END b[57]
  PIN b[580]
    DIRECTION OUTPUT ;
    USE SIGNAL ;
    PORT
      LAYER M4 ;
        RECT  104.004 77.904 104.088 77.928 ;
    END
  END b[580]
  PIN b[581]
    DIRECTION OUTPUT ;
    USE SIGNAL ;
    PORT
      LAYER M4 ;
        RECT  104.004 78 104.088 78.024 ;
    END
  END b[581]
  PIN b[582]
    DIRECTION OUTPUT ;
    USE SIGNAL ;
    PORT
      LAYER M4 ;
        RECT  104.004 78.096 104.088 78.12 ;
    END
  END b[582]
  PIN b[583]
    DIRECTION OUTPUT ;
    USE SIGNAL ;
    PORT
      LAYER M4 ;
        RECT  104.004 78.192 104.088 78.216 ;
    END
  END b[583]
  PIN b[584]
    DIRECTION OUTPUT ;
    USE SIGNAL ;
    PORT
      LAYER M4 ;
        RECT  104.004 78.288 104.088 78.312 ;
    END
  END b[584]
  PIN b[585]
    DIRECTION OUTPUT ;
    USE SIGNAL ;
    PORT
      LAYER M4 ;
        RECT  104.004 78.384 104.088 78.408 ;
    END
  END b[585]
  PIN b[586]
    DIRECTION OUTPUT ;
    USE SIGNAL ;
    PORT
      LAYER M4 ;
        RECT  104.004 78.48 104.088 78.504 ;
    END
  END b[586]
  PIN b[587]
    DIRECTION OUTPUT ;
    USE SIGNAL ;
    PORT
      LAYER M4 ;
        RECT  104.004 78.576 104.088 78.6 ;
    END
  END b[587]
  PIN b[588]
    DIRECTION OUTPUT ;
    USE SIGNAL ;
    PORT
      LAYER M4 ;
        RECT  104.004 78.672 104.088 78.696 ;
    END
  END b[588]
  PIN b[589]
    DIRECTION OUTPUT ;
    USE SIGNAL ;
    PORT
      LAYER M4 ;
        RECT  104.004 78.768 104.088 78.792 ;
    END
  END b[589]
  PIN b[58]
    DIRECTION OUTPUT ;
    USE SIGNAL ;
    PORT
      LAYER M4 ;
        RECT  104.004 56.976 104.088 57 ;
    END
  END b[58]
  PIN b[590]
    DIRECTION OUTPUT ;
    USE SIGNAL ;
    PORT
      LAYER M4 ;
        RECT  104.004 78.864 104.088 78.888 ;
    END
  END b[590]
  PIN b[591]
    DIRECTION OUTPUT ;
    USE SIGNAL ;
    PORT
      LAYER M4 ;
        RECT  104.004 78.96 104.088 78.984 ;
    END
  END b[591]
  PIN b[592]
    DIRECTION OUTPUT ;
    USE SIGNAL ;
    PORT
      LAYER M4 ;
        RECT  104.004 79.056 104.088 79.08 ;
    END
  END b[592]
  PIN b[593]
    DIRECTION OUTPUT ;
    USE SIGNAL ;
    PORT
      LAYER M4 ;
        RECT  104.004 79.152 104.088 79.176 ;
    END
  END b[593]
  PIN b[594]
    DIRECTION OUTPUT ;
    USE SIGNAL ;
    PORT
      LAYER M4 ;
        RECT  104.004 79.248 104.088 79.272 ;
    END
  END b[594]
  PIN b[595]
    DIRECTION OUTPUT ;
    USE SIGNAL ;
    PORT
      LAYER M4 ;
        RECT  104.004 79.344 104.088 79.368 ;
    END
  END b[595]
  PIN b[596]
    DIRECTION OUTPUT ;
    USE SIGNAL ;
    PORT
      LAYER M4 ;
        RECT  104.004 79.44 104.088 79.464 ;
    END
  END b[596]
  PIN b[597]
    DIRECTION OUTPUT ;
    USE SIGNAL ;
    PORT
      LAYER M4 ;
        RECT  104.004 79.536 104.088 79.56 ;
    END
  END b[597]
  PIN b[598]
    DIRECTION OUTPUT ;
    USE SIGNAL ;
    PORT
      LAYER M4 ;
        RECT  104.004 79.632 104.088 79.656 ;
    END
  END b[598]
  PIN b[599]
    DIRECTION OUTPUT ;
    USE SIGNAL ;
    PORT
      LAYER M4 ;
        RECT  104.004 79.728 104.088 79.752 ;
    END
  END b[599]
  PIN b[59]
    DIRECTION OUTPUT ;
    USE SIGNAL ;
    PORT
      LAYER M4 ;
        RECT  104.004 57.072 104.088 57.096 ;
    END
  END b[59]
  PIN b[5]
    DIRECTION OUTPUT ;
    USE SIGNAL ;
    PORT
      LAYER M4 ;
        RECT  104.004 42.672 104.088 42.696 ;
    END
  END b[5]
  PIN b[60]
    DIRECTION OUTPUT ;
    USE SIGNAL ;
    PORT
      LAYER M4 ;
        RECT  104.004 57.168 104.088 57.192 ;
    END
  END b[60]
  PIN b[61]
    DIRECTION OUTPUT ;
    USE SIGNAL ;
    PORT
      LAYER M4 ;
        RECT  104.004 57.264 104.088 57.288 ;
    END
  END b[61]
  PIN b[62]
    DIRECTION OUTPUT ;
    USE SIGNAL ;
    PORT
      LAYER M4 ;
        RECT  104.004 57.36 104.088 57.384 ;
    END
  END b[62]
  PIN b[63]
    DIRECTION OUTPUT ;
    USE SIGNAL ;
    PORT
      LAYER M4 ;
        RECT  104.004 57.456 104.088 57.48 ;
    END
  END b[63]
  PIN b[64]
    DIRECTION OUTPUT ;
    USE SIGNAL ;
    PORT
      LAYER M4 ;
        RECT  104.004 39.12 104.088 39.144 ;
    END
  END b[64]
  PIN b[65]
    DIRECTION OUTPUT ;
    USE SIGNAL ;
    PORT
      LAYER M4 ;
        RECT  104.004 39.216 104.088 39.24 ;
    END
  END b[65]
  PIN b[66]
    DIRECTION OUTPUT ;
    USE SIGNAL ;
    PORT
      LAYER M4 ;
        RECT  104.004 39.312 104.088 39.336 ;
    END
  END b[66]
  PIN b[67]
    DIRECTION OUTPUT ;
    USE SIGNAL ;
    PORT
      LAYER M4 ;
        RECT  104.004 39.408 104.088 39.432 ;
    END
  END b[67]
  PIN b[68]
    DIRECTION OUTPUT ;
    USE SIGNAL ;
    PORT
      LAYER M4 ;
        RECT  104.004 39.504 104.088 39.528 ;
    END
  END b[68]
  PIN b[69]
    DIRECTION OUTPUT ;
    USE SIGNAL ;
    PORT
      LAYER M4 ;
        RECT  104.004 39.6 104.088 39.624 ;
    END
  END b[69]
  PIN b[6]
    DIRECTION OUTPUT ;
    USE SIGNAL ;
    PORT
      LAYER M4 ;
        RECT  104.004 42.768 104.088 42.792 ;
    END
  END b[6]
  PIN b[70]
    DIRECTION OUTPUT ;
    USE SIGNAL ;
    PORT
      LAYER M4 ;
        RECT  104.004 39.696 104.088 39.72 ;
    END
  END b[70]
  PIN b[71]
    DIRECTION OUTPUT ;
    USE SIGNAL ;
    PORT
      LAYER M4 ;
        RECT  104.004 39.792 104.088 39.816 ;
    END
  END b[71]
  PIN b[72]
    DIRECTION OUTPUT ;
    USE SIGNAL ;
    PORT
      LAYER M4 ;
        RECT  104.004 39.888 104.088 39.912 ;
    END
  END b[72]
  PIN b[73]
    DIRECTION OUTPUT ;
    USE SIGNAL ;
    PORT
      LAYER M4 ;
        RECT  104.004 39.984 104.088 40.008 ;
    END
  END b[73]
  PIN b[74]
    DIRECTION OUTPUT ;
    USE SIGNAL ;
    PORT
      LAYER M4 ;
        RECT  104.004 40.08 104.088 40.104 ;
    END
  END b[74]
  PIN b[75]
    DIRECTION OUTPUT ;
    USE SIGNAL ;
    PORT
      LAYER M4 ;
        RECT  104.004 40.176 104.088 40.2 ;
    END
  END b[75]
  PIN b[76]
    DIRECTION OUTPUT ;
    USE SIGNAL ;
    PORT
      LAYER M4 ;
        RECT  104.004 40.272 104.088 40.296 ;
    END
  END b[76]
  PIN b[77]
    DIRECTION OUTPUT ;
    USE SIGNAL ;
    PORT
      LAYER M4 ;
        RECT  104.004 40.368 104.088 40.392 ;
    END
  END b[77]
  PIN b[78]
    DIRECTION OUTPUT ;
    USE SIGNAL ;
    PORT
      LAYER M4 ;
        RECT  104.004 40.464 104.088 40.488 ;
    END
  END b[78]
  PIN b[79]
    DIRECTION OUTPUT ;
    USE SIGNAL ;
    PORT
      LAYER M4 ;
        RECT  104.004 40.56 104.088 40.584 ;
    END
  END b[79]
  PIN b[7]
    DIRECTION OUTPUT ;
    USE SIGNAL ;
    PORT
      LAYER M4 ;
        RECT  104.004 42.864 104.088 42.888 ;
    END
  END b[7]
  PIN b[80]
    DIRECTION OUTPUT ;
    USE SIGNAL ;
    PORT
      LAYER M4 ;
        RECT  104.004 40.656 104.088 40.68 ;
    END
  END b[80]
  PIN b[81]
    DIRECTION OUTPUT ;
    USE SIGNAL ;
    PORT
      LAYER M4 ;
        RECT  104.004 40.752 104.088 40.776 ;
    END
  END b[81]
  PIN b[82]
    DIRECTION OUTPUT ;
    USE SIGNAL ;
    PORT
      LAYER M4 ;
        RECT  104.004 40.848 104.088 40.872 ;
    END
  END b[82]
  PIN b[83]
    DIRECTION OUTPUT ;
    USE SIGNAL ;
    PORT
      LAYER M4 ;
        RECT  104.004 40.944 104.088 40.968 ;
    END
  END b[83]
  PIN b[84]
    DIRECTION OUTPUT ;
    USE SIGNAL ;
    PORT
      LAYER M4 ;
        RECT  104.004 41.04 104.088 41.064 ;
    END
  END b[84]
  PIN b[85]
    DIRECTION OUTPUT ;
    USE SIGNAL ;
    PORT
      LAYER M4 ;
        RECT  104.004 41.136 104.088 41.16 ;
    END
  END b[85]
  PIN b[86]
    DIRECTION OUTPUT ;
    USE SIGNAL ;
    PORT
      LAYER M4 ;
        RECT  104.004 41.232 104.088 41.256 ;
    END
  END b[86]
  PIN b[87]
    DIRECTION OUTPUT ;
    USE SIGNAL ;
    PORT
      LAYER M4 ;
        RECT  104.004 41.328 104.088 41.352 ;
    END
  END b[87]
  PIN b[88]
    DIRECTION OUTPUT ;
    USE SIGNAL ;
    PORT
      LAYER M4 ;
        RECT  104.004 41.424 104.088 41.448 ;
    END
  END b[88]
  PIN b[89]
    DIRECTION OUTPUT ;
    USE SIGNAL ;
    PORT
      LAYER M4 ;
        RECT  104.004 41.52 104.088 41.544 ;
    END
  END b[89]
  PIN b[8]
    DIRECTION OUTPUT ;
    USE SIGNAL ;
    PORT
      LAYER M4 ;
        RECT  104.004 42.96 104.088 42.984 ;
    END
  END b[8]
  PIN b[90]
    DIRECTION OUTPUT ;
    USE SIGNAL ;
    PORT
      LAYER M4 ;
        RECT  104.004 41.616 104.088 41.64 ;
    END
  END b[90]
  PIN b[91]
    DIRECTION OUTPUT ;
    USE SIGNAL ;
    PORT
      LAYER M4 ;
        RECT  104.004 41.712 104.088 41.736 ;
    END
  END b[91]
  PIN b[92]
    DIRECTION OUTPUT ;
    USE SIGNAL ;
    PORT
      LAYER M4 ;
        RECT  104.004 41.808 104.088 41.832 ;
    END
  END b[92]
  PIN b[93]
    DIRECTION OUTPUT ;
    USE SIGNAL ;
    PORT
      LAYER M4 ;
        RECT  104.004 41.904 104.088 41.928 ;
    END
  END b[93]
  PIN b[94]
    DIRECTION OUTPUT ;
    USE SIGNAL ;
    PORT
      LAYER M4 ;
        RECT  104.004 42 104.088 42.024 ;
    END
  END b[94]
  PIN b[95]
    DIRECTION OUTPUT ;
    USE SIGNAL ;
    PORT
      LAYER M4 ;
        RECT  104.004 42.096 104.088 42.12 ;
    END
  END b[95]
  PIN b[96]
    DIRECTION OUTPUT ;
    USE SIGNAL ;
    PORT
      LAYER M4 ;
        RECT  104.004 48.336 104.088 48.36 ;
    END
  END b[96]
  PIN b[97]
    DIRECTION OUTPUT ;
    USE SIGNAL ;
    PORT
      LAYER M4 ;
        RECT  104.004 48.432 104.088 48.456 ;
    END
  END b[97]
  PIN b[98]
    DIRECTION OUTPUT ;
    USE SIGNAL ;
    PORT
      LAYER M4 ;
        RECT  104.004 48.528 104.088 48.552 ;
    END
  END b[98]
  PIN b[99]
    DIRECTION OUTPUT ;
    USE SIGNAL ;
    PORT
      LAYER M4 ;
        RECT  104.004 48.624 104.088 48.648 ;
    END
  END b[99]
  PIN b[9]
    DIRECTION OUTPUT ;
    USE SIGNAL ;
    PORT
      LAYER M4 ;
        RECT  104.004 43.056 104.088 43.08 ;
    END
  END b[9]
  PIN ck
    DIRECTION INPUT ;
    USE SIGNAL ;
    PORT
      LAYER M4 ;
        RECT  0 54.096 0.084 54.12 ;
    END
  END ck
  PIN ck_o
    DIRECTION OUTPUT ;
    USE SIGNAL ;
    PORT
      LAYER M4 ;
        RECT  0 54.192 0.084 54.216 ;
    END
  END ck_o
  PIN eb
    DIRECTION OUTPUT ;
    USE SIGNAL ;
    PORT
      LAYER M4 ;
        RECT  104.004 79.824 104.088 79.848 ;
    END
  END eb
  PIN en
    DIRECTION INPUT ;
    USE SIGNAL ;
    PORT
      LAYER M4 ;
        RECT  0 54.288 0.084 54.312 ;
    END
  END en
  PIN VDD
    DIRECTION INOUT ;
    USE POWER ;
    PORT
      LAYER M5 ;
        RECT  99.792 2.151 99.912 103.433 ;
        RECT  97.092 2.151 97.212 103.433 ;
        RECT  94.392 2.151 94.512 103.433 ;
        RECT  91.692 2.151 91.812 103.433 ;
        RECT  88.992 2.151 89.112 103.433 ;
        RECT  86.292 2.151 86.412 103.433 ;
        RECT  83.592 2.151 83.712 103.433 ;
        RECT  80.892 2.151 81.012 103.433 ;
        RECT  78.192 2.151 78.312 103.433 ;
        RECT  75.492 2.151 75.612 103.433 ;
        RECT  72.792 2.151 72.912 103.433 ;
        RECT  70.092 2.151 70.212 103.433 ;
        RECT  67.392 2.151 67.512 103.433 ;
        RECT  64.692 2.151 64.812 103.433 ;
        RECT  61.992 2.151 62.112 103.433 ;
        RECT  59.292 2.151 59.412 103.433 ;
        RECT  56.592 2.151 56.712 103.433 ;
        RECT  53.892 2.151 54.012 103.433 ;
        RECT  51.192 2.151 51.312 103.433 ;
        RECT  48.492 2.151 48.612 103.433 ;
        RECT  45.792 2.151 45.912 103.433 ;
        RECT  43.092 2.151 43.212 103.433 ;
        RECT  40.392 2.151 40.512 103.433 ;
        RECT  37.692 2.151 37.812 103.433 ;
        RECT  34.992 2.151 35.112 103.433 ;
        RECT  32.292 2.151 32.412 103.433 ;
        RECT  29.592 2.151 29.712 103.433 ;
        RECT  26.892 2.151 27.012 103.433 ;
        RECT  24.192 2.151 24.312 103.433 ;
        RECT  21.492 2.151 21.612 103.433 ;
        RECT  18.792 2.151 18.912 103.433 ;
        RECT  16.092 2.151 16.212 103.433 ;
        RECT  13.392 2.151 13.512 103.433 ;
        RECT  10.692 2.151 10.812 103.433 ;
        RECT  7.992 2.151 8.112 103.433 ;
        RECT  5.292 2.151 5.412 103.433 ;
        RECT  2.592 2.151 2.712 103.433 ;
    END
  END VDD
  PIN VSS
    DIRECTION INOUT ;
    USE GROUND ;
    PORT
      LAYER M5 ;
        RECT  99.6 2.137 99.72 103.419 ;
        RECT  96.9 2.137 97.02 103.419 ;
        RECT  94.2 2.137 94.32 103.419 ;
        RECT  91.5 2.137 91.62 103.419 ;
        RECT  88.8 2.137 88.92 103.419 ;
        RECT  86.1 2.137 86.22 103.419 ;
        RECT  83.4 2.137 83.52 103.419 ;
        RECT  80.7 2.137 80.82 103.419 ;
        RECT  78 2.137 78.12 103.419 ;
        RECT  75.3 2.137 75.42 103.419 ;
        RECT  72.6 2.137 72.72 103.419 ;
        RECT  69.9 2.137 70.02 103.419 ;
        RECT  67.2 2.137 67.32 103.419 ;
        RECT  64.5 2.137 64.62 103.419 ;
        RECT  61.8 2.137 61.92 103.419 ;
        RECT  59.1 2.137 59.22 103.419 ;
        RECT  56.4 2.137 56.52 103.419 ;
        RECT  53.7 2.137 53.82 103.419 ;
        RECT  51 2.137 51.12 103.419 ;
        RECT  48.3 2.137 48.42 103.419 ;
        RECT  45.6 2.137 45.72 103.419 ;
        RECT  42.9 2.137 43.02 103.419 ;
        RECT  40.2 2.137 40.32 103.419 ;
        RECT  37.5 2.137 37.62 103.419 ;
        RECT  34.8 2.137 34.92 103.419 ;
        RECT  32.1 2.137 32.22 103.419 ;
        RECT  29.4 2.137 29.52 103.419 ;
        RECT  26.7 2.137 26.82 103.419 ;
        RECT  24 2.137 24.12 103.419 ;
        RECT  21.3 2.137 21.42 103.419 ;
        RECT  18.6 2.137 18.72 103.419 ;
        RECT  15.9 2.137 16.02 103.419 ;
        RECT  13.2 2.137 13.32 103.419 ;
        RECT  10.5 2.137 10.62 103.419 ;
        RECT  7.8 2.137 7.92 103.419 ;
        RECT  5.1 2.137 5.22 103.419 ;
        RECT  2.4 2.137 2.52 103.419 ;
    END
  END VSS
  OBS
    LAYER RVTN ;
     RECT  2.16 2.16 101.898 2.295 ;
     RECT  2.16 2.565 101.898 2.835 ;
     RECT  2.16 3.105 101.898 3.375 ;
     RECT  2.16 3.645 101.898 3.915 ;
     RECT  2.16 4.185 101.898 4.455 ;
     RECT  2.16 4.725 101.898 4.995 ;
     RECT  2.16 5.265 101.898 5.535 ;
     RECT  2.16 5.805 101.898 6.075 ;
     RECT  2.16 6.345 101.898 6.615 ;
     RECT  2.16 6.885 101.898 7.155 ;
     RECT  2.16 7.425 101.898 7.695 ;
     RECT  2.16 7.965 101.898 8.235 ;
     RECT  2.16 8.505 101.898 8.775 ;
     RECT  2.16 9.045 101.898 9.315 ;
     RECT  2.16 9.585 101.898 9.855 ;
     RECT  2.16 10.125 101.898 10.395 ;
     RECT  2.16 10.665 101.898 10.935 ;
     RECT  2.16 11.205 101.898 11.475 ;
     RECT  2.16 11.745 101.898 12.015 ;
     RECT  2.16 12.285 101.898 12.555 ;
     RECT  2.16 12.825 101.898 13.095 ;
     RECT  2.16 13.365 101.898 13.635 ;
     RECT  2.16 13.905 101.898 14.175 ;
     RECT  2.16 14.445 101.898 14.715 ;
     RECT  2.16 14.985 101.898 15.255 ;
     RECT  2.16 15.525 101.898 15.795 ;
     RECT  2.16 16.065 101.898 16.335 ;
     RECT  2.16 16.605 101.898 16.875 ;
     RECT  2.16 17.145 101.898 17.415 ;
     RECT  2.16 17.685 101.898 17.955 ;
     RECT  2.16 18.225 101.898 18.495 ;
     RECT  2.16 18.765 101.898 19.035 ;
     RECT  2.16 19.305 101.898 19.575 ;
     RECT  2.16 19.845 101.898 20.115 ;
     RECT  2.16 20.385 101.898 20.655 ;
     RECT  2.16 20.925 101.898 21.195 ;
     RECT  2.16 21.465 101.898 21.735 ;
     RECT  2.16 22.005 101.898 22.275 ;
     RECT  2.16 22.545 101.898 22.815 ;
     RECT  2.16 23.085 101.898 23.355 ;
     RECT  2.16 23.625 101.898 23.895 ;
     RECT  2.16 24.165 101.898 24.435 ;
     RECT  2.16 24.705 101.898 24.975 ;
     RECT  2.16 25.245 101.898 25.515 ;
     RECT  2.16 25.785 101.898 26.055 ;
     RECT  2.16 26.325 101.898 26.595 ;
     RECT  2.16 26.865 101.898 27.135 ;
     RECT  2.16 27.405 101.898 27.675 ;
     RECT  2.16 27.945 101.898 28.215 ;
     RECT  2.16 28.485 101.898 28.755 ;
     RECT  2.16 29.025 101.898 29.295 ;
     RECT  2.16 29.565 101.898 29.835 ;
     RECT  2.16 30.105 101.898 30.375 ;
     RECT  2.16 30.645 101.898 30.915 ;
     RECT  2.16 31.185 101.898 31.455 ;
     RECT  2.16 31.725 101.898 31.995 ;
     RECT  2.16 32.265 101.898 32.535 ;
     RECT  2.16 32.805 101.898 33.075 ;
     RECT  2.16 33.345 101.898 33.615 ;
     RECT  2.16 33.885 101.898 34.155 ;
     RECT  2.16 34.425 101.898 34.695 ;
     RECT  2.16 34.965 101.898 35.235 ;
     RECT  2.16 35.505 101.898 35.775 ;
     RECT  2.16 36.045 101.898 36.315 ;
     RECT  2.16 36.585 101.898 36.855 ;
     RECT  2.16 37.125 101.898 37.395 ;
     RECT  2.16 37.665 101.898 37.935 ;
     RECT  2.16 38.205 101.898 38.475 ;
     RECT  2.16 38.745 101.898 39.015 ;
     RECT  2.16 39.285 101.898 39.555 ;
     RECT  2.16 39.825 101.898 40.095 ;
     RECT  2.16 40.365 101.898 40.635 ;
     RECT  2.16 40.905 101.898 41.175 ;
     RECT  2.16 41.445 101.898 41.715 ;
     RECT  2.16 41.985 101.898 42.255 ;
     RECT  2.16 42.525 101.898 42.795 ;
     RECT  2.16 43.065 101.898 43.335 ;
     RECT  2.16 43.605 101.898 43.875 ;
     RECT  2.16 44.145 101.898 44.415 ;
     RECT  2.16 44.685 101.898 44.955 ;
     RECT  2.16 45.225 101.898 45.495 ;
     RECT  2.16 45.765 101.898 46.035 ;
     RECT  2.16 46.305 101.898 46.575 ;
     RECT  2.16 46.845 101.898 47.115 ;
     RECT  2.16 47.385 101.898 47.655 ;
     RECT  2.16 47.925 101.898 48.195 ;
     RECT  2.16 48.465 101.898 48.735 ;
     RECT  2.16 49.005 101.898 49.275 ;
     RECT  2.16 49.545 101.898 49.815 ;
     RECT  2.16 50.085 101.898 50.355 ;
     RECT  2.16 50.625 101.898 50.895 ;
     RECT  2.16 51.165 101.898 51.435 ;
     RECT  2.16 51.705 101.898 51.975 ;
     RECT  2.16 52.245 101.898 52.515 ;
     RECT  2.16 52.785 101.898 53.055 ;
     RECT  2.16 53.325 101.898 53.595 ;
     RECT  2.16 53.865 101.898 54.135 ;
     RECT  2.16 54.405 101.898 54.675 ;
     RECT  2.16 54.945 101.898 55.215 ;
     RECT  2.16 55.485 101.898 55.755 ;
     RECT  2.16 56.025 101.898 56.295 ;
     RECT  2.16 56.565 101.898 56.835 ;
     RECT  2.16 57.105 101.898 57.375 ;
     RECT  2.16 57.645 101.898 57.915 ;
     RECT  2.16 58.185 101.898 58.455 ;
     RECT  2.16 58.725 101.898 58.995 ;
     RECT  2.16 59.265 101.898 59.535 ;
     RECT  2.16 59.805 101.898 60.075 ;
     RECT  2.16 60.345 101.898 60.615 ;
     RECT  2.16 60.885 101.898 61.155 ;
     RECT  2.16 61.425 101.898 61.695 ;
     RECT  2.16 61.965 101.898 62.235 ;
     RECT  2.16 62.505 101.898 62.775 ;
     RECT  2.16 63.045 101.898 63.315 ;
     RECT  2.16 63.585 101.898 63.855 ;
     RECT  2.16 64.125 101.898 64.395 ;
     RECT  2.16 64.665 101.898 64.935 ;
     RECT  2.16 65.205 101.898 65.475 ;
     RECT  2.16 65.745 101.898 66.015 ;
     RECT  2.16 66.285 101.898 66.555 ;
     RECT  2.16 66.825 101.898 67.095 ;
     RECT  2.16 67.365 101.898 67.635 ;
     RECT  2.16 67.905 101.898 68.175 ;
     RECT  2.16 68.445 101.898 68.715 ;
     RECT  2.16 68.985 101.898 69.255 ;
     RECT  2.16 69.525 101.898 69.795 ;
     RECT  2.16 70.065 101.898 70.335 ;
     RECT  2.16 70.605 101.898 70.875 ;
     RECT  2.16 71.145 101.898 71.415 ;
     RECT  2.16 71.685 101.898 71.955 ;
     RECT  2.16 72.225 101.898 72.495 ;
     RECT  2.16 72.765 101.898 73.035 ;
     RECT  2.16 73.305 101.898 73.575 ;
     RECT  2.16 73.845 101.898 74.115 ;
     RECT  2.16 74.385 101.898 74.655 ;
     RECT  2.16 74.925 101.898 75.195 ;
     RECT  2.16 75.465 101.898 75.735 ;
     RECT  2.16 76.005 101.898 76.275 ;
     RECT  2.16 76.545 101.898 76.815 ;
     RECT  2.16 77.085 101.898 77.355 ;
     RECT  2.16 77.625 101.898 77.895 ;
     RECT  2.16 78.165 101.898 78.435 ;
     RECT  2.16 78.705 101.898 78.975 ;
     RECT  2.16 79.245 101.898 79.515 ;
     RECT  2.16 79.785 101.898 80.055 ;
     RECT  2.16 80.325 101.898 80.595 ;
     RECT  2.16 80.865 101.898 81.135 ;
     RECT  2.16 81.405 101.898 81.675 ;
     RECT  2.16 81.945 101.898 82.215 ;
     RECT  2.16 82.485 101.898 82.755 ;
     RECT  2.16 83.025 101.898 83.295 ;
     RECT  2.16 83.565 101.898 83.835 ;
     RECT  2.16 84.105 101.898 84.375 ;
     RECT  2.16 84.645 101.898 84.915 ;
     RECT  2.16 85.185 101.898 85.455 ;
     RECT  2.16 85.725 101.898 85.995 ;
     RECT  2.16 86.265 101.898 86.535 ;
     RECT  2.16 86.805 101.898 87.075 ;
     RECT  2.16 87.345 101.898 87.615 ;
     RECT  2.16 87.885 101.898 88.155 ;
     RECT  2.16 88.425 101.898 88.695 ;
     RECT  2.16 88.965 101.898 89.235 ;
     RECT  2.16 89.505 101.898 89.775 ;
     RECT  2.16 90.045 101.898 90.315 ;
     RECT  2.16 90.585 101.898 90.855 ;
     RECT  2.16 91.125 101.898 91.395 ;
     RECT  2.16 91.665 101.898 91.935 ;
     RECT  2.16 92.205 101.898 92.475 ;
     RECT  2.16 92.745 101.898 93.015 ;
     RECT  2.16 93.285 101.898 93.555 ;
     RECT  2.16 93.825 101.898 94.095 ;
     RECT  2.16 94.365 101.898 94.635 ;
     RECT  2.16 94.905 101.898 95.175 ;
     RECT  2.16 95.445 101.898 95.715 ;
     RECT  2.16 95.985 101.898 96.255 ;
     RECT  2.16 96.525 101.898 96.795 ;
     RECT  2.16 97.065 101.898 97.335 ;
     RECT  2.16 97.605 101.898 97.875 ;
     RECT  2.16 98.145 101.898 98.415 ;
     RECT  2.16 98.685 101.898 98.955 ;
     RECT  2.16 99.225 101.898 99.495 ;
     RECT  2.16 99.765 101.898 100.035 ;
     RECT  2.16 100.305 101.898 100.575 ;
     RECT  2.16 100.845 101.898 101.115 ;
     RECT  2.16 101.385 101.898 101.655 ;
     RECT  2.16 101.925 101.898 102.195 ;
     RECT  2.16 102.465 101.898 102.735 ;
     RECT  2.16 103.005 101.898 103.275 ;
    LAYER RVTP ;
     RECT  2.16 2.295 101.898 2.565 ;
     RECT  2.16 2.835 101.898 3.105 ;
     RECT  2.16 3.375 101.898 3.645 ;
     RECT  2.16 3.915 101.898 4.185 ;
     RECT  2.16 4.455 101.898 4.725 ;
     RECT  2.16 4.995 101.898 5.265 ;
     RECT  2.16 5.535 101.898 5.805 ;
     RECT  2.16 6.075 101.898 6.345 ;
     RECT  2.16 6.615 101.898 6.885 ;
     RECT  2.16 7.155 101.898 7.425 ;
     RECT  2.16 7.695 101.898 7.965 ;
     RECT  2.16 8.235 101.898 8.505 ;
     RECT  2.16 8.775 101.898 9.045 ;
     RECT  2.16 9.315 101.898 9.585 ;
     RECT  2.16 9.855 101.898 10.125 ;
     RECT  2.16 10.395 101.898 10.665 ;
     RECT  2.16 10.935 101.898 11.205 ;
     RECT  2.16 11.475 101.898 11.745 ;
     RECT  2.16 12.015 101.898 12.285 ;
     RECT  2.16 12.555 101.898 12.825 ;
     RECT  2.16 13.095 101.898 13.365 ;
     RECT  2.16 13.635 101.898 13.905 ;
     RECT  2.16 14.175 101.898 14.445 ;
     RECT  2.16 14.715 101.898 14.985 ;
     RECT  2.16 15.255 101.898 15.525 ;
     RECT  2.16 15.795 101.898 16.065 ;
     RECT  2.16 16.335 101.898 16.605 ;
     RECT  2.16 16.875 101.898 17.145 ;
     RECT  2.16 17.415 101.898 17.685 ;
     RECT  2.16 17.955 101.898 18.225 ;
     RECT  2.16 18.495 101.898 18.765 ;
     RECT  2.16 19.035 101.898 19.305 ;
     RECT  2.16 19.575 101.898 19.845 ;
     RECT  2.16 20.115 101.898 20.385 ;
     RECT  2.16 20.655 101.898 20.925 ;
     RECT  2.16 21.195 101.898 21.465 ;
     RECT  2.16 21.735 101.898 22.005 ;
     RECT  2.16 22.275 101.898 22.545 ;
     RECT  2.16 22.815 101.898 23.085 ;
     RECT  2.16 23.355 101.898 23.625 ;
     RECT  2.16 23.895 101.898 24.165 ;
     RECT  2.16 24.435 101.898 24.705 ;
     RECT  2.16 24.975 101.898 25.245 ;
     RECT  2.16 25.515 101.898 25.785 ;
     RECT  2.16 26.055 101.898 26.325 ;
     RECT  2.16 26.595 101.898 26.865 ;
     RECT  2.16 27.135 101.898 27.405 ;
     RECT  2.16 27.675 101.898 27.945 ;
     RECT  2.16 28.215 101.898 28.485 ;
     RECT  2.16 28.755 101.898 29.025 ;
     RECT  2.16 29.295 101.898 29.565 ;
     RECT  2.16 29.835 101.898 30.105 ;
     RECT  2.16 30.375 101.898 30.645 ;
     RECT  2.16 30.915 101.898 31.185 ;
     RECT  2.16 31.455 101.898 31.725 ;
     RECT  2.16 31.995 101.898 32.265 ;
     RECT  2.16 32.535 101.898 32.805 ;
     RECT  2.16 33.075 101.898 33.345 ;
     RECT  2.16 33.615 101.898 33.885 ;
     RECT  2.16 34.155 101.898 34.425 ;
     RECT  2.16 34.695 101.898 34.965 ;
     RECT  2.16 35.235 101.898 35.505 ;
     RECT  2.16 35.775 101.898 36.045 ;
     RECT  2.16 36.315 101.898 36.585 ;
     RECT  2.16 36.855 101.898 37.125 ;
     RECT  2.16 37.395 101.898 37.665 ;
     RECT  2.16 37.935 101.898 38.205 ;
     RECT  2.16 38.475 101.898 38.745 ;
     RECT  2.16 39.015 101.898 39.285 ;
     RECT  2.16 39.555 101.898 39.825 ;
     RECT  2.16 40.095 101.898 40.365 ;
     RECT  2.16 40.635 101.898 40.905 ;
     RECT  2.16 41.175 101.898 41.445 ;
     RECT  2.16 41.715 101.898 41.985 ;
     RECT  2.16 42.255 101.898 42.525 ;
     RECT  2.16 42.795 101.898 43.065 ;
     RECT  2.16 43.335 101.898 43.605 ;
     RECT  2.16 43.875 101.898 44.145 ;
     RECT  2.16 44.415 101.898 44.685 ;
     RECT  2.16 44.955 101.898 45.225 ;
     RECT  2.16 45.495 101.898 45.765 ;
     RECT  2.16 46.035 101.898 46.305 ;
     RECT  2.16 46.575 101.898 46.845 ;
     RECT  2.16 47.115 101.898 47.385 ;
     RECT  2.16 47.655 101.898 47.925 ;
     RECT  2.16 48.195 101.898 48.465 ;
     RECT  2.16 48.735 101.898 49.005 ;
     RECT  2.16 49.275 101.898 49.545 ;
     RECT  2.16 49.815 101.898 50.085 ;
     RECT  2.16 50.355 101.898 50.625 ;
     RECT  2.16 50.895 101.898 51.165 ;
     RECT  2.16 51.435 101.898 51.705 ;
     RECT  2.16 51.975 101.898 52.245 ;
     RECT  2.16 52.515 101.898 52.785 ;
     RECT  2.16 53.055 101.898 53.325 ;
     RECT  2.16 53.595 101.898 53.865 ;
     RECT  2.16 54.135 101.898 54.405 ;
     RECT  2.16 54.675 101.898 54.945 ;
     RECT  2.16 55.215 101.898 55.485 ;
     RECT  2.16 55.755 101.898 56.025 ;
     RECT  2.16 56.295 101.898 56.565 ;
     RECT  2.16 56.835 101.898 57.105 ;
     RECT  2.16 57.375 101.898 57.645 ;
     RECT  2.16 57.915 101.898 58.185 ;
     RECT  2.16 58.455 101.898 58.725 ;
     RECT  2.16 58.995 101.898 59.265 ;
     RECT  2.16 59.535 101.898 59.805 ;
     RECT  2.16 60.075 101.898 60.345 ;
     RECT  2.16 60.615 101.898 60.885 ;
     RECT  2.16 61.155 101.898 61.425 ;
     RECT  2.16 61.695 101.898 61.965 ;
     RECT  2.16 62.235 101.898 62.505 ;
     RECT  2.16 62.775 101.898 63.045 ;
     RECT  2.16 63.315 101.898 63.585 ;
     RECT  2.16 63.855 101.898 64.125 ;
     RECT  2.16 64.395 101.898 64.665 ;
     RECT  2.16 64.935 101.898 65.205 ;
     RECT  2.16 65.475 101.898 65.745 ;
     RECT  2.16 66.015 101.898 66.285 ;
     RECT  2.16 66.555 101.898 66.825 ;
     RECT  2.16 67.095 101.898 67.365 ;
     RECT  2.16 67.635 101.898 67.905 ;
     RECT  2.16 68.175 101.898 68.445 ;
     RECT  2.16 68.715 101.898 68.985 ;
     RECT  2.16 69.255 101.898 69.525 ;
     RECT  2.16 69.795 101.898 70.065 ;
     RECT  2.16 70.335 101.898 70.605 ;
     RECT  2.16 70.875 101.898 71.145 ;
     RECT  2.16 71.415 101.898 71.685 ;
     RECT  2.16 71.955 101.898 72.225 ;
     RECT  2.16 72.495 101.898 72.765 ;
     RECT  2.16 73.035 101.898 73.305 ;
     RECT  2.16 73.575 101.898 73.845 ;
     RECT  2.16 74.115 101.898 74.385 ;
     RECT  2.16 74.655 101.898 74.925 ;
     RECT  2.16 75.195 101.898 75.465 ;
     RECT  2.16 75.735 101.898 76.005 ;
     RECT  2.16 76.275 101.898 76.545 ;
     RECT  2.16 76.815 101.898 77.085 ;
     RECT  2.16 77.355 101.898 77.625 ;
     RECT  2.16 77.895 101.898 78.165 ;
     RECT  2.16 78.435 101.898 78.705 ;
     RECT  2.16 78.975 101.898 79.245 ;
     RECT  2.16 79.515 101.898 79.785 ;
     RECT  2.16 80.055 101.898 80.325 ;
     RECT  2.16 80.595 101.898 80.865 ;
     RECT  2.16 81.135 101.898 81.405 ;
     RECT  2.16 81.675 101.898 81.945 ;
     RECT  2.16 82.215 101.898 82.485 ;
     RECT  2.16 82.755 101.898 83.025 ;
     RECT  2.16 83.295 101.898 83.565 ;
     RECT  2.16 83.835 101.898 84.105 ;
     RECT  2.16 84.375 101.898 84.645 ;
     RECT  2.16 84.915 101.898 85.185 ;
     RECT  2.16 85.455 101.898 85.725 ;
     RECT  2.16 85.995 101.898 86.265 ;
     RECT  2.16 86.535 101.898 86.805 ;
     RECT  2.16 87.075 101.898 87.345 ;
     RECT  2.16 87.615 101.898 87.885 ;
     RECT  2.16 88.155 101.898 88.425 ;
     RECT  2.16 88.695 101.898 88.965 ;
     RECT  2.16 89.235 101.898 89.505 ;
     RECT  2.16 89.775 101.898 90.045 ;
     RECT  2.16 90.315 101.898 90.585 ;
     RECT  2.16 90.855 101.898 91.125 ;
     RECT  2.16 91.395 101.898 91.665 ;
     RECT  2.16 91.935 101.898 92.205 ;
     RECT  2.16 92.475 101.898 92.745 ;
     RECT  2.16 93.015 101.898 93.285 ;
     RECT  2.16 93.555 101.898 93.825 ;
     RECT  2.16 94.095 101.898 94.365 ;
     RECT  2.16 94.635 101.898 94.905 ;
     RECT  2.16 95.175 101.898 95.445 ;
     RECT  2.16 95.715 101.898 95.985 ;
     RECT  2.16 96.255 101.898 96.525 ;
     RECT  2.16 96.795 101.898 97.065 ;
     RECT  2.16 97.335 101.898 97.605 ;
     RECT  2.16 97.875 101.898 98.145 ;
     RECT  2.16 98.415 101.898 98.685 ;
     RECT  2.16 98.955 101.898 99.225 ;
     RECT  2.16 99.495 101.898 99.765 ;
     RECT  2.16 100.035 101.898 100.305 ;
     RECT  2.16 100.575 101.898 100.845 ;
     RECT  2.16 101.115 101.898 101.385 ;
     RECT  2.16 101.655 101.898 101.925 ;
     RECT  2.16 102.195 101.898 102.465 ;
     RECT  2.16 102.735 101.898 103.005 ;
     RECT  2.16 103.275 101.898 103.41 ;
    LAYER M1 ;
     RECT  2.16 2.151 101.898 103.419 ;
    LAYER M2 ;
     RECT  31.963 105.678 32.035 105.696 ;
     RECT  32.035 105.606 32.071 105.696 ;
     RECT  2.16 2.151 32.251 103.419 ;
     RECT  32.071 105.606 32.431 105.768 ;
     RECT  32.251 2.151 32.827 103.644 ;
     RECT  32.431 105.516 33.655 105.768 ;
     RECT  33.655 104.868 33.755 105.768 ;
     RECT  33.755 105.516 34.951 105.768 ;
     RECT  32.827 2.151 35.095 103.689 ;
     RECT  35.095 2.151 35.375 103.734 ;
     RECT  34.951 104.796 35.879 105.768 ;
     RECT  35.879 105.516 36.419 105.768 ;
     RECT  35.375 2.151 36.491 103.572 ;
     RECT  36.419 105.606 37.247 105.768 ;
     RECT  37.247 105.606 37.327 105.732 ;
     RECT  37.327 105.561 37.615 105.732 ;
     RECT  37.615 105.516 37.651 105.732 ;
     RECT  36.491 2.151 37.687 103.536 ;
     RECT  37.687 2.151 38.047 103.572 ;
     RECT  37.651 104.796 38.191 105.732 ;
     RECT  38.047 2.151 38.471 103.734 ;
     RECT  38.191 104.796 38.587 105.768 ;
     RECT  38.587 104.751 38.723 105.768 ;
     RECT  38.723 104.751 38.759 104.769 ;
     RECT  38.723 105.561 39.919 105.768 ;
     RECT  38.471 2.151 40.531 103.644 ;
     RECT  39.919 104.868 40.567 105.768 ;
     RECT  40.567 104.706 40.739 105.768 ;
     RECT  40.739 104.796 40.775 105.768 ;
     RECT  40.775 104.868 40.919 105.768 ;
     RECT  40.919 105.516 41.351 105.768 ;
     RECT  41.351 105.561 42.475 105.768 ;
     RECT  40.531 2.151 42.511 103.689 ;
     RECT  42.475 104.868 42.835 105.768 ;
     RECT  42.835 104.706 43.223 105.768 ;
     RECT  43.223 104.796 43.799 105.768 ;
     RECT  43.799 104.868 45.211 105.768 ;
     RECT  45.211 104.796 46.103 105.768 ;
     RECT  46.103 105.606 46.175 105.768 ;
     RECT  46.795 104.67 46.867 104.688 ;
     RECT  46.867 104.67 47.011 104.886 ;
     RECT  46.175 105.678 47.011 105.768 ;
     RECT  47.011 104.67 47.147 105.768 ;
     RECT  47.147 104.868 47.615 105.768 ;
     RECT  47.615 105.561 48.451 105.768 ;
     RECT  48.451 104.868 48.631 105.768 ;
     RECT  48.631 104.796 48.731 105.768 ;
     RECT  42.511 2.151 48.911 103.734 ;
     RECT  48.731 104.868 49.451 105.768 ;
     RECT  49.451 105.642 49.559 105.768 ;
     RECT  49.451 104.868 50.287 104.886 ;
     RECT  49.559 105.678 50.287 105.768 ;
     RECT  50.287 104.868 50.575 105.768 ;
     RECT  50.575 104.832 50.791 105.768 ;
     RECT  50.791 104.706 50.927 105.768 ;
     RECT  50.927 104.868 52.439 105.768 ;
     RECT  48.911 2.151 52.879 103.689 ;
     RECT  52.879 2.151 53.167 103.878 ;
     RECT  53.167 2.151 53.303 103.959 ;
     RECT  52.439 105.561 53.383 105.768 ;
     RECT  53.383 104.868 54.895 105.768 ;
     RECT  54.895 104.67 54.995 105.768 ;
     RECT  54.995 104.706 55.751 105.768 ;
     RECT  55.751 104.706 55.787 104.769 ;
     RECT  55.751 105.561 55.859 105.768 ;
     RECT  55.903 104.598 56.695 104.616 ;
     RECT  56.695 104.598 56.803 104.652 ;
     RECT  55.859 105.606 56.803 105.768 ;
     RECT  53.303 2.151 58.855 103.734 ;
     RECT  58.855 2.151 59.431 103.77 ;
     RECT  59.431 2.151 59.675 103.842 ;
     RECT  59.675 2.151 59.855 103.77 ;
     RECT  56.803 104.598 60.107 105.768 ;
     RECT  60.107 105.516 60.287 105.768 ;
     RECT  60.287 105.516 60.323 105.624 ;
     RECT  60.323 105.561 60.359 105.624 ;
     RECT  60.359 105.561 60.431 105.579 ;
     RECT  60.107 104.598 61.259 104.652 ;
     RECT  61.259 104.598 61.439 104.616 ;
     RECT  59.855 2.151 66.731 103.734 ;
     RECT  66.731 2.151 67.271 103.644 ;
     RECT  67.271 2.151 71.519 103.572 ;
     RECT  71.519 2.151 84.623 103.536 ;
     RECT  84.623 2.151 101.898 103.419 ;
     RECT  101.898 32.166 101.903 35.694 ;
     RECT  101.898 41.616 102.011 76.734 ;
     RECT  101.898 20.592 102.047 20.844 ;
     RECT  101.898 21.816 102.047 26.424 ;
     RECT  102.011 41.616 102.047 52.974 ;
     RECT  101.898 90.486 102.299 90.504 ;
     RECT  101.898 30.996 102.371 31.374 ;
     RECT  101.898 81.306 102.371 81.324 ;
     RECT  102.011 53.874 102.407 76.734 ;
     RECT  102.047 21.816 102.551 23.274 ;
     RECT  102.047 20.592 102.587 20.718 ;
     RECT  102.047 41.616 102.587 48.798 ;
     RECT  102.407 53.874 102.587 65.574 ;
     RECT  102.407 66.33 102.587 76.734 ;
     RECT  101.898 77.706 102.587 80.514 ;
     RECT  102.047 24.336 102.623 26.352 ;
     RECT  101.903 32.166 102.623 35.424 ;
     RECT  101.898 38.376 102.623 40.824 ;
     RECT  102.587 41.616 102.623 44.208 ;
     RECT  102.587 56.196 102.623 65.394 ;
     RECT  102.587 73.656 102.623 76.734 ;
     RECT  102.623 40.806 102.659 40.824 ;
     RECT  102.587 45.036 102.659 48.798 ;
     RECT  102.047 49.986 102.659 52.974 ;
     RECT  102.623 56.196 102.659 59.634 ;
     RECT  102.623 63.324 102.659 63.684 ;
     RECT  102.623 74.088 102.659 74.106 ;
     RECT  102.659 48.78 102.695 48.798 ;
     RECT  102.659 56.196 102.695 56.52 ;
     RECT  102.587 66.33 102.695 67.158 ;
     RECT  102.623 75.168 102.875 76.734 ;
     RECT  102.623 42.732 102.911 44.208 ;
     RECT  102.623 41.616 102.947 41.904 ;
     RECT  102.623 38.376 102.983 40.014 ;
     RECT  102.947 41.616 103.019 41.634 ;
     RECT  102.983 38.376 103.055 39.078 ;
     RECT  102.623 24.336 103.091 24.624 ;
     RECT  102.371 30.996 103.091 31.014 ;
     RECT  102.659 45.036 103.091 47.034 ;
     RECT  103.055 38.484 103.127 39.078 ;
     RECT  102.587 67.95 103.163 72.864 ;
     RECT  102.587 20.7 103.199 20.718 ;
     RECT  102.551 21.816 103.199 23.184 ;
     RECT  103.091 24.336 103.199 24.354 ;
     RECT  102.623 25.524 103.199 26.352 ;
     RECT  101.898 29.34 103.199 29.358 ;
     RECT  102.623 32.166 103.199 33.804 ;
     RECT  102.623 34.776 103.199 34.794 ;
     RECT  103.127 38.484 103.199 38.538 ;
     RECT  102.911 42.732 103.199 42.75 ;
     RECT  102.911 43.686 103.199 44.208 ;
     RECT  103.091 45.036 103.199 46.872 ;
     RECT  102.659 47.862 103.199 47.88 ;
     RECT  102.659 49.986 103.199 52.002 ;
     RECT  102.659 52.956 103.199 52.974 ;
     RECT  102.587 53.874 103.199 55.404 ;
     RECT  102.695 56.196 103.199 56.214 ;
     RECT  102.659 57.384 103.199 59.634 ;
     RECT  102.623 60.516 103.199 61.452 ;
     RECT  102.623 62.28 103.199 62.298 ;
     RECT  102.623 64.44 103.199 65.394 ;
     RECT  102.695 66.528 103.199 67.158 ;
     RECT  103.163 67.986 103.199 72.864 ;
     RECT  102.875 75.168 103.199 76.194 ;
     RECT  102.587 77.706 103.199 80.244 ;
     RECT  103.199 22.176 103.235 23.184 ;
     RECT  103.199 26.226 103.235 26.244 ;
     RECT  103.199 45.036 103.235 45.909 ;
     RECT  103.199 49.986 103.235 51.498 ;
     RECT  103.199 53.874 103.235 53.892 ;
     RECT  103.199 54.648 103.235 54.666 ;
     RECT  103.199 58.536 103.235 59.526 ;
     RECT  103.199 61.434 103.235 61.452 ;
     RECT  103.199 66.6 103.235 67.158 ;
     RECT  103.199 72.126 103.235 72.144 ;
     RECT  103.199 77.706 103.235 78.462 ;
     RECT  103.199 79.758 103.235 79.776 ;
     RECT  103.199 38.484 103.271 38.502 ;
     RECT  103.235 45.162 103.271 45.909 ;
     RECT  103.235 50.706 103.271 51.084 ;
     RECT  103.235 58.536 103.271 58.554 ;
     RECT  103.235 77.868 103.271 78.462 ;
     RECT  103.235 59.508 103.307 59.526 ;
     RECT  103.199 32.238 103.811 33.372 ;
     RECT  103.811 33.354 103.847 33.372 ;
     RECT  103.235 22.824 103.883 23.184 ;
     RECT  103.811 32.238 103.883 32.256 ;
     RECT  102.983 39.996 103.883 40.014 ;
     RECT  103.883 22.824 103.919 23.004 ;
     RECT  103.199 44.046 103.919 44.208 ;
     RECT  103.235 66.6 103.927 66.888 ;
     RECT  101.898 37.566 103.955 37.584 ;
     RECT  103.271 45.891 103.955 45.909 ;
     RECT  103.199 69.966 103.955 69.984 ;
     RECT  103.927 53.496 103.963 53.514 ;
     RECT  103.927 65.871 103.963 66.888 ;
     RECT  103.919 44.046 103.991 44.064 ;
     RECT  103.919 22.824 104.027 22.914 ;
     RECT  103.199 57.546 104.027 57.564 ;
     RECT  104.027 22.896 104.063 22.914 ;
     RECT  103.271 50.751 104.063 50.769 ;
     RECT  103.963 52.371 104.063 52.389 ;
     RECT  103.963 53.406 104.063 53.514 ;
     RECT  103.963 65.871 104.063 67.014 ;
     RECT  103.963 73.35 104.063 73.989 ;
     RECT  103.963 75.006 104.063 75.024 ;
    LAYER M3 ;
     RECT  2.415 2.143 2.505 2.413 ;
     RECT  5.115 2.143 5.205 2.413 ;
     RECT  7.815 2.143 7.905 2.413 ;
     RECT  10.515 2.143 10.605 2.413 ;
     RECT  13.215 2.143 13.305 2.413 ;
     RECT  15.915 2.143 16.005 2.413 ;
     RECT  18.615 2.143 18.705 2.413 ;
     RECT  21.315 2.143 21.405 2.413 ;
     RECT  24.015 2.143 24.105 2.413 ;
     RECT  26.715 2.143 26.805 2.413 ;
     RECT  29.415 2.143 29.505 2.413 ;
     RECT  32.115 2.143 32.205 2.413 ;
     RECT  34.815 2.143 34.905 2.413 ;
     RECT  37.515 2.143 37.605 2.413 ;
     RECT  40.215 2.143 40.305 2.413 ;
     RECT  42.915 2.143 43.005 2.413 ;
     RECT  45.615 2.143 45.705 2.413 ;
     RECT  48.315 2.143 48.405 2.413 ;
     RECT  51.015 2.143 51.105 2.413 ;
     RECT  53.715 2.143 53.805 2.413 ;
     RECT  56.415 2.143 56.505 2.413 ;
     RECT  59.115 2.143 59.205 2.413 ;
     RECT  61.815 2.143 61.905 2.413 ;
     RECT  64.515 2.143 64.605 2.413 ;
     RECT  67.215 2.143 67.305 2.413 ;
     RECT  69.915 2.143 70.005 2.413 ;
     RECT  72.615 2.143 72.705 2.413 ;
     RECT  75.315 2.143 75.405 2.413 ;
     RECT  78.015 2.143 78.105 2.413 ;
     RECT  80.715 2.143 80.805 2.413 ;
     RECT  83.415 2.143 83.505 2.413 ;
     RECT  86.115 2.143 86.205 2.413 ;
     RECT  88.815 2.143 88.905 2.413 ;
     RECT  91.515 2.143 91.605 2.413 ;
     RECT  94.215 2.143 94.305 2.413 ;
     RECT  96.915 2.143 97.005 2.413 ;
     RECT  99.615 2.143 99.705 2.413 ;
     RECT  103.968 19.915 103.986 20.011 ;
     RECT  99.615 2.413 99.897 20.395 ;
     RECT  102.42 20.203 102.438 20.491 ;
     RECT  101.844 20.491 102.438 20.587 ;
     RECT  103.176 20.299 103.194 20.587 ;
     RECT  99.615 20.395 100.278 20.659 ;
     RECT  96.915 2.413 97.197 20.695 ;
     RECT  101.844 20.587 103.194 20.723 ;
     RECT  103.932 20.011 103.986 20.779 ;
     RECT  86.115 2.413 86.397 20.857 ;
     RECT  99.615 20.659 100.854 21.163 ;
     RECT  99.615 21.163 100.962 21.259 ;
     RECT  101.844 20.723 103.086 21.259 ;
     RECT  64.515 2.413 64.797 21.361 ;
     RECT  99.615 21.259 103.086 21.643 ;
     RECT  103.896 20.779 103.986 21.643 ;
     RECT  66.168 21.811 66.186 21.929 ;
     RECT  99.615 21.643 103.986 22.739 ;
     RECT  103.824 22.739 103.986 22.819 ;
     RECT  103.824 22.819 104.022 22.891 ;
     RECT  103.824 22.891 104.058 23.009 ;
     RECT  103.86 23.009 104.058 23.189 ;
     RECT  75.315 2.413 75.597 23.323 ;
     RECT  99.615 22.739 103.086 23.665 ;
     RECT  41.904 23.017 41.922 23.827 ;
     RECT  99.108 23.665 103.086 24.043 ;
     RECT  103.896 23.189 104.058 24.043 ;
     RECT  78.015 2.413 78.297 24.907 ;
     RECT  76.788 22.477 76.806 25.447 ;
     RECT  96.915 20.695 97.758 25.717 ;
     RECT  96.915 25.717 98.37 25.979 ;
     RECT  63.072 25.177 63.09 25.987 ;
     RECT  64.116 21.361 64.797 25.987 ;
     RECT  91.515 2.413 91.797 25.987 ;
     RECT  94.215 2.413 94.497 26.023 ;
     RECT  69.915 2.413 70.197 26.107 ;
     RECT  85.752 20.857 86.397 26.251 ;
     RECT  68.652 23.287 68.67 26.257 ;
     RECT  95.4 22.207 95.418 26.293 ;
     RECT  69.516 26.107 70.197 26.347 ;
     RECT  77.94 24.907 78.297 26.347 ;
     RECT  85.752 26.251 86.67 26.347 ;
     RECT  90.9 25.987 91.797 26.347 ;
     RECT  98.352 25.979 98.37 26.347 ;
     RECT  99.108 24.043 104.058 26.347 ;
     RECT  98.352 26.347 104.058 26.357 ;
     RECT  95.4 26.293 96.066 26.365 ;
     RECT  96.915 25.979 97.197 26.365 ;
     RECT  77.94 26.347 78.678 26.491 ;
     RECT  79.488 25.483 79.506 26.491 ;
     RECT  56.415 2.413 56.697 26.539 ;
     RECT  48.315 2.413 48.597 26.587 ;
     RECT  73.944 24.367 73.962 26.587 ;
     RECT  74.952 23.323 75.597 26.587 ;
     RECT  85.752 26.347 86.706 26.621 ;
     RECT  90.648 26.347 91.797 26.621 ;
     RECT  63.072 25.987 64.797 26.635 ;
     RECT  69.516 26.347 70.722 26.797 ;
     RECT  56.124 26.539 56.697 27.115 ;
     RECT  61.815 2.413 62.097 27.163 ;
     RECT  63 26.635 64.797 27.163 ;
     RECT  80.715 2.413 80.997 27.301 ;
     RECT  90.9 26.621 91.797 27.301 ;
     RECT  92.556 22.747 92.574 27.301 ;
     RECT  53.715 2.413 53.997 27.307 ;
     RECT  54.72 27.163 54.738 27.307 ;
     RECT  80.715 27.301 81.09 27.341 ;
     RECT  90.9 27.301 92.574 27.341 ;
     RECT  73.944 26.587 75.597 27.403 ;
     RECT  76.5 25.447 76.806 27.403 ;
     RECT  85.752 26.621 86.397 27.451 ;
     RECT  90.9 27.341 91.797 27.451 ;
     RECT  93.744 26.023 94.497 27.451 ;
     RECT  53.715 27.307 54.738 27.595 ;
     RECT  58.356 20.107 58.374 27.643 ;
     RECT  61.815 27.163 64.797 27.773 ;
     RECT  90.648 27.451 91.797 27.773 ;
     RECT  93.744 27.451 94.59 27.773 ;
     RECT  47.592 26.587 48.597 27.883 ;
     RECT  85.752 27.451 86.49 28.123 ;
     RECT  53.352 27.595 54.738 28.171 ;
     RECT  55.548 27.115 56.697 28.171 ;
     RECT  61.815 27.773 62.097 28.219 ;
     RECT  51.015 2.413 51.297 28.459 ;
     RECT  93.744 27.773 94.497 28.507 ;
     RECT  98.352 26.357 103.086 28.555 ;
     RECT  103.896 26.357 104.058 28.555 ;
     RECT  61.524 28.219 62.097 28.651 ;
     RECT  63 27.773 64.797 28.651 ;
     RECT  85.752 28.123 86.67 28.651 ;
     RECT  85.752 28.651 86.778 28.781 ;
     RECT  47.052 27.883 48.597 28.939 ;
     RECT  60.732 27.691 60.75 29.035 ;
     RECT  60.192 29.035 60.75 29.227 ;
     RECT  61.524 28.651 64.797 29.227 ;
     RECT  53.352 28.171 56.697 29.335 ;
     RECT  45.615 2.413 45.897 29.467 ;
     RECT  47.016 28.939 48.597 29.467 ;
     RECT  90.9 27.773 91.797 29.467 ;
     RECT  93.744 28.507 94.518 29.467 ;
     RECT  52.74 29.335 56.697 29.611 ;
     RECT  60.192 29.227 64.797 29.803 ;
     RECT  85.752 28.781 86.49 29.933 ;
     RECT  90.648 29.467 91.797 29.933 ;
     RECT  93.744 29.467 94.59 29.933 ;
     RECT  69.516 26.797 70.974 30.173 ;
     RECT  41.58 23.827 41.922 30.181 ;
     RECT  41.508 30.181 41.922 30.221 ;
     RECT  98.352 28.555 104.058 30.283 ;
     RECT  52.704 29.611 56.697 30.379 ;
     RECT  57.816 27.643 58.374 30.379 ;
     RECT  51.015 28.459 51.642 30.571 ;
     RECT  52.704 30.379 58.374 30.571 ;
     RECT  51.015 30.571 58.374 30.667 ;
     RECT  59.115 2.413 59.397 30.667 ;
     RECT  83.415 2.413 83.697 30.721 ;
     RECT  69.516 30.173 70.197 30.907 ;
     RECT  70.956 30.173 70.974 30.907 ;
     RECT  85.752 29.933 86.397 30.907 ;
     RECT  90.9 29.933 91.797 30.907 ;
     RECT  93.744 29.933 94.497 30.907 ;
     RECT  67.215 2.413 67.497 30.991 ;
     RECT  68.652 26.257 68.706 30.991 ;
     RECT  83.376 30.721 83.697 31.019 ;
     RECT  98.316 30.283 104.058 31.019 ;
     RECT  67.215 30.991 68.706 31.109 ;
     RECT  45.615 29.467 48.597 31.117 ;
     RECT  42.915 2.413 43.197 31.153 ;
     RECT  44.136 30.451 44.154 31.153 ;
     RECT  88.056 27.979 88.074 31.243 ;
     RECT  88.815 2.413 89.097 31.243 ;
     RECT  88.056 31.243 89.097 31.289 ;
     RECT  85.752 30.907 86.454 31.387 ;
     RECT  82.368 21.937 82.386 31.483 ;
     RECT  93.744 30.907 94.554 31.483 ;
     RECT  42.915 31.153 44.154 31.621 ;
     RECT  73.944 27.403 76.806 31.649 ;
     RECT  85.752 31.387 86.49 31.661 ;
     RECT  90.648 30.907 91.797 31.661 ;
     RECT  93.744 31.483 94.59 31.661 ;
     RECT  82.368 31.483 82.674 31.757 ;
     RECT  69.516 30.907 70.974 31.805 ;
     RECT  98.316 31.019 103.05 32.161 ;
     RECT  103.788 31.019 104.058 32.161 ;
     RECT  42.915 31.621 44.226 32.269 ;
     RECT  45.108 31.117 48.597 32.269 ;
     RECT  77.94 26.491 79.506 32.297 ;
     RECT  33.444 32.197 33.462 32.737 ;
     RECT  98.316 32.161 104.058 32.801 ;
     RECT  93.744 31.661 94.497 33.007 ;
     RECT  95.4 26.365 97.197 33.007 ;
     RECT  79.2 32.297 79.506 33.277 ;
     RECT  80.715 27.341 80.997 33.277 ;
     RECT  73.944 31.649 75.597 33.413 ;
     RECT  34.815 2.413 35.097 33.547 ;
     RECT  98.352 32.801 104.058 33.809 ;
     RECT  98.352 33.809 103.122 33.817 ;
     RECT  76.356 31.649 76.806 34.079 ;
     RECT  93.744 33.007 97.197 34.159 ;
     RECT  98.316 33.817 103.122 34.159 ;
     RECT  34.815 33.547 35.802 34.357 ;
     RECT  34.815 34.357 35.874 34.393 ;
     RECT  79.2 33.277 80.997 34.493 ;
     RECT  93.744 34.159 103.122 34.603 ;
     RECT  103.86 33.809 104.058 34.603 ;
     RECT  34.815 34.393 35.946 34.627 ;
     RECT  87.264 34.771 87.282 34.889 ;
     RECT  73.944 33.413 73.962 34.969 ;
     RECT  74.952 33.413 75.597 34.969 ;
     RECT  77.94 32.297 78.297 34.969 ;
     RECT  85.752 31.661 86.397 35.005 ;
     RECT  92.556 27.341 92.574 35.203 ;
     RECT  93.744 34.603 104.058 35.203 ;
     RECT  77.94 34.969 78.426 35.239 ;
     RECT  77.94 35.239 78.462 35.339 ;
     RECT  41.904 30.221 41.922 35.429 ;
     RECT  88.056 31.289 88.074 35.609 ;
     RECT  41.832 35.581 41.85 35.645 ;
     RECT  69.516 31.805 70.197 36.091 ;
     RECT  70.956 31.805 70.974 36.091 ;
     RECT  77.94 35.339 78.297 36.091 ;
     RECT  90.9 31.661 91.797 36.091 ;
     RECT  77.94 36.091 78.678 36.413 ;
     RECT  90.648 36.091 91.797 36.413 ;
     RECT  73.944 34.969 75.597 36.553 ;
     RECT  76.5 34.079 76.806 36.553 ;
     RECT  73.944 36.553 76.806 37.147 ;
     RECT  77.94 36.413 78.297 37.147 ;
     RECT  90.9 36.413 91.797 37.339 ;
     RECT  90.648 37.339 91.797 37.469 ;
     RECT  67.215 31.109 67.914 37.597 ;
     RECT  68.652 31.109 68.706 37.597 ;
     RECT  73.944 37.147 78.297 37.613 ;
     RECT  51.015 30.667 59.397 38.101 ;
     RECT  60.12 29.803 64.797 38.101 ;
     RECT  79.488 34.493 80.997 38.101 ;
     RECT  90.9 37.469 91.797 38.101 ;
     RECT  92.556 35.203 104.058 38.101 ;
     RECT  51.015 38.101 64.797 38.141 ;
     RECT  69.516 36.091 70.974 38.141 ;
     RECT  79.488 38.101 81.09 38.141 ;
     RECT  90.9 38.101 104.058 38.141 ;
     RECT  92.556 38.141 104.058 38.543 ;
     RECT  41.94 38.443 41.958 39.019 ;
     RECT  92.556 38.543 103.122 39.083 ;
     RECT  65.952 22.045 65.97 39.523 ;
     RECT  42.915 32.269 48.597 39.595 ;
     RECT  49.86 28.411 49.878 39.595 ;
     RECT  69.516 38.141 70.197 39.883 ;
     RECT  70.956 38.141 70.974 39.883 ;
     RECT  82.368 31.757 82.386 39.883 ;
     RECT  90.9 38.141 91.797 39.883 ;
     RECT  103.86 38.543 104.058 40.019 ;
     RECT  42.915 39.595 49.878 40.199 ;
     RECT  60.12 38.141 64.797 40.261 ;
     RECT  79.488 38.141 80.997 40.261 ;
     RECT  65.952 39.523 66.402 40.267 ;
     RECT  67.215 37.597 68.706 40.267 ;
     RECT  60.12 40.261 64.89 40.301 ;
     RECT  79.488 40.261 81.09 40.301 ;
     RECT  73.944 37.613 76.806 40.363 ;
     RECT  73.944 40.363 77.058 40.433 ;
     RECT  65.952 40.267 68.706 40.445 ;
     RECT  69.516 39.883 70.974 40.445 ;
     RECT  73.944 40.433 76.986 40.445 ;
     RECT  82.368 39.883 82.674 40.445 ;
     RECT  90.648 39.883 91.797 40.445 ;
     RECT  51.015 38.141 59.397 40.711 ;
     RECT  42.915 40.199 49.77 40.945 ;
     RECT  50.76 40.711 59.397 40.945 ;
     RECT  41.94 39.019 42.066 41.371 ;
     RECT  42.915 40.945 59.397 41.371 ;
     RECT  41.94 41.371 59.397 41.501 ;
     RECT  37.515 2.413 37.797 41.647 ;
     RECT  38.772 41.083 38.79 41.647 ;
     RECT  37.515 41.647 38.79 41.741 ;
     RECT  92.556 39.083 103.086 41.995 ;
     RECT  103.896 40.019 104.058 41.995 ;
     RECT  42.915 41.501 59.397 42.179 ;
     RECT  50.472 42.179 59.397 42.961 ;
     RECT  50.148 42.961 59.397 43.037 ;
     RECT  37.515 41.741 38.178 43.099 ;
     RECT  50.292 43.037 59.397 43.181 ;
     RECT  37.515 43.099 38.79 43.277 ;
     RECT  72.615 2.413 72.897 43.627 ;
     RECT  42.915 42.179 49.158 43.771 ;
     RECT  42.915 43.771 49.554 43.843 ;
     RECT  40.215 2.413 40.497 44.077 ;
     RECT  39.888 44.077 40.497 44.383 ;
     RECT  92.556 41.995 104.058 45.185 ;
     RECT  42.915 43.843 49.734 45.769 ;
     RECT  50.544 43.181 59.397 45.769 ;
     RECT  72.36 43.627 72.897 45.833 ;
     RECT  103.932 45.185 104.058 45.914 ;
     RECT  42.915 45.769 59.397 45.959 ;
     RECT  41.94 41.501 42.066 46.003 ;
     RECT  82.368 40.445 82.386 46.003 ;
     RECT  67.215 40.445 68.706 46.543 ;
     RECT  69.516 40.445 70.197 46.543 ;
     RECT  42.915 45.959 49.734 46.777 ;
     RECT  39.456 44.383 40.497 46.885 ;
     RECT  41.868 46.003 42.066 46.921 ;
     RECT  41.436 46.921 42.066 46.973 ;
     RECT  37.515 43.277 38.178 47.191 ;
     RECT  50.544 45.959 59.397 47.281 ;
     RECT  42.804 46.777 49.734 47.623 ;
     RECT  50.472 47.281 59.397 47.623 ;
     RECT  41.652 46.973 42.066 47.731 ;
     RECT  42.804 47.623 59.397 47.731 ;
     RECT  92.556 45.185 103.194 47.885 ;
     RECT  41.652 47.731 59.397 48.127 ;
     RECT  88.815 31.289 89.097 48.163 ;
     RECT  81.756 46.003 82.386 48.299 ;
     RECT  37.476 47.191 38.178 48.703 ;
     RECT  39.348 46.885 40.497 48.703 ;
     RECT  37.476 48.703 40.497 48.941 ;
     RECT  65.952 40.445 66.402 48.973 ;
     RECT  67.215 46.543 70.197 48.973 ;
     RECT  92.556 47.885 102.87 49.003 ;
     RECT  65.952 48.973 70.197 49.195 ;
     RECT  70.956 40.445 70.974 49.195 ;
     RECT  77.94 37.613 78.297 49.243 ;
     RECT  90.9 40.445 91.797 49.243 ;
     RECT  65.952 49.195 70.974 49.373 ;
     RECT  77.94 49.243 78.678 49.373 ;
     RECT  90.648 49.243 91.797 49.373 ;
     RECT  37.476 48.941 38.214 49.477 ;
     RECT  37.44 49.477 38.214 49.577 ;
     RECT  92.556 49.003 103.194 49.579 ;
     RECT  92.556 49.579 103.23 49.867 ;
     RECT  39.348 48.941 40.497 50.251 ;
     RECT  41.22 48.127 59.397 50.251 ;
     RECT  39.348 50.251 59.397 50.431 ;
     RECT  39.276 50.431 59.397 50.693 ;
     RECT  92.556 49.867 103.266 50.746 ;
     RECT  104.004 45.914 104.058 50.746 ;
     RECT  92.556 50.746 104.058 50.774 ;
     RECT  73.944 40.445 76.806 50.791 ;
     RECT  50.292 50.693 59.397 50.923 ;
     RECT  60.12 40.301 64.797 50.923 ;
     RECT  39.276 50.693 49.554 51.061 ;
     RECT  37.44 49.577 38.178 51.097 ;
     RECT  39.24 51.061 49.554 51.161 ;
     RECT  39.24 51.161 48.597 51.169 ;
     RECT  50.292 50.923 64.797 51.359 ;
     RECT  37.44 51.097 38.394 51.367 ;
     RECT  39.204 51.169 48.597 51.367 ;
     RECT  50.508 51.359 64.797 51.467 ;
     RECT  92.556 50.774 104.022 51.503 ;
     RECT  50.508 51.467 52.182 51.629 ;
     RECT  65.952 49.373 70.197 52.141 ;
     RECT  37.44 51.367 48.597 52.285 ;
     RECT  49.536 51.161 49.554 52.285 ;
     RECT  50.544 51.629 52.182 52.313 ;
     RECT  103.932 51.503 104.022 52.315 ;
     RECT  103.932 52.315 104.058 52.394 ;
     RECT  37.44 52.285 49.554 52.439 ;
     RECT  53.028 51.467 64.797 52.825 ;
     RECT  65.556 52.141 70.197 52.825 ;
     RECT  92.556 51.503 103.194 52.979 ;
     RECT  103.932 52.394 104.022 53.371 ;
     RECT  37.44 52.439 48.597 53.401 ;
     RECT  49.536 52.439 49.554 53.401 ;
     RECT  37.44 53.401 49.554 53.519 ;
     RECT  103.932 53.371 104.058 53.519 ;
     RECT  37.44 53.519 46.026 53.789 ;
     RECT  46.764 53.519 48.69 53.789 ;
     RECT  92.556 52.979 102.87 53.869 ;
     RECT  26.715 2.413 26.997 53.899 ;
     RECT  5.115 2.413 5.397 54.031 ;
     RECT  13.215 2.413 13.497 54.031 ;
     RECT  21.315 2.413 21.597 54.031 ;
     RECT  26.676 53.899 26.997 54.059 ;
     RECT  5.004 54.031 5.397 54.077 ;
     RECT  6.84 53.899 6.858 54.077 ;
     RECT  13.104 54.031 13.497 54.077 ;
     RECT  14.832 53.899 14.85 54.077 ;
     RECT  21.204 54.031 21.597 54.077 ;
     RECT  2.415 2.413 2.697 54.091 ;
     RECT  2.415 54.091 2.898 54.131 ;
     RECT  2.415 54.131 2.697 54.283 ;
     RECT  2.304 54.283 2.697 54.329 ;
     RECT  53.028 52.825 70.197 54.413 ;
     RECT  92.556 53.869 103.23 54.671 ;
     RECT  37.44 53.789 45.99 54.715 ;
     RECT  46.764 53.789 48.597 54.715 ;
     RECT  37.44 54.715 48.597 54.869 ;
     RECT  56.415 54.413 70.197 54.941 ;
     RECT  88.815 48.163 89.19 55.049 ;
     RECT  33.444 32.737 34.038 55.409 ;
     RECT  92.556 54.671 103.194 55.409 ;
     RECT  46.764 54.869 48.597 55.831 ;
     RECT  92.556 55.409 102.87 56.191 ;
     RECT  92.556 56.191 103.194 56.237 ;
     RECT  58.392 54.941 70.197 56.731 ;
     RECT  70.956 49.373 70.974 56.731 ;
     RECT  77.94 49.373 78.297 56.731 ;
     RECT  46.62 55.831 48.597 56.861 ;
     RECT  58.392 56.731 70.974 56.861 ;
     RECT  77.94 56.731 78.678 56.861 ;
     RECT  92.556 56.237 102.87 57.163 ;
     RECT  46.98 56.861 48.597 57.341 ;
     RECT  92.556 57.163 103.194 57.407 ;
     RECT  104.004 53.519 104.058 57.569 ;
     RECT  72.615 45.833 72.897 57.883 ;
     RECT  92.556 57.407 102.87 58.261 ;
     RECT  34.815 34.627 36.162 58.423 ;
     RECT  92.556 58.261 103.194 58.507 ;
     RECT  37.44 54.869 45.897 58.531 ;
     RECT  47.016 57.341 48.597 58.531 ;
     RECT  92.556 58.507 103.23 58.531 ;
     RECT  92.556 58.531 103.266 58.637 ;
     RECT  73.944 50.791 76.878 58.685 ;
     RECT  92.556 58.637 103.23 59.503 ;
     RECT  37.44 58.531 48.726 59.575 ;
     RECT  49.536 53.519 49.554 59.575 ;
     RECT  50.544 52.313 51.858 59.701 ;
     RECT  53.028 54.413 55.638 59.701 ;
     RECT  37.44 59.575 49.554 59.773 ;
     RECT  92.556 59.503 103.302 59.789 ;
     RECT  37.44 59.773 49.734 60.079 ;
     RECT  37.44 60.079 49.806 60.115 ;
     RECT  50.544 59.701 55.638 60.115 ;
     RECT  92.556 59.789 102.87 60.511 ;
     RECT  37.44 60.115 55.638 60.655 ;
     RECT  56.415 54.941 57.474 60.655 ;
     RECT  37.44 60.655 57.474 60.953 ;
     RECT  34.02 55.409 34.038 61.087 ;
     RECT  34.815 58.423 36.594 61.087 ;
     RECT  92.556 60.511 103.194 61.291 ;
     RECT  92.556 61.291 103.23 61.457 ;
     RECT  92.556 61.457 103.194 62.303 ;
     RECT  34.02 61.087 36.594 62.429 ;
     RECT  56.415 60.953 57.474 63.751 ;
     RECT  92.556 62.303 102.87 63.787 ;
     RECT  37.44 60.953 55.638 63.931 ;
     RECT  56.376 63.751 57.474 63.931 ;
     RECT  58.392 56.861 70.197 63.931 ;
     RECT  85.752 35.005 87.102 64.165 ;
     RECT  88.056 57.001 88.074 64.165 ;
     RECT  37.44 63.931 70.197 64.319 ;
     RECT  85.752 64.165 88.074 64.319 ;
     RECT  90.9 49.373 91.797 64.939 ;
     RECT  92.556 63.787 103.194 64.939 ;
     RECT  90.9 64.939 103.194 65.273 ;
     RECT  37.44 64.319 57.474 65.399 ;
     RECT  92.556 65.273 103.194 65.399 ;
     RECT  104.04 57.569 104.058 65.866 ;
     RECT  92.556 65.399 102.87 66.187 ;
     RECT  56.415 65.399 57.474 66.28 ;
     RECT  58.392 64.319 70.197 66.28 ;
     RECT  92.556 66.187 103.194 66.283 ;
     RECT  103.932 65.866 104.058 66.283 ;
     RECT  56.415 66.28 70.197 66.317 ;
     RECT  92.556 66.283 104.058 67.037 ;
     RECT  92.556 67.037 103.95 67.163 ;
     RECT  90.9 65.273 91.797 67.405 ;
     RECT  56.415 66.317 57.474 67.909 ;
     RECT  58.392 66.317 70.197 67.909 ;
     RECT  73.944 58.685 76.806 68.639 ;
     RECT  92.556 67.163 103.194 69.755 ;
     RECT  103.932 67.163 103.95 69.989 ;
     RECT  92.556 69.755 102.87 70.603 ;
     RECT  56.415 67.909 70.197 71.617 ;
     RECT  70.956 56.861 70.974 71.617 ;
     RECT  92.556 70.603 103.194 71.755 ;
     RECT  92.556 71.755 103.23 72.149 ;
     RECT  56.415 71.617 70.974 72.329 ;
     RECT  92.556 72.149 103.194 72.869 ;
     RECT  56.415 72.329 70.197 73.237 ;
     RECT  70.956 72.329 70.974 73.237 ;
     RECT  104.04 73.336 104.058 73.345 ;
     RECT  56.415 73.237 70.974 73.877 ;
     RECT  103.968 73.345 104.058 73.997 ;
     RECT  104.04 73.997 104.058 74.045 ;
     RECT  56.415 73.877 70.197 74.111 ;
     RECT  56.415 74.111 68.202 74.281 ;
     RECT  37.44 65.399 55.638 74.353 ;
     RECT  56.412 74.281 68.202 74.353 ;
     RECT  104.04 74.971 104.058 75.001 ;
     RECT  103.968 75.001 104.058 75.029 ;
     RECT  103.968 75.029 103.986 75.053 ;
     RECT  92.556 72.869 102.87 75.115 ;
     RECT  72.324 57.883 72.897 75.199 ;
     RECT  37.44 74.353 68.202 75.659 ;
     RECT  92.556 75.115 103.194 76.199 ;
     RECT  88.815 55.049 89.097 76.267 ;
     RECT  92.556 76.199 102.87 76.739 ;
     RECT  34.02 62.429 36.162 76.783 ;
     RECT  37.44 75.659 55.638 76.783 ;
     RECT  88.815 76.267 89.478 77.081 ;
     RECT  79.488 40.301 80.997 77.161 ;
     RECT  70.956 73.877 70.974 77.279 ;
     RECT  34.02 76.783 55.638 77.431 ;
     RECT  56.376 75.659 68.202 77.431 ;
     RECT  79.164 77.161 80.997 77.431 ;
     RECT  103.176 77.515 103.194 77.611 ;
     RECT  103.176 77.611 103.23 77.707 ;
     RECT  103.176 77.707 103.266 77.803 ;
     RECT  103.14 77.803 103.266 78.029 ;
     RECT  68.976 74.111 70.197 78.091 ;
     RECT  77.94 56.861 78.297 78.241 ;
     RECT  79.092 77.431 80.997 78.241 ;
     RECT  77.94 78.241 80.997 78.359 ;
     RECT  68.94 78.091 70.197 78.403 ;
     RECT  103.176 78.029 103.266 78.467 ;
     RECT  34.02 77.431 68.202 78.475 ;
     RECT  68.94 78.403 70.722 78.475 ;
     RECT  34.02 78.475 70.722 78.539 ;
     RECT  34.02 78.539 70.197 78.701 ;
     RECT  92.556 76.739 102.366 78.859 ;
     RECT  103.176 78.467 103.194 78.859 ;
     RECT  20.196 78.871 20.214 78.941 ;
     RECT  18.615 2.413 18.897 79.003 ;
     RECT  15.084 54.301 15.102 79.079 ;
     RECT  34.02 78.701 68.202 79.079 ;
     RECT  18.615 79.003 19.566 79.169 ;
     RECT  18.615 79.169 19.242 79.241 ;
     RECT  68.94 78.701 70.197 79.619 ;
     RECT  85.752 64.319 87.246 79.753 ;
     RECT  88.056 64.319 88.074 79.753 ;
     RECT  92.556 78.859 103.194 79.753 ;
     RECT  92.556 79.753 103.23 79.853 ;
     RECT  92.556 79.853 103.194 80.249 ;
     RECT  71.46 80.131 71.478 80.285 ;
     RECT  92.556 80.249 102.582 80.519 ;
     RECT  37.152 79.079 68.202 80.635 ;
     RECT  68.976 79.619 70.197 80.635 ;
     RECT  72.216 75.199 72.897 80.905 ;
     RECT  71.496 80.905 72.897 80.933 ;
     RECT  92.556 80.519 102.366 81.329 ;
     RECT  37.152 80.635 70.197 81.869 ;
     RECT  34.02 79.079 36.162 82.679 ;
     RECT  33.156 80.293 33.174 82.831 ;
     RECT  82.368 48.299 82.386 82.831 ;
     RECT  82.368 82.831 82.602 82.949 ;
     RECT  82.368 82.949 82.494 82.985 ;
     RECT  68.976 81.869 70.197 83.323 ;
     RECT  71.496 80.933 71.514 83.497 ;
     RECT  72.615 80.933 72.897 83.497 ;
     RECT  68.976 83.323 70.722 83.597 ;
     RECT  71.496 83.497 72.897 84.073 ;
     RECT  34.56 82.679 36.162 85.657 ;
     RECT  85.752 79.753 88.074 85.765 ;
     RECT  79.092 78.359 80.997 85.919 ;
     RECT  37.152 81.869 68.202 86.341 ;
     RECT  68.976 83.597 70.197 86.341 ;
     RECT  92.556 81.329 102.294 86.369 ;
     RECT  79.992 85.919 80.997 86.881 ;
     RECT  37.152 86.341 70.197 87.269 ;
     RECT  73.944 68.639 75.597 87.889 ;
     RECT  76.5 68.639 76.806 87.889 ;
     RECT  77.94 78.359 78.297 88.349 ;
     RECT  37.152 87.269 68.202 88.627 ;
     RECT  90.36 67.405 91.797 89.203 ;
     RECT  79.092 85.919 79.11 90.317 ;
     RECT  85.176 85.765 88.074 90.347 ;
     RECT  95.868 86.369 102.294 90.509 ;
     RECT  26.715 54.059 26.997 91.243 ;
     RECT  27.9 91.201 27.918 91.243 ;
     RECT  29.415 2.413 29.697 91.291 ;
     RECT  26.715 91.243 27.918 91.319 ;
     RECT  27.756 91.319 27.918 91.325 ;
     RECT  28.836 91.291 29.697 91.328 ;
     RECT  30.78 91.195 30.798 91.373 ;
     RECT  70.956 84.073 72.897 91.463 ;
     RECT  95.868 90.509 101.574 91.469 ;
     RECT  79.848 86.881 80.997 91.561 ;
     RECT  79.848 91.561 81.63 91.723 ;
     RECT  82.368 82.985 82.386 91.723 ;
     RECT  34.524 85.657 36.162 91.859 ;
     RECT  79.848 91.723 82.386 91.859 ;
     RECT  78.015 88.349 78.297 91.867 ;
     RECT  82.368 91.859 82.386 91.903 ;
     RECT  87.48 90.347 88.074 91.931 ;
     RECT  26.715 91.319 26.997 92.059 ;
     RECT  27.756 91.325 27.774 92.059 ;
     RECT  26.715 92.059 27.774 92.129 ;
     RECT  82.368 91.903 82.674 92.129 ;
     RECT  79.848 91.859 81.522 92.189 ;
     RECT  96.012 91.469 101.574 92.201 ;
     RECT  78.015 91.867 78.75 92.245 ;
     RECT  85.176 90.347 86.397 92.399 ;
     RECT  29.415 91.328 29.697 92.551 ;
     RECT  36.936 88.627 68.202 92.551 ;
     RECT  28.8 92.551 29.697 92.621 ;
     RECT  26.715 92.129 27.27 92.669 ;
     RECT  28.584 92.677 28.602 92.717 ;
     RECT  83.415 31.019 83.697 93.181 ;
     RECT  90.324 89.203 91.797 93.209 ;
     RECT  73.944 87.889 76.806 93.865 ;
     RECT  73.692 93.865 76.806 94.289 ;
     RECT  90.324 93.209 90.558 94.361 ;
     RECT  82.368 92.129 82.386 94.639 ;
     RECT  82.368 94.639 82.458 94.667 ;
     RECT  98.316 92.201 101.574 94.901 ;
     RECT  88.056 91.931 88.074 94.973 ;
     RECT  82.44 94.667 82.458 95.449 ;
     RECT  83.415 93.181 84.042 95.449 ;
     RECT  92.556 86.369 94.914 95.477 ;
     RECT  34.524 91.859 36.054 95.485 ;
     RECT  36.828 92.551 68.202 95.485 ;
     RECT  34.524 95.485 68.202 95.639 ;
     RECT  74.376 94.289 76.806 96.029 ;
     RECT  71.496 91.463 72.897 96.139 ;
     RECT  71.496 96.139 72.99 96.151 ;
     RECT  71.496 96.151 73.314 96.269 ;
     RECT  68.976 87.269 70.197 96.427 ;
     RECT  82.44 95.449 84.042 96.601 ;
     RECT  98.316 94.901 100.062 96.629 ;
     RECT  74.88 96.029 76.806 96.719 ;
     RECT  34.524 95.639 36.09 96.871 ;
     RECT  36.828 95.639 68.202 96.871 ;
     RECT  71.496 96.269 73.098 97.099 ;
     RECT  68.976 96.427 70.29 97.243 ;
     RECT  68.976 97.243 70.722 97.373 ;
     RECT  71.496 97.099 73.242 97.439 ;
     RECT  71.496 97.439 72.99 97.529 ;
     RECT  33.156 82.831 33.534 97.951 ;
     RECT  34.524 96.871 68.202 97.951 ;
     RECT  68.976 97.373 70.197 98.107 ;
     RECT  68.976 98.107 70.722 98.237 ;
     RECT  92.556 95.477 94.497 98.339 ;
     RECT  68.976 98.237 70.197 98.717 ;
     RECT  79.848 92.189 80.997 98.887 ;
     RECT  101.124 94.901 101.574 98.915 ;
     RECT  73.728 99.229 73.746 99.419 ;
     RECT  32.115 2.413 32.397 99.535 ;
     RECT  33.156 97.951 68.202 99.535 ;
     RECT  69.192 98.717 70.197 99.535 ;
     RECT  71.496 97.529 72.897 99.535 ;
     RECT  74.88 96.719 76.338 99.563 ;
     RECT  101.124 98.915 101.25 99.563 ;
     RECT  82.152 96.601 84.042 99.571 ;
     RECT  85.176 92.399 85.194 99.599 ;
     RECT  32.115 99.535 68.202 99.661 ;
     RECT  69.192 99.535 72.897 99.689 ;
     RECT  81.72 99.571 84.042 99.689 ;
     RECT  76.932 99.697 76.95 99.773 ;
     RECT  69.192 99.689 70.197 100.027 ;
     RECT  74.88 99.563 76.086 100.031 ;
     RECT  78.015 92.245 78.93 100.265 ;
     RECT  88.815 77.081 89.097 100.471 ;
     RECT  98.388 96.629 100.062 100.499 ;
     RECT  74.988 100.031 76.086 100.571 ;
     RECT  88.815 100.471 89.586 100.637 ;
     RECT  69.12 100.027 70.197 100.651 ;
     RECT  96.012 92.201 97.197 100.679 ;
     RECT  69.048 100.651 70.197 100.769 ;
     RECT  79.812 98.887 80.997 100.769 ;
     RECT  82.152 99.689 83.697 100.769 ;
     RECT  74.988 100.571 75.798 100.849 ;
     RECT  74.664 100.849 75.798 100.949 ;
     RECT  92.556 98.339 93.114 101.039 ;
     RECT  69.192 100.769 70.197 101.083 ;
     RECT  86.04 92.399 86.397 101.083 ;
     RECT  90.324 94.361 90.342 101.083 ;
     RECT  94.215 98.339 94.497 101.083 ;
     RECT  74.664 100.949 75.597 101.183 ;
     RECT  31.716 99.661 68.202 101.191 ;
     RECT  78.015 100.265 78.678 101.213 ;
     RECT  86.04 101.083 86.49 101.213 ;
     RECT  90.324 101.083 90.666 101.213 ;
     RECT  94.215 101.083 94.662 101.213 ;
     RECT  88.815 100.637 89.097 101.281 ;
     RECT  69.192 101.083 70.722 101.309 ;
     RECT  90.324 101.213 90.342 101.309 ;
     RECT  30.924 101.191 68.202 101.579 ;
     RECT  80.715 100.769 80.997 101.659 ;
     RECT  69.228 101.309 70.722 101.695 ;
     RECT  71.496 99.689 72.897 101.695 ;
     RECT  101.232 99.563 101.25 101.723 ;
     RECT  82.836 100.769 83.697 101.731 ;
     RECT  86.04 101.213 86.397 101.741 ;
     RECT  98.784 100.499 100.062 101.759 ;
     RECT  69.228 101.695 72.897 101.849 ;
     RECT  80.715 101.659 81.054 101.849 ;
     RECT  82.728 101.731 83.697 101.849 ;
     RECT  75.204 101.183 75.597 101.933 ;
     RECT  94.215 101.213 94.497 101.947 ;
     RECT  69.228 101.849 70.722 102.029 ;
     RECT  88.344 101.281 89.097 102.029 ;
     RECT  69.228 102.029 70.197 102.299 ;
     RECT  78.015 101.213 78.297 102.361 ;
     RECT  30.924 101.579 68.166 102.389 ;
     RECT  79.812 100.769 79.83 102.389 ;
     RECT  82.764 101.849 83.697 102.569 ;
     RECT  93.096 101.039 93.114 102.631 ;
     RECT  93.024 102.631 93.114 102.659 ;
     RECT  78.015 102.361 78.678 102.731 ;
     RECT  86.115 101.741 86.397 102.811 ;
     RECT  98.784 101.759 100.026 102.839 ;
     RECT  85.752 102.811 86.397 102.929 ;
     RECT  94.032 101.947 94.497 102.929 ;
     RECT  96.588 100.679 97.197 102.929 ;
     RECT  69.915 102.299 70.197 102.973 ;
     RECT  71.496 101.849 72.897 103.001 ;
     RECT  69.915 102.973 70.614 103.073 ;
     RECT  2.415 54.329 2.697 103.157 ;
     RECT  5.115 54.077 5.397 103.157 ;
     RECT  7.815 2.413 8.097 103.157 ;
     RECT  10.515 2.413 10.797 103.157 ;
     RECT  13.215 54.077 13.497 103.157 ;
     RECT  15.915 2.413 16.197 103.157 ;
     RECT  18.615 79.241 18.897 103.157 ;
     RECT  21.315 54.077 21.597 103.157 ;
     RECT  24.015 2.413 24.297 103.157 ;
     RECT  26.715 92.669 26.997 103.157 ;
     RECT  29.415 92.621 29.697 103.157 ;
     RECT  69.915 103.073 70.197 103.157 ;
     RECT  72.615 103.001 72.897 103.157 ;
     RECT  75.315 101.933 75.597 103.157 ;
     RECT  78.015 102.731 78.297 103.157 ;
     RECT  80.715 101.849 80.997 103.157 ;
     RECT  83.415 102.569 83.697 103.157 ;
     RECT  86.115 102.929 86.397 103.157 ;
     RECT  88.815 102.029 89.097 103.157 ;
     RECT  91.515 93.209 91.797 103.157 ;
     RECT  94.215 102.929 94.497 103.157 ;
     RECT  96.915 102.929 97.197 103.157 ;
     RECT  98.784 102.839 99.897 103.199 ;
     RECT  30.924 102.389 67.662 103.235 ;
     RECT  93.024 102.659 93.042 103.271 ;
     RECT  98.784 103.199 98.802 103.277 ;
     RECT  31.5 103.235 67.662 103.343 ;
     RECT  31.5 103.343 67.554 103.379 ;
     RECT  2.607 103.157 2.697 103.427 ;
     RECT  5.307 103.157 5.397 103.427 ;
     RECT  8.007 103.157 8.097 103.427 ;
     RECT  10.707 103.157 10.797 103.427 ;
     RECT  13.407 103.157 13.497 103.427 ;
     RECT  16.107 103.157 16.197 103.427 ;
     RECT  18.807 103.157 18.897 103.427 ;
     RECT  21.507 103.157 21.597 103.427 ;
     RECT  24.207 103.157 24.297 103.427 ;
     RECT  26.907 103.157 26.997 103.427 ;
     RECT  29.607 103.157 29.697 103.427 ;
     RECT  70.107 103.157 70.197 103.427 ;
     RECT  72.807 103.157 72.897 103.427 ;
     RECT  75.507 103.157 75.597 103.427 ;
     RECT  78.207 103.157 78.297 103.427 ;
     RECT  80.907 103.157 80.997 103.427 ;
     RECT  83.607 103.157 83.697 103.427 ;
     RECT  86.307 103.157 86.397 103.427 ;
     RECT  89.007 103.157 89.097 103.427 ;
     RECT  91.707 103.157 91.797 103.427 ;
     RECT  94.407 103.157 94.497 103.427 ;
     RECT  97.107 103.157 97.197 103.427 ;
     RECT  99.807 103.199 99.897 103.427 ;
     RECT  31.968 103.379 67.554 103.469 ;
     RECT  84.6 103.351 84.618 103.541 ;
     RECT  71.496 103.001 71.514 103.577 ;
     RECT  31.968 103.469 67.338 103.613 ;
     RECT  62.352 103.613 67.338 103.649 ;
     RECT  62.352 103.649 63.954 103.661 ;
     RECT  62.46 103.661 63.954 103.694 ;
     RECT  64.908 103.649 67.338 103.805 ;
     RECT  62.46 103.694 63.198 103.997 ;
     RECT  63.936 103.694 63.954 104.093 ;
     RECT  31.968 103.613 61.47 104.657 ;
     RECT  65.448 103.805 67.338 104.717 ;
     RECT  31.968 104.657 60.534 104.813 ;
     RECT  65.664 104.717 67.338 105.389 ;
     RECT  64.152 105.307 64.17 105.437 ;
     RECT  62.46 103.997 62.478 105.547 ;
     RECT  65.88 105.389 67.338 105.581 ;
     RECT  31.968 104.813 60.426 105.584 ;
     RECT  31.968 105.584 60.354 105.629 ;
     RECT  66.924 105.581 67.338 105.629 ;
     RECT  61.452 104.657 61.47 105.677 ;
     RECT  66.924 105.629 67.122 105.677 ;
     RECT  31.968 105.629 60.318 105.701 ;
     RECT  32.004 105.701 60.318 105.725 ;
     RECT  62.46 105.547 62.586 105.725 ;
     RECT  66.924 105.677 66.942 105.725 ;
     RECT  32.076 105.725 60.318 105.773 ;
     RECT  65.88 105.581 65.898 105.773 ;
     RECT  32.148 105.773 60.318 105.804 ;
    LAYER M4 ;
     RECT  0.06 54.096 2.408 54.312 ;
     RECT  0.181 90.816 2.408 90.84 ;
     RECT  2.408 2.148 2.512 103.152 ;
     RECT  2.512 2.418 2.6 103.152 ;
     RECT  2.6 2.418 2.704 103.422 ;
     RECT  2.704 54.048 2.909 54.12 ;
     RECT  2.909 54.048 5.108 54.072 ;
     RECT  2.704 90.816 5.108 90.84 ;
     RECT  5.108 2.148 5.212 103.152 ;
     RECT  5.212 2.418 5.3 103.152 ;
     RECT  5.3 2.418 5.404 103.422 ;
     RECT  5.404 54.048 6.829 54.072 ;
     RECT  6.829 53.904 7.808 54.072 ;
     RECT  5.404 90.816 7.808 90.84 ;
     RECT  7.808 2.148 7.912 103.152 ;
     RECT  7.912 2.418 8 103.152 ;
     RECT  8 2.418 8.104 103.422 ;
     RECT  8.104 53.904 10.508 53.928 ;
     RECT  8.104 90.816 10.508 90.84 ;
     RECT  10.508 2.148 10.612 103.152 ;
     RECT  10.612 2.418 10.7 103.152 ;
     RECT  10.7 2.418 10.804 103.422 ;
     RECT  10.804 54.048 13.208 54.072 ;
     RECT  10.804 90.816 13.208 90.84 ;
     RECT  13.208 2.148 13.312 103.152 ;
     RECT  13.312 2.418 13.4 103.152 ;
     RECT  13.4 2.418 13.504 103.422 ;
     RECT  13.504 54.048 14.821 54.072 ;
     RECT  14.821 53.904 14.861 54.072 ;
     RECT  14.861 53.904 15.908 53.928 ;
     RECT  13.504 90.816 15.908 90.84 ;
     RECT  15.908 2.148 16.012 103.152 ;
     RECT  16.012 2.418 16.1 103.152 ;
     RECT  16.1 2.418 16.204 103.422 ;
     RECT  16.204 53.904 18.608 53.928 ;
     RECT  16.204 90.816 18.608 90.84 ;
     RECT  18.608 2.148 18.712 103.152 ;
     RECT  18.712 2.418 18.8 103.152 ;
     RECT  18.8 2.418 18.904 103.422 ;
     RECT  18.904 79.008 20.185 79.224 ;
     RECT  18.904 54.048 21.308 54.072 ;
     RECT  20.185 78.912 21.308 79.224 ;
     RECT  18.904 90.816 21.308 90.84 ;
     RECT  21.308 2.148 21.412 103.152 ;
     RECT  21.412 2.418 21.5 103.152 ;
     RECT  21.5 2.418 21.604 103.422 ;
     RECT  21.604 54.048 23.893 54.072 ;
     RECT  23.893 53.904 24.008 54.072 ;
     RECT  21.604 78.912 24.008 79.224 ;
     RECT  21.604 90.816 24.008 90.84 ;
     RECT  24.008 2.148 24.112 103.152 ;
     RECT  24.112 2.418 24.2 103.152 ;
     RECT  24.2 2.418 24.304 103.422 ;
     RECT  24.304 53.904 26.708 53.928 ;
     RECT  24.304 78.912 26.708 79.224 ;
     RECT  24.304 90.816 26.708 90.84 ;
     RECT  26.708 2.148 26.812 103.152 ;
     RECT  26.812 2.418 26.9 103.152 ;
     RECT  26.9 2.418 27.004 103.422 ;
     RECT  27.004 78.912 27.347 79.224 ;
     RECT  27.004 54.048 29.408 54.072 ;
     RECT  27.347 79.2 29.408 79.224 ;
     RECT  27.004 90.816 29.408 92.712 ;
     RECT  28.789 99.696 29.408 99.72 ;
     RECT  29.408 2.148 29.512 103.152 ;
     RECT  29.512 2.418 29.6 103.152 ;
     RECT  29.6 2.418 29.704 103.422 ;
     RECT  30.913 101.424 31.957 101.448 ;
     RECT  31.921 103.2 31.957 103.224 ;
     RECT  29.704 79.2 32.108 79.224 ;
     RECT  29.704 90.816 32.108 92.712 ;
     RECT  29.704 99.696 32.108 99.72 ;
     RECT  31.957 101.424 32.108 101.88 ;
     RECT  31.957 102.96 32.108 103.224 ;
     RECT  32.108 2.148 32.212 103.224 ;
     RECT  32.212 2.418 32.3 103.224 ;
     RECT  32.3 2.418 32.404 103.422 ;
     RECT  31.993 105.696 32.465 105.72 ;
     RECT  32.404 90.816 33.395 92.712 ;
     RECT  32.404 98.304 33.437 98.328 ;
     RECT  33.395 92.688 33.443 92.712 ;
     RECT  32.404 99.696 34.297 103.224 ;
     RECT  34.261 105.744 34.409 105.768 ;
     RECT  34.357 98.16 34.652 98.184 ;
     RECT  34.297 99.36 34.652 103.224 ;
     RECT  33.493 41.184 34.808 41.208 ;
     RECT  34.309 66.288 34.808 66.312 ;
     RECT  32.404 79.2 34.808 79.224 ;
     RECT  33.395 90.816 34.808 91.464 ;
     RECT  33.877 96.768 34.808 96.792 ;
     RECT  34.652 98.16 34.808 103.224 ;
     RECT  34.808 2.148 34.912 103.224 ;
     RECT  34.912 2.418 35 103.224 ;
     RECT  35 2.418 35.104 103.422 ;
     RECT  35.104 99.744 35.363 102.744 ;
     RECT  35.104 98.64 36.133 98.76 ;
     RECT  35.363 99.744 36.133 100.92 ;
     RECT  35.557 105.696 36.241 105.72 ;
     RECT  35.104 96.768 36.421 97.464 ;
     RECT  36.133 98.64 36.421 100.92 ;
     RECT  35.363 102.048 36.493 102.744 ;
     RECT  36.229 103.728 36.493 103.752 ;
     RECT  36.241 105.696 36.745 105.768 ;
     RECT  36.421 96.768 36.781 100.92 ;
     RECT  36.493 102.048 36.781 103.752 ;
     RECT  35.104 90.816 36.805 91.464 ;
     RECT  35.104 66.288 36.853 66.312 ;
     RECT  36.745 104.832 36.947 105.768 ;
     RECT  35.104 41.184 37.141 41.208 ;
     RECT  37.189 60.672 37.237 60.696 ;
     RECT  36.229 44.4 37.285 44.424 ;
     RECT  37.141 41.136 37.508 41.208 ;
     RECT  37.285 43.536 37.508 44.424 ;
     RECT  37.237 60.096 37.508 60.696 ;
     RECT  35.104 61.968 37.508 61.992 ;
     RECT  36.853 65.952 37.508 66.312 ;
     RECT  37.333 79.2 37.508 79.224 ;
     RECT  36.709 82.944 37.508 82.968 ;
     RECT  35.104 85.2 37.508 85.224 ;
     RECT  35.104 86.304 37.508 86.328 ;
     RECT  35.104 89.184 37.508 89.208 ;
     RECT  36.805 90.288 37.508 91.464 ;
     RECT  36.781 96.768 37.508 103.752 ;
     RECT  37.508 2.148 37.612 103.752 ;
     RECT  37.612 2.418 37.804 103.752 ;
     RECT  37.804 79.2 37.901 79.224 ;
     RECT  36.947 105.744 38.621 105.768 ;
     RECT  38.653 104.832 38.765 104.856 ;
     RECT  37.804 48.912 38.797 50.088 ;
     RECT  37.804 41.088 38.801 41.736 ;
     RECT  38.797 48.768 38.837 50.088 ;
     RECT  37.804 61.872 38.873 61.992 ;
     RECT  37.804 95.712 38.941 95.736 ;
     RECT  37.804 96.768 38.941 103.752 ;
     RECT  37.804 58.944 38.965 58.968 ;
     RECT  38.941 95.712 39.017 103.752 ;
     RECT  37.804 55.152 39.061 55.176 ;
     RECT  38.773 72.912 39.161 72.936 ;
     RECT  38.821 53.568 39.205 53.592 ;
     RECT  38.837 49.824 39.253 50.088 ;
     RECT  39.205 53.568 39.397 53.832 ;
     RECT  37.804 60.096 39.589 60.84 ;
     RECT  39.109 56.88 39.637 56.904 ;
     RECT  39.637 56.88 39.685 57.384 ;
     RECT  38.965 58.416 39.685 58.968 ;
     RECT  39.877 62.976 39.925 63 ;
     RECT  37.804 65.952 39.925 66.504 ;
     RECT  39.685 56.88 39.973 58.968 ;
     RECT  37.804 86.304 40.021 86.328 ;
     RECT  38.801 41.136 40.208 41.736 ;
     RECT  37.804 43.104 40.208 44.424 ;
     RECT  38.917 47.616 40.208 47.64 ;
     RECT  38.837 48.768 40.208 48.792 ;
     RECT  39.253 49.824 40.208 50.616 ;
     RECT  39.829 51.696 40.208 51.72 ;
     RECT  39.397 52.8 40.208 53.832 ;
     RECT  39.061 54.96 40.208 55.176 ;
     RECT  39.973 56.352 40.208 58.968 ;
     RECT  39.589 60.048 40.208 60.84 ;
     RECT  38.873 61.968 40.208 61.992 ;
     RECT  39.925 62.976 40.208 63.528 ;
     RECT  39.925 65.952 40.208 66.696 ;
     RECT  37.804 68.112 40.208 68.136 ;
     RECT  37.804 82.944 40.208 82.968 ;
     RECT  37.804 85.2 40.208 85.224 ;
     RECT  40.021 86.304 40.208 87.192 ;
     RECT  37.804 89.184 40.208 89.208 ;
     RECT  37.804 90.288 40.208 91.464 ;
     RECT  39.017 96 40.208 103.752 ;
     RECT  40.208 2.148 40.312 103.752 ;
     RECT  40.312 2.418 40.504 103.752 ;
     RECT  40.021 105.696 40.705 105.72 ;
     RECT  40.705 104.832 40.853 105.72 ;
     RECT  40.853 105.6 40.988 105.72 ;
     RECT  40.504 54.96 41.213 57.384 ;
     RECT  40.504 46.944 41.465 47.64 ;
     RECT  40.504 52.8 41.501 53.832 ;
     RECT  40.504 30.192 41.537 30.216 ;
     RECT  40.988 105.6 41.555 105.768 ;
     RECT  40.504 82.944 41.557 82.968 ;
     RECT  41.555 105.6 41.609 105.72 ;
     RECT  40.504 48.768 41.612 48.792 ;
     RECT  40.504 49.824 41.612 51.72 ;
     RECT  41.612 48.768 41.699 51.72 ;
     RECT  40.504 65.952 41.701 66.504 ;
     RECT  40.504 95.376 41.749 103.752 ;
     RECT  41.699 48.768 41.753 48.792 ;
     RECT  41.797 35.616 41.884 35.64 ;
     RECT  41.465 47.616 41.893 47.64 ;
     RECT  41.893 47.616 42.325 47.688 ;
     RECT  41.699 49.824 42.397 51.72 ;
     RECT  41.501 52.8 42.469 52.824 ;
     RECT  41.501 53.808 42.469 53.832 ;
     RECT  40.504 90.288 42.685 91.464 ;
     RECT  42.397 49.824 42.709 51.768 ;
     RECT  42.469 52.8 42.709 53.832 ;
     RECT  41.213 56.832 42.757 57.384 ;
     RECT  40.504 58.416 42.757 58.968 ;
     RECT  41.989 78.912 42.757 78.936 ;
     RECT  40.504 89.184 42.757 89.208 ;
     RECT  42.685 90.288 42.757 91.8 ;
     RECT  40.504 41.136 42.908 41.736 ;
     RECT  40.504 43.104 42.908 44.424 ;
     RECT  42.325 47.616 42.908 48.168 ;
     RECT  42.709 49.824 42.908 53.832 ;
     RECT  41.213 54.96 42.908 55.752 ;
     RECT  42.757 56.832 42.908 58.968 ;
     RECT  40.504 60.048 42.908 60.84 ;
     RECT  40.504 61.968 42.908 61.992 ;
     RECT  40.504 62.976 42.908 64.104 ;
     RECT  41.701 65.232 42.908 66.504 ;
     RECT  40.504 68.112 42.908 68.136 ;
     RECT  42.757 78.912 42.908 78.984 ;
     RECT  42.757 80.544 42.908 80.568 ;
     RECT  41.557 82.944 42.908 83.016 ;
     RECT  40.504 85.2 42.908 85.224 ;
     RECT  40.504 86.304 42.908 86.328 ;
     RECT  42.757 89.184 42.908 91.8 ;
     RECT  41.749 95.136 42.908 103.752 ;
     RECT  42.908 2.148 43.012 103.752 ;
     RECT  43.012 2.418 43.204 103.752 ;
     RECT  43.204 78.864 43.331 78.984 ;
     RECT  43.331 78.864 43.373 78.936 ;
     RECT  42.901 105.744 43.429 105.768 ;
     RECT  43.429 105.408 43.669 105.768 ;
     RECT  43.204 47.664 43.697 48.504 ;
     RECT  43.204 46.416 43.805 46.44 ;
     RECT  43.204 51.168 44.021 53.832 ;
     RECT  43.204 62.976 44.165 64.104 ;
     RECT  43.204 41.136 44.293 41.736 ;
     RECT  43.669 104.832 44.381 105.768 ;
     RECT  44.021 52.8 44.453 53.832 ;
     RECT  43.204 65.232 44.453 66.504 ;
     RECT  44.453 53.808 44.597 53.832 ;
     RECT  44.293 41.136 44.677 41.928 ;
     RECT  43.204 94.368 44.732 103.752 ;
     RECT  44.677 41.136 44.917 41.976 ;
     RECT  44.381 104.832 45.349 105.72 ;
     RECT  44.732 93.888 45.397 103.752 ;
     RECT  44.917 41.136 45.608 42.024 ;
     RECT  43.204 43.104 45.608 44.424 ;
     RECT  43.697 47.664 45.608 48.168 ;
     RECT  43.204 49.824 45.608 50.088 ;
     RECT  44.021 51.168 45.608 51.672 ;
     RECT  44.453 52.8 45.608 52.824 ;
     RECT  43.204 54.96 45.608 55.752 ;
     RECT  43.204 56.832 45.608 58.968 ;
     RECT  43.204 60.048 45.608 60.84 ;
     RECT  43.204 61.968 45.608 61.992 ;
     RECT  44.165 63.504 45.608 64.104 ;
     RECT  44.453 65.232 45.608 66.312 ;
     RECT  43.204 68.112 45.608 68.136 ;
     RECT  43.373 78.912 45.608 78.936 ;
     RECT  43.204 80.544 45.608 80.568 ;
     RECT  43.204 82.944 45.608 83.016 ;
     RECT  43.204 85.2 45.608 85.224 ;
     RECT  43.204 86.304 45.608 86.328 ;
     RECT  43.204 89.184 45.608 91.464 ;
     RECT  45.397 93.888 45.608 103.8 ;
     RECT  45.608 2.148 45.712 103.8 ;
     RECT  45.712 2.418 45.904 103.8 ;
     RECT  45.904 65.232 45.965 66.312 ;
     RECT  45.904 60.048 46.001 61.992 ;
     RECT  45.904 93.744 46.177 103.8 ;
     RECT  45.349 104.784 46.177 105.72 ;
     RECT  45.904 49.824 46.181 49.848 ;
     RECT  45.904 52.8 46.217 52.824 ;
     RECT  46.001 60.096 46.499 61.992 ;
     RECT  45.904 89.184 46.505 91.464 ;
     RECT  45.904 63.792 46.541 63.816 ;
     RECT  45.904 51.36 46.757 51.768 ;
     RECT  45.904 80.544 46.757 80.568 ;
     RECT  46.499 61.872 46.793 61.992 ;
     RECT  46.177 93.744 46.892 105.72 ;
     RECT  45.904 41.088 46.901 42.072 ;
     RECT  45.904 78.912 46.969 78.936 ;
     RECT  46.892 93.6 46.979 105.72 ;
     RECT  45.904 29.472 47.005 30.072 ;
     RECT  46.979 93.744 47.005 105.72 ;
     RECT  45.904 56.784 47.009 58.968 ;
     RECT  47.005 93.744 47.027 105.768 ;
     RECT  46.757 51.36 47.077 51.672 ;
     RECT  47.009 58.224 47.117 58.968 ;
     RECT  47.041 27.888 47.221 27.912 ;
     RECT  47.005 28.944 47.221 30.072 ;
     RECT  45.904 47.568 47.221 47.592 ;
     RECT  47.077 50.736 47.261 51.672 ;
     RECT  45.904 55.728 47.297 55.752 ;
     RECT  47.027 104.88 47.297 105.768 ;
     RECT  47.221 27.888 47.365 30.072 ;
     RECT  45.904 43.104 47.365 44.424 ;
     RECT  45.904 46.224 47.413 46.248 ;
     RECT  47.297 104.88 47.699 105.72 ;
     RECT  47.261 51.36 48.133 51.672 ;
     RECT  45.965 65.952 48.181 66.312 ;
     RECT  47.221 47.568 48.193 48.504 ;
     RECT  45.904 86.304 48.193 86.328 ;
     RECT  46.969 78.624 48.265 78.936 ;
     RECT  47.581 26.592 48.308 26.616 ;
     RECT  47.365 27.888 48.308 30.12 ;
     RECT  46.901 41.136 48.308 42.072 ;
     RECT  47.365 43.104 48.308 44.664 ;
     RECT  47.413 46.032 48.308 46.248 ;
     RECT  48.193 47.424 48.308 48.504 ;
     RECT  48.133 51.36 48.308 52.488 ;
     RECT  47.009 56.784 48.308 56.808 ;
     RECT  47.689 58.992 48.308 59.016 ;
     RECT  46.499 60.096 48.308 60.84 ;
     RECT  46.793 61.968 48.308 61.992 ;
     RECT  48.181 65.52 48.308 66.312 ;
     RECT  46.933 68.112 48.308 68.136 ;
     RECT  45.904 76.512 48.308 76.536 ;
     RECT  48.265 78.624 48.308 78.984 ;
     RECT  47.581 80.4 48.308 80.424 ;
     RECT  45.904 82.944 48.308 83.016 ;
     RECT  45.904 85.2 48.308 85.224 ;
     RECT  48.193 86.208 48.308 86.328 ;
     RECT  46.505 89.184 48.308 89.208 ;
     RECT  46.505 90.288 48.308 91.464 ;
     RECT  47.027 93.744 48.308 103.8 ;
     RECT  48.308 2.148 48.412 103.8 ;
     RECT  48.412 2.418 48.604 103.8 ;
     RECT  48.604 46.032 48.773 46.248 ;
     RECT  47.699 105.456 48.989 105.72 ;
     RECT  48.604 92.928 48.997 103.8 ;
     RECT  48.989 105.456 48.997 105.672 ;
     RECT  48.604 48.48 49.025 48.504 ;
     RECT  48.604 86.208 49.043 86.328 ;
     RECT  48.997 92.928 49.043 105.672 ;
     RECT  49.043 93.648 49.283 105.672 ;
     RECT  48.604 65.52 49.349 66.312 ;
     RECT  48.604 41.136 49.421 42.024 ;
     RECT  48.604 47.328 49.601 47.448 ;
     RECT  49.601 47.328 49.673 47.352 ;
     RECT  49.421 41.184 49.853 42.024 ;
     RECT  48.604 43.104 50.053 44.664 ;
     RECT  49.853 41.424 50.149 42.024 ;
     RECT  50.053 43.008 50.149 44.664 ;
     RECT  49.283 93.648 50.245 104.28 ;
     RECT  49.283 105.408 50.341 105.672 ;
     RECT  48.604 90.288 50.461 91.464 ;
     RECT  50.245 92.832 50.461 104.28 ;
     RECT  50.461 90.288 50.485 104.28 ;
     RECT  50.341 105.408 50.485 105.72 ;
     RECT  50.485 90.288 50.675 105.72 ;
     RECT  48.604 26.592 51.008 26.616 ;
     RECT  48.604 27.888 51.008 30.12 ;
     RECT  48.604 39.6 51.008 39.624 ;
     RECT  50.149 41.424 51.008 44.664 ;
     RECT  48.773 46.032 51.008 46.056 ;
     RECT  48.604 51.36 51.008 51.672 ;
     RECT  48.604 58.992 51.008 59.016 ;
     RECT  48.604 60.816 51.008 61.992 ;
     RECT  48.604 64.368 51.008 64.392 ;
     RECT  49.349 65.952 51.008 66.312 ;
     RECT  48.604 68.112 51.008 68.136 ;
     RECT  48.604 76.512 51.008 76.92 ;
     RECT  48.604 78.624 51.008 78.984 ;
     RECT  48.604 82.944 51.008 82.968 ;
     RECT  48.604 85.2 51.008 85.224 ;
     RECT  49.043 86.304 51.008 86.328 ;
     RECT  48.604 89.184 51.008 89.208 ;
     RECT  50.675 90.288 51.008 104.28 ;
     RECT  51.008 2.148 51.112 104.28 ;
     RECT  51.112 2.418 51.304 104.28 ;
     RECT  51.304 41.952 51.401 41.976 ;
     RECT  51.304 90.288 51.491 104.28 ;
     RECT  51.304 43.104 51.617 43.32 ;
     RECT  51.304 46.032 51.617 46.056 ;
     RECT  51.617 43.296 51.635 43.32 ;
     RECT  51.491 90.288 51.905 103.752 ;
     RECT  50.675 105.264 52.117 105.72 ;
     RECT  51.304 76.512 52.229 76.536 ;
     RECT  52.117 105.264 52.265 105.768 ;
     RECT  51.304 61.968 52.445 61.992 ;
     RECT  51.304 63.792 52.445 63.816 ;
     RECT  52.265 105.264 52.499 105.72 ;
     RECT  51.304 68.112 52.549 68.136 ;
     RECT  51.304 44.352 52.657 45 ;
     RECT  51.304 38.16 52.801 38.184 ;
     RECT  51.304 65.952 52.885 66.312 ;
     RECT  52.801 38.112 52.909 38.184 ;
     RECT  52.657 44.352 53.269 45.192 ;
     RECT  51.304 27.888 53.341 30.6 ;
     RECT  53.269 44.352 53.413 45.72 ;
     RECT  52.499 105.408 53.516 105.72 ;
     RECT  52.909 37.584 53.521 38.184 ;
     RECT  53.521 37.584 53.557 38.28 ;
     RECT  51.304 39.6 53.557 40.392 ;
     RECT  52.585 62.16 53.557 62.184 ;
     RECT  53.516 104.832 53.557 105.72 ;
     RECT  53.557 104.736 53.593 105.72 ;
     RECT  51.304 26.592 53.708 26.616 ;
     RECT  53.341 27.6 53.708 30.6 ;
     RECT  51.304 31.92 53.708 31.944 ;
     RECT  53.485 35.808 53.708 35.832 ;
     RECT  53.557 37.584 53.708 40.392 ;
     RECT  53.413 44.352 53.708 46.248 ;
     RECT  53.125 50.304 53.708 50.328 ;
     RECT  51.304 51.36 53.708 51.672 ;
     RECT  53.449 55.152 53.708 55.176 ;
     RECT  51.304 58.992 53.708 59.016 ;
     RECT  51.304 60.816 53.708 60.84 ;
     RECT  53.557 62.16 53.708 63.096 ;
     RECT  53.629 64.416 53.708 64.44 ;
     RECT  52.885 65.568 53.708 66.312 ;
     RECT  52.549 67.824 53.708 68.136 ;
     RECT  51.304 78.624 53.708 78.984 ;
     RECT  51.304 82.944 53.708 82.968 ;
     RECT  51.304 85.2 53.708 85.224 ;
     RECT  51.304 86.304 53.708 86.328 ;
     RECT  51.304 89.184 53.708 89.208 ;
     RECT  51.905 90.288 53.708 90.312 ;
     RECT  51.905 91.44 53.708 103.752 ;
     RECT  53.708 2.148 53.812 103.752 ;
     RECT  53.812 2.418 53.893 103.752 ;
     RECT  53.593 104.736 53.893 105.768 ;
     RECT  53.893 2.418 54.004 105.768 ;
     RECT  54.004 64.416 54.131 64.44 ;
     RECT  54.004 44.688 54.137 50.328 ;
     RECT  54.004 91.44 54.275 105.768 ;
     RECT  54.004 60.816 54.605 63.096 ;
     RECT  54.137 44.688 54.641 50.136 ;
     RECT  54.605 60.816 54.713 62.664 ;
     RECT  54.713 60.816 54.965 62.568 ;
     RECT  54.004 31.92 54.997 31.944 ;
     RECT  54.641 44.688 55.001 46.776 ;
     RECT  54.004 37.44 55.069 40.392 ;
     RECT  54.641 48.24 55.285 50.136 ;
     RECT  54.004 51.312 55.285 51.768 ;
     RECT  55.285 48.24 55.321 51.768 ;
     RECT  54.004 53.28 55.321 53.304 ;
     RECT  54.275 92.544 55.361 105.768 ;
     RECT  54.004 35.808 55.681 35.832 ;
     RECT  55.681 35.76 55.717 35.832 ;
     RECT  55.069 36.864 55.717 40.392 ;
     RECT  54.004 54.96 55.969 55.176 ;
     RECT  54.004 26.592 56.113 30.6 ;
     RECT  56.113 26.544 56.221 30.6 ;
     RECT  54.997 31.92 56.221 32.232 ;
     RECT  56.221 26.544 56.408 32.232 ;
     RECT  55.717 35.76 56.408 40.392 ;
     RECT  55.001 44.688 56.408 46.584 ;
     RECT  55.321 48.24 56.408 53.304 ;
     RECT  55.969 54.384 56.408 55.176 ;
     RECT  54.004 58.992 56.408 59.016 ;
     RECT  54.965 60.816 56.408 60.84 ;
     RECT  54.965 62.016 56.408 62.04 ;
     RECT  56.365 63.792 56.408 63.816 ;
     RECT  54.004 65.952 56.408 66.312 ;
     RECT  54.004 68.112 56.408 68.136 ;
     RECT  56.108 75.216 56.408 75.24 ;
     RECT  54.004 78.624 56.408 78.984 ;
     RECT  54.004 82.944 56.408 82.968 ;
     RECT  54.004 85.2 56.408 85.224 ;
     RECT  54.004 86.304 56.408 86.328 ;
     RECT  54.004 89.184 56.408 89.208 ;
     RECT  54.004 90.288 56.408 90.312 ;
     RECT  54.275 91.44 56.408 91.464 ;
     RECT  55.361 92.688 56.408 105.768 ;
     RECT  56.408 2.148 56.512 105.768 ;
     RECT  56.512 2.418 56.704 105.768 ;
     RECT  56.704 92.688 56.819 105.768 ;
     RECT  56.704 47.568 57.161 47.592 ;
     RECT  56.704 58.128 57.251 59.016 ;
     RECT  56.704 44.688 57.347 46.536 ;
     RECT  56.819 92.784 57.521 105.768 ;
     RECT  56.704 74.928 57.697 75.144 ;
     RECT  56.704 64.992 58.097 66.312 ;
     RECT  57.347 45.168 58.129 46.536 ;
     RECT  56.704 49.248 58.129 56.808 ;
     RECT  56.704 89.184 58.381 89.208 ;
     RECT  56.704 90.288 58.381 90.312 ;
     RECT  56.704 35.76 58.417 40.392 ;
     RECT  56.704 78.624 58.489 78.984 ;
     RECT  58.489 77.664 58.525 78.984 ;
     RECT  57.521 92.784 58.597 105.72 ;
     RECT  58.129 48.96 58.777 56.808 ;
     RECT  58.345 20.112 59.108 20.136 ;
     RECT  56.704 26.544 59.108 32.232 ;
     RECT  58.417 35.712 59.108 40.392 ;
     RECT  58.129 45.168 59.108 47.064 ;
     RECT  58.777 48.96 59.108 57.144 ;
     RECT  57.251 58.992 59.108 59.016 ;
     RECT  56.704 62.016 59.108 62.04 ;
     RECT  58.097 64.992 59.108 65.976 ;
     RECT  56.704 68.112 59.108 68.136 ;
     RECT  57.697 74.112 59.108 75.144 ;
     RECT  58.525 77.232 59.108 78.984 ;
     RECT  56.704 82.944 59.108 82.968 ;
     RECT  56.704 85.2 59.108 85.224 ;
     RECT  56.704 86.304 59.108 86.664 ;
     RECT  58.381 89.184 59.108 90.312 ;
     RECT  56.704 91.44 59.108 91.464 ;
     RECT  58.597 92.784 59.108 105.768 ;
     RECT  59.108 2.148 59.212 105.768 ;
     RECT  59.212 2.418 59.404 105.768 ;
     RECT  59.404 71.28 59.699 71.304 ;
     RECT  59.404 69.552 59.747 69.576 ;
     RECT  59.404 58.704 60.419 59.064 ;
     RECT  60.419 58.944 60.505 59.064 ;
     RECT  59.404 77.664 60.659 78.984 ;
     RECT  59.404 65.952 60.797 68.136 ;
     RECT  60.505 58.944 60.803 59.304 ;
     RECT  59.404 56.064 60.901 57.432 ;
     RECT  59.404 48.96 61.117 54.984 ;
     RECT  60.901 56.064 61.117 57.864 ;
     RECT  59.404 86.304 61.669 86.328 ;
     RECT  60.803 58.944 61.765 59.064 ;
     RECT  59.404 20.112 61.808 20.136 ;
     RECT  59.404 26.544 61.808 32.232 ;
     RECT  59.404 35.712 61.808 40.392 ;
     RECT  59.404 45.168 61.808 47.064 ;
     RECT  61.117 48.96 61.808 57.864 ;
     RECT  61.765 58.944 61.808 59.304 ;
     RECT  59.404 62.016 61.808 63 ;
     RECT  60.797 66.48 61.808 68.136 ;
     RECT  61.333 72.528 61.808 72.552 ;
     RECT  59.404 74.928 61.808 75.144 ;
     RECT  60.659 78.624 61.808 78.984 ;
     RECT  59.404 82.944 61.808 82.968 ;
     RECT  59.404 84.96 61.808 85.224 ;
     RECT  61.669 86.304 61.808 87.144 ;
     RECT  59.404 89.184 61.808 90.312 ;
     RECT  59.404 91.44 61.808 91.464 ;
     RECT  59.404 92.784 61.808 105.768 ;
     RECT  61.808 2.148 61.912 105.768 ;
     RECT  61.912 2.418 62.104 105.768 ;
     RECT  62.104 94.656 62.291 105.768 ;
     RECT  62.104 48.96 62.579 59.304 ;
     RECT  62.104 45.168 62.675 47.064 ;
     RECT  62.104 69.456 62.705 69.48 ;
     RECT  62.579 49.2 62.819 59.304 ;
     RECT  62.819 54.96 62.867 59.064 ;
     RECT  62.104 70.656 62.867 73.56 ;
     RECT  62.104 74.64 62.915 75.144 ;
     RECT  62.819 49.2 62.963 53.928 ;
     RECT  62.915 74.736 63.011 75.144 ;
     RECT  62.104 78.576 63.011 78.984 ;
     RECT  62.104 82.608 63.011 82.968 ;
     RECT  62.104 86.304 63.011 86.664 ;
     RECT  62.104 89.184 63.011 91.464 ;
     RECT  63.011 74.928 63.065 75.144 ;
     RECT  62.867 70.704 63.107 71.016 ;
     RECT  63.011 91.44 63.253 91.464 ;
     RECT  62.104 66.48 63.709 68.136 ;
     RECT  63.709 66.24 63.877 68.136 ;
     RECT  62.867 72.768 64.133 73.56 ;
     RECT  64.133 72.336 64.309 73.56 ;
     RECT  63.065 74.928 64.309 74.952 ;
     RECT  63.011 82.944 64.309 82.968 ;
     RECT  62.104 20.112 64.508 20.136 ;
     RECT  62.104 26.544 64.508 32.232 ;
     RECT  62.104 35.712 64.508 40.392 ;
     RECT  62.675 45.168 64.508 46.536 ;
     RECT  62.963 49.2 64.508 53.88 ;
     RECT  62.867 54.96 64.508 57.864 ;
     RECT  62.867 58.944 64.508 59.064 ;
     RECT  62.104 60.912 64.508 60.936 ;
     RECT  62.104 62.016 64.508 63 ;
     RECT  62.104 64.992 64.508 65.016 ;
     RECT  63.877 66.096 64.508 68.136 ;
     RECT  64.076 69.552 64.508 69.576 ;
     RECT  63.107 70.704 64.508 70.728 ;
     RECT  64.309 72.24 64.508 73.56 ;
     RECT  64.309 74.88 64.508 74.952 ;
     RECT  63.011 78.624 64.508 78.984 ;
     RECT  64.309 82.464 64.508 82.968 ;
     RECT  62.104 85.2 64.508 85.224 ;
     RECT  63.011 86.304 64.508 86.328 ;
     RECT  63.011 89.184 64.508 90.312 ;
     RECT  63.253 91.44 64.508 92.184 ;
     RECT  62.291 94.944 64.508 105.768 ;
     RECT  64.508 2.148 64.612 105.768 ;
     RECT  64.612 2.418 64.804 105.768 ;
     RECT  64.804 60.912 64.901 60.936 ;
     RECT  64.804 62.016 64.973 62.76 ;
     RECT  64.804 56.256 64.979 57.864 ;
     RECT  64.804 58.944 65.009 59.064 ;
     RECT  64.804 82.464 65.081 82.968 ;
     RECT  64.804 54.96 65.123 55.272 ;
     RECT  65.081 82.608 65.171 82.968 ;
     RECT  65.009 58.992 65.219 59.064 ;
     RECT  64.979 56.256 65.225 57.528 ;
     RECT  64.804 64.992 65.267 65.016 ;
     RECT  64.804 66.24 65.363 68.136 ;
     RECT  64.804 71.04 65.369 72.792 ;
     RECT  64.804 74.688 65.405 74.952 ;
     RECT  65.171 82.704 65.405 82.968 ;
     RECT  65.363 66.24 65.411 66.264 ;
     RECT  65.123 55.152 65.459 55.272 ;
     RECT  65.369 71.04 65.621 71.976 ;
     RECT  64.804 50.832 65.747 53.88 ;
     RECT  65.225 56.592 65.843 57.528 ;
     RECT  65.843 56.592 65.891 57.384 ;
     RECT  64.804 96 65.909 105.768 ;
     RECT  65.891 56.592 65.939 57.144 ;
     RECT  64.804 63.84 65.987 63.864 ;
     RECT  64.804 89.184 66.179 90.312 ;
     RECT  65.909 96 66.413 105.72 ;
     RECT  64.804 35.712 66.697 40.392 ;
     RECT  66.413 104.592 66.809 105.72 ;
     RECT  66.413 96 66.845 103.512 ;
     RECT  66.809 105.6 66.953 105.72 ;
     RECT  66.953 105.6 67.133 105.672 ;
     RECT  66.809 104.592 67.205 104.616 ;
     RECT  64.804 20.112 67.208 20.136 ;
     RECT  64.804 26.544 67.208 32.232 ;
     RECT  66.697 35.712 67.208 40.44 ;
     RECT  64.804 45.168 67.208 46.536 ;
     RECT  64.804 49.2 67.208 49.848 ;
     RECT  65.747 50.832 67.208 51.768 ;
     RECT  65.747 52.752 67.208 53.88 ;
     RECT  65.459 55.248 67.208 55.272 ;
     RECT  65.939 56.592 67.208 56.808 ;
     RECT  65.219 58.992 67.208 59.016 ;
     RECT  64.973 62.016 67.208 62.472 ;
     RECT  65.363 67.68 67.208 68.136 ;
     RECT  65.621 71.856 67.208 71.976 ;
     RECT  65.405 74.928 67.208 74.952 ;
     RECT  64.804 78.624 67.208 78.984 ;
     RECT  65.405 82.944 67.208 82.968 ;
     RECT  64.804 85.2 67.208 85.224 ;
     RECT  64.804 86.304 67.208 86.328 ;
     RECT  66.179 89.184 67.208 89.208 ;
     RECT  66.179 90.288 67.208 90.312 ;
     RECT  64.804 91.44 67.208 92.184 ;
     RECT  64.804 94.944 67.208 94.968 ;
     RECT  66.845 96 67.208 103.422 ;
     RECT  67.208 2.148 67.312 103.422 ;
     RECT  67.133 105.6 67.349 105.624 ;
     RECT  67.312 2.418 67.504 103.422 ;
     RECT  67.504 67.68 68.105 68.136 ;
     RECT  67.504 71.952 68.141 71.976 ;
     RECT  67.504 74.064 68.429 74.952 ;
     RECT  67.504 45.984 68.435 46.152 ;
     RECT  67.504 96 68.483 103.272 ;
     RECT  68.435 46.032 68.579 46.152 ;
     RECT  67.504 82.944 68.629 82.968 ;
     RECT  68.483 103.008 68.675 103.272 ;
     RECT  67.504 78.624 68.929 78.984 ;
     RECT  67.504 26.544 69.505 32.232 ;
     RECT  67.504 20.112 69.908 20.136 ;
     RECT  69.505 26.112 69.908 32.232 ;
     RECT  69.205 33.312 69.908 33.336 ;
     RECT  67.504 35.712 69.908 40.44 ;
     RECT  67.504 49.2 69.908 49.512 ;
     RECT  67.504 50.928 69.908 51.768 ;
     RECT  67.504 55.248 69.908 55.272 ;
     RECT  67.504 56.592 69.908 56.616 ;
     RECT  67.504 58.992 69.908 59.016 ;
     RECT  67.504 62.016 69.908 62.04 ;
     RECT  68.105 67.68 69.908 67.704 ;
     RECT  68.429 74.928 69.908 74.952 ;
     RECT  67.504 77.04 69.908 77.064 ;
     RECT  68.929 78.096 69.908 78.984 ;
     RECT  68.629 82.944 69.908 83.592 ;
     RECT  67.504 85.2 69.908 85.224 ;
     RECT  67.504 86.304 69.908 86.328 ;
     RECT  67.504 89.184 69.908 89.208 ;
     RECT  67.504 90.288 69.908 90.312 ;
     RECT  67.504 91.44 69.908 92.184 ;
     RECT  67.504 94.944 69.908 94.968 ;
     RECT  68.483 96 69.908 101.976 ;
     RECT  68.675 103.248 69.908 103.272 ;
     RECT  69.908 2.148 70.012 103.272 ;
     RECT  70.012 2.418 70.1 103.272 ;
     RECT  70.1 2.418 70.204 103.422 ;
     RECT  70.204 49.2 70.301 49.512 ;
     RECT  70.204 82.944 70.301 83.592 ;
     RECT  70.204 56.736 70.733 56.856 ;
     RECT  70.301 82.944 70.733 83.496 ;
     RECT  70.204 96 70.733 102.024 ;
     RECT  70.204 20.112 72.608 20.136 ;
     RECT  70.204 26.112 72.608 32.232 ;
     RECT  70.204 33.312 72.608 33.336 ;
     RECT  70.204 35.712 72.608 40.44 ;
     RECT  72.349 43.632 72.608 43.656 ;
     RECT  70.301 49.248 72.608 49.512 ;
     RECT  70.204 50.928 72.608 51.768 ;
     RECT  70.204 55.248 72.608 55.272 ;
     RECT  70.733 56.832 72.608 56.856 ;
     RECT  70.204 58.992 72.608 59.016 ;
     RECT  70.204 62.016 72.608 62.04 ;
     RECT  70.204 67.68 72.608 67.704 ;
     RECT  70.204 74.928 72.608 74.952 ;
     RECT  70.204 77.04 72.608 77.064 ;
     RECT  70.204 78.096 72.608 78.984 ;
     RECT  70.733 82.944 72.608 83.352 ;
     RECT  70.204 85.2 72.608 85.224 ;
     RECT  70.204 86.304 72.608 86.328 ;
     RECT  70.204 89.184 72.608 89.208 ;
     RECT  70.204 90.288 72.608 90.312 ;
     RECT  70.204 91.44 72.608 92.184 ;
     RECT  70.204 94.944 72.608 94.968 ;
     RECT  70.733 96 72.608 101.976 ;
     RECT  70.204 103.248 72.608 103.272 ;
     RECT  72.608 2.148 72.712 103.272 ;
     RECT  72.712 2.418 72.8 103.272 ;
     RECT  72.8 2.418 72.904 103.422 ;
     RECT  72.904 96 73.253 101.976 ;
     RECT  73.253 96 73.325 96.264 ;
     RECT  72.904 20.112 75.308 20.136 ;
     RECT  72.904 26.112 75.308 32.232 ;
     RECT  72.904 33.312 75.308 33.336 ;
     RECT  72.904 35.712 75.308 40.44 ;
     RECT  72.904 43.632 75.308 43.656 ;
     RECT  72.904 49.248 75.308 49.512 ;
     RECT  72.904 50.928 75.308 51.768 ;
     RECT  72.904 55.248 75.308 55.272 ;
     RECT  72.904 56.832 75.308 56.856 ;
     RECT  72.904 58.992 75.308 59.016 ;
     RECT  72.904 62.016 75.308 62.04 ;
     RECT  72.904 67.68 75.308 67.704 ;
     RECT  72.904 74.928 75.308 74.952 ;
     RECT  72.904 77.04 75.308 77.064 ;
     RECT  72.904 78.096 75.308 79.752 ;
     RECT  72.904 82.944 75.308 83.352 ;
     RECT  72.904 85.2 75.308 85.224 ;
     RECT  72.904 86.304 75.308 86.328 ;
     RECT  72.904 89.184 75.308 89.208 ;
     RECT  72.904 90.288 75.308 90.312 ;
     RECT  72.904 91.44 75.308 92.184 ;
     RECT  72.904 94.944 75.308 94.968 ;
     RECT  73.325 96 75.308 96.024 ;
     RECT  73.253 98.112 75.308 101.976 ;
     RECT  72.904 103.248 75.308 103.272 ;
     RECT  75.308 2.148 75.412 103.272 ;
     RECT  75.412 2.418 75.5 103.272 ;
     RECT  75.5 2.418 75.604 103.422 ;
     RECT  75.604 98.112 76.961 101.976 ;
     RECT  75.604 35.712 77.03 40.44 ;
     RECT  75.604 20.112 78.008 20.136 ;
     RECT  75.604 26.112 78.008 32.232 ;
     RECT  75.604 33.312 78.008 33.336 ;
     RECT  77.03 35.712 78.008 40.392 ;
     RECT  75.604 43.632 78.008 43.656 ;
     RECT  75.604 49.248 78.008 49.512 ;
     RECT  75.604 50.928 78.008 51.768 ;
     RECT  75.604 55.248 78.008 55.272 ;
     RECT  75.604 56.832 78.008 56.856 ;
     RECT  75.604 58.992 78.008 59.016 ;
     RECT  75.604 62.016 78.008 62.04 ;
     RECT  75.604 67.68 78.008 67.704 ;
     RECT  75.604 74.928 78.008 74.952 ;
     RECT  75.604 77.04 78.008 77.064 ;
     RECT  75.604 78.096 78.008 79.752 ;
     RECT  75.604 82.944 78.008 82.968 ;
     RECT  75.604 85.2 78.008 85.224 ;
     RECT  75.604 86.304 78.008 86.328 ;
     RECT  75.604 89.184 78.008 89.208 ;
     RECT  75.604 90.288 78.008 90.312 ;
     RECT  75.604 91.44 78.008 92.184 ;
     RECT  75.604 94.944 78.008 94.968 ;
     RECT  76.961 98.112 78.008 99 ;
     RECT  76.961 100.608 78.008 101.976 ;
     RECT  75.604 103.248 78.008 103.272 ;
     RECT  78.008 2.148 78.112 103.272 ;
     RECT  78.112 2.418 78.2 103.272 ;
     RECT  78.2 2.418 78.304 103.422 ;
     RECT  78.304 56.736 78.689 56.856 ;
     RECT  78.304 98.208 78.689 99 ;
     RECT  78.304 90.288 79.121 90.312 ;
     RECT  78.304 20.112 80.708 20.136 ;
     RECT  78.304 26.112 80.708 32.232 ;
     RECT  78.304 33.312 80.708 33.336 ;
     RECT  78.304 35.712 80.708 40.44 ;
     RECT  78.304 43.632 80.708 43.656 ;
     RECT  78.304 49.248 80.708 49.512 ;
     RECT  78.304 50.928 80.708 51.768 ;
     RECT  78.304 55.248 80.708 55.272 ;
     RECT  78.689 56.832 80.708 56.856 ;
     RECT  78.304 58.992 80.708 59.016 ;
     RECT  78.304 62.016 80.708 62.04 ;
     RECT  78.304 67.68 80.708 67.704 ;
     RECT  78.304 74.928 80.708 74.952 ;
     RECT  78.304 77.04 80.708 77.064 ;
     RECT  78.304 78.096 80.708 79.752 ;
     RECT  78.304 82.944 80.708 82.968 ;
     RECT  78.304 85.2 80.708 85.224 ;
     RECT  78.304 86.304 80.708 86.328 ;
     RECT  78.304 89.184 80.708 89.208 ;
     RECT  78.304 91.44 80.708 92.184 ;
     RECT  78.304 94.944 80.708 94.968 ;
     RECT  78.689 98.352 80.708 99 ;
     RECT  78.304 100.608 80.708 101.976 ;
     RECT  78.304 103.248 80.708 103.272 ;
     RECT  80.708 2.148 80.812 103.272 ;
     RECT  80.812 2.418 80.9 103.272 ;
     RECT  80.9 2.418 81.004 103.422 ;
     RECT  81.004 91.44 81.533 92.184 ;
     RECT  81.533 91.44 82.217 91.752 ;
     RECT  81.004 35.712 82.645 40.392 ;
     RECT  81.004 20.112 83.408 20.136 ;
     RECT  81.004 26.112 83.408 32.232 ;
     RECT  81.004 33.312 83.408 33.336 ;
     RECT  82.645 35.712 83.408 40.44 ;
     RECT  81.004 43.632 83.408 43.656 ;
     RECT  81.004 49.248 83.408 49.512 ;
     RECT  81.004 50.928 83.408 51.768 ;
     RECT  81.004 55.248 83.408 55.272 ;
     RECT  81.004 56.832 83.408 56.856 ;
     RECT  81.004 58.992 83.408 59.016 ;
     RECT  81.004 62.016 83.408 62.04 ;
     RECT  81.004 67.68 83.408 67.704 ;
     RECT  81.004 74.928 83.408 74.952 ;
     RECT  81.004 77.04 83.408 77.064 ;
     RECT  81.004 78.096 83.408 79.752 ;
     RECT  81.004 82.944 83.408 82.968 ;
     RECT  81.004 85.2 83.408 85.224 ;
     RECT  81.004 89.184 83.408 89.208 ;
     RECT  82.217 91.44 83.408 91.464 ;
     RECT  81.004 94.944 83.408 94.968 ;
     RECT  81.004 98.352 83.408 98.376 ;
     RECT  81.004 100.608 83.408 101.976 ;
     RECT  81.004 103.248 83.408 103.272 ;
     RECT  83.408 2.148 83.512 103.272 ;
     RECT  83.512 2.418 83.6 103.272 ;
     RECT  83.6 2.418 83.704 103.422 ;
     RECT  83.704 20.112 86.108 20.136 ;
     RECT  83.704 26.112 86.108 32.232 ;
     RECT  83.704 33.312 86.108 33.336 ;
     RECT  83.704 35.712 86.108 40.44 ;
     RECT  83.704 43.632 86.108 43.656 ;
     RECT  83.704 49.248 86.108 49.512 ;
     RECT  83.704 50.928 86.108 51.768 ;
     RECT  83.704 55.248 86.108 55.272 ;
     RECT  83.704 56.832 86.108 56.856 ;
     RECT  83.704 58.992 86.108 59.016 ;
     RECT  83.704 62.016 86.108 62.04 ;
     RECT  83.704 67.68 86.108 67.704 ;
     RECT  83.704 74.928 86.108 74.952 ;
     RECT  83.704 77.04 86.108 77.064 ;
     RECT  83.704 78.096 86.108 79.752 ;
     RECT  83.704 85.2 86.108 85.224 ;
     RECT  83.704 89.184 86.108 89.208 ;
     RECT  83.704 91.44 86.108 91.464 ;
     RECT  83.704 94.944 86.108 94.968 ;
     RECT  83.704 100.608 86.108 101.976 ;
     RECT  83.704 103.248 86.108 103.272 ;
     RECT  86.108 2.148 86.212 103.272 ;
     RECT  86.212 2.418 86.3 103.272 ;
     RECT  86.3 2.418 86.404 103.422 ;
     RECT  86.404 35.712 86.429 40.44 ;
     RECT  86.404 49.248 86.501 49.512 ;
     RECT  86.404 56.736 86.681 56.856 ;
     RECT  86.404 85.2 87.257 85.224 ;
     RECT  86.404 20.112 88.808 20.136 ;
     RECT  86.404 26.112 88.808 32.232 ;
     RECT  86.404 33.312 88.808 33.336 ;
     RECT  86.429 35.712 88.808 40.392 ;
     RECT  86.404 43.632 88.808 43.656 ;
     RECT  86.501 49.344 88.808 49.512 ;
     RECT  86.404 50.928 88.808 51.768 ;
     RECT  86.404 55.248 88.808 55.272 ;
     RECT  86.681 56.832 88.808 56.856 ;
     RECT  86.404 58.992 88.808 59.016 ;
     RECT  86.404 62.016 88.808 62.04 ;
     RECT  86.404 67.68 88.808 67.704 ;
     RECT  86.404 74.928 88.808 74.952 ;
     RECT  86.404 77.04 88.808 77.064 ;
     RECT  86.404 78.096 88.808 79.752 ;
     RECT  86.404 89.184 88.808 89.208 ;
     RECT  86.404 91.44 88.808 91.464 ;
     RECT  86.404 94.944 88.808 94.968 ;
     RECT  86.404 100.608 88.808 101.976 ;
     RECT  86.404 103.248 88.808 103.272 ;
     RECT  88.808 2.148 88.912 103.272 ;
     RECT  88.912 2.418 89 103.272 ;
     RECT  89 2.418 89.104 103.422 ;
     RECT  89.104 100.608 89.597 101.976 ;
     RECT  89.104 89.184 90.389 89.208 ;
     RECT  89.104 35.712 90.629 40.392 ;
     RECT  89.104 49.344 90.637 49.512 ;
     RECT  89.597 101.184 90.637 101.976 ;
     RECT  89.104 74.928 91.177 74.952 ;
     RECT  89.104 56.832 91.213 56.856 ;
     RECT  89.104 20.112 91.508 20.136 ;
     RECT  89.104 26.112 91.508 32.232 ;
     RECT  89.104 33.312 91.508 33.336 ;
     RECT  90.629 35.712 91.508 40.44 ;
     RECT  89.104 43.632 91.508 43.656 ;
     RECT  90.637 49.248 91.508 49.512 ;
     RECT  89.104 50.928 91.508 51.768 ;
     RECT  89.104 55.248 91.508 55.272 ;
     RECT  91.213 56.784 91.508 56.856 ;
     RECT  89.104 58.992 91.508 59.016 ;
     RECT  89.104 62.016 91.508 62.04 ;
     RECT  89.104 67.68 91.508 67.704 ;
     RECT  91.177 74.928 91.508 75.24 ;
     RECT  89.104 76.272 91.508 77.064 ;
     RECT  89.104 78.096 91.508 79.752 ;
     RECT  89.104 91.44 91.508 91.464 ;
     RECT  90.637 101.088 91.508 101.976 ;
     RECT  89.104 103.248 91.508 103.272 ;
     RECT  91.508 2.148 91.612 103.272 ;
     RECT  91.612 2.418 91.7 103.272 ;
     RECT  91.7 2.418 91.804 103.422 ;
     RECT  91.804 43.632 93.445 43.656 ;
     RECT  93.481 71.952 94.021 71.976 ;
     RECT  91.804 20.112 94.208 20.136 ;
     RECT  91.804 26.112 94.208 32.232 ;
     RECT  91.804 33.312 94.208 33.336 ;
     RECT  91.804 35.712 94.208 40.44 ;
     RECT  91.804 41.424 94.208 41.448 ;
     RECT  93.445 43.632 94.208 43.848 ;
     RECT  91.804 49.248 94.208 49.512 ;
     RECT  91.804 50.928 94.208 51.768 ;
     RECT  93.445 53.808 94.208 53.832 ;
     RECT  91.804 55.248 94.208 55.272 ;
     RECT  91.804 56.784 94.208 56.856 ;
     RECT  91.804 58.992 94.208 59.016 ;
     RECT  91.804 62.016 94.208 62.04 ;
     RECT  91.804 64.944 94.208 64.968 ;
     RECT  94.021 66.528 94.208 66.552 ;
     RECT  91.804 67.68 94.208 67.704 ;
     RECT  92.905 70.032 94.208 70.056 ;
     RECT  94.021 71.952 94.208 72.024 ;
     RECT  91.804 74.928 94.208 75.24 ;
     RECT  91.804 76.272 94.208 77.064 ;
     RECT  91.804 78.096 94.208 79.752 ;
     RECT  91.804 91.44 94.208 91.464 ;
     RECT  91.804 101.088 94.208 101.976 ;
     RECT  91.804 103.248 94.208 103.272 ;
     RECT  94.208 2.148 94.312 103.272 ;
     RECT  94.312 2.418 94.4 103.272 ;
     RECT  94.4 2.418 94.504 103.422 ;
     RECT  94.504 49.248 94.601 49.512 ;
     RECT  94.504 35.712 94.609 40.44 ;
     RECT  94.504 101.088 94.673 101.208 ;
     RECT  94.504 63.888 95.713 63.912 ;
     RECT  94.504 64.944 95.713 64.968 ;
     RECT  94.504 66.528 95.713 66.552 ;
     RECT  94.504 67.68 95.713 67.704 ;
     RECT  94.504 50.928 95.749 51.768 ;
     RECT  94.504 91.44 95.897 91.464 ;
     RECT  94.504 53.376 96.109 53.832 ;
     RECT  94.504 55.248 96.109 55.272 ;
     RECT  94.504 43.632 96.253 43.848 ;
     RECT  94.504 45.456 96.253 45.48 ;
     RECT  95.749 50.928 96.289 52.2 ;
     RECT  94.609 35.712 96.865 40.392 ;
     RECT  94.504 41.424 96.865 41.448 ;
     RECT  96.865 35.712 96.901 41.448 ;
     RECT  94.504 20.112 96.908 20.136 ;
     RECT  94.504 26.112 96.908 32.232 ;
     RECT  94.504 33.312 96.908 33.336 ;
     RECT  96.901 35.712 96.908 41.928 ;
     RECT  96.253 43.632 96.908 45.48 ;
     RECT  94.504 47.664 96.908 47.88 ;
     RECT  94.601 49.344 96.908 49.512 ;
     RECT  96.289 50.928 96.908 52.248 ;
     RECT  96.109 53.376 96.908 55.272 ;
     RECT  94.504 56.736 96.908 56.808 ;
     RECT  94.504 58.992 96.908 59.016 ;
     RECT  94.504 62.016 96.908 62.04 ;
     RECT  95.713 63.888 96.908 64.968 ;
     RECT  95.713 66.528 96.908 67.704 ;
     RECT  94.504 70.032 96.908 70.872 ;
     RECT  94.504 71.952 96.908 72.024 ;
     RECT  94.504 74.928 96.908 75.24 ;
     RECT  94.504 76.272 96.908 77.064 ;
     RECT  94.504 78.096 96.908 79.752 ;
     RECT  94.673 101.088 96.908 101.112 ;
     RECT  94.504 103.248 96.908 103.272 ;
     RECT  96.908 2.148 97.012 103.272 ;
     RECT  97.012 2.418 97.1 103.272 ;
     RECT  97.1 2.418 97.204 103.422 ;
     RECT  97.204 66.528 97.301 68.136 ;
     RECT  97.204 47.664 98.485 47.88 ;
     RECT  97.204 70.032 98.521 72.84 ;
     RECT  98.485 47.568 98.557 47.88 ;
     RECT  97.204 48.912 98.557 52.344 ;
     RECT  97.204 62.016 98.557 62.04 ;
     RECT  97.204 78.096 98.557 79.752 ;
     RECT  98.557 47.568 98.593 52.344 ;
     RECT  97.204 53.376 98.593 56.856 ;
     RECT  97.204 103.248 98.813 103.272 ;
     RECT  97.204 34.992 99.133 45.48 ;
     RECT  98.593 46.512 99.133 52.344 ;
     RECT  98.593 53.376 99.133 56.904 ;
     RECT  98.521 69.456 99.133 72.84 ;
     RECT  97.204 26.112 99.457 32.232 ;
     RECT  97.204 33.312 99.457 33.336 ;
     RECT  98.557 61.2 99.565 62.04 ;
     RECT  97.301 66.624 99.565 68.136 ;
     RECT  97.204 20.112 99.608 20.136 ;
     RECT  99.457 26.112 99.608 33.336 ;
     RECT  99.133 34.992 99.608 56.904 ;
     RECT  97.204 58.992 99.608 59.016 ;
     RECT  99.565 60.624 99.608 62.04 ;
     RECT  97.204 63.888 99.608 64.968 ;
     RECT  99.565 66.048 99.608 68.136 ;
     RECT  99.133 69.456 99.608 73.032 ;
     RECT  97.204 74.016 99.608 77.064 ;
     RECT  98.557 78.096 99.608 79.8 ;
     RECT  97.204 101.088 99.608 101.112 ;
     RECT  99.608 2.148 99.712 103.152 ;
     RECT  99.712 2.418 99.8 103.152 ;
     RECT  99.8 2.418 99.904 103.422 ;
     RECT  99.904 26.112 99.962 32.616 ;
     RECT  99.904 78.096 100.001 79.8 ;
     RECT  99.904 60.624 100.541 77.064 ;
     RECT  99.962 26.16 101.077 32.616 ;
     RECT  99.904 23.28 101.149 23.88 ;
     RECT  101.149 22.992 101.185 23.88 ;
     RECT  99.904 34.704 101.185 57.096 ;
     RECT  101.185 22.992 101.257 24.36 ;
     RECT  101.077 25.392 101.365 32.616 ;
     RECT  101.365 25.392 101.473 32.904 ;
     RECT  101.185 34.032 101.473 57.096 ;
     RECT  101.257 22.8 101.653 24.36 ;
     RECT  101.473 25.392 101.653 57.48 ;
     RECT  99.904 58.992 101.941 59.016 ;
     RECT  100.541 60.624 101.941 76.584 ;
     RECT  99.904 20.112 102.013 21.48 ;
     RECT  101.653 22.8 102.013 57.48 ;
     RECT  100.001 78.096 102.553 79.656 ;
     RECT  101.941 58.992 102.589 76.584 ;
     RECT  102.589 58.992 103.129 76.68 ;
     RECT  102.553 78.096 103.129 79.752 ;
     RECT  102.013 20.112 103.165 57.48 ;
     RECT  103.129 58.896 103.165 76.68 ;
     RECT  103.129 77.808 103.165 79.752 ;
     RECT  103.165 20.112 103.201 79.752 ;
     RECT  103.201 20.112 103.921 79.848 ;
     RECT  103.921 20.016 103.957 79.848 ;
     RECT  103.957 19.92 104.028 79.848 ;
     RECT  104.028 52.32 104.069 52.344 ;
     RECT  104.028 53.376 104.069 53.4 ;
     RECT  104.028 65.952 104.069 67.032 ;
     RECT  104.028 73.344 104.069 75 ;
    LAYER M5 ;
     RECT  2.4 2.137 2.52 2.151 ;
     RECT  5.1 2.137 5.22 2.151 ;
     RECT  7.8 2.137 7.92 2.151 ;
     RECT  10.5 2.137 10.62 2.151 ;
     RECT  13.2 2.137 13.32 2.151 ;
     RECT  15.9 2.137 16.02 2.151 ;
     RECT  18.6 2.137 18.72 2.151 ;
     RECT  21.3 2.137 21.42 2.151 ;
     RECT  24 2.137 24.12 2.151 ;
     RECT  26.7 2.137 26.82 2.151 ;
     RECT  29.4 2.137 29.52 2.151 ;
     RECT  32.1 2.137 32.22 2.151 ;
     RECT  34.8 2.137 34.92 2.151 ;
     RECT  37.5 2.137 37.62 2.151 ;
     RECT  40.2 2.137 40.32 2.151 ;
     RECT  42.9 2.137 43.02 2.151 ;
     RECT  45.6 2.137 45.72 2.151 ;
     RECT  48.3 2.137 48.42 2.151 ;
     RECT  51 2.137 51.12 2.151 ;
     RECT  53.7 2.137 53.82 2.151 ;
     RECT  56.4 2.137 56.52 2.151 ;
     RECT  59.1 2.137 59.22 2.151 ;
     RECT  61.8 2.137 61.92 2.151 ;
     RECT  64.5 2.137 64.62 2.151 ;
     RECT  67.2 2.137 67.32 2.151 ;
     RECT  69.9 2.137 70.02 2.151 ;
     RECT  72.6 2.137 72.72 2.151 ;
     RECT  75.3 2.137 75.42 2.151 ;
     RECT  78 2.137 78.12 2.151 ;
     RECT  80.7 2.137 80.82 2.151 ;
     RECT  83.4 2.137 83.52 2.151 ;
     RECT  86.1 2.137 86.22 2.151 ;
     RECT  88.8 2.137 88.92 2.151 ;
     RECT  91.5 2.137 91.62 2.151 ;
     RECT  94.2 2.137 94.32 2.151 ;
     RECT  96.9 2.137 97.02 2.151 ;
     RECT  99.6 2.137 99.72 2.151 ;
     RECT  69.9 2.151 70.212 28.501 ;
     RECT  78 2.151 78.312 28.501 ;
     RECT  86.1 2.151 86.412 28.501 ;
     RECT  69.9 28.501 70.728 28.787 ;
     RECT  78 28.501 78.696 28.787 ;
     RECT  86.1 28.501 86.664 28.787 ;
     RECT  40.2 2.151 40.512 30.181 ;
     RECT  69.9 28.787 70.212 31.477 ;
     RECT  69.9 31.477 70.392 31.763 ;
     RECT  69.9 31.763 70.212 33.301 ;
     RECT  102.336 36.037 102.36 36.085 ;
     RECT  102.336 36.085 102.456 36.275 ;
     RECT  86.1 28.787 86.412 37.141 ;
     RECT  86.1 37.141 86.712 37.427 ;
     RECT  76.944 37.333 76.968 37.475 ;
     RECT  61.8 2.151 62.112 40.117 ;
     RECT  61.8 40.117 62.232 40.259 ;
     RECT  76.944 40.261 76.968 40.403 ;
     RECT  37.5 2.151 37.812 41.125 ;
     RECT  41.808 35.605 41.832 41.221 ;
     RECT  42.9 2.151 43.212 41.221 ;
     RECT  40.2 30.181 40.728 41.365 ;
     RECT  41.808 41.221 43.212 41.365 ;
     RECT  45.6 2.151 45.912 41.413 ;
     RECT  37.152 41.125 37.812 41.605 ;
     RECT  40.2 41.365 43.212 41.653 ;
     RECT  44.256 41.365 44.28 41.653 ;
     RECT  40.2 41.653 44.28 41.893 ;
     RECT  40.2 41.893 44.328 41.941 ;
     RECT  45.6 41.413 46.344 41.941 ;
     RECT  51 2.151 51.312 42.133 ;
     RECT  50.16 42.133 51.312 42.997 ;
     RECT  37.152 41.605 38.328 43.237 ;
     RECT  50.064 42.997 51.312 43.285 ;
     RECT  37.152 43.237 38.712 44.389 ;
     RECT  48.3 2.151 48.612 44.629 ;
     RECT  56.4 2.151 56.712 44.677 ;
     RECT  53.7 2.151 54.012 44.869 ;
     RECT  50.064 43.285 51.624 44.965 ;
     RECT  53.232 44.869 54.012 44.965 ;
     RECT  67.2 2.151 67.512 45.157 ;
     RECT  59.1 2.151 59.412 45.205 ;
     RECT  59.1 45.205 59.928 45.493 ;
     RECT  61.8 40.259 62.112 45.685 ;
     RECT  61.8 45.685 62.52 45.733 ;
     RECT  66.72 45.157 67.512 45.973 ;
     RECT  69.216 33.301 70.212 45.973 ;
     RECT  40.2 41.941 46.344 46.213 ;
     RECT  47.376 44.629 48.612 46.213 ;
     RECT  64.5 2.151 64.812 46.213 ;
     RECT  66.72 45.973 70.212 46.501 ;
     RECT  53.04 44.965 54.012 46.741 ;
     RECT  55.392 46.117 55.416 46.741 ;
     RECT  61.2 45.733 62.52 47.029 ;
     RECT  40.2 46.213 48.612 47.317 ;
     RECT  36.24 44.389 38.712 47.605 ;
     RECT  98.592 47.653 98.616 47.891 ;
     RECT  53.04 46.741 55.416 48.997 ;
     RECT  56.4 44.677 57.336 48.997 ;
     RECT  66.48 46.501 70.212 49.237 ;
     RECT  63.84 46.213 64.812 50.389 ;
     RECT  58.368 45.493 59.928 50.533 ;
     RECT  36.24 47.605 38.952 50.581 ;
     RECT  40.2 47.317 48.792 50.581 ;
     RECT  53.04 48.997 57.336 51.301 ;
     RECT  58.368 50.533 60.168 51.301 ;
     RECT  53.04 51.301 60.168 51.685 ;
     RECT  61.2 47.029 62.664 51.685 ;
     RECT  63.648 50.389 64.812 52.261 ;
     RECT  66 49.237 70.212 52.261 ;
     RECT  53.04 51.685 62.664 53.317 ;
     RECT  63.648 52.261 70.212 53.317 ;
     RECT  24 2.151 24.312 53.893 ;
     RECT  29.4 2.151 29.712 54.037 ;
     RECT  23.904 53.893 24.312 54.083 ;
     RECT  0.192 54.085 0.312 54.227 ;
     RECT  36.24 50.581 48.792 60.997 ;
     RECT  36.24 60.997 48.84 61.045 ;
     RECT  50.064 44.965 51.96 61.045 ;
     RECT  34.8 2.151 35.112 61.957 ;
     RECT  36.24 61.045 51.96 61.957 ;
     RECT  101.664 62.389 101.688 62.723 ;
     RECT  34.8 61.957 51.96 63.781 ;
     RECT  34.8 63.781 52.056 65.557 ;
     RECT  53.04 53.317 70.212 65.557 ;
     RECT  102.576 65.941 102.6 66.083 ;
     RECT  33.504 41.173 33.528 66.277 ;
     RECT  34.8 65.557 70.212 66.277 ;
     RECT  102.576 69.781 102.6 70.067 ;
     RECT  26.7 2.151 27.012 78.901 ;
     RECT  72.6 2.151 72.912 79.717 ;
     RECT  0.192 54.227 0.216 90.851 ;
     RECT  32.1 2.151 32.412 91.429 ;
     RECT  33.504 66.277 70.212 91.429 ;
     RECT  26.7 78.901 27.336 92.387 ;
     RECT  26.7 92.387 27.144 92.723 ;
     RECT  72.6 79.717 73.224 96.323 ;
     RECT  72.6 96.323 73.032 96.709 ;
     RECT  72.48 96.709 73.032 97.331 ;
     RECT  72.6 97.331 73.032 98.915 ;
     RECT  28.8 54.037 29.712 99.731 ;
     RECT  32.1 91.429 70.212 100.931 ;
     RECT  94.2 2.151 94.512 101.077 ;
     RECT  94.2 101.077 94.632 101.219 ;
     RECT  32.1 100.931 68.664 101.413 ;
     RECT  31.968 101.413 68.664 101.651 ;
     RECT  31.968 101.651 41.304 102.035 ;
     RECT  31.968 102.035 38.712 102.083 ;
     RECT  42.432 101.651 68.664 102.083 ;
     RECT  39.744 102.035 41.304 102.467 ;
     RECT  34.8 102.083 38.712 102.659 ;
     RECT  42.576 102.083 68.664 102.659 ;
     RECT  31.968 102.083 33.528 102.755 ;
     RECT  42.624 102.659 68.664 102.899 ;
     RECT  39.984 102.467 41.304 102.901 ;
     RECT  31.968 102.755 32.904 102.995 ;
     RECT  66.288 102.899 68.664 102.995 ;
     RECT  36.24 102.659 38.712 103.043 ;
     RECT  68.64 102.995 68.664 103.043 ;
     RECT  66.288 102.995 67.512 103.091 ;
     RECT  32.1 102.995 32.904 103.235 ;
     RECT  66.72 103.091 67.512 103.235 ;
     RECT  36.24 103.043 38.328 103.283 ;
     RECT  42.624 102.899 65.112 103.331 ;
     RECT  2.4 2.151 2.712 103.419 ;
     RECT  5.1 2.151 5.412 103.419 ;
     RECT  7.8 2.151 8.112 103.419 ;
     RECT  10.5 2.151 10.812 103.419 ;
     RECT  13.2 2.151 13.512 103.419 ;
     RECT  15.9 2.151 16.212 103.419 ;
     RECT  18.6 2.151 18.912 103.419 ;
     RECT  21.3 2.151 21.612 103.419 ;
     RECT  24 54.083 24.312 103.419 ;
     RECT  26.7 92.723 27.012 103.419 ;
     RECT  29.4 99.731 29.712 103.419 ;
     RECT  32.1 103.235 32.412 103.419 ;
     RECT  34.8 102.659 35.112 103.419 ;
     RECT  42.9 103.331 65.112 103.419 ;
     RECT  67.2 103.235 67.512 103.419 ;
     RECT  69.9 100.931 70.212 103.419 ;
     RECT  72.6 98.915 72.912 103.419 ;
     RECT  75.3 2.151 75.612 103.419 ;
     RECT  78 28.787 78.312 103.419 ;
     RECT  80.7 2.151 81.012 103.419 ;
     RECT  83.4 2.151 83.712 103.419 ;
     RECT  86.1 37.427 86.412 103.419 ;
     RECT  88.8 2.151 89.112 103.419 ;
     RECT  91.5 2.151 91.812 103.419 ;
     RECT  94.2 101.219 94.512 103.419 ;
     RECT  96.9 2.151 97.212 103.419 ;
     RECT  99.6 2.151 99.912 103.419 ;
     RECT  2.592 103.419 2.712 103.433 ;
     RECT  5.292 103.419 5.412 103.433 ;
     RECT  7.992 103.419 8.112 103.433 ;
     RECT  10.692 103.419 10.812 103.433 ;
     RECT  13.392 103.419 13.512 103.433 ;
     RECT  16.092 103.419 16.212 103.433 ;
     RECT  18.792 103.419 18.912 103.433 ;
     RECT  21.492 103.419 21.612 103.433 ;
     RECT  24.192 103.419 24.312 103.433 ;
     RECT  26.892 103.419 27.012 103.433 ;
     RECT  29.592 103.419 29.712 103.433 ;
     RECT  32.292 103.419 32.412 103.433 ;
     RECT  34.992 103.419 35.112 103.433 ;
     RECT  36.24 103.283 37.812 103.433 ;
     RECT  39.984 102.901 41.352 103.433 ;
     RECT  43.092 103.419 65.112 103.433 ;
     RECT  67.392 103.419 67.512 103.433 ;
     RECT  70.092 103.419 70.212 103.433 ;
     RECT  72.792 103.419 72.912 103.433 ;
     RECT  75.492 103.419 75.612 103.433 ;
     RECT  78.192 103.419 78.312 103.433 ;
     RECT  80.892 103.419 81.012 103.433 ;
     RECT  83.592 103.419 83.712 103.433 ;
     RECT  86.292 103.419 86.412 103.433 ;
     RECT  88.992 103.419 89.112 103.433 ;
     RECT  91.692 103.419 91.812 103.433 ;
     RECT  94.392 103.419 94.512 103.433 ;
     RECT  97.092 103.419 97.212 103.433 ;
     RECT  99.792 103.419 99.912 103.433 ;
     RECT  39.984 103.433 40.008 103.523 ;
     RECT  41.04 103.433 41.352 103.523 ;
     RECT  43.296 103.433 65.112 103.523 ;
     RECT  36.24 103.433 36.936 103.763 ;
     RECT  43.584 103.523 65.112 103.859 ;
     RECT  36.912 103.763 36.936 104.867 ;
     RECT  43.584 103.859 64.968 105.397 ;
     RECT  41.04 103.523 41.064 105.589 ;
     RECT  43.44 105.397 64.968 105.683 ;
     RECT  43.536 105.683 64.968 105.744 ;
     RECT  41.04 105.589 41.544 105.779 ;
  END
END qfd_rlyh0_600_NE_104x106
END LIBRARY
